# iorx71m register map
Registers from a debugger description file.
Registers are 8-bit, access not given, no defined reset value unless marked. A register's access mark holds for its fields unless they carry their own. Addresses are absolute; registers are grouped by the start of their names; lines under a group give offsets from that group; [hi:lo] are bit positions; {n}, {i} and the like mark numbered series; 'fields as' and 'values as' point back to an identical list; <NAME> marks a mode.

## SFR (part 1 of 4)
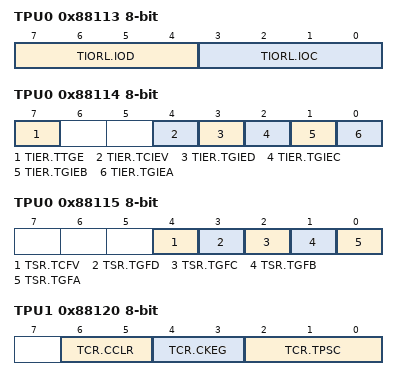
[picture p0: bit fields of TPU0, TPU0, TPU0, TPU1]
0x88113 TPU0
  [7:4] TIORL.IOD, [3:0] TIORL.IOC
0x88114 TPU0
  [7] TIER.TTGE, [4] TIER.TCIEV, [3] TIER.TGIED, [2] TIER.TGIEC, [1] TIER.TGIEB, [0] TIER.TGIEA
0x88115 TPU0
  [4] TSR.TCFV, [3] TSR.TGFD, [2] TSR.TGFC, [1] TSR.TGFB, [0] TSR.TGFA
0x88120 TPU1
  [6:5] TCR.CCLR, [4:3] TCR.CKEG, [2:0] TCR.TPSC
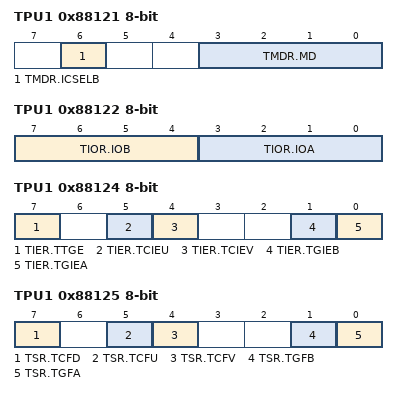
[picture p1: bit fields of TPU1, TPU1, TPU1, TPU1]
0x88121 TPU1
  [6] TMDR.ICSELB, [3:0] TMDR.MD
0x88122 TPU1
  [7:4] TIOR.IOB, [3:0] TIOR.IOA
0x88124 TPU1
  [7] TIER.TTGE, [5] TIER.TCIEU, [4] TIER.TCIEV, [1] TIER.TGIEB, [0] TIER.TGIEA
0x88125 TPU1
  [7] TSR.TCFD, [5] TSR.TCFU, [4] TSR.TCFV, [1] TSR.TGFB, [0] TSR.TGFA
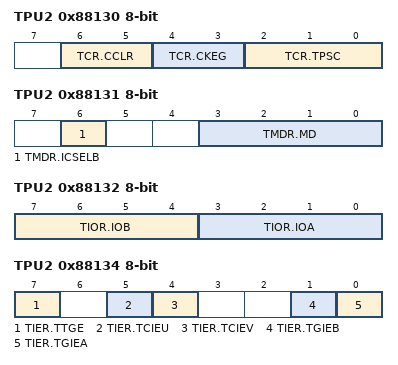
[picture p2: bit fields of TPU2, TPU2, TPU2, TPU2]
0x88130 TPU2
  [6:5] TCR.CCLR, [4:3] TCR.CKEG, [2:0] TCR.TPSC
0x88131 TPU2
  [6] TMDR.ICSELB, [3:0] TMDR.MD
0x88132 TPU2
  [7:4] TIOR.IOB, [3:0] TIOR.IOA
0x88134 TPU2
  [7] TIER.TTGE, [5] TIER.TCIEU, [4] TIER.TCIEV, [1] TIER.TGIEB, [0] TIER.TGIEA
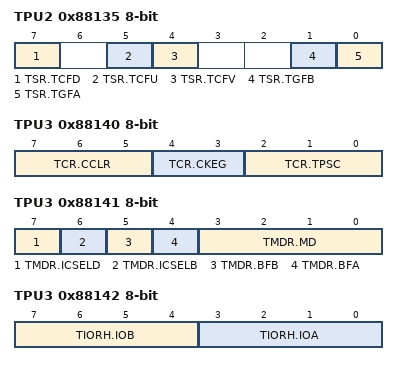
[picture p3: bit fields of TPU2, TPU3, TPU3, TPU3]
0x88135 TPU2
  [7] TSR.TCFD, [5] TSR.TCFU, [4] TSR.TCFV, [1] TSR.TGFB, [0] TSR.TGFA
0x88140 TPU3
  [7:5] TCR.CCLR, [4:3] TCR.CKEG, [2:0] TCR.TPSC
0x88141 TPU3
  [7] TMDR.ICSELD, [6] TMDR.ICSELB, [5] TMDR.BFB, [4] TMDR.BFA, [3:0] TMDR.MD
0x88142 TPU3
  [7:4] TIORH.IOB, [3:0] TIORH.IOA
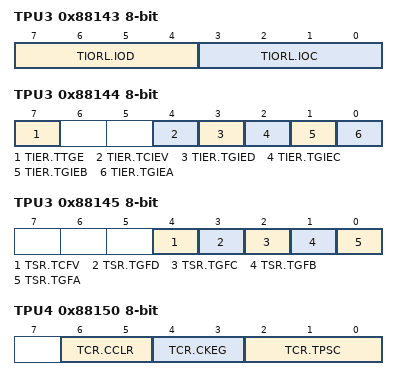
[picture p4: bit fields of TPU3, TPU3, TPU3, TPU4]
0x88143 TPU3
  [7:4] TIORL.IOD, [3:0] TIORL.IOC
0x88144 TPU3
  [7] TIER.TTGE, [4] TIER.TCIEV, [3] TIER.TGIED, [2] TIER.TGIEC, [1] TIER.TGIEB, [0] TIER.TGIEA
0x88145 TPU3
  [4] TSR.TCFV, [3] TSR.TGFD, [2] TSR.TGFC, [1] TSR.TGFB, [0] TSR.TGFA
0x88150 TPU4
  [6:5] TCR.CCLR, [4:3] TCR.CKEG, [2:0] TCR.TPSC
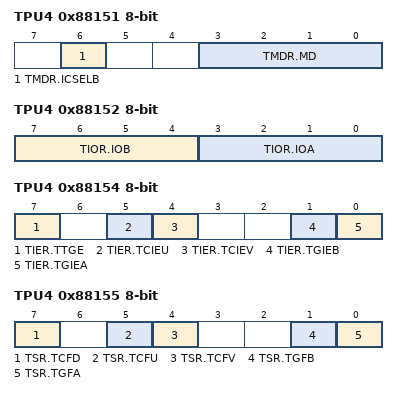
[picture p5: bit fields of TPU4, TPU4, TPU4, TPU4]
0x88151 TPU4
  [6] TMDR.ICSELB, [3:0] TMDR.MD
0x88152 TPU4
  [7:4] TIOR.IOB, [3:0] TIOR.IOA
0x88154 TPU4
  [7] TIER.TTGE, [5] TIER.TCIEU, [4] TIER.TCIEV, [1] TIER.TGIEB, [0] TIER.TGIEA
0x88155 TPU4
  [7] TSR.TCFD, [5] TSR.TCFU, [4] TSR.TCFV, [1] TSR.TGFB, [0] TSR.TGFA
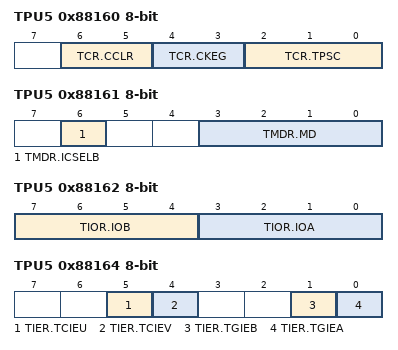
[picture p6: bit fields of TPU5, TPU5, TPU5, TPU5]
0x88160 TPU5
  [6:5] TCR.CCLR, [4:3] TCR.CKEG, [2:0] TCR.TPSC
0x88161 TPU5
  [6] TMDR.ICSELB, [3:0] TMDR.MD
0x88162 TPU5
  [7:4] TIOR.IOB, [3:0] TIOR.IOA
0x88164 TPU5
  [5] TIER.TCIEU, [4] TIER.TCIEV, [1] TIER.TGIEB, [0] TIER.TGIEA
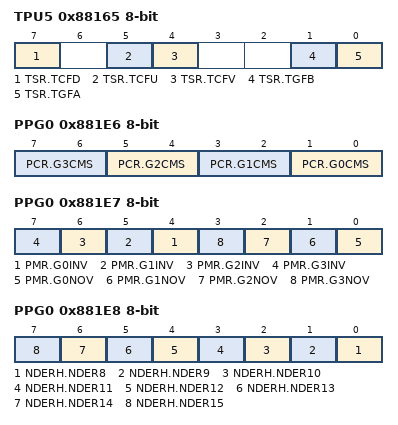
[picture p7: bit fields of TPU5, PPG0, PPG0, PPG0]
0x88165 TPU5
  [7] TSR.TCFD, [5] TSR.TCFU, [4] TSR.TCFV, [1] TSR.TGFB, [0] TSR.TGFA
0x881E6 PPG0
  [2n+1:2n] PCR.G{n}CMS (n=0..3)
0x881E7 PPG0
  [n+4] PMR.G{n}INV (n=0..3), [n] PMR.G{n}NOV (n=0..3)
0x881E8 PPG0
  [n-8] NDERH.NDER{n} (n=8..15)
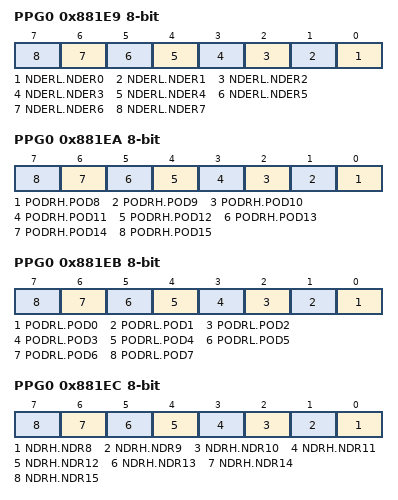
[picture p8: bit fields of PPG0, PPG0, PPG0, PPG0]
0x881E9 PPG0
  [n] NDERL.NDER{n} (n=0..7)
0x881EA PPG0
  [n-8] PODRH.POD{n} (n=8..15)
0x881EB PPG0
  [n] PODRL.POD{n} (n=0..7)
0x881EC PPG0
  [n-8] NDRH.NDR{n} (n=8..15)
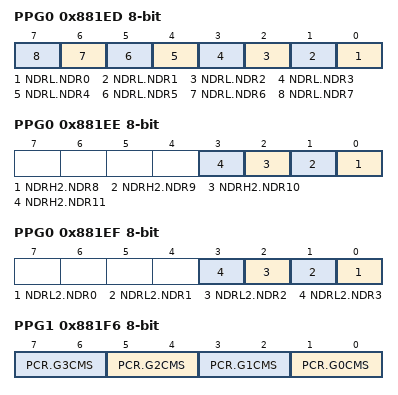
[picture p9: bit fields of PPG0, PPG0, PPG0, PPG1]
0x881ED PPG0
  [n] NDRL.NDR{n} (n=0..7)
0x881EE PPG0
  [n-8] NDRH2.NDR{n} (n=8..11)
0x881EF PPG0
  [n] NDRL2.NDR{n} (n=0..3)
0x881F0 PPG1
  [0] PTRSLR.PTRSL
0x881F6 PPG1
  [2n+1:2n] PCR.G{n}CMS (n=0..3)
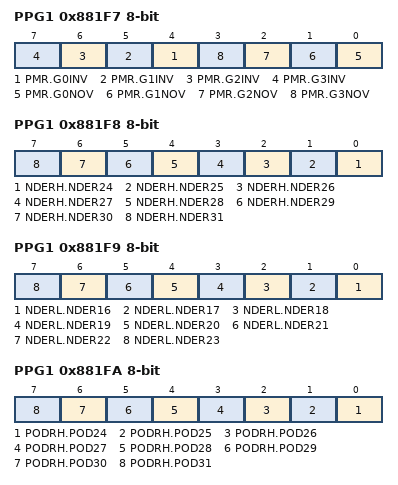
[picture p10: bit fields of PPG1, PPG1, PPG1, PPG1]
0x881F7 PPG1
  [n+4] PMR.G{n}INV (n=0..3), [n] PMR.G{n}NOV (n=0..3)
0x881F8 PPG1
  [n-24] NDERH.NDER{n} (n=24..31)
0x881F9 PPG1
  [n-16] NDERL.NDER{n} (n=16..23)
0x881FA PPG1
  [n-24] PODRH.POD{n} (n=24..31)
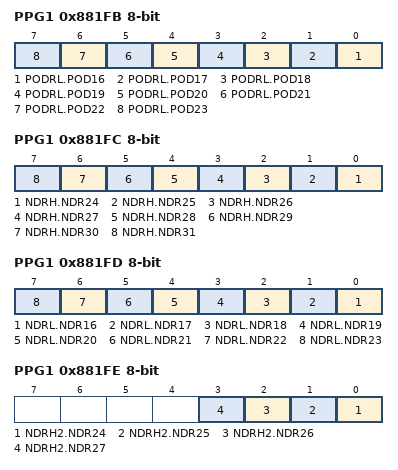
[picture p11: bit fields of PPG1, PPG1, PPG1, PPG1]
0x881FB PPG1
  [n-16] PODRL.POD{n} (n=16..23)
0x881FC PPG1
  [n-24] NDRH.NDR{n} (n=24..31)
0x881FD PPG1
  [n-16] NDRL.NDR{n} (n=16..23)
0x881FE PPG1
  [n-24] NDRH2.NDR{n} (n=24..27)
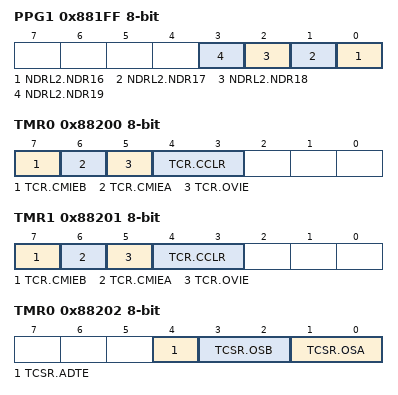
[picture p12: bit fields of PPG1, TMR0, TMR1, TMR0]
0x881FF PPG1
  [n-16] NDRL2.NDR{n} (n=16..19)
0x88200 TMR0
  [7] TCR.CMIEB, [6] TCR.CMIEA, [5] TCR.OVIE, [4:3] TCR.CCLR
0x88201 TMR1
  [7] TCR.CMIEB, [6] TCR.CMIEA, [5] TCR.OVIE, [4:3] TCR.CCLR
0x88202 TMR0
  [4] TCSR.ADTE, [3:2] TCSR.OSB, [1:0] TCSR.OSA
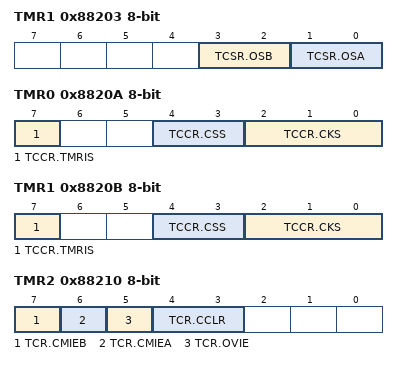
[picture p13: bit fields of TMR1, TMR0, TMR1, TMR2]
0x88203 TMR1
  [3:2] TCSR.OSB, [1:0] TCSR.OSA
0x8820A TMR0
  [7] TCCR.TMRIS, [4:3] TCCR.CSS, [2:0] TCCR.CKS
0x8820B TMR1
  [7] TCCR.TMRIS, [4:3] TCCR.CSS, [2:0] TCCR.CKS
0x8820C TMR0
  [0] TCSTR.TCS
0x8820D TMR1
  [0] TCSTR.TCS
0x88210 TMR2
  [7] TCR.CMIEB, [6] TCR.CMIEA, [5] TCR.OVIE, [4:3] TCR.CCLR
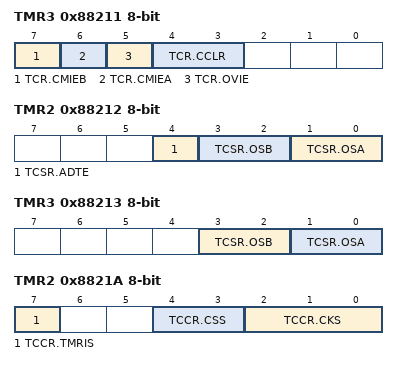
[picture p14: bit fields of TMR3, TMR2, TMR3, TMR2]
0x88211 TMR3
  [7] TCR.CMIEB, [6] TCR.CMIEA, [5] TCR.OVIE, [4:3] TCR.CCLR
0x88212 TMR2
  [4] TCSR.ADTE, [3:2] TCSR.OSB, [1:0] TCSR.OSA
0x88213 TMR3
  [3:2] TCSR.OSB, [1:0] TCSR.OSA
0x8821A TMR2
  [7] TCCR.TMRIS, [4:3] TCCR.CSS, [2:0] TCCR.CKS
0x8821B TMR3
  [7] TCCR.TMRIS, [4:3] TCCR.CSS, [2:0] TCCR.CKS
0x8821C TMR2
  [0] TCSTR.TCS
0x8821D TMR3
  [0] TCSTR.TCS
0x88280 CRC
  [7] CRCCR.DORCLR, [2] CRCCR.LMS, [1:0] CRCCR.GPS
0x88300 RIIC0
  [7] ICCR1.ICE, [6] ICCR1.IICRST, [5] ICCR1.CLO, [4] ICCR1.SOWP, [3] ICCR1.SCLO, [2] ICCR1.SDAO, [1] ICCR1.SCLI, [0] ICCR1.SDAI
0x88301 RIIC0
  [7] ICCR2.BBSY, [6] ICCR2.MST, [5] ICCR2.TRS, [3] ICCR2.SP, [2] ICCR2.RS, [1] ICCR2.ST
0x88302 RIIC0
  [7] ICMR1.MTWP, [6:4] ICMR1.CKS, [3] ICMR1.BCWP, [2:0] ICMR1.BC
0x88303 RIIC0
  [7] ICMR2.DLCS, [6:4] ICMR2.SDDL, [2] ICMR2.TMOH, [1] ICMR2.TMOL, [0] ICMR2.TMOS
0x88304 RIIC0
  [7] ICMR3.SMBS, [6] ICMR3.WAIT, [5] ICMR3.RDRFS, [4] ICMR3.ACKWP, [3] ICMR3.ACKBT, [2] ICMR3.ACKBR, [1:0] ICMR3.NF
0x88305 RIIC0
  [7] ICFER.FMPE, [6] ICFER.SCLE, [5] ICFER.NFE, [4] ICFER.NACKE, [3] ICFER.SALE, [2] ICFER.NALE, [1] ICFER.MALE, [0] ICFER.TMOE
0x88306 RIIC0
  [7] ICSER.HOAE, [5] ICSER.DIDE, [3] ICSER.GCAE, [2] ICSER.SAR2E, [1] ICSER.SAR1E, [0] ICSER.SAR0E
0x88307 RIIC0
  [7] ICIER.TIE, [6] ICIER.TEIE, [5] ICIER.RIE, [4] ICIER.NAKIE, [3] ICIER.SPIE, [2] ICIER.STIE, [1] ICIER.ALIE, [0] ICIER.TMOIE
0x88308 RIIC0
  [7] ICSR1.HOA, [5] ICSR1.DID, [3] ICSR1.GCA, [2] ICSR1.AAS2, [1] ICSR1.AAS1, [0] ICSR1.AAS0
0x88309 RIIC0
  [7] ICSR2.TDRE, [6] ICSR2.TEND, [5] ICSR2.RDRF, [4] ICSR2.NACKF, [3] ICSR2.STOP, [2] ICSR2.START, [1] ICSR2.AL, [0] ICSR2.TMOF
0x8830A RIIC0
  [7:1] SARL0.SVA, [0] SARL0.SVA0
0x8830B RIIC0
  [2:1] SARU0.SVA, [0] SARU0.FS
0x8830C RIIC0
  [7:1] SARL1.SVA, [0] SARL1.SVA0
0x8830D RIIC0
  [2:1] SARU1.SVA, [0] SARU1.FS
0x8830E RIIC0
  [7:1] SARL2.SVA, [0] SARL2.SVA0
0x8830F RIIC0
  [2:1] SARU2.SVA, [0] SARU2.FS
0x88310 RIIC0
  [4:0] ICBRL.BRL
0x88311 RIIC0
  [4:0] ICBRH.BRH
0x88340 RIIC2
  fields as RIIC0
0x88341 RIIC2
  [7] ICCR2.BBSY, [6] ICCR2.MST, [5] ICCR2.TRS, [3] ICCR2.SP, [2] ICCR2.RS, [1] ICCR2.ST
0x88342 RIIC2
  [7] ICMR1.MTWP, [6:4] ICMR1.CKS, [3] ICMR1.BCWP, [2:0] ICMR1.BC
0x88343 RIIC2
  [7] ICMR2.DLCS, [6:4] ICMR2.SDDL, [2] ICMR2.TMOH, [1] ICMR2.TMOL, [0] ICMR2.TMOS
0x88344 RIIC2
  [7] ICMR3.SMBS, [6] ICMR3.WAIT, [5] ICMR3.RDRFS, [4] ICMR3.ACKWP, [3] ICMR3.ACKBT, [2] ICMR3.ACKBR, [1:0] ICMR3.NF
0x88345 RIIC2
  [7] ICFER.FMPE, [6] ICFER.SCLE, [5] ICFER.NFE, [4] ICFER.NACKE, [3] ICFER.SALE, [2] ICFER.NALE, [1] ICFER.MALE, [0] ICFER.TMOE
0x88346 RIIC2
  [7] ICSER.HOAE, [5] ICSER.DIDE, [3] ICSER.GCAE, [2] ICSER.SAR2E, [1] ICSER.SAR1E, [0] ICSER.SAR0E
0x88347 RIIC2
  [7] ICIER.TIE, [6] ICIER.TEIE, [5] ICIER.RIE, [4] ICIER.NAKIE, [3] ICIER.SPIE, [2] ICIER.STIE, [1] ICIER.ALIE, [0] ICIER.TMOIE
0x88348 RIIC2
  [7] ICSR1.HOA, [5] ICSR1.DID, [3] ICSR1.GCA, [2] ICSR1.AAS2, [1] ICSR1.AAS1, [0] ICSR1.AAS0
0x88349 RIIC2
  [7] ICSR2.TDRE, [6] ICSR2.TEND, [5] ICSR2.RDRF, [4] ICSR2.NACKF, [3] ICSR2.STOP, [2] ICSR2.START, [1] ICSR2.AL, [0] ICSR2.TMOF
0x8834A RIIC2
  [7:1] SARL0.SVA, [0] SARL0.SVA0
0x8834B RIIC2
  [2:1] SARU0.SVA, [0] SARU0.FS
0x8834C RIIC2
  [7:1] SARL1.SVA, [0] SARL1.SVA0
0x8834D RIIC2
  [2:1] SARU1.SVA, [0] SARU1.FS
0x8834E RIIC2
  [7:1] SARL2.SVA, [0] SARL2.SVA0
0x8834F RIIC2
  [2:1] SARU2.SVA, [0] SARU2.FS
0x88350 RIIC2
  [4:0] ICBRL.BRL
0x88351 RIIC2
  [4:0] ICBRH.BRH
0x88500 MMCIF 32-bit
  [30] CECMDSET.BOOT, [29:24] CECMDSET.CMD, [23:22] CECMDSET.RTYP, [21] CECMDSET.RBSY, [19] CECMDSET.WDAT, [18] CECMDSET.DWEN, [17] CECMDSET.CMLTE, [16] CECMDSET.CMD12EN, [15:14] CECMDSET.RIDXC, [13:12] CECMDSET.RCRC7C, [10] CECMDSET.CRC16C, [9] CECMDSET.BOOTACK, [8] CECMDSET.CRCSTE, [7] CECMDSET.TBIT, [6] CECMDSET.OPDM, [3] CECMDSET.SBIT, [1:0] CECMDSET.DATW
0x88508 MMCIF 32-bit
  [31:0] CEARG.ARG
0x8850C MMCIF 32-bit
  [31:0] CEARGCMD12.C12ARG
0x88510 MMCIF 32-bit
  [0] CECMDCTRL.BREAK
0x88514 MMCIF 32-bit
  [31:16] CEBLOCKSET.BLKCNT, [15:0] CEBLOCKSET.BLKSIZ
0x88518 MMCIF 32-bit
  [31] CECLKCTRL.MMCBUSBSY, [24] CECLKCTRL.CLKEN, [19:16] CECLKCTRL.CLKDIV, [13:12] CECLKCTRL.SRSPTO, [11:8] CECLKCTRL.SRBSYTO, [7:4] CECLKCTRL.SRWDTO
0x8851C MMCIF 32-bit
  [26] CEBUFACC.DMATYP, [25] CEBUFACC.DMAWEN, [24] CEBUFACC.DMAREN, [16] CEBUFACC.ATYP
0x88530 MMCIF 32-bit
  [31:0] CERESPCMD12.RSP12
0x88534 MMCIF 32-bit
  [31:0] CEDATA.DATA
0x8853C MMCIF 32-bit
  [31:28] CEBOOT.SBTCLKDIV, [27:24] CEBOOT.SBTACKTO, [23:20] CEBOOT.SFSTBTDATTO, [19:16] CEBOOT.SBTDATTO
0x88540 MMCIF 32-bit
  [26] CEINT.CMD12DRE, [25] CEINT.CMD12RBE, [24] CEINT.CMD12CRE, [23] CEINT.DTRANE, [22] CEINT.BUFRE, [21] CEINT.BUFWEN, [20] CEINT.BUFREN, [17] CEINT.RBSYE, [16] CEINT.CRSPE, [15] CEINT.CMDVIO, [14] CEINT.BUFVIO, [11] CEINT.WDATERR, [10] CEINT.RDATERR, [9] CEINT.RIDXERR, [8] CEINT.RSPERR, [4] CEINT.CRCSTO, [3] CEINT.WDATTO, [2] CEINT.RDATTO, [1] CEINT.RBSYTO, [0] CEINT.RSPTO
0x88544 MMCIF 32-bit
  [26] CEINTEN.MCMD12DRE, [25] CEINTEN.MCMD12RBE, [24] CEINTEN.MCMD12CRE, [23] CEINTEN.MDTRANE, [22] CEINTEN.MBUFRE, [21] CEINTEN.MBUFWEN, [20] CEINTEN.MBUFREN, [17] CEINTEN.MRBSYE, [16] CEINTEN.MCRSPE, [15] CEINTEN.MCMDVIO, [14] CEINTEN.MBUFVIO, [11] CEINTEN.MWDATERR, [10] CEINTEN.MRDATERR, [9] CEINTEN.MRIDXERR, [8] CEINTEN.MRSPERR, [4] CEINTEN.MCRCSTO, [3] CEINTEN.MWDATTO, [2] CEINTEN.MRDATTO, [1] CEINTEN.MRBSYTO, [0] CEINTEN.MRSPTO
0x88548 MMCIF 32-bit
  [31] CEHOSTSTS1.CMDSEQ, [30] CEHOSTSTS1.CMDSIG, [29:24] CEHOSTSTS1.RSPIDX, [23:16] CEHOSTSTS1.DATSIG, [15:0] CEHOSTSTS1.RCVBLK
0x8854C MMCIF 32-bit
  [31] CEHOSTSTS2.CRCSTE, [30] CEHOSTSTS2.CRC16E, [29] CEHOSTSTS2.AC12CRCE, [28] CEHOSTSTS2.RSPCRC7E, [27] CEHOSTSTS2.CRCSTEBE, [26] CEHOSTSTS2.RDATEBE, [25] CEHOSTSTS2.AC12REBE, [24] CEHOSTSTS2.RSPEBE, [23] CEHOSTSTS2.AC12IDXE, [22] CEHOSTSTS2.RSPIDXE, [21] CEHOSTSTS2.BTACKPATE, [20] CEHOSTSTS2.BTACKEBE, [18:16] CEHOSTSTS2.CRCST, [14] CEHOSTSTS2.STRDATTO, [13] CEHOSTSTS2.DATBSYTO, [12] CEHOSTSTS2.CRCSTTO, [11] CEHOSTSTS2.AC12BSYTO, [10] CEHOSTSTS2.RSPBSYTO, [9] CEHOSTSTS2.AC12RSPTO, [8] CEHOSTSTS2.STRSPTO, [7] CEHOSTSTS2.BTACKTO, [6] CEHOSTSTS2.FSTBTDATTO, [5] CEHOSTSTS2.BTDATTO
0x88570 MMCIF 32-bit
  [14] CEDETECT.CDSIG, [13] CEDETECT.CDRISE, [12] CEDETECT.CDFALL, [5] CEDETECT.MCDRISE, [4] CEDETECT.MCDFALL
0x88574 MMCIF 32-bit
  [21] CEADDMODE.RESNOUT, [19] CEADDMODE.CLKMAIN
0x8857C MMCIF 32-bit
  [31] CEVERSION.SWRST, [15:0] CEVERSION.VERSION
0x89000 S12AD 16-bit
  [15] ADCSR.ADST, [14:13] ADCSR.ADCS, [12] ADCSR.ADIE, [9] ADCSR.TRGE, [8] ADCSR.EXTRG, [7] ADCSR.DBLE, [6] ADCSR.GBADIE, [4:0] ADCSR.DBLANS
0x89004 S12AD 16-bit
  [15:0] ADANSA0.ANSA0
0x89008 S12AD 16-bit
  [15:0] ADADS0.ADS0
0x8900C S12AD
  [7] ADADC.AVEE, [1:0] ADADC.ADC
0x8900E S12AD 16-bit
  [15] ADCER.ADRFMT, [11] ADCER.DIAGM, [10] ADCER.DIAGLD, [9:8] ADCER.DIAGVAL, [5] ADCER.ACE, [2:1] ADCER.ADPRC
0x89010 S12AD 16-bit
  [13:8] ADSTRGR.TRSA, [5:0] ADSTRGR.TRSB
0x89014 S12AD 16-bit
  [15:0] ADANSB0.ANSB0
0x89018 S12AD 16-bit
  [13:2] ADDBLDR.AD
0x8901E S12AD 16-bit
  [15:14] ADRD.RIGHT.DIAGST, [15:4] ADRD.LEFT.AD, [11:0] ADRD.RIGHT.AD, [1:0] ADRD.LEFT.DIAGST
0x89066 S12AD 16-bit
  [10:8] ADSHCR.SHANS, [7:0] ADSHCR.SSTSH
0x8907A S12AD
  [4:0] ADDISCR.ADNDIS
0x8907C S12AD
  [0] ADSHMSR.SHMD
0x89080 S12AD 16-bit
  [15] ADGSPCR.GBRP, [1] ADGSPCR.GBRSCN, [0] ADGSPCR.PGS
0x89090 S12AD
  [7] ADCMPCR.CMPIE, [6] ADCMPCR.WCMPE
0x89094 S12AD 16-bit
  [15:0] ADCMPANSR0.CMPS0
0x89098 S12AD 16-bit
  [15:0] ADCMPLR0.CMPL0
0x890A0 S12AD 16-bit
  [15:0] ADCMPSR0.CMPF0
0x89100 S12AD1 16-bit
  fields as S12AD
0x89104 S12AD1 16-bit
  [15:0] ADANSA0.ANSA0
0x89106 S12AD1 16-bit
  [4:0] ADANSA1.ANSA1
0x89108 S12AD1 16-bit
  [15:0] ADADS0.ADS0
0x8910A S12AD1 16-bit
  [4:0] ADADS1.ADS1
0x8910C S12AD1
  [7] ADADC.AVEE, [1:0] ADADC.ADC
0x8910E S12AD1 16-bit
  [15] ADCER.ADRFMT, [11] ADCER.DIAGM, [10] ADCER.DIAGLD, [9:8] ADCER.DIAGVAL, [5] ADCER.ACE, [2:1] ADCER.ADPRC
0x89110 S12AD1 16-bit
  [13:8] ADSTRGR.TRSA, [5:0] ADSTRGR.TRSB
0x89112 S12AD1 16-bit
  [15] ADEXICR.EXOEN, [14:13] ADEXICR.EXSEL, [11] ADEXICR.OCSB, [10] ADEXICR.TSSB, [9] ADEXICR.OCSA, [8] ADEXICR.TSSA, [1] ADEXICR.OCSAD, [0] ADEXICR.TSSAD
0x89114 S12AD1 16-bit
  [15:0] ADANSB0.ANSB0
0x89116 S12AD1 16-bit
  [4:0] ADANSB1.ANSB1
0x8911E S12AD1 16-bit
  [15:14] ADRD.RIGHT.DIAGST, [15:4] ADRD.LEFT.AD, [11:0] ADRD.RIGHT.AD, [1:0] ADRD.LEFT.DIAGST
0x8917A S12AD1
  [4:0] ADDISCR.ADNDIS
0x89180 S12AD1 16-bit
  [15] ADGSPCR.GBRP, [1] ADGSPCR.GBRSCN, [0] ADGSPCR.PGS
0x89190 S12AD1
  [7] ADCMPCR.CMPIE, [6] ADCMPCR.WCMPE
0x89192 S12AD1
  [1] ADCMPANSER.CMPSOC, [0] ADCMPANSER.CMPSTS
0x89193 S12AD1
  [1] ADCMPLER.CMPLOC, [0] ADCMPLER.CMPLTS
0x89194 S12AD1 16-bit
  [15:0] ADCMPANSR0.CMPS0
0x89196 S12AD1 16-bit
  [4:0] ADCMPANSR1.CMPS1
0x89198 S12AD1 16-bit
  [15:0] ADCMPLR0.CMPL0
0x8919A S12AD1 16-bit
  [4:0] ADCMPLR1.CMPL1
0x891A0 S12AD1 16-bit
  [15:0] ADCMPSR0.CMPF0
0x891A2 S12AD1 16-bit
  [4:0] ADCMPSR1.CMPF1
0x891A4 S12AD1
  [1] ADCMPSER.CMPFOC, [0] ADCMPSER.CMPFTS
0x89E00 QSPI
  [7] SPCR.SPRIE, [6] SPCR.SPE, [5] SPCR.SPTIE, [3] SPCR.MSTR, [1] SPCR.SPSSLIE
0x89E01 QSPI
  [0] SSLP.SSLP
0x89E02 QSPI
  [5] SPPCR.MOIFE, [4] SPPCR.MOIFV, [2] SPPCR.IO3FV, [1] SPPCR.IO2FV, [0] SPPCR.SPLP
0x89E03 QSPI
  [7] SPSR.SPRFF, [6] SPSR.TREND, [5] SPSR.SPTEF, [4] SPSR.SPSSLF
0x89E08 QSPI
  [1:0] SPSCR.SPSC
0x89E09 QSPI
  [1:0] SPSSR.SPSS
0x89E0A QSPI
  [n] SPBR.SPBR{n} (n=0..7)
0x89E0B QSPI
  [7] SPDCR.TXDMY
0x89E0C QSPI
  [2:0] SPCKD.SCKDL
0x89E0D QSPI
  [2:0] SSLND.SLNDL
0x89E0E QSPI
  [2:0] SPND.SPNDL
0x89E10 QSPI 16-bit
  [15] SPCMD0.SCKDEN, [14] SPCMD0.SLNDEN, [13] SPCMD0.SPNDEN, [12] SPCMD0.LSBF, [11:8] SPCMD0.SPB, [7] SPCMD0.SSLKP, [6:5] SPCMD0.SPIMOD, [4] SPCMD0.SPRW, [3:2] SPCMD0.BRDV, [1] SPCMD0.CPOL, [0] SPCMD0.CPHA
0x89E12 QSPI 16-bit
  [15] SPCMD1.SCKDEN, [14] SPCMD1.SLNDEN, [13] SPCMD1.SPNDEN, [12] SPCMD1.LSBF, [11:8] SPCMD1.SPB, [7] SPCMD1.SSLKP, [6:5] SPCMD1.SPIMOD, [4] SPCMD1.SPRW, [3:2] SPCMD1.BRDV, [1] SPCMD1.CPOL, [0] SPCMD1.CPHA
0x89E14 QSPI 16-bit
  [15] SPCMD2.SCKDEN, [14] SPCMD2.SLNDEN, [13] SPCMD2.SPNDEN, [12] SPCMD2.LSBF, [11:8] SPCMD2.SPB, [7] SPCMD2.SSLKP, [6:5] SPCMD2.SPIMOD, [4] SPCMD2.SPRW, [3:2] SPCMD2.BRDV, [1] SPCMD2.CPOL, [0] SPCMD2.CPHA
0x89E16 QSPI 16-bit
  [15] SPCMD3.SCKDEN, [14] SPCMD3.SLNDEN, [13] SPCMD3.SPNDEN, [12] SPCMD3.LSBF, [11:8] SPCMD3.SPB, [7] SPCMD3.SSLKP, [6:5] SPCMD3.SPIMOD, [4] SPCMD3.SPRW, [3:2] SPCMD3.BRDV, [1] SPCMD3.CPOL, [0] SPCMD3.CPHA
0x89E18 QSPI
  [7] SPBFCR.TXRST, [6] SPBFCR.RXRST, [5:4] SPBFCR.TXTRG, [3] SPBFCR.TXTRGEX, [2:0] SPBFCR.RXTRG
0x89E1A QSPI 16-bit
  [13:8] SPBDCR.TXBC, [5:0] SPBDCR.RXBC
{0x8A000+0x20*i} SCI{i} (i=0..7)
  [7] SMR.CM, [6] SMR.CHR, [5] SMR.PE, [4] SMR.PM, [3] SMR.STOP, [2] SMR.MP, [1:0] SMR.CKS
{0x8A000+0x20*i} SMCI{i} (i=0..7)
  [7] SMR.GM, [6] SMR.BLK, [5] SMR.PE, [4] SMR.PM, [3:2] SMR.BCP, [1:0] SMR.CKS
{0x8A002+0x20*i} SCI{i} (i=0..7)
  [7] SCR.TIE, [6] SCR.RIE, [5] SCR.TE, [4] SCR.RE, [3] SCR.MPIE, [2] SCR.TEIE, [1:0] SCR.CKE
{0x8A002+0x20*i} SMCI{i} (i=0..7)
  [7] SCR.TIE, [6] SCR.RIE, [5] SCR.TE, [4] SCR.RE, [3] SCR.MPIE, [2] SCR.TEIE, [1:0] SCR.CKE
{0x8A004+0x20*i} SCI{i} (i=0..7)
  [7] SSR.TDRE, [6] SSR.RDRF, [5] SSR.ORER, [4] SSR.FER, [3] SSR.PER, [2] SSR.TEND, [1] SSR.MPB, [0] SSR.MPBT
{0x8A004+0x20*i} SMCI{i} (i=0..7)
  [7] SSR.TDRE, [6] SSR.RDRF, [5] SSR.ORER, [4] SSR.ERS, [3] SSR.PER, [2] SSR.TEND, [1] SSR.MPB, [0] SSR.MPBT
{0x8A006+0x20*i} SCI{i} (i=0..7)
  [7] SCMR.BCP2, [4] SCMR.CHR1, [3] SCMR.SDIR, [2] SCMR.SINV, [0] SCMR.SMIF
{0x8A006+0x20*i} SMCI{i} (i=0..7)
  [7] SCMR.BCP2, [4] SCMR.CHR1, [3] SCMR.SDIR, [2] SCMR.SINV, [0] SCMR.SMIF
{0x8A007+0x20*i} SCI{i} (i=0..7)
  [7] SEMR.RXDESEL, [6] SEMR.BGDM, [5] SEMR.NFEN, [4] SEMR.ABCS, [2] SEMR.BRME, [0] SEMR.ACS0
{0x8A008+0x20*i} SCI{i} (i=0..7)
  [2:0] SNFR.NFCS
{0x8A009+0x20*i} SCI{i} (i=0..7)
  [7:3] SIMR1.IICDL, [0] SIMR1.IICM
{0x8A00A+0x20*i} SCI{i} (i=0..7)
  [5] SIMR2.IICACKT, [1] SIMR2.IICCSC, [0] SIMR2.IICINTM
{0x8A00B+0x20*i} SCI{i} (i=0..7)
  [7:6] SIMR3.IICSCLS, [5:4] SIMR3.IICSDAS, [3] SIMR3.IICSTIF, [2] SIMR3.IICSTPREQ, [1] SIMR3.IICRSTAREQ, [0] SIMR3.IICSTAREQ
{0x8A00C+0x20*i} SCI{i} (i=0..7)
  [0] SISR.IICACKR
{0x8A00D+0x20*i} SCI{i} (i=0..7)
  [7] SPMR.CKPH, [6] SPMR.CKPOL, [4] SPMR.MFF, [2] SPMR.MSS, [1] SPMR.CTSE, [0] SPMR.SSE
0x8A500 SSI0 32-bit
  [30] SSICR.CKS, [29] SSICR.TUIEN, [28] SSICR.TOIEN, [27] SSICR.RUIEN, [26] SSICR.ROIEN, [25] SSICR.IIEN, [23:22] SSICR.CHNL, [21:19] SSICR.DWL, [18:16] SSICR.SWL, [15] SSICR.SCKD, [14] SSICR.SWSD, [13] SSICR.SCKP, [12] SSICR.SWSP, [11] SSICR.SPDP, [10] SSICR.SDTA, [9] SSICR.PDTA, [8] SSICR.DEL, [7:4] SSICR.CKDV, [3] SSICR.MUEN, [1] SSICR.TEN, [0] SSICR.REN
0x8A504 SSI0 32-bit
  [29] SSISR.TUIRQ, [28] SSISR.TOIRQ, [27] SSISR.RUIRQ, [26] SSISR.ROIRQ, [25] SSISR.IIRQ, [6:5] SSISR.TCHNO, [4] SSISR.TSWNO, [3:2] SSISR.RCHNO, [1] SSISR.RSWNO, [0] SSISR.IDST
0x8A510 SSI0 32-bit
  [31] SSIFCR.AUCKE, [16] SSIFCR.SSIRST, [7:6] SSIFCR.TTRG, [5:4] SSIFCR.RTRG, [3] SSIFCR.TIE, [2] SSIFCR.RIE, [1] SSIFCR.TFRST, [0] SSIFCR.RFRST
0x8A514 SSI0 32-bit
  [27:24] SSIFSR.TDC, [16] SSIFSR.TDE, [11:8] SSIFSR.RDC, [0] SSIFSR.RDF
0x8A520 SSI0 32-bit
  [8] SSITDMR.CONT
0x8A540 SSI1 32-bit
  fields as SSI0
0x8A544 SSI1 32-bit
  [29] SSISR.TUIRQ, [28] SSISR.TOIRQ, [27] SSISR.RUIRQ, [26] SSISR.ROIRQ, [25] SSISR.IIRQ, [6:5] SSISR.TCHNO, [4] SSISR.TSWNO, [3:2] SSISR.RCHNO, [1] SSISR.RSWNO, [0] SSISR.IDST
0x8A550 SSI1 32-bit
  [31] SSIFCR.AUCKE, [16] SSIFCR.SSIRST, [7:6] SSIFCR.TTRG, [5:4] SSIFCR.RTRG, [3] SSIFCR.TIE, [2] SSIFCR.RIE, [1] SSIFCR.TFRST, [0] SSIFCR.RFRST
0x8A554 SSI1 32-bit
  [27:24] SSIFSR.TDC, [16] SSIFSR.TDE, [11:8] SSIFSR.RDC, [0] SSIFSR.RDF
0x8A560 SSI1 32-bit
  [8] SSITDMR.CONT
0x8AC00 SDHI 32-bit
  [15:14] SDCMD.CMD12AT, [13] SDCMD.TRSTP, [12] SDCMD.CMDRW, [11] SDCMD.CMDTP, [10:8] SDCMD.RSPTP, [7:6] SDCMD.ACMD, [5:0] SDCMD.CMDIDX
0x8AC10 SDHI 32-bit
  [8] SDSTOP.SDBLKCNTEN, [0] SDSTOP.STP
0x8AC38 SDHI 32-bit
  [10] SDSTS1.SDD3MON, [9] SDSTS1.SDD3IN, [8] SDSTS1.SDD3RM, [7] SDSTS1.SDWPMON, [5] SDSTS1.SDCDMON, [4] SDSTS1.SDCDIN, [3] SDSTS1.SDCDRM, [2] SDSTS1.ACEND, [0] SDSTS1.RSPEND
0x8AC3C SDHI 32-bit
  [15] SDSTS2.ILA, [14] SDSTS2.CBSY, [13] SDSTS2.SDCLKCREN, [9] SDSTS2.BWE, [8] SDSTS2.BRE, [7] SDSTS2.SDD0MON, [6] SDSTS2.RSPTO, [5] SDSTS2.ILR, [4] SDSTS2.ILW, [3] SDSTS2.DTO, [2] SDSTS2.ENDE, [1] SDSTS2.CRCE, [0] SDSTS2.CMDE
0x8AC40 SDHI 32-bit
  [9] SDIMSK1.SDD3INM, [8] SDIMSK1.SDD3RMM, [4] SDIMSK1.SDCDINM, [3] SDIMSK1.SDCDRMM, [2] SDIMSK1.ACENDM, [0] SDIMSK1.RSPENDM
0x8AC44 SDHI 32-bit
  [15] SDIMSK2.ILAM, [9] SDIMSK2.BWEM, [8] SDIMSK2.BREM, [6] SDIMSK2.RSPTOM, [5] SDIMSK2.ILRM, [4] SDIMSK2.ILWM, [3] SDIMSK2.DTTOM, [2] SDIMSK2.ENDEM, [1] SDIMSK2.CRCEM, [0] SDIMSK2.CMDEM
0x8AC48 SDHI 32-bit
  [9] SDCLKCR.CLKCTRLEN, [8] SDCLKCR.CLKEN, [7:0] SDCLKCR.CLKSEL
0x8AC4C SDHI 32-bit
  [9:0] SDSIZE.LEN
0x8AC50 SDHI 32-bit
  [15] SDOPT.WIDTH, [7:4] SDOPT.TOP, [3:0] SDOPT.CTOP
0x8AC58 SDHI 32-bit
  [14:12] SDERSTS1.CRCTK, [11] SDERSTS1.CRCTKE, [10] SDERSTS1.RDCRCE, [9] SDERSTS1.RSPCRCE1, [8] SDERSTS1.RSPCRCE0, [5] SDERSTS1.CRCLENE, [4] SDERSTS1.RDLENE, [3] SDERSTS1.RSPLENE1, [2] SDERSTS1.RSPLENE0, [1] SDERSTS1.CMDE1, [0] SDERSTS1.CMDE0
0x8AC5C SDHI 32-bit
  [6] SDERSTS2.CRCBSYTO, [5] SDERSTS2.CRCTO, [4] SDERSTS2.RDTO, [3] SDERSTS2.BSYTO1, [2] SDERSTS2.BSYTO0, [1] SDERSTS2.RSPTO1, [0] SDERSTS2.RSPTO0
0x8AC68 SDHI 32-bit
  [9] SDIOMD.C52PUB, [8] SDIOMD.IOABT, [2] SDIOMD.RWREQ, [0] SDIOMD.INTEN
0x8AC6C SDHI 32-bit
  [15] SDIOSTS.EXWT, [14] SDIOSTS.EXPUB52, [0] SDIOSTS.IOIRQ
0x8AC70 SDHI 32-bit
  [15] SDIOIMSK.EXWTM, [14] SDIOIMSK.EXPUB52M, [0] SDIOIMSK.IOIRQM
0x8ADB0 SDHI 32-bit
  [1] SDDMAEN.DMAEN
0x8ADC0 SDHI 32-bit
  [0] SDRST.SDRST
0x8ADC4 SDHI 32-bit
  [15] SDVER.CPRM, [14] SDVER.CLKRAT, [11:8] SDVER.IP2, [7:0] SDVER.IP1
0x8ADE0 SDHI 32-bit
  [7] SDSWAP.BRSWP, [6] SDSWAP.BWSWP
0x8B000 CAC
  [0] CACR0.CFME
0x8B001 CAC
  [7:6] CACR1.EDGES, [5:4] CACR1.TCSS, [3:1] CACR1.FMCS, [0] CACR1.CACREFE
0x8B002 CAC
  [7:6] CACR2.DFS, [5:4] CACR2.RCDS, [3:1] CACR2.RSCS, [0] CACR2.RPS
0x8B003 CAC
  [6] CAICR.OVFFCL, [5] CAICR.MENDFCL, [4] CAICR.FERRFCL, [2] CAICR.OVFIE, [1] CAICR.MENDIE, [0] CAICR.FERRIE
0x8B004 CAC
  [2] CASTR.OVFF, [1] CASTR.MENDF, [0] CASTR.FERRF
0x8B080 DOC
  [6] DOCR.DOPCFCL, [5] DOCR.DOPCF, [4] DOCR.DOPCIE, [2] DOCR.DCSEL, [1:0] DOCR.OMS
0x8B100 ELC
  [7] ELCR.ELCON
0x8B101 ELC
  [7:0] ELSR0.ELS
0x8B104 ELC
  [7:0] ELSR3.ELS
0x8B105 ELC
  [7:0] ELSR4.ELS
0x8B108 ELC
  [7:0] ELSR7.ELS
0x8B10B ELC
  [7:0] ELSR10.ELS
0x8B10C ELC
  [7:0] ELSR11.ELS
0x8B10D ELC
  [7:0] ELSR12.ELS
0x8B10E ELC
  [7:0] ELSR13.ELS
0x8B110 ELC
  [7:0] ELSR15.ELS
0x8B111 ELC
  [7:0] ELSR16.ELS
0x8B113 ELC
  [7:0] ELSR18.ELS
0x8B114 ELC
  [7:0] ELSR19.ELS
0x8B115 ELC
  [7:0] ELSR20.ELS
0x8B116 ELC
  [7:0] ELSR21.ELS
0x8B117 ELC
  [7:0] ELSR22.ELS
0x8B118 ELC
  [7:0] ELSR23.ELS
0x8B119 ELC
  [7:0] ELSR24.ELS
0x8B11A ELC
  [7:0] ELSR25.ELS
0x8B11B ELC
  [7:0] ELSR26.ELS
0x8B11C ELC
  [7:0] ELSR27.ELS
0x8B11D ELC
  [7:0] ELSR28.ELS
0x8B11F ELC
  [7:6] ELOPA.MTU3MD, [1:0] ELOPA.MTU0MD
0x8B120 ELC
  [1:0] ELOPB.MTU4MD
0x8B121 ELC
  [3:2] ELOPC.CMT1MD
0x8B122 ELC
  [2n+1:2n] ELOPD.TMR{n}MD (n=0..3)
0x8B123 ELC
  [n] PGR1.PGR{n} (n=0..7)
0x8B124 ELC
  [n] PGR2.PGR{n} (n=0..7)
0x8B125 ELC
  [6:4] PGC1.PGCO, [2] PGC1.PGCOVE, [1:0] PGC1.PGCI
0x8B126 ELC
  [6:4] PGC2.PGCO, [2] PGC2.PGCOVE, [1:0] PGC2.PGCI
0x8B127 ELC
  [n] PDBF1.PDBF{n} (n=0..7)
0x8B128 ELC
  [n] PDBF2.PDBF{n} (n=0..7)
0x8B129 ELC
  [6:5] PEL0.PSM, [4:3] PEL0.PSP, [2:0] PEL0.PSB
0x8B12A ELC
  [6:5] PEL1.PSM, [4:3] PEL1.PSP, [2:0] PEL1.PSB
0x8B12B ELC
  [6:5] PEL2.PSM, [4:3] PEL2.PSP, [2:0] PEL2.PSB
0x8B12C ELC
  [6:5] PEL3.PSM, [4:3] PEL3.PSP, [2:0] PEL3.PSB
0x8B12D ELC
  [7] ELSEGR.WI, [6] ELSEGR.WE, [0] ELSEGR.SEG
0x8B131 ELC
  [7:0] ELSR33.ELS
0x8B133 ELC
  [7:0] ELSR35.ELS
0x8B134 ELC
  [7:0] ELSR36.ELS
0x8B135 ELC
  [7:0] ELSR37.ELS
0x8B136 ELC
  [7:0] ELSR38.ELS
0x8B139 ELC
  [7:0] ELSR41.ELS
0x8B13A ELC
  [7:0] ELSR42.ELS
0x8B13B ELC
  [7:0] ELSR43.ELS
0x8B13C ELC
  [7:0] ELSR44.ELS
0x8B13D ELC
  [7:0] ELSR45.ELS
0x8B13F ELC
  [2n+1:2n] ELOPF.TPU{n}MD (n=0..3)
0x8B141 ELC
  [1:0] ELOPH.CMTW0MD
0x8B142 ELC
  [6:4] ELOPI.GPT1MD, [2:0] ELOPI.GPT0MD
0x8B143 ELC
  [6:4] ELOPJ.GPT3MD, [2:0] ELOPJ.GPT2MD
0x8B300 SCI12
  fields as SCI0
0x8B300 SMCI12
  fields as SMCI0
0x8B302 SCI12
  [7] SCR.TIE, [6] SCR.RIE, [5] SCR.TE, [4] SCR.RE, [3] SCR.MPIE, [2] SCR.TEIE, [1:0] SCR.CKE
0x8B302 SMCI12
  [7] SCR.TIE, [6] SCR.RIE, [5] SCR.TE, [4] SCR.RE, [3] SCR.MPIE, [2] SCR.TEIE, [1:0] SCR.CKE
0x8B304 SCI12
  [7] SSR.TDRE, [6] SSR.RDRF, [5] SSR.ORER, [4] SSR.FER, [3] SSR.PER, [2] SSR.TEND, [1] SSR.MPB, [0] SSR.MPBT
0x8B304 SMCI12
  [7] SSR.TDRE, [6] SSR.RDRF, [5] SSR.ORER, [4] SSR.ERS, [3] SSR.PER, [2] SSR.TEND, [1] SSR.MPB, [0] SSR.MPBT
0x8B306 SCI12
  [7] SCMR.BCP2, [4] SCMR.CHR1, [3] SCMR.SDIR, [2] SCMR.SINV, [0] SCMR.SMIF
0x8B306 SMCI12
  [7] SCMR.BCP2, [4] SCMR.CHR1, [3] SCMR.SDIR, [2] SCMR.SINV, [0] SCMR.SMIF
0x8B307 SCI12
  [7] SEMR.RXDESEL, [6] SEMR.BGDM, [5] SEMR.NFEN, [4] SEMR.ABCS, [2] SEMR.BRME, [0] SEMR.ACS0
0x8B308 SCI12
  [2:0] SNFR.NFCS
0x8B309 SCI12
  [7:3] SIMR1.IICDL, [0] SIMR1.IICM
0x8B30A SCI12
  [5] SIMR2.IICACKT, [1] SIMR2.IICCSC, [0] SIMR2.IICINTM
0x8B30B SCI12
  [7:6] SIMR3.IICSCLS, [5:4] SIMR3.IICSDAS, [3] SIMR3.IICSTIF, [2] SIMR3.IICSTPREQ, [1] SIMR3.IICRSTAREQ, [0] SIMR3.IICSTAREQ
0x8B30C SCI12
  [0] SISR.IICACKR
0x8B30D SCI12
  [7] SPMR.CKPH, [6] SPMR.CKPOL, [4] SPMR.MFF, [2] SPMR.MSS, [1] SPMR.CTSE, [0] SPMR.SSE
0x8B320 SCI12
  [0] ESMER.ESME
0x8B321 SCI12
  [3] CR0.BRME, [2] CR0.RXDSF, [1] CR0.SFSF
0x8B322 SCI12
  [7:5] CR1.PIBS, [4] CR1.PIBE, [3:2] CR1.CF1DS, [1] CR1.CF0RE, [0] CR1.BFE
0x8B323 SCI12
  [7:6] CR2.RTS, [5:4] CR2.BCCS, [2:0] CR2.DFCS
0x8B324 SCI12
  [0] CR3.SDST
0x8B325 SCI12
  [4] PCR.SHARPS, [1] PCR.RXDXPS, [0] PCR.TXDXPS
0x8B326 SCI12
  [5] ICR.AEDIE, [4] ICR.BCDIE, [3] ICR.PIBDIE, [2] ICR.CF1MIE, [1] ICR.CF0MIE, [0] ICR.BFDIE
0x8B327 SCI12
  [5] STR.AEDF, [4] STR.BCDF, [3] STR.PIBDF, [2] STR.CF1MF, [1] STR.CF0MF, [0] STR.BFDF
0x8B328 SCI12
  [5] STCR.AEDCL, [4] STCR.BCDCL, [3] STCR.PIBDCL, [2] STCR.CF1MCL, [1] STCR.CF0MCL, [0] STCR.BFDCL
0x8B32A SCI12
  [n] CF0CR.CF0CE{n} (n=0..7)
0x8B32E SCI12
  [n] CF1CR.CF1CE{n} (n=0..7)
0x8B330 SCI12
  [0] TCR.TCST
0x8B331 SCI12
  [6:4] TMR.TCSS, [3] TMR.TWRC, [1:0] TMR.TOMS
0x8C000 PORT0
  [7] PDR.B7, [5] PDR.B5, [n] PDR.B{n} (n=0..3)
0x8C001 PORT1
  [n] PDR.B{n} (n=0..7)
0x8C002 PORT2
  [n] PDR.B{n} (n=0..7)
0x8C003 PORT3
  [7] PDR.B7, [6] PDR.B6, [n] PDR.B{n} (n=0..4)
0x8C004 PORT4
  [n] PDR.B{n} (n=0..7)
0x8C005 PORT5
  [n] PDR.B{n} (n=0..6)
0x8C006 PORT6
  [n] PDR.B{n} (n=0..7)
0x8C007 PORT7
  [n] PDR.B{n} (n=0..7)
0x8C008 PORT8
  [7] PDR.B7, [6] PDR.B6, [n] PDR.B{n} (n=0..3)
0x8C009 PORT9
  [n] PDR.B{n} (n=0..7)
0x8C00A PORTA
  [n] PDR.B{n} (n=0..7)
0x8C00B PORTB
  [n] PDR.B{n} (n=0..7)
0x8C00C PORTC
  [n] PDR.B{n} (n=0..7)
0x8C00D PORTD
  [n] PDR.B{n} (n=0..7)
0x8C00E PORTE
  [n] PDR.B{n} (n=0..7)
0x8C00F PORTF
  [n] PDR.B{n} (n=0..5)
0x8C010 PORTG
  [n] PDR.B{n} (n=0..7)
0x8C012 PORTJ
  [5] PDR.B5, [3] PDR.B3
0x8C020 PORT0
  [7] PODR.B7, [5] PODR.B5, [n] PODR.B{n} (n=0..3)
0x8C021 PORT1
  [n] PODR.B{n} (n=0..7)
0x8C022 PORT2
  [n] PODR.B{n} (n=0..7)
0x8C023 PORT3
  [7] PODR.B7, [6] PODR.B6, [n] PODR.B{n} (n=0..4)
0x8C024 PORT4
  [n] PODR.B{n} (n=0..7)
0x8C025 PORT5
  [n] PODR.B{n} (n=0..6)
0x8C026 PORT6
  [n] PODR.B{n} (n=0..7)
0x8C027 PORT7
  [n] PODR.B{n} (n=0..7)
0x8C028 PORT8
  [7] PODR.B7, [6] PODR.B6, [n] PODR.B{n} (n=0..3)
0x8C029 PORT9
  [n] PODR.B{n} (n=0..7)
0x8C02A PORTA
  [n] PODR.B{n} (n=0..7)
0x8C02B PORTB
  [n] PODR.B{n} (n=0..7)
0x8C02C PORTC
  [n] PODR.B{n} (n=0..7)
0x8C02D PORTD
  [n] PODR.B{n} (n=0..7)
0x8C02E PORTE
  [n] PODR.B{n} (n=0..7)
0x8C02F PORTF
  [n] PODR.B{n} (n=0..5)
0x8C030 PORTG
  [n] PODR.B{n} (n=0..7)
0x8C032 PORTJ
  [5] PODR.B5, [3] PODR.B3
0x8C040 PORT0
  [7] PIDR.B7, [5] PIDR.B5, [n] PIDR.B{n} (n=0..3)
{0x8C040+i} PORT{i} (i=1..4)
  [n] PIDR.B{n} (n=0..7)
0x8C045 PORT5
  [n] PIDR.B{n} (n=0..6)
0x8C046 PORT6
  [n] PIDR.B{n} (n=0..7)
0x8C047 PORT7
  [n] PIDR.B{n} (n=0..7)
0x8C048 PORT8
  [7] PIDR.B7, [6] PIDR.B6, [n] PIDR.B{n} (n=0..3)
0x8C049 PORT9
  [n] PIDR.B{n} (n=0..7)
0x8C04A PORTA
  [n] PIDR.B{n} (n=0..7)
0x8C04B PORTB
  [n] PIDR.B{n} (n=0..7)
0x8C04C PORTC
  [n] PIDR.B{n} (n=0..7)
0x8C04D PORTD
  [n] PIDR.B{n} (n=0..7)
0x8C04E PORTE
  [n] PIDR.B{n} (n=0..7)
0x8C04F PORTF
  [n] PIDR.B{n} (n=0..5)
0x8C050 PORTG
  [n] PIDR.B{n} (n=0..7)
0x8C052 PORTJ
  [5] PIDR.B5, [3] PIDR.B3
0x8C060 PORT0
  [7] PMR.B7, [5] PMR.B5, [n] PMR.B{n} (n=0..3)
0x8C061 PORT1
  [n] PMR.B{n} (n=0..7)
0x8C062 PORT2
  [n] PMR.B{n} (n=0..7)
0x8C063 PORT3
  [7] PMR.B7, [6] PMR.B6, [n] PMR.B{n} (n=0..4)
0x8C064 PORT4
  [n] PMR.B{n} (n=0..7)
0x8C065 PORT5
  [n] PMR.B{n} (n=0..6)
0x8C066 PORT6
  [n] PMR.B{n} (n=0..7)
0x8C067 PORT7
  [n] PMR.B{n} (n=0..7)
0x8C068 PORT8
  [7] PMR.B7, [6] PMR.B6, [n] PMR.B{n} (n=0..3)
0x8C069 PORT9
  [n] PMR.B{n} (n=0..7)
0x8C06A PORTA
  [n] PMR.B{n} (n=0..7)
0x8C06B PORTB
  [n] PMR.B{n} (n=0..7)
0x8C06C PORTC
  [n] PMR.B{n} (n=0..7)
0x8C06D PORTD
  [n] PMR.B{n} (n=0..7)
0x8C06E PORTE
  [n] PMR.B{n} (n=0..7)
0x8C06F PORTF
  [n] PMR.B{n} (n=0..5)
0x8C070 PORTG
  [n] PMR.B{n} (n=0..7)
0x8C072 PORTJ
  [5] PMR.B5, [3] PMR.B3
0x8C080 PORT0
  [6] ODR0.B6, [4] ODR0.B4, [2] ODR0.B2, [0] ODR0.B0
0x8C081 PORT0
  [6] ODR1.B6, [2] ODR1.B2
0x8C082 PORT1
  [6] ODR0.B6, [4] ODR0.B4, [2] ODR0.B2, [0] ODR0.B0
0x8C083 PORT1
  [6] ODR1.B6, [4] ODR1.B4, [2] ODR1.B2, [0] ODR1.B0
0x8C084 PORT2
  [6] ODR0.B6, [4] ODR0.B4, [2] ODR0.B2, [0] ODR0.B0
0x8C085 PORT2
  [6] ODR1.B6, [4] ODR1.B4, [2] ODR1.B2, [0] ODR1.B0
0x8C086 PORT3
  [6] ODR0.B6, [4] ODR0.B4, [2] ODR0.B2, [0] ODR0.B0
0x8C087 PORT3
  [6] ODR1.B6, [4] ODR1.B4, [0] ODR1.B0
0x8C088 PORT4
  [6] ODR0.B6, [4] ODR0.B4, [2] ODR0.B2, [0] ODR0.B0
0x8C089 PORT4
  [6] ODR1.B6, [4] ODR1.B4, [2] ODR1.B2, [0] ODR1.B0
0x8C08A PORT5
  [6] ODR0.B6, [4] ODR0.B4, [2] ODR0.B2, [0] ODR0.B0
0x8C08B PORT5
  [6] ODR1.B6, [4] ODR1.B4, [2] ODR1.B2, [0] ODR1.B0
0x8C08C PORT6
  [6] ODR0.B6, [4] ODR0.B4, [2] ODR0.B2, [0] ODR0.B0
0x8C08D PORT6
  [6] ODR1.B6, [4] ODR1.B4, [2] ODR1.B2, [0] ODR1.B0
0x8C08E PORT7
  [6] ODR0.B6, [4] ODR0.B4, [2] ODR0.B2, [0] ODR0.B0
0x8C08F PORT7
  [6] ODR1.B6, [4] ODR1.B4, [2] ODR1.B2, [0] ODR1.B0
0x8C090 PORT8
  [6] ODR0.B6, [4] ODR0.B4, [2] ODR0.B2, [0] ODR0.B0
0x8C091 PORT8
  [6] ODR1.B6, [4] ODR1.B4
0x8C092 PORT9
  [6] ODR0.B6, [4] ODR0.B4, [2] ODR0.B2, [0] ODR0.B0
0x8C093 PORT9
  [6] ODR1.B6, [4] ODR1.B4, [2] ODR1.B2, [0] ODR1.B0
0x8C094 PORTA
  [6] ODR0.B6, [4] ODR0.B4, [2] ODR0.B2, [0] ODR0.B0
0x8C095 PORTA
  [6] ODR1.B6, [4] ODR1.B4, [2] ODR1.B2, [0] ODR1.B0
0x8C096 PORTB
  [6] ODR0.B6, [4] ODR0.B4, [2] ODR0.B2, [0] ODR0.B0
0x8C097 PORTB
  [6] ODR1.B6, [4] ODR1.B4, [2] ODR1.B2, [0] ODR1.B0
0x8C098 PORTC
  [6] ODR0.B6, [4] ODR0.B4, [2] ODR0.B2, [0] ODR0.B0
0x8C099 PORTC
  [6] ODR1.B6, [4] ODR1.B4, [2] ODR1.B2, [0] ODR1.B0
0x8C09A PORTD
  [6] ODR0.B6, [4] ODR0.B4, [2] ODR0.B2, [0] ODR0.B0
0x8C09B PORTD
  [6] ODR1.B6, [4] ODR1.B4, [2] ODR1.B2, [0] ODR1.B0
0x8C09C PORTE
  [6] ODR0.B6, [4] ODR0.B4, [3] ODR0.B3, [2] ODR0.B2, [0] ODR0.B0
0x8C09D PORTE
  [6] ODR1.B6, [4] ODR1.B4, [2] ODR1.B2, [0] ODR1.B0
0x8C09E PORTF
  [6] ODR0.B6, [4] ODR0.B4, [2] ODR0.B2, [0] ODR0.B0
0x8C09F PORTF
  [2] ODR1.B2, [0] ODR1.B0
0x8C0A0 PORTG
  [6] ODR0.B6, [4] ODR0.B4, [2] ODR0.B2, [0] ODR0.B0
0x8C0A1 PORTG
  [6] ODR1.B6, [4] ODR1.B4, [2] ODR1.B2, [0] ODR1.B0
0x8C0A4 PORTJ
  [6] ODR0.B6
0x8C0A5 PORTJ
  [2] ODR1.B2
0x8C0C0 PORT0
  [7] PCR.B7, [5] PCR.B5, [n] PCR.B{n} (n=0..3)
0x8C0C1 PORT1
  [n] PCR.B{n} (n=0..7)
0x8C0C2 PORT2
  [n] PCR.B{n} (n=0..7)
0x8C0C3 PORT3
  [7] PCR.B7, [6] PCR.B6, [n] PCR.B{n} (n=0..4)
0x8C0C4 PORT4
  [n] PCR.B{n} (n=0..7)
0x8C0C5 PORT5
  [n] PCR.B{n} (n=0..6)
0x8C0C6 PORT6
  [n] PCR.B{n} (n=0..7)
0x8C0C7 PORT7
  [n] PCR.B{n} (n=0..7)
0x8C0C8 PORT8
  [7] PCR.B7, [6] PCR.B6, [n] PCR.B{n} (n=0..3)
0x8C0C9 PORT9
  [n] PCR.B{n} (n=0..7)
0x8C0CA PORTA
  [n] PCR.B{n} (n=0..7)
0x8C0CB PORTB
  [n] PCR.B{n} (n=0..7)
0x8C0CC PORTC
  [n] PCR.B{n} (n=0..7)
0x8C0CD PORTD
  [n] PCR.B{n} (n=0..7)
0x8C0CE PORTE
  [n] PCR.B{n} (n=0..7)
0x8C0CF PORTF
  [n] PCR.B{n} (n=0..5)
0x8C0D0 PORTG
  [n] PCR.B{n} (n=0..7)
0x8C0D2 PORTJ
  [5] PCR.B5, [3] PCR.B3
0x8C0E0 PORT0
  [2] DSCR.B2, [1] DSCR.B1, [0] DSCR.B0
0x8C0E2 PORT2
  [7] DSCR.B7
0x8C0E5 PORT5
  [6] DSCR.B6, [2] DSCR.B2, [1] DSCR.B1, [0] DSCR.B0
0x8C0E9 PORT9
  [n] DSCR.B{n} (n=0..7)
0x8C0EA PORTA
  [n] DSCR.B{n} (n=0..7)
0x8C0EB PORTB
  [n] DSCR.B{n} (n=0..7)
0x8C0EC PORTC
  [n] DSCR.B{n} (n=0..7)
0x8C0ED PORTD
  [n] DSCR.B{n} (n=0..7)
0x8C0EE PORTE
  [n] DSCR.B{n} (n=0..7)
0x8C0F0 PORTG
  [1] DSCR.B1, [0] DSCR.B0
0x8C100 MPC
  [n] PFCSE.CS{n}E (n=0..7)
0x8C102 MPC
  [7:6] PFCSS0.CS3S, [5:4] PFCSS0.CS2S, [3:2] PFCSS0.CS1S, [0] PFCSS0.CS0S
0x8C103 MPC
  [2n-7:2n-8] PFCSS1.CS{n}S (n=4..7)
0x8C104 MPC
  [n-8] PFAOE0.A{n}E (n=8..15)
0x8C105 MPC
  [n-16] PFAOE1.A{n}E (n=16..23)
0x8C106 MPC
  [7] PFBCR0.WR32BC32E, [6] PFBCR0.WR1BC1E, [5] PFBCR0.DH32E, [4] PFBCR0.DHE, [3] PFBCR0.BCLKO, [2] PFBCR0.ADRHMS2, [1] PFBCR0.ADRHMS, [0] PFBCR0.ADRLE
0x8C107 MPC
  [7] PFBCR1.SDCLKE, [6] PFBCR1.DQM1E, [4] PFBCR1.MDSDE, [3] PFBCR1.ALES, [2] PFBCR1.ALEOE, [1:0] PFBCR1.WAITS
0x8C10E MPC
  [5] PFENET.PHYMODE1, [4] PFENET.PHYMODE0
0x8C11F MPC
  [7] PWPR.B0WI, [6] PWPR.PFSWE
0x8C140 MPC
  [7] P00PFS.ASEL, [6] P00PFS.ISEL, [5:0] P00PFS.PSEL
0x8C141 MPC
  [7] P01PFS.ASEL, [6] P01PFS.ISEL, [5:0] P01PFS.PSEL
0x8C142 MPC
  [7] P02PFS.ASEL, [6] P02PFS.ISEL, [5:0] P02PFS.PSEL
0x8C143 MPC
  [7] P03PFS.ASEL, [6] P03PFS.ISEL
0x8C145 MPC
  [7] P05PFS.ASEL, [6] P05PFS.ISEL
0x8C147 MPC
  [6] P07PFS.ISEL, [5:0] P07PFS.PSEL
0x8C148 MPC
  [6] P10PFS.ISEL, [5:0] P10PFS.PSEL
0x8C149 MPC
  [6] P11PFS.ISEL, [5:0] P11PFS.PSEL
0x8C14A MPC
  [6] P12PFS.ISEL, [5:0] P12PFS.PSEL
0x8C14B MPC
  [6] P13PFS.ISEL, [5:0] P13PFS.PSEL
0x8C14C MPC
  [6] P14PFS.ISEL, [5:0] P14PFS.PSEL
0x8C14D MPC
  [6] P15PFS.ISEL, [5:0] P15PFS.PSEL
0x8C14E MPC
  [6] P16PFS.ISEL, [5:0] P16PFS.PSEL
0x8C14F MPC
  [6] P17PFS.ISEL, [5:0] P17PFS.PSEL
0x8C150 MPC
  [6] P20PFS.ISEL, [5:0] P20PFS.PSEL
0x8C151 MPC
  [6] P21PFS.ISEL, [5:0] P21PFS.PSEL
0x8C152 MPC
  [5:0] P22PFS.PSEL
0x8C153 MPC
  [5:0] P23PFS.PSEL
0x8C154 MPC
  [5:0] P24PFS.PSEL
0x8C155 MPC
  [5:0] P25PFS.PSEL
0x8C156 MPC
  [5:0] P26PFS.PSEL
0x8C157 MPC
  [5:0] P27PFS.PSEL
0x8C158 MPC
  [6] P30PFS.ISEL, [5:0] P30PFS.PSEL
0x8C159 MPC
  [6] P31PFS.ISEL, [5:0] P31PFS.PSEL
0x8C15A MPC
  [6] P32PFS.ISEL, [5:0] P32PFS.PSEL
0x8C15B MPC
  [6] P33PFS.ISEL, [5:0] P33PFS.PSEL
0x8C15C MPC
  [6] P34PFS.ISEL, [5:0] P34PFS.PSEL
0x8C160 MPC
  [7] P40PFS.ASEL, [6] P40PFS.ISEL
0x8C161 MPC
  [7] P41PFS.ASEL, [6] P41PFS.ISEL
0x8C162 MPC
  [7] P42PFS.ASEL, [6] P42PFS.ISEL
0x8C163 MPC
  [7] P43PFS.ASEL, [6] P43PFS.ISEL
0x8C164 MPC
  [7] P44PFS.ASEL, [6] P44PFS.ISEL
0x8C165 MPC
  [7] P45PFS.ASEL, [6] P45PFS.ISEL
0x8C166 MPC
  [7] P46PFS.ASEL, [6] P46PFS.ISEL
0x8C167 MPC
  [7] P47PFS.ASEL, [6] P47PFS.ISEL
0x8C168 MPC
  [5:0] P50PFS.PSEL
0x8C169 MPC
  [5:0] P51PFS.PSEL
0x8C16A MPC
  [5:0] P52PFS.PSEL
0x8C16C MPC
  [5:0] P54PFS.PSEL
0x8C16D MPC
  [6] P55PFS.ISEL, [5:0] P55PFS.PSEL
0x8C16E MPC
  [5:0] P56PFS.PSEL
0x8C170 MPC
  [5:0] P60PFS.PSEL
0x8C176 MPC
  [5:0] P66PFS.PSEL
0x8C177 MPC
  [6] P67PFS.ISEL, [5:0] P67PFS.PSEL
0x8C179 MPC
  [5:0] P71PFS.PSEL
0x8C17A MPC
  [5:0] P72PFS.PSEL
0x8C17B MPC
  [5:0] P73PFS.PSEL
0x8C17C MPC
  [5:0] P74PFS.PSEL
0x8C17D MPC
  [5:0] P75PFS.PSEL
0x8C17E MPC
  [5:0] P76PFS.PSEL
0x8C17F MPC
  [5:0] P77PFS.PSEL
0x8C180 MPC
  [5:0] P80PFS.PSEL
0x8C181 MPC
  [5:0] P81PFS.PSEL
0x8C182 MPC
  [5:0] P82PFS.PSEL
0x8C183 MPC
  [5:0] P83PFS.PSEL
0x8C186 MPC
  [5:0] P86PFS.PSEL
0x8C187 MPC
  [5:0] P87PFS.PSEL
0x8C188 MPC
  [7] P90PFS.ASEL, [5:0] P90PFS.PSEL
0x8C189 MPC
  [7] P91PFS.ASEL, [5:0] P91PFS.PSEL
0x8C18A MPC
  [7] P92PFS.ASEL, [5:0] P92PFS.PSEL
0x8C18B MPC
  [7] P93PFS.ASEL, [5:0] P93PFS.PSEL
0x8C18C MPC
  [7] P94PFS.ASEL, [5:0] P94PFS.PSEL
0x8C18D MPC
  [7] P95PFS.ASEL, [5:0] P95PFS.PSEL
0x8C18E MPC
  [7] P96PFS.ASEL, [5:0] P96PFS.PSEL
0x8C18F MPC
  [7] P97PFS.ASEL, [5:0] P97PFS.PSEL
0x8C190 MPC
  [5:0] PA0PFS.PSEL
0x8C191 MPC
  [6] PA1PFS.ISEL, [5:0] PA1PFS.PSEL
0x8C192 MPC
  [5:0] PA2PFS.PSEL
0x8C193 MPC
  [6] PA3PFS.ISEL, [5:0] PA3PFS.PSEL
0x8C194 MPC
  [6] PA4PFS.ISEL, [5:0] PA4PFS.PSEL
0x8C195 MPC
  [5:0] PA5PFS.PSEL
0x8C196 MPC
  [5:0] PA6PFS.PSEL
0x8C197 MPC
  [5:0] PA7PFS.PSEL
0x8C198 MPC
  [6] PB0PFS.ISEL, [5:0] PB0PFS.PSEL
0x8C199 MPC
  [6] PB1PFS.ISEL, [5:0] PB1PFS.PSEL
0x8C19A MPC
  [5:0] PB2PFS.PSEL
0x8C19B MPC
  [5:0] PB3PFS.PSEL
0x8C19C MPC
  [5:0] PB4PFS.PSEL
0x8C19D MPC
  [5:0] PB5PFS.PSEL
0x8C19E MPC
  [5:0] PB6PFS.PSEL
0x8C19F MPC
  [5:0] PB7PFS.PSEL
0x8C1A0 MPC
  [6] PC0PFS.ISEL, [5:0] PC0PFS.PSEL
0x8C1A1 MPC
  [6] PC1PFS.ISEL, [5:0] PC1PFS.PSEL
0x8C1A2 MPC
  [5:0] PC2PFS.PSEL
0x8C1A3 MPC
  [5:0] PC3PFS.PSEL
0x8C1A4 MPC
  [5:0] PC4PFS.PSEL
0x8C1A5 MPC
  [5:0] PC5PFS.PSEL
0x8C1A6 MPC
  [6] PC6PFS.ISEL, [5:0] PC6PFS.PSEL
0x8C1A7 MPC
  [6] PC7PFS.ISEL, [5:0] PC7PFS.PSEL
0x8C1A8 MPC
  [7] PD0PFS.ASEL, [6] PD0PFS.ISEL, [5:0] PD0PFS.PSEL
0x8C1A9 MPC
  [7] PD1PFS.ASEL, [6] PD1PFS.ISEL, [5:0] PD1PFS.PSEL
0x8C1AA MPC
  [7] PD2PFS.ASEL, [6] PD2PFS.ISEL, [5:0] PD2PFS.PSEL
0x8C1AB MPC
  [7] PD3PFS.ASEL, [6] PD3PFS.ISEL, [5:0] PD3PFS.PSEL
0x8C1AC MPC
  [7] PD4PFS.ASEL, [6] PD4PFS.ISEL, [5:0] PD4PFS.PSEL
0x8C1AD MPC
  [7] PD5PFS.ASEL, [6] PD5PFS.ISEL, [5:0] PD5PFS.PSEL
0x8C1AE MPC
  [7] PD6PFS.ASEL, [6] PD6PFS.ISEL, [5:0] PD6PFS.PSEL
0x8C1AF MPC
  [7] PD7PFS.ASEL, [6] PD7PFS.ISEL, [5:0] PD7PFS.PSEL
0x8C1B0 MPC
  [7] PE0PFS.ASEL, [5:0] PE0PFS.PSEL
0x8C1B1 MPC
  [7] PE1PFS.ASEL, [5:0] PE1PFS.PSEL
0x8C1B2 MPC
  [7] PE2PFS.ASEL, [6] PE2PFS.ISEL, [5:0] PE2PFS.PSEL
0x8C1B3 MPC
  [7] PE3PFS.ASEL, [5:0] PE3PFS.PSEL
0x8C1B4 MPC
  [7] PE4PFS.ASEL, [5:0] PE4PFS.PSEL
0x8C1B5 MPC
  [7] PE5PFS.ASEL, [6] PE5PFS.ISEL, [5:0] PE5PFS.PSEL
0x8C1B6 MPC
  [7] PE6PFS.ASEL, [6] PE6PFS.ISEL, [5:0] PE6PFS.PSEL
0x8C1B7 MPC
  [7] PE7PFS.ASEL, [6] PE7PFS.ISEL, [5:0] PE7PFS.PSEL
0x8C1B8 MPC
  [5:0] PF0PFS.PSEL
0x8C1B9 MPC
  [5:0] PF1PFS.PSEL
0x8C1BA MPC
  [5:0] PF2PFS.PSEL
0x8C1BD MPC
  [6] PF5PFS.ISEL, [5:0] PF5PFS.PSEL
0x8C1C0 MPC
  [5:0] PG0PFS.PSEL
0x8C1C1 MPC
  [5:0] PG1PFS.PSEL
0x8C1C2 MPC
  [5:0] PG2PFS.PSEL
0x8C1C3 MPC
  [5:0] PG3PFS.PSEL
0x8C1C4 MPC
  [5:0] PG4PFS.PSEL
0x8C1C5 MPC
  [5:0] PG5PFS.PSEL
0x8C1C6 MPC
  [5:0] PG6PFS.PSEL
0x8C1C7 MPC
  [5:0] PG7PFS.PSEL
0x8C1D3 MPC
  [5:0] PJ3PFS.PSEL
0x8C1D5 MPC
  [5:0] PJ5PFS.PSEL
0x8C280 SYSTEM
  [7] DPSBYCR.DPSBY, [6] DPSBYCR.IOKEEP, [1:0] DPSBYCR.DEEPCUT
0x8C282 SYSTEM
  [n] DPSIER0.DIRQ{n}E (n=0..7)
0x8C283 SYSTEM
  [n-8] DPSIER1.DIRQ{n}E (n=8..15)
0x8C284 SYSTEM
  [7] DPSIER2.DUSBIE, [6] DPSIER2.DRIICCIE, [5] DPSIER2.DRIICDIE, [4] DPSIER2.DNMIE, [3] DPSIER2.DRTCAIE, [2] DPSIER2.DRTCIIE, [1] DPSIER2.DLVD2IE, [0] DPSIER2.DLVD1IE
0x8C285 SYSTEM
  [0] DPSIER3.DCANIE
0x8C286 SYSTEM
  [n] DPSIFR0.DIRQ{n}F (n=0..7)
0x8C287 SYSTEM
  [n-8] DPSIFR1.DIRQ{n}F (n=8..15)
0x8C288 SYSTEM
  [7] DPSIFR2.DUSBIF, [6] DPSIFR2.DRIICCIF, [5] DPSIFR2.DRIICDIF, [4] DPSIFR2.DNMIF, [3] DPSIFR2.DRTCAIF, [2] DPSIFR2.DRTCIIF, [1] DPSIFR2.DLVD2IF, [0] DPSIFR2.DLVD1IF
0x8C289 SYSTEM
  [0] DPSIFR3.DCANIF
0x8C28A SYSTEM
  [n] DPSIEGR0.DIRQ{n}EG (n=0..7)
0x8C28B SYSTEM
  [n-8] DPSIEGR1.DIRQ{n}EG (n=8..15)
0x8C28C SYSTEM
  [6] DPSIEGR2.DRIICCEG, [5] DPSIEGR2.DRIICDEG, [4] DPSIEGR2.DNMIEG, [1] DPSIEGR2.DLVD2EG, [0] DPSIEGR2.DLVD1EG
0x8C28D SYSTEM
  [0] DPSIEGR3.DCANIEG
0x8C290 SYSTEM
  [7] RSTSR0.DPSRSTF, [3] RSTSR0.LVD2RF, [2] RSTSR0.LVD1RF, [1] RSTSR0.LVD0RF, [0] RSTSR0.PORF
0x8C291 SYSTEM
  [0] RSTSR1.CWSF
0x8C293 SYSTEM
  [6] MOFCR.MOSEL, [5:4] MOFCR.MODRV2, [0] MOFCR.MOFXIN
0x8C294 SYSTEM
  [0] HOCOPCR.HOCOPCNT
0x8C296 FLASH
  [1:0] FWEPROR.FLWE
0x8C297 SYSTEM
  [6] LVCMPCR.LVD2E, [5] LVCMPCR.LVD1E
0x8C298 SYSTEM
  [7:4] LVDLVLR.LVD2LVL, [3:0] LVDLVLR.LVD1LVL
0x8C29A SYSTEM
  [7] LVD1CR0.LVD1RN, [6] LVD1CR0.LVD1RI, [5:4] LVD1CR0.LVD1FSAMP, [2] LVD1CR0.LVD1CMPE, [1] LVD1CR0.LVD1DFDIS, [0] LVD1CR0.LVD1RIE
0x8C29B SYSTEM
  [7] LVD2CR0.LVD2RN, [6] LVD2CR0.LVD2RI, [5:4] LVD2CR0.LVD2FSAMP, [2] LVD2CR0.LVD2CMPE, [1] LVD2CR0.LVD2DFDIS, [0] LVD2CR0.LVD2RIE
0x8C400 RTC
  [6] R64CNT.F1HZ, [5] R64CNT.F2HZ, [4] R64CNT.F4HZ, [3] R64CNT.F8HZ, [2] R64CNT.F16HZ, [1] R64CNT.F32HZ, [0] R64CNT.F64HZ
0x8C402 RTC
  [6:4] RSECCNT.SEC10, [3:0] RSECCNT.SEC1, [7:0] BCNT0.BCNT
0x8C404 RTC
  [6:4] RMINCNT.MIN10, [3:0] RMINCNT.MIN1, [7:0] BCNT1.BCNT
0x8C406 RTC
  [6] RHRCNT.PM, [5:4] RHRCNT.HR10, [3:0] RHRCNT.HR1, [7:0] BCNT2.BCNT
0x8C408 RTC
  [2:0] RWKCNT.DAYW, [7:0] BCNT3.BCNT
0x8C40A RTC
  [5:4] RDAYCNT.DATE10, [3:0] RDAYCNT.DATE1
0x8C40C RTC
  [4] RMONCNT.MON10, [3:0] RMONCNT.MON1
0x8C40E RTC 16-bit
  [7:4] RYRCNT.YR10, [3:0] RYRCNT.YR1
0x8C410 RTC
  [7] RSECAR.ENB, [6:4] RSECAR.SEC10, [3:0] RSECAR.SEC1, [7:0] BCNT0AR.BCNTAR
0x8C412 RTC
  [7] RMINAR.ENB, [6:4] RMINAR.MIN10, [3:0] RMINAR.MIN1, [7:0] BCNT1AR.BCNTAR
0x8C414 RTC
  [7] RHRAR.ENB, [6] RHRAR.PM, [5:4] RHRAR.HR10, [3:0] RHRAR.HR1, [7:0] BCNT2AR.BCNTAR
0x8C416 RTC
  [7] RWKAR.ENB, [2:0] RWKAR.DAYW, [7:0] BCNT3AR.BCNTAR
0x8C418 RTC
  [7] RDAYAR.ENB, [5:4] RDAYAR.DATE10, [3:0] RDAYAR.DATE1, [7:0] BCNT0AER.ENB
0x8C41A RTC
  [7] RMONAR.ENB, [4] RMONAR.MON10, [3:0] RMONAR.MON1, [7:0] BCNT1AER.ENB
0x8C41C RTC 16-bit
  [7:4] RYRAR.YR10, [3:0] RYRAR.YR1, [7:0] BCNT2AER.ENB
0x8C41E RTC
  [7] RYRAREN.ENB, [7:0] BCNT3AER.ENB
0x8C422 RTC
  [7:4] RCR1.PES, [3] RCR1.RTCOS, [2] RCR1.PIE, [1] RCR1.CIE, [0] RCR1.AIE
0x8C424 RTC
  [7] RCR2.CNTMD, [6] RCR2.HR24, [5] RCR2.AADJP, [4] RCR2.AADJE, [3] RCR2.RTCOE, [2] RCR2.ADJ30, [1] RCR2.RESET, [0] RCR2.START
0x8C426 RTC
  [3:1] RCR3.RTCDV, [0] RCR3.RTCEN
0x8C428 RTC
  [0] RCR4.RCKSEL
0x8C42A RTC 16-bit
  [0] RFRH.RFC
0x8C42C RTC 16-bit
  [15:0] RFRL.RFC
0x8C42E RTC
  [7:6] RADJ.PMADJ, [5:0] RADJ.ADJ
0x8C440 RTC
  [7] RTCCR0.TCEN, [5:4] RTCCR0.TCNF, [2] RTCCR0.TCST, [1:0] RTCCR0.TCCT
0x8C442 RTC
  [7] RTCCR1.TCEN, [5:4] RTCCR1.TCNF, [2] RTCCR1.TCST, [1:0] RTCCR1.TCCT
0x8C444 RTC
  [7] RTCCR2.TCEN, [5:4] RTCCR2.TCNF, [2] RTCCR2.TCST, [1:0] RTCCR2.TCCT
0x8C452 RTC
  [6:4] RSECCP0.SEC10, [3:0] RSECCP0.SEC1, [7:0] BCNT0CP0.BCNCP0
0x8C454 RTC
  [6:4] RMINCP0.MIN10, [3:0] RMINCP0.MIN1, [7:0] BCNT1CP0.BCNCP0
0x8C456 RTC
  [6] RHRCP0.PM, [5:4] RHRCP0.HR10, [3:0] RHRCP0.HR1, [7:0] BCNT2CP0.BCNCP0
0x8C45A RTC
  [5:4] RDAYCP0.DATE10, [3:0] RDAYCP0.DATE1, [7:0] BCNT3CP0.BCNCP0
0x8C45C RTC
  [4] RMONCP0.MON10, [3:0] RMONCP0.MON1
0x8C462 RTC
  [6:4] RSECCP1.SEC10, [3:0] RSECCP1.SEC1, [7:0] BCNT0CP1.BCNCP1
0x8C464 RTC
  [6:4] RMINCP1.MIN10, [3:0] RMINCP1.MIN1, [7:0] BCNT1CP1.BCNCP1
0x8C466 RTC
  [6] RHRCP1.PM, [5:4] RHRCP1.HR10, [3:0] RHRCP1.HR1, [7:0] BCNT2CP1.BCNCP1
0x8C46A RTC
  [5:4] RDAYCP1.DATE10, [3:0] RDAYCP1.DATE1, [7:0] BCNT3CP1.BCNCP1
0x8C46C RTC
  [4] RMONCP1.MON10, [3:0] RMONCP1.MON1
0x8C472 RTC
  [6:4] RSECCP2.SEC10, [3:0] RSECCP2.SEC1, [7:0] BCNT0CP2.BCNCP2
0x8C474 RTC
  [6:4] RMINCP2.MIN10, [3:0] RMINCP2.MIN1, [7:0] BCNT1CP2.BCNCP2
0x8C476 RTC
  [6] RHRCP2.PM, [5:4] RHRCP2.HR10, [3:0] RHRCP2.HR1, [7:0] BCNT2CP2.BCNCP2
0x8C47A RTC
  [5:4] RDAYCP2.DATE10, [3:0] RDAYCP2.DATE1, [7:0] BCNT3CP2.BCNCP2
0x8C47C RTC
  [4] RMONCP2.MON10, [3:0] RMONCP2.MON1
0x8C4C0 POE3 16-bit
  [12] ICSR1.POE0F, [8] ICSR1.PIE1, [1:0] ICSR1.POE0M
0x8C4C2 POE3 16-bit
  [15] OCSR1.OSF1, [9] OCSR1.OCE1, [8] OCSR1.OIE1
0x8C4C4 POE3 16-bit
  [12] ICSR2.POE4F, [8] ICSR2.PIE2, [1:0] ICSR2.POE4M
0x8C4C6 POE3 16-bit
  [15] OCSR2.OSF2, [9] OCSR2.OCE2, [8] OCSR2.OIE2
0x8C4C8 POE3 16-bit
  [12] ICSR3.POE8F, [9] ICSR3.POE8E, [8] ICSR3.PIE3, [1:0] ICSR3.POE8M
0x8C4CA POE3
  [4] SPOER.GPT23HIZ, [3] SPOER.GPT01HIZ, [2] SPOER.MTUCH0HIZ, [1] SPOER.MTUCH67HIZ, [0] SPOER.MTUCH34HIZ
0x8C4CB POE3
  [3] POECR1.MTU0DZE, [2] POECR1.MTU0CZE, [1] POECR1.MTU0BZE, [0] POECR1.MTU0AZE
0x8C4CC POE3 16-bit
  [10] POECR2.MTU3BDZE, [9] POECR2.MTU4ACZE, [8] POECR2.MTU4BDZE, [2] POECR2.MTU6BDZE, [1] POECR2.MTU7ACZE, [0] POECR2.MTU7BDZE
0x8C4CE POE3 16-bit
  [9] POECR3.GPT3ABZE, [8] POECR3.GPT2ABZE, [1] POECR3.GPT1ABZE, [0] POECR3.GPT0ABZE
0x8C4D0 POE3 16-bit
  [13] POECR4.IC5ADDMT67ZE, [12] POECR4.IC4ADDMT67ZE, [11] POECR4.IC3ADDMT67ZE, [9] POECR4.IC1ADDMT67ZE, [n] POECR4.IC{n}ADDMT34ZE (n=2..5)
0x8C4D2 POE3 16-bit
  [5] POECR5.IC5ADDMT0ZE, [4] POECR5.IC4ADDMT0ZE, [2] POECR5.IC2ADDMT0ZE, [1] POECR5.IC1ADDMT0ZE
0x8C4D4 POE3 16-bit
  [n+8] POECR6.IC{n}ADDGPT23ZE (n=1..4), [5] POECR6.IC5ADDGPT01ZE, [3] POECR6.IC3ADDGPT01ZE, [2] POECR6.IC2ADDGPT01ZE, [1] POECR6.IC1ADDGPT01ZE
0x8C4D6 POE3 16-bit
  [12] ICSR4.POE10F, [9] ICSR4.POE10E, [8] ICSR4.PIE4, [1:0] ICSR4.POE10M
0x8C4D8 POE3 16-bit
  [12] ICSR5.POE11F, [9] ICSR5.POE11E, [8] ICSR5.PIE5, [1:0] ICSR5.POE11M
0x8C4DA POE3 16-bit
  [7] ALR1.OLSEN, [5] ALR1.OLSG2B, [4] ALR1.OLSG2A, [3] ALR1.OLSG1B, [2] ALR1.OLSG1A, [1] ALR1.OLSG0B, [0] ALR1.OLSG0A
0x8C4DC POE3 16-bit
  [12] ICSR6.OSTSTF, [9] ICSR6.OSTSTE
0x8C4E0 POE3
  [7:4] G0SELR.G0BSEL, [3:0] G0SELR.G0ASEL
0x8C4E1 POE3
  [7:4] G1SELR.G1BSEL, [3:0] G1SELR.G1ASEL
0x8C4E2 POE3
  [7:4] G2SELR.G2BSEL, [3:0] G2SELR.G2ASEL
0x8C4E3 POE3
  [7:4] G3SELR.G3BSEL, [3:0] G3SELR.G3ASEL
0x8C4E4 POE3
  [7:4] M0SELR1.M0BSEL, [3:0] M0SELR1.M0ASEL
0x8C4E5 POE3
  [7:4] M0SELR2.M0DSEL, [3:0] M0SELR2.M0CSEL
0x8C4E6 POE3
  [7:4] M3SELR.M3DSEL, [3:0] M3SELR.M3BSEL
0x8C4E7 POE3
  [7:4] M4SELR1.M4CSEL, [3:0] M4SELR1.M4ASEL
0x8C4E8 POE3
  [7:4] M4SELR2.M4DSEL, [3:0] M4SELR2.M4BSEL
0x8C4E9 POE3
  [2] MGSELR.M4G2SEL, [1] MGSELR.M4G1SEL, [0] MGSELR.M3G0SEL
0x8C500 TEMPS
  [7] TSCR.TSEN, [4] TSCR.TSOE
0x8C5C0 DA
  [1] DAADUSR.AMADSEL1
0x90200 CAN0 32-bit
  [31] MB[0]_ID.IDE, [30] MB[0]_ID.RTR, [28:18] MB[0]_ID.SID, [17:0] MB[0]_ID.EID
0x90210 CAN0 32-bit
  [31] MB[1]_ID.IDE, [30] MB[1]_ID.RTR, [28:18] MB[1]_ID.SID, [17:0] MB[1]_ID.EID
0x90220 CAN0 32-bit
  [31] MB[2]_ID.IDE, [30] MB[2]_ID.RTR, [28:18] MB[2]_ID.SID, [17:0] MB[2]_ID.EID
0x90230 CAN0 32-bit
  [31] MB[3]_ID.IDE, [30] MB[3]_ID.RTR, [28:18] MB[3]_ID.SID, [17:0] MB[3]_ID.EID
0x90240 CAN0 32-bit
  [31] MB[4]_ID.IDE, [30] MB[4]_ID.RTR, [28:18] MB[4]_ID.SID, [17:0] MB[4]_ID.EID
0x90250 CAN0 32-bit
  [31] MB[5]_ID.IDE, [30] MB[5]_ID.RTR, [28:18] MB[5]_ID.SID, [17:0] MB[5]_ID.EID
0x90260 CAN0 32-bit
  [31] MB[6]_ID.IDE, [30] MB[6]_ID.RTR, [28:18] MB[6]_ID.SID, [17:0] MB[6]_ID.EID
0x90270 CAN0 32-bit
  [31] MB[7]_ID.IDE, [30] MB[7]_ID.RTR, [28:18] MB[7]_ID.SID, [17:0] MB[7]_ID.EID
0x90280 CAN0 32-bit
  [31] MB[8]_ID.IDE, [30] MB[8]_ID.RTR, [28:18] MB[8]_ID.SID, [17:0] MB[8]_ID.EID
0x90290 CAN0 32-bit
  [31] MB[9]_ID.IDE, [30] MB[9]_ID.RTR, [28:18] MB[9]_ID.SID, [17:0] MB[9]_ID.EID
0x902A0 CAN0 32-bit
  [31] MB[10]_ID.IDE, [30] MB[10]_ID.RTR, [28:18] MB[10]_ID.SID, [17:0] MB[10]_ID.EID
# iorx71m register map
Registers are 8-bit, access not given, no defined reset value unless marked. A register's access mark holds for its fields unless they carry their own. Addresses are absolute; registers are grouped by the start of their names; [hi:lo] are bit positions; {n}, {i} and the like mark numbered series; 'fields as' and 'values as' point back to an identical list.

## SFR (part 2 of 4)
0x80000 SYSTEM 16-bit
  [0] MDMONR.MD
0x80002 SYSTEM 16-bit
  [5] MDSR.UBTS
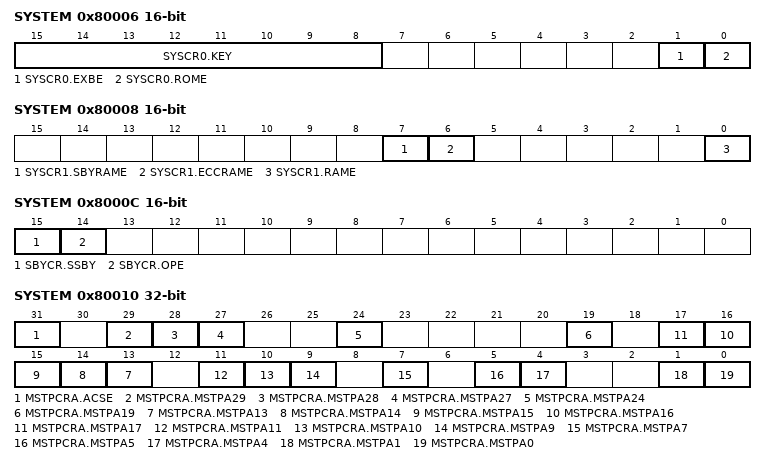
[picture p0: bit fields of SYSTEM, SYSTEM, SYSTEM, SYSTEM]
0x80006 SYSTEM 16-bit
  [15:8] SYSCR0.KEY, [1] SYSCR0.EXBE, [0] SYSCR0.ROME
0x80008 SYSTEM 16-bit
  [7] SYSCR1.SBYRAME, [6] SYSCR1.ECCRAME, [0] SYSCR1.RAME
0x8000C SYSTEM 16-bit
  [15] SBYCR.SSBY, [14] SBYCR.OPE
0x80010 SYSTEM 32-bit
  [31] MSTPCRA.ACSE, [29] MSTPCRA.MSTPA29, [28] MSTPCRA.MSTPA28, [27] MSTPCRA.MSTPA27, [24] MSTPCRA.MSTPA24, [19] MSTPCRA.MSTPA19, [n] MSTPCRA.MSTPA{n} (n=13..17), [11] MSTPCRA.MSTPA11, [10] MSTPCRA.MSTPA10, [9] MSTPCRA.MSTPA9, [7] MSTPCRA.MSTPA7, [5] MSTPCRA.MSTPA5, [4] MSTPCRA.MSTPA4, [1] MSTPCRA.MSTPA1, [0] MSTPCRA.MSTPA0
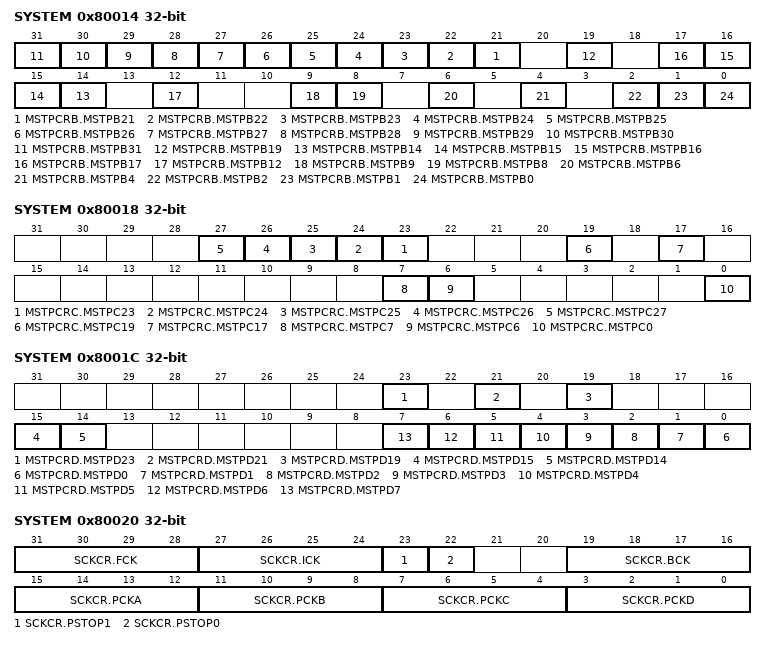
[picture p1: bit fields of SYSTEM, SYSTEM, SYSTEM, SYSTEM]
0x80014 SYSTEM 32-bit
  [n] MSTPCRB.MSTPB{n} (n=21..31), [19] MSTPCRB.MSTPB19, [n] MSTPCRB.MSTPB{n} (n=14..17), [12] MSTPCRB.MSTPB12, [9] MSTPCRB.MSTPB9, [8] MSTPCRB.MSTPB8, [6] MSTPCRB.MSTPB6, [4] MSTPCRB.MSTPB4, [2] MSTPCRB.MSTPB2, [1] MSTPCRB.MSTPB1, [0] MSTPCRB.MSTPB0
0x80018 SYSTEM 32-bit
  [n] MSTPCRC.MSTPC{n} (n=23..27), [19] MSTPCRC.MSTPC19, [17] MSTPCRC.MSTPC17, [7] MSTPCRC.MSTPC7, [6] MSTPCRC.MSTPC6, [0] MSTPCRC.MSTPC0
0x8001C SYSTEM 32-bit
  [23] MSTPCRD.MSTPD23, [21] MSTPCRD.MSTPD21, [19] MSTPCRD.MSTPD19, [15] MSTPCRD.MSTPD15, [14] MSTPCRD.MSTPD14, [n] MSTPCRD.MSTPD{n} (n=0..7)
0x80020 SYSTEM 32-bit
  [31:28] SCKCR.FCK, [27:24] SCKCR.ICK, [23] SCKCR.PSTOP1, [22] SCKCR.PSTOP0, [19:16] SCKCR.BCK, [15:12] SCKCR.PCKA, [11:8] SCKCR.PCKB, [7:4] SCKCR.PCKC, [3:0] SCKCR.PCKD
0x80024 SYSTEM 16-bit
  [7:4] SCKCR2.UCK
0x80026 SYSTEM 16-bit
  [10:8] SCKCR3.CKSEL
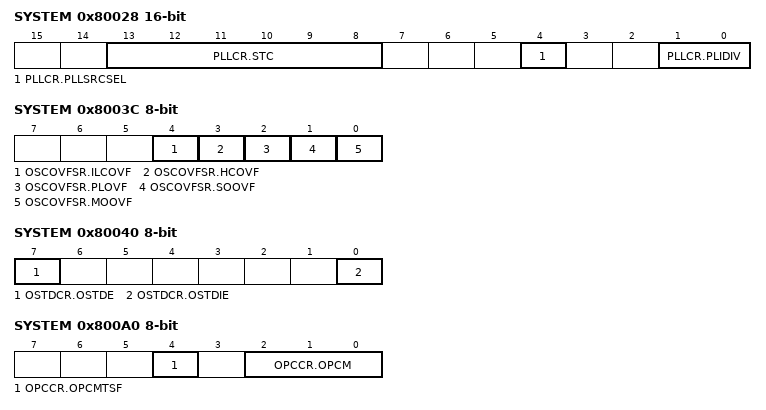
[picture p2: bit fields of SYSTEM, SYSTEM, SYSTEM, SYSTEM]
0x80028 SYSTEM 16-bit
  [13:8] PLLCR.STC, [4] PLLCR.PLLSRCSEL, [1:0] PLLCR.PLIDIV
0x8002A SYSTEM
  [0] PLLCR2.PLLEN
0x80030 SYSTEM
  [0] BCKCR.BCLKDIV
0x80032 SYSTEM
  [0] MOSCCR.MOSTP
0x80033 SYSTEM
  [0] SOSCCR.SOSTP
0x80034 SYSTEM
  [0] LOCOCR.LCSTP
0x80035 SYSTEM
  [0] ILOCOCR.ILCSTP
0x80036 SYSTEM
  [0] HOCOCR.HCSTP
0x80037 SYSTEM
  [1:0] HOCOCR2.HCFRQ
0x8003C SYSTEM
  [4] OSCOVFSR.ILCOVF, [3] OSCOVFSR.HCOVF, [2] OSCOVFSR.PLOVF, [1] OSCOVFSR.SOOVF, [0] OSCOVFSR.MOOVF
0x80040 SYSTEM
  [7] OSTDCR.OSTDE, [0] OSTDCR.OSTDIE
0x80041 SYSTEM
  [0] OSTDSR.OSTDF
0x800A0 SYSTEM
  [4] OPCCR.OPCMTSF, [2:0] OPCCR.OPCM
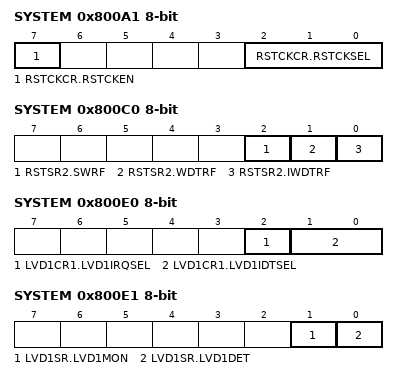
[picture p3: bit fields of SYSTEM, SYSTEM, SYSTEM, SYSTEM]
0x800A1 SYSTEM
  [7] RSTCKCR.RSTCKEN, [2:0] RSTCKCR.RSTCKSEL
0x800A2 SYSTEM
  [7:0] MOSCWTCR.MSTS
0x800A3 SYSTEM
  [7:0] SOSCWTCR.SSTS
0x800C0 SYSTEM
  [2] RSTSR2.SWRF, [1] RSTSR2.WDTRF, [0] RSTSR2.IWDTRF
0x800E0 SYSTEM
  [2] LVD1CR1.LVD1IRQSEL, [1:0] LVD1CR1.LVD1IDTSEL
0x800E1 SYSTEM
  [1] LVD1SR.LVD1MON, [0] LVD1SR.LVD1DET
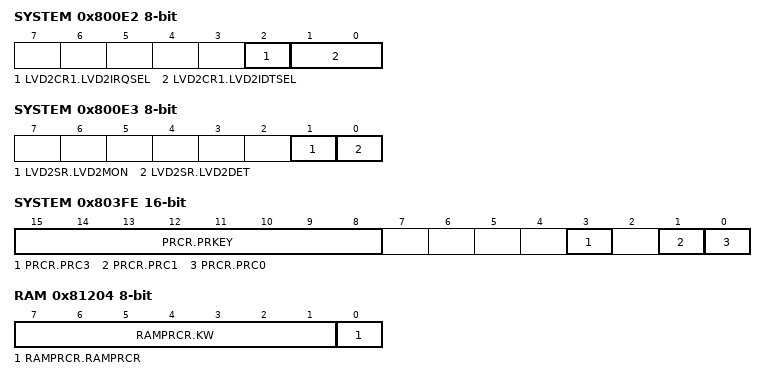
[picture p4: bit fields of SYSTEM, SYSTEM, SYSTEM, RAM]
0x800E2 SYSTEM
  [2] LVD2CR1.LVD2IRQSEL, [1:0] LVD2CR1.LVD2IDTSEL
0x800E3 SYSTEM
  [1] LVD2SR.LVD2MON, [0] LVD2SR.LVD2DET
0x803FE SYSTEM 16-bit
  [15:8] PRCR.PRKEY, [3] PRCR.PRC3, [1] PRCR.PRC1, [0] PRCR.PRC0
0x81200 RAM
  [1:0] RAMMODE.RAMMODE
0x81201 RAM
  [0] RAMSTS.RAMERR
0x81204 RAM
  [7:1] RAMPRCR.KW, [0] RAMPRCR.RAMPRCR
0x81208 RAM 32-bit
  [18:3] RAMECAD.READ
0x812C0 ECCRAM
  [1:0] ECCRAMMODE.RAMMOD
0x812C1 ECCRAM
  [0] ECCRAM2STS.ECC2ERR
0x812C2 ECCRAM
  [0] ECCRAM1STSEN.ECC1STSEN
0x812C3 ECCRAM
  [0] ECCRAM1STS.ECC1ERR
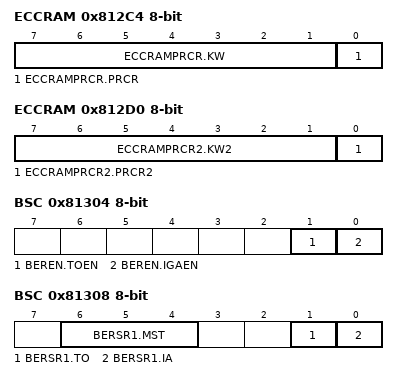
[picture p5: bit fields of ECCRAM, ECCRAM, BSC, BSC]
0x812C4 ECCRAM
  [7:1] ECCRAMPRCR.KW, [0] ECCRAMPRCR.PRCR
0x812C8 ECCRAM 32-bit
  [14:3] ECCRAM2ECAD.ECC2EAD
0x812CC ECCRAM 32-bit
  [14:3] ECCRAM1ECAD.ECC1EAD
0x812D0 ECCRAM
  [7:1] ECCRAMPRCR2.KW2, [0] ECCRAMPRCR2.PRCR2
0x812D4 ECCRAM
  [0] ECCRAMETST.TSTBYP
0x81300 BSC
  [0] BERCLR.STSCLR
0x81304 BSC
  [1] BEREN.TOEN, [0] BEREN.IGAEN
0x81308 BSC
  [6:4] BERSR1.MST, [1] BERSR1.TO, [0] BERSR1.IA
0x8130A BSC 16-bit
  [15:3] BERSR2.ADDR
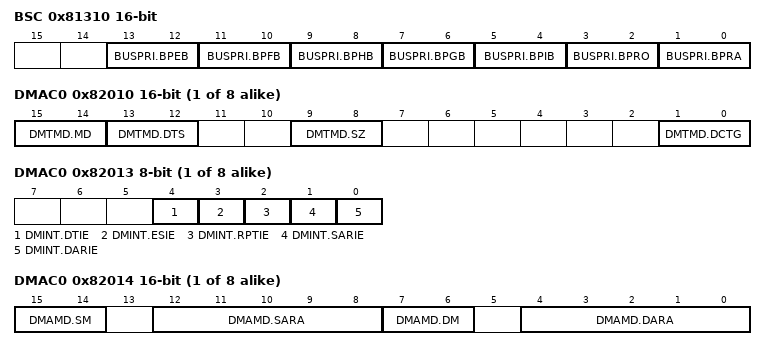
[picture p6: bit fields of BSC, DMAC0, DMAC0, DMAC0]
0x81310 BSC 16-bit
  [13:12] BUSPRI.BPEB, [11:10] BUSPRI.BPFB, [9:8] BUSPRI.BPHB, [7:6] BUSPRI.BPGB, [5:4] BUSPRI.BPIB, [3:2] BUSPRI.BPRO, [1:0] BUSPRI.BPRA
{0x82010+0x40*i} DMAC{i} 16-bit (i=0..7)
  [15:14] DMTMD.MD, [13:12] DMTMD.DTS, [9:8] DMTMD.SZ, [1:0] DMTMD.DCTG
{0x82013+0x40*i} DMAC{i} (i=0..7)
  [4] DMINT.DTIE, [3] DMINT.ESIE, [2] DMINT.RPTIE, [1] DMINT.SARIE, [0] DMINT.DARIE
{0x82014+0x40*i} DMAC{i} 16-bit (i=0..7)
  [15:14] DMAMD.SM, [12:8] DMAMD.SARA, [7:6] DMAMD.DM, [4:0] DMAMD.DARA
{0x8201C+0x40*i} DMAC{i} (i=0..7)
  [0] DMCNT.DTE
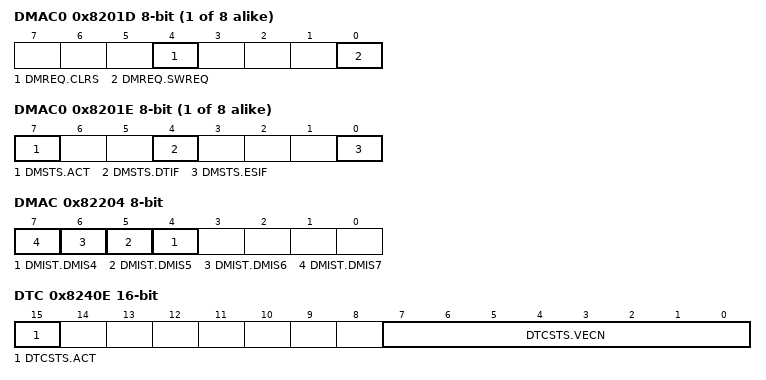
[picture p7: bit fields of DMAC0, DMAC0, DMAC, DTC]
{0x8201D+0x40*i} DMAC{i} (i=0..7)
  [4] DMREQ.CLRS, [0] DMREQ.SWREQ
{0x8201E+0x40*i} DMAC{i} (i=0..7)
  [7] DMSTS.ACT, [4] DMSTS.DTIF, [0] DMSTS.ESIF
{0x8201F+0x40*i} DMAC{i} (i=0..7)
  [0] DMCSL.DISEL
0x82200 DMAC
  [0] DMAST.DMST
0x82204 DMAC
  [n] DMIST.DMIS{n} (n=4..7)
0x82400 DTC
  [4] DTCCR.RRS
0x82408 DTC
  [0] DTCADMOD.SHORT
0x8240C DTC
  [0] DTCST.DTCST
0x8240E DTC 16-bit
  [15] DTCSTS.ACT, [7:0] DTCSTS.VECN
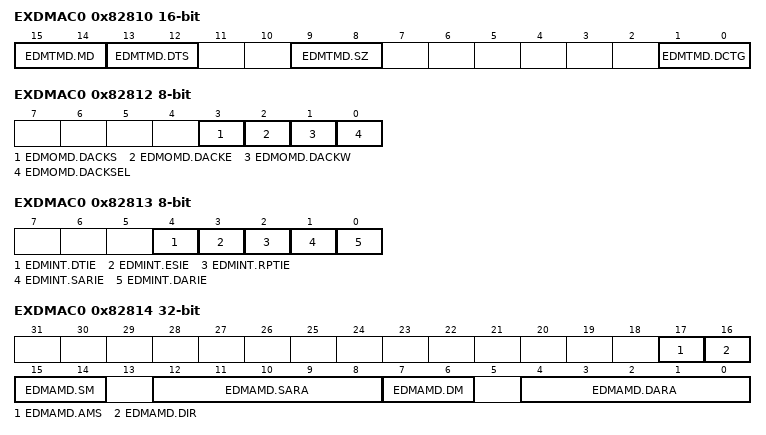
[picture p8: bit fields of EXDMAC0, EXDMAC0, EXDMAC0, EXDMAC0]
0x82810 EXDMAC0 16-bit
  [15:14] EDMTMD.MD, [13:12] EDMTMD.DTS, [9:8] EDMTMD.SZ, [1:0] EDMTMD.DCTG
0x82812 EXDMAC0
  [3] EDMOMD.DACKS, [2] EDMOMD.DACKE, [1] EDMOMD.DACKW, [0] EDMOMD.DACKSEL
0x82813 EXDMAC0
  [4] EDMINT.DTIE, [3] EDMINT.ESIE, [2] EDMINT.RPTIE, [1] EDMINT.SARIE, [0] EDMINT.DARIE
0x82814 EXDMAC0 32-bit
  [17] EDMAMD.AMS, [16] EDMAMD.DIR, [15:14] EDMAMD.SM, [12:8] EDMAMD.SARA, [7:6] EDMAMD.DM, [4:0] EDMAMD.DARA
0x8281C EXDMAC0
  [0] EDMCNT.DTE
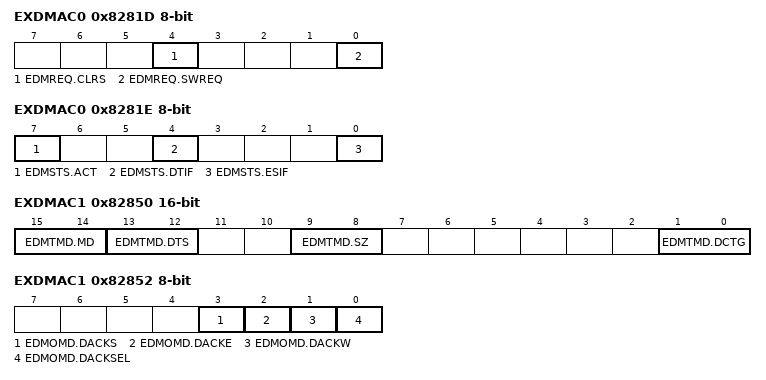
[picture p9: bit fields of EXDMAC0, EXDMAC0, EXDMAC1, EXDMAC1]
0x8281D EXDMAC0
  [4] EDMREQ.CLRS, [0] EDMREQ.SWREQ
0x8281E EXDMAC0
  [7] EDMSTS.ACT, [4] EDMSTS.DTIF, [0] EDMSTS.ESIF
0x82820 EXDMAC0
  [1:0] EDMRMD.DREQS
0x82821 EXDMAC0
  [0] EDMERF.EREQ
0x82822 EXDMAC0
  [0] EDMPRF.PREQ
0x82850 EXDMAC1 16-bit
  fields as EXDMAC0
0x82852 EXDMAC1
  [3] EDMOMD.DACKS, [2] EDMOMD.DACKE, [1] EDMOMD.DACKW, [0] EDMOMD.DACKSEL
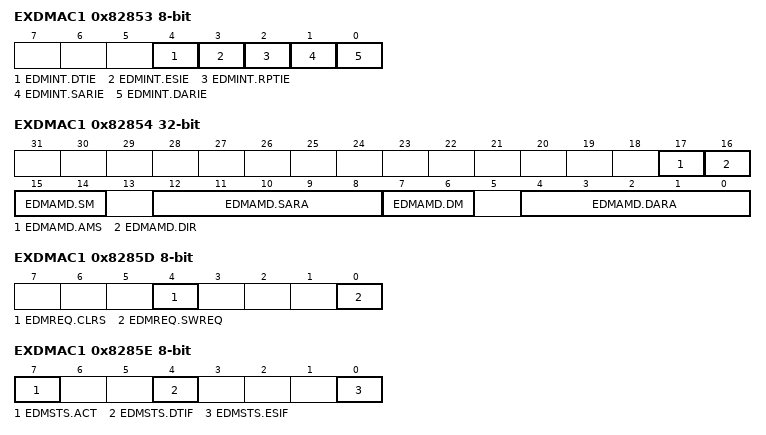
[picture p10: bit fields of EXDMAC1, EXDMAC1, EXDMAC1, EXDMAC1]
0x82853 EXDMAC1
  [4] EDMINT.DTIE, [3] EDMINT.ESIE, [2] EDMINT.RPTIE, [1] EDMINT.SARIE, [0] EDMINT.DARIE
0x82854 EXDMAC1 32-bit
  [17] EDMAMD.AMS, [16] EDMAMD.DIR, [15:14] EDMAMD.SM, [12:8] EDMAMD.SARA, [7:6] EDMAMD.DM, [4:0] EDMAMD.DARA
0x8285C EXDMAC1
  [0] EDMCNT.DTE
0x8285D EXDMAC1
  [4] EDMREQ.CLRS, [0] EDMREQ.SWREQ
0x8285E EXDMAC1
  [7] EDMSTS.ACT, [4] EDMSTS.DTIF, [0] EDMSTS.ESIF
0x82860 EXDMAC1
  [1:0] EDMRMD.DREQS
0x82861 EXDMAC1
  [0] EDMERF.EREQ
0x82862 EXDMAC1
  [0] EDMPRF.PREQ
0x82A00 EXDMAC
  [0] EDMAST.DMST
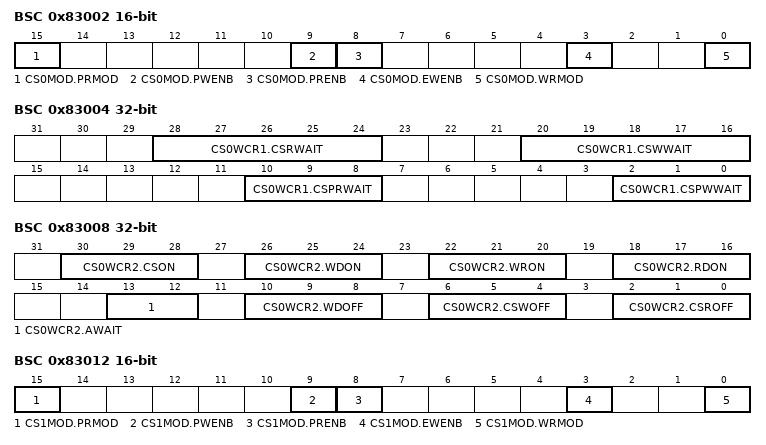
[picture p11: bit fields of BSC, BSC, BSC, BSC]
0x83002 BSC 16-bit
  [15] CS0MOD.PRMOD, [9] CS0MOD.PWENB, [8] CS0MOD.PRENB, [3] CS0MOD.EWENB, [0] CS0MOD.WRMOD
0x83004 BSC 32-bit
  [28:24] CS0WCR1.CSRWAIT, [20:16] CS0WCR1.CSWWAIT, [10:8] CS0WCR1.CSPRWAIT, [2:0] CS0WCR1.CSPWWAIT
0x83008 BSC 32-bit
  [30:28] CS0WCR2.CSON, [26:24] CS0WCR2.WDON, [22:20] CS0WCR2.WRON, [18:16] CS0WCR2.RDON, [13:12] CS0WCR2.AWAIT, [10:8] CS0WCR2.WDOFF, [6:4] CS0WCR2.CSWOFF, [2:0] CS0WCR2.CSROFF
0x83012 BSC 16-bit
  [15] CS1MOD.PRMOD, [9] CS1MOD.PWENB, [8] CS1MOD.PRENB, [3] CS1MOD.EWENB, [0] CS1MOD.WRMOD
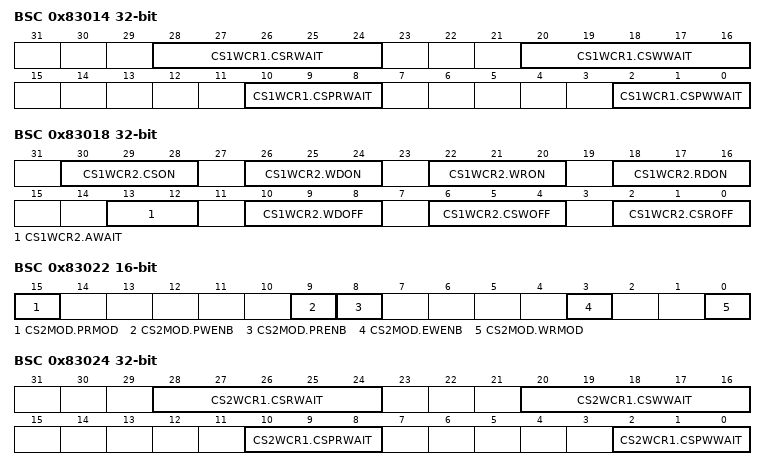
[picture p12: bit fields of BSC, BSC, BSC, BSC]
0x83014 BSC 32-bit
  [28:24] CS1WCR1.CSRWAIT, [20:16] CS1WCR1.CSWWAIT, [10:8] CS1WCR1.CSPRWAIT, [2:0] CS1WCR1.CSPWWAIT
0x83018 BSC 32-bit
  [30:28] CS1WCR2.CSON, [26:24] CS1WCR2.WDON, [22:20] CS1WCR2.WRON, [18:16] CS1WCR2.RDON, [13:12] CS1WCR2.AWAIT, [10:8] CS1WCR2.WDOFF, [6:4] CS1WCR2.CSWOFF, [2:0] CS1WCR2.CSROFF
0x83022 BSC 16-bit
  [15] CS2MOD.PRMOD, [9] CS2MOD.PWENB, [8] CS2MOD.PRENB, [3] CS2MOD.EWENB, [0] CS2MOD.WRMOD
0x83024 BSC 32-bit
  [28:24] CS2WCR1.CSRWAIT, [20:16] CS2WCR1.CSWWAIT, [10:8] CS2WCR1.CSPRWAIT, [2:0] CS2WCR1.CSPWWAIT
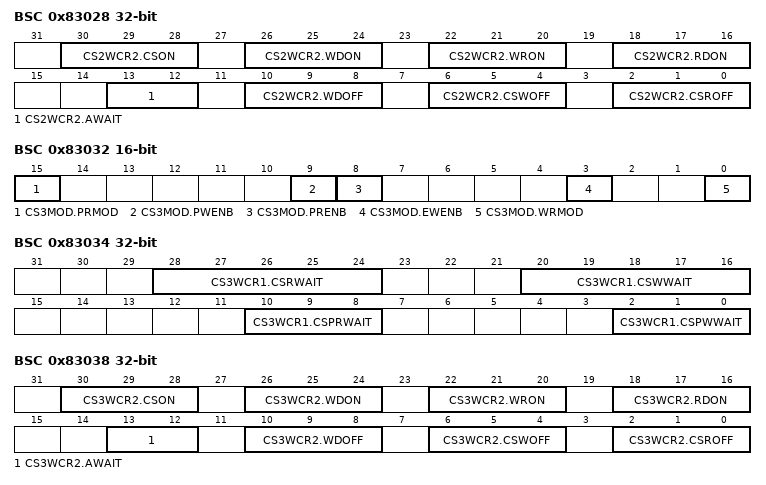
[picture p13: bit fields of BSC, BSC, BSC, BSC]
0x83028 BSC 32-bit
  [30:28] CS2WCR2.CSON, [26:24] CS2WCR2.WDON, [22:20] CS2WCR2.WRON, [18:16] CS2WCR2.RDON, [13:12] CS2WCR2.AWAIT, [10:8] CS2WCR2.WDOFF, [6:4] CS2WCR2.CSWOFF, [2:0] CS2WCR2.CSROFF
0x83032 BSC 16-bit
  [15] CS3MOD.PRMOD, [9] CS3MOD.PWENB, [8] CS3MOD.PRENB, [3] CS3MOD.EWENB, [0] CS3MOD.WRMOD
0x83034 BSC 32-bit
  [28:24] CS3WCR1.CSRWAIT, [20:16] CS3WCR1.CSWWAIT, [10:8] CS3WCR1.CSPRWAIT, [2:0] CS3WCR1.CSPWWAIT
0x83038 BSC 32-bit
  [30:28] CS3WCR2.CSON, [26:24] CS3WCR2.WDON, [22:20] CS3WCR2.WRON, [18:16] CS3WCR2.RDON, [13:12] CS3WCR2.AWAIT, [10:8] CS3WCR2.WDOFF, [6:4] CS3WCR2.CSWOFF, [2:0] CS3WCR2.CSROFF
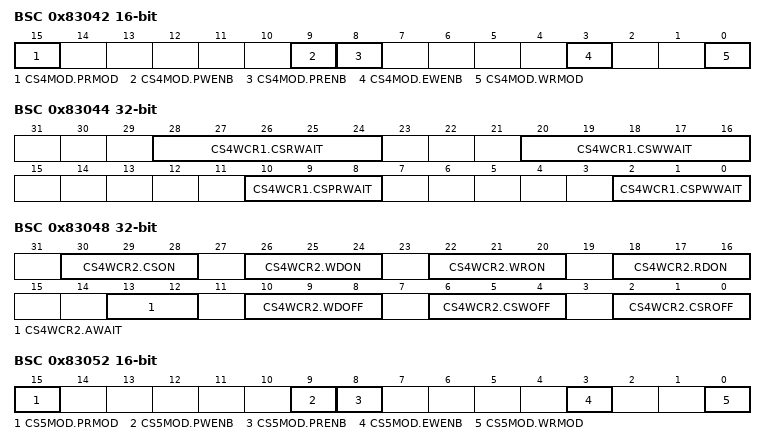
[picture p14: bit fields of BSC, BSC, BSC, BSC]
0x83042 BSC 16-bit
  [15] CS4MOD.PRMOD, [9] CS4MOD.PWENB, [8] CS4MOD.PRENB, [3] CS4MOD.EWENB, [0] CS4MOD.WRMOD
0x83044 BSC 32-bit
  [28:24] CS4WCR1.CSRWAIT, [20:16] CS4WCR1.CSWWAIT, [10:8] CS4WCR1.CSPRWAIT, [2:0] CS4WCR1.CSPWWAIT
0x83048 BSC 32-bit
  [30:28] CS4WCR2.CSON, [26:24] CS4WCR2.WDON, [22:20] CS4WCR2.WRON, [18:16] CS4WCR2.RDON, [13:12] CS4WCR2.AWAIT, [10:8] CS4WCR2.WDOFF, [6:4] CS4WCR2.CSWOFF, [2:0] CS4WCR2.CSROFF
0x83052 BSC 16-bit
  [15] CS5MOD.PRMOD, [9] CS5MOD.PWENB, [8] CS5MOD.PRENB, [3] CS5MOD.EWENB, [0] CS5MOD.WRMOD
0x83054 BSC 32-bit
  [28:24] CS5WCR1.CSRWAIT, [20:16] CS5WCR1.CSWWAIT, [10:8] CS5WCR1.CSPRWAIT, [2:0] CS5WCR1.CSPWWAIT
0x83058 BSC 32-bit
  [30:28] CS5WCR2.CSON, [26:24] CS5WCR2.WDON, [22:20] CS5WCR2.WRON, [18:16] CS5WCR2.RDON, [13:12] CS5WCR2.AWAIT, [10:8] CS5WCR2.WDOFF, [6:4] CS5WCR2.CSWOFF, [2:0] CS5WCR2.CSROFF
0x83062 BSC 16-bit
  [15] CS6MOD.PRMOD, [9] CS6MOD.PWENB, [8] CS6MOD.PRENB, [3] CS6MOD.EWENB, [0] CS6MOD.WRMOD
0x83064 BSC 32-bit
  [28:24] CS6WCR1.CSRWAIT, [20:16] CS6WCR1.CSWWAIT, [10:8] CS6WCR1.CSPRWAIT, [2:0] CS6WCR1.CSPWWAIT
0x83068 BSC 32-bit
  [30:28] CS6WCR2.CSON, [26:24] CS6WCR2.WDON, [22:20] CS6WCR2.WRON, [18:16] CS6WCR2.RDON, [13:12] CS6WCR2.AWAIT, [10:8] CS6WCR2.WDOFF, [6:4] CS6WCR2.CSWOFF, [2:0] CS6WCR2.CSROFF
0x83072 BSC 16-bit
  [15] CS7MOD.PRMOD, [9] CS7MOD.PWENB, [8] CS7MOD.PRENB, [3] CS7MOD.EWENB, [0] CS7MOD.WRMOD
0x83074 BSC 32-bit
  [28:24] CS7WCR1.CSRWAIT, [20:16] CS7WCR1.CSWWAIT, [10:8] CS7WCR1.CSPRWAIT, [2:0] CS7WCR1.CSPWWAIT
0x83078 BSC 32-bit
  [30:28] CS7WCR2.CSON, [26:24] CS7WCR2.WDON, [22:20] CS7WCR2.WRON, [18:16] CS7WCR2.RDON, [13:12] CS7WCR2.AWAIT, [10:8] CS7WCR2.WDOFF, [6:4] CS7WCR2.CSWOFF, [2:0] CS7WCR2.CSROFF
0x83802 BSC 16-bit
  [12] CS0CR.MPXEN, [8] CS0CR.EMODE, [5:4] CS0CR.BSIZE, [0] CS0CR.EXENB
0x8380A BSC 16-bit
  [11:8] CS0REC.WRCV, [3:0] CS0REC.RRCV
0x83812 BSC 16-bit
  [12] CS1CR.MPXEN, [8] CS1CR.EMODE, [5:4] CS1CR.BSIZE, [0] CS1CR.EXENB
0x8381A BSC 16-bit
  [11:8] CS1REC.WRCV, [3:0] CS1REC.RRCV
0x83822 BSC 16-bit
  [12] CS2CR.MPXEN, [8] CS2CR.EMODE, [5:4] CS2CR.BSIZE, [0] CS2CR.EXENB
0x8382A BSC 16-bit
  [11:8] CS2REC.WRCV, [3:0] CS2REC.RRCV
0x83832 BSC 16-bit
  [12] CS3CR.MPXEN, [8] CS3CR.EMODE, [5:4] CS3CR.BSIZE, [0] CS3CR.EXENB
0x8383A BSC 16-bit
  [11:8] CS3REC.WRCV, [3:0] CS3REC.RRCV
0x83842 BSC 16-bit
  [12] CS4CR.MPXEN, [8] CS4CR.EMODE, [5:4] CS4CR.BSIZE, [0] CS4CR.EXENB
0x8384A BSC 16-bit
  [11:8] CS4REC.WRCV, [3:0] CS4REC.RRCV
0x83852 BSC 16-bit
  [12] CS5CR.MPXEN, [8] CS5CR.EMODE, [5:4] CS5CR.BSIZE, [0] CS5CR.EXENB
0x8385A BSC 16-bit
  [11:8] CS5REC.WRCV, [3:0] CS5REC.RRCV
0x83862 BSC 16-bit
  [12] CS6CR.MPXEN, [8] CS6CR.EMODE, [5:4] CS6CR.BSIZE, [0] CS6CR.EXENB
0x8386A BSC 16-bit
  [11:8] CS6REC.WRCV, [3:0] CS6REC.RRCV
0x83872 BSC 16-bit
  [12] CS7CR.MPXEN, [8] CS7CR.EMODE, [5:4] CS7CR.BSIZE, [0] CS7CR.EXENB
0x8387A BSC 16-bit
  [11:8] CS7REC.WRCV, [3:0] CS7REC.RRCV
0x83880 BSC 16-bit
  [n+8] CSRECEN.RCVENM{n} (n=0..7), [n] CSRECEN.RCVEN{n} (n=0..7)
0x83C00 BSC
  [5:4] SDCCR.BSIZE, [0] SDCCR.EXENB
0x83C01 BSC
  [0] SDCMOD.EMODE
0x83C02 BSC
  [0] SDAMOD.BE
0x83C10 BSC
  [0] SDSELF.SFEN
0x83C14 BSC 16-bit
  [15:12] SDRFCR.REFW, [11:0] SDRFCR.RFC
0x83C16 BSC
  [0] SDRFEN.RFEN
0x83C20 BSC
  [0] SDICR.INIRQ
0x83C24 BSC 16-bit
  [10:8] SDIR.PRC, [7:4] SDIR.ARFC, [3:0] SDIR.ARFI
0x83C40 BSC
  [1:0] SDADR.MXC
0x83C44 BSC 32-bit
  [18:16] SDTR.RAS, [13:12] SDTR.RCD, [11:9] SDTR.RP, [8] SDTR.WR, [2:0] SDTR.CL
0x83C48 BSC 16-bit
  [14:0] SDMOD.MR
0x83C50 BSC
  [4] SDSR.SRFST, [3] SDSR.INIST, [0] SDSR.MRSST
0x86400 MPU 32-bit
  [31:4] RSPAGE0.RSPN
0x86404 MPU 32-bit
  [31:4] REPAGE0.REPN, [3:1] REPAGE0.UAC, [0] REPAGE0.V
0x86408 MPU 32-bit
  [31:4] RSPAGE1.RSPN
0x8640C MPU 32-bit
  [31:4] REPAGE1.REPN, [3:1] REPAGE1.UAC, [0] REPAGE1.V
0x86410 MPU 32-bit
  [31:4] RSPAGE2.RSPN
0x86414 MPU 32-bit
  [31:4] REPAGE2.REPN, [3:1] REPAGE2.UAC, [0] REPAGE2.V
0x86418 MPU 32-bit
  [31:4] RSPAGE3.RSPN
0x8641C MPU 32-bit
  [31:4] REPAGE3.REPN, [3:1] REPAGE3.UAC, [0] REPAGE3.V
0x86420 MPU 32-bit
  [31:4] RSPAGE4.RSPN
0x86424 MPU 32-bit
  [31:4] REPAGE4.REPN, [3:1] REPAGE4.UAC, [0] REPAGE4.V
0x86428 MPU 32-bit
  [31:4] RSPAGE5.RSPN
0x8642C MPU 32-bit
  [31:4] REPAGE5.REPN, [3:1] REPAGE5.UAC, [0] REPAGE5.V
0x86430 MPU 32-bit
  [31:4] RSPAGE6.RSPN
0x86434 MPU 32-bit
  [31:4] REPAGE6.REPN, [3:1] REPAGE6.UAC, [0] REPAGE6.V
0x86438 MPU 32-bit
  [31:4] RSPAGE7.RSPN
0x8643C MPU 32-bit
  [31:4] REPAGE7.REPN, [3:1] REPAGE7.UAC, [0] REPAGE7.V
0x86500 MPU 32-bit
  [0] MPEN.MPEN
0x86504 MPU 32-bit
  [3:1] MPBAC.UBAC
0x86508 MPU 32-bit
  [0] MPECLR.CLR
0x8650C MPU 32-bit
  [2] MPESTS.DRW, [1] MPESTS.DMPER, [0] MPESTS.IMPER
0x86514 MPU 32-bit
  [31:0] MPDEA.DEA
0x86520 MPU 32-bit
  [31:0] MPSA.SA
0x86524 MPU 16-bit
  [0] MPOPS.S
0x86526 MPU 16-bit
  [0] MPOPI.INV
0x86528 MPU 32-bit
  [23:16] MHITI.HITI, [3:1] MHITI.UHACI
0x8652C MPU 32-bit
  [23:16] MHITD.HITD, [3:1] MHITD.UHACD
0x86610 SYSTEM 32-bit
  [0] MEMWAIT.MEMWAIT
0x87010 ICU
  [0] IR016.IR
0x87011 ICU
  [0] IR017.IR
0x87012 ICU
  [0] IR018.IR
0x87013 ICU
  [0] IR019.IR
0x87014 ICU
  [0] IR020.IR
0x87015 ICU
  [0] IR021.IR
0x87016 ICU
  [0] IR022.IR
0x87017 ICU
  [0] IR023.IR
0x87018 ICU
  [0] IR024.IR
0x87019 ICU
  [0] IR025.IR
0x8701A ICU
  [0] IR026.IR
0x8701B ICU
  [0] IR027.IR
0x8701C ICU
  [0] IR028.IR
0x8701D ICU
  [0] IR029.IR
0x8701E ICU
  [0] IR030.IR
0x8701F ICU
  [0] IR031.IR
0x87020 ICU
  [0] IR032.IR
0x87021 ICU
  [0] IR033.IR
0x87022 ICU
  [0] IR034.IR
0x87023 ICU
  [0] IR035.IR
0x87024 ICU
  [0] IR036.IR
0x87025 ICU
  [0] IR037.IR
0x87026 ICU
  [0] IR038.IR
0x87027 ICU
  [0] IR039.IR
0x87028 ICU
  [0] IR040.IR
0x87029 ICU
  [0] IR041.IR
0x8702A ICU
  [0] IR042.IR
0x8702B ICU
  [0] IR043.IR
0x8702C ICU
  [0] IR044.IR
0x8702D ICU
  [0] IR045.IR
0x8702E ICU
  [0] IR046.IR
0x8702F ICU
  [0] IR047.IR
0x87030 ICU
  [0] IR048.IR
0x87031 ICU
  [0] IR049.IR
0x87032 ICU
  [0] IR050.IR
0x87033 ICU
  [0] IR051.IR
0x87034 ICU
  [0] IR052.IR
0x87035 ICU
  [0] IR053.IR
0x87036 ICU
  [0] IR054.IR
0x87037 ICU
  [0] IR055.IR
0x87038 ICU
  [0] IR056.IR
0x87039 ICU
  [0] IR057.IR
0x8703A ICU
  [0] IR058.IR
0x8703B ICU
  [0] IR059.IR
0x8703C ICU
  [0] IR060.IR
0x8703D ICU
  [0] IR061.IR
0x8703E ICU
  [0] IR062.IR
0x8703F ICU
  [0] IR063.IR
0x87040 ICU
  [0] IR064.IR
0x87041 ICU
  [0] IR065.IR
0x87042 ICU
  [0] IR066.IR
0x87043 ICU
  [0] IR067.IR
0x87044 ICU
  [0] IR068.IR
0x87045 ICU
  [0] IR069.IR
0x87046 ICU
  [0] IR070.IR
0x87047 ICU
  [0] IR071.IR
0x87048 ICU
  [0] IR072.IR
0x87049 ICU
  [0] IR073.IR
0x8704A ICU
  [0] IR074.IR
0x8704B ICU
  [0] IR075.IR
0x8704C ICU
  [0] IR076.IR
0x8704D ICU
  [0] IR077.IR
0x8704E ICU
  [0] IR078.IR
0x8704F ICU
  [0] IR079.IR
0x87050 ICU
  [0] IR080.IR
0x87051 ICU
  [0] IR081.IR
0x87052 ICU
  [0] IR082.IR
0x87053 ICU
  [0] IR083.IR
0x87054 ICU
  [0] IR084.IR
0x87055 ICU
  [0] IR085.IR
0x87056 ICU
  [0] IR086.IR
0x87057 ICU
  [0] IR087.IR
0x87058 ICU
  [0] IR088.IR
0x87059 ICU
  [0] IR089.IR
0x8705A ICU
  [0] IR090.IR
0x8705B ICU
  [0] IR091.IR
0x8705C ICU
  [0] IR092.IR
0x8705D ICU
  [0] IR093.IR
0x8705E ICU
  [0] IR094.IR
0x8705F ICU
  [0] IR095.IR
0x87060 ICU
  [0] IR096.IR
0x87061 ICU
  [0] IR097.IR
0x87062 ICU
  [0] IR098.IR
0x87063 ICU
  [0] IR099.IR
0x87064 ICU
  [0] IR100.IR
0x87065 ICU
  [0] IR101.IR
0x87066 ICU
  [0] IR102.IR
0x87067 ICU
  [0] IR103.IR
0x87068 ICU
  [0] IR104.IR
0x87069 ICU
  [0] IR105.IR
0x8706A ICU
  [0] IR106.IR
0x8706B ICU
  [0] IR107.IR
0x8706C ICU
  [0] IR108.IR
0x8706D ICU
  [0] IR109.IR
0x8706E ICU
  [0] IR110.IR
0x8706F ICU
  [0] IR111.IR
0x87070 ICU
  [0] IR112.IR
0x87071 ICU
  [0] IR113.IR
0x87072 ICU
  [0] IR114.IR
0x87073 ICU
  [0] IR115.IR
0x87074 ICU
  [0] IR116.IR
0x87075 ICU
  [0] IR117.IR
0x87076 ICU
  [0] IR118.IR
0x87077 ICU
  [0] IR119.IR
0x87078 ICU
  [0] IR120.IR
0x87079 ICU
  [0] IR121.IR
0x8707A ICU
  [0] IR122.IR
0x8707B ICU
  [0] IR123.IR
0x8707C ICU
  [0] IR124.IR
0x8707D ICU
  [0] IR125.IR
0x8707E ICU
  [0] IR126.IR
0x8707F ICU
  [0] IR127.IR
0x87080 ICU
  [0] IR128.IR
0x87081 ICU
  [0] IR129.IR
0x87082 ICU
  [0] IR130.IR
0x87083 ICU
  [0] IR131.IR
0x87084 ICU
  [0] IR132.IR
0x87085 ICU
  [0] IR133.IR
0x87086 ICU
  [0] IR134.IR
0x87087 ICU
  [0] IR135.IR
0x87088 ICU
  [0] IR136.IR
0x87089 ICU
  [0] IR137.IR
0x8708A ICU
  [0] IR138.IR
0x8708B ICU
  [0] IR139.IR
0x8708C ICU
  [0] IR140.IR
0x8708D ICU
  [0] IR141.IR
0x8708E ICU
  [0] IR142.IR
0x8708F ICU
  [0] IR143.IR
0x87090 ICU
  [0] IR144.IR
0x87091 ICU
  [0] IR145.IR
0x87092 ICU
  [0] IR146.IR
0x87093 ICU
  [0] IR147.IR
0x87094 ICU
  [0] IR148.IR
0x87095 ICU
  [0] IR149.IR
0x87096 ICU
  [0] IR150.IR
0x87097 ICU
  [0] IR151.IR
0x87098 ICU
  [0] IR152.IR
0x87099 ICU
  [0] IR153.IR
0x8709A ICU
  [0] IR154.IR
0x8709B ICU
  [0] IR155.IR
0x8709C ICU
  [0] IR156.IR
0x8709D ICU
  [0] IR157.IR
0x8709E ICU
  [0] IR158.IR
0x8709F ICU
  [0] IR159.IR
0x870A0 ICU
  [0] IR160.IR
0x870A1 ICU
  [0] IR161.IR
0x870A2 ICU
  [0] IR162.IR
0x870A3 ICU
  [0] IR163.IR
0x870A4 ICU
  [0] IR164.IR
0x870A5 ICU
  [0] IR165.IR
0x870A6 ICU
  [0] IR166.IR
0x870A7 ICU
  [0] IR167.IR
0x870A8 ICU
  [0] IR168.IR
0x870A9 ICU
  [0] IR169.IR
0x870AA ICU
  [0] IR170.IR
0x870AB ICU
  [0] IR171.IR
0x870AC ICU
  [0] IR172.IR
0x870AD ICU
  [0] IR173.IR
0x870AE ICU
  [0] IR174.IR
0x870AF ICU
  [0] IR175.IR
0x870B0 ICU
  [0] IR176.IR
0x870B1 ICU
  [0] IR177.IR
0x870B2 ICU
  [0] IR178.IR
0x870B3 ICU
  [0] IR179.IR
0x870B4 ICU
  [0] IR180.IR
0x870B5 ICU
  [0] IR181.IR
0x870B6 ICU
  [0] IR182.IR
0x870B7 ICU
  [0] IR183.IR
0x870B8 ICU
  [0] IR184.IR
0x870B9 ICU
  [0] IR185.IR
0x870BA ICU
  [0] IR186.IR
0x870BB ICU
  [0] IR187.IR
0x870BC ICU
  [0] IR188.IR
0x870BD ICU
  [0] IR189.IR
0x870BE ICU
  [0] IR190.IR
0x870BF ICU
  [0] IR191.IR
0x870C0 ICU
  [0] IR192.IR
0x870C1 ICU
  [0] IR193.IR
0x870C2 ICU
  [0] IR194.IR
0x870C3 ICU
  [0] IR195.IR
0x870C4 ICU
  [0] IR196.IR
0x870C5 ICU
  [0] IR197.IR
0x870C6 ICU
  [0] IR198.IR
0x870C7 ICU
  [0] IR199.IR
0x870C8 ICU
  [0] IR200.IR
0x870C9 ICU
  [0] IR201.IR
0x870CA ICU
  [0] IR202.IR
0x870CB ICU
  [0] IR203.IR
0x870CC ICU
  [0] IR204.IR
0x870CD ICU
  [0] IR205.IR
0x870CE ICU
  [0] IR206.IR
0x870CF ICU
  [0] IR207.IR
0x870D0 ICU
  [0] IR208.IR
0x870D1 ICU
  [0] IR209.IR
0x870D2 ICU
  [0] IR210.IR
0x870D3 ICU
  [0] IR211.IR
0x870D4 ICU
  [0] IR212.IR
0x870D5 ICU
  [0] IR213.IR
0x870D6 ICU
  [0] IR214.IR
0x870D7 ICU
  [0] IR215.IR
0x870D8 ICU
  [0] IR216.IR
0x870D9 ICU
  [0] IR217.IR
0x870DA ICU
  [0] IR218.IR
0x870DB ICU
  [0] IR219.IR
0x870DC ICU
  [0] IR220.IR
0x870DD ICU
  [0] IR221.IR
0x870DE ICU
  [0] IR222.IR
0x870DF ICU
  [0] IR223.IR
0x870E0 ICU
  [0] IR224.IR
0x870E1 ICU
  [0] IR225.IR
0x870E2 ICU
  [0] IR226.IR
0x870E3 ICU
  [0] IR227.IR
0x870E4 ICU
  [0] IR228.IR
0x870E5 ICU
  [0] IR229.IR
0x870E6 ICU
  [0] IR230.IR
0x870E7 ICU
  [0] IR231.IR
0x870E8 ICU
  [0] IR232.IR
0x870E9 ICU
  [0] IR233.IR
0x870EA ICU
  [0] IR234.IR
0x870EB ICU
  [0] IR235.IR
0x870EC ICU
  [0] IR236.IR
0x870ED ICU
  [0] IR237.IR
0x870EE ICU
  [0] IR238.IR
0x870EF ICU
  [0] IR239.IR
0x870F0 ICU
  [0] IR240.IR
0x870F1 ICU
  [0] IR241.IR
0x870F2 ICU
  [0] IR242.IR
0x870F3 ICU
  [0] IR243.IR
0x870F4 ICU
  [0] IR244.IR
0x870F5 ICU
  [0] IR245.IR
0x870F6 ICU
  [0] IR246.IR
0x870F7 ICU
  [0] IR247.IR
0x870F8 ICU
  [0] IR248.IR
0x870F9 ICU
  [0] IR249.IR
0x870FA ICU
  [0] IR250.IR
0x870FB ICU
  [0] IR251.IR
0x870FC ICU
  [0] IR252.IR
0x870FD ICU
  [0] IR253.IR
0x870FE ICU
  [0] IR254.IR
0x870FF ICU
  [0] IR255.IR
0x8711A ICU
  [0] DTCER026.DTCE
0x8711B ICU
  [0] DTCER027.DTCE
0x8711C ICU
  [0] DTCER028.DTCE
0x8711D ICU
  [0] DTCER029.DTCE
0x8711E ICU
  [0] DTCER030.DTCE
0x8711F ICU
  [0] DTCER031.DTCE
0x87120 ICU
  [0] DTCER032.DTCE
0x87121 ICU
  [0] DTCER033.DTCE
0x87122 ICU
  [0] DTCER034.DTCE
0x87123 ICU
  [0] DTCER035.DTCE
0x87124 ICU
  [0] DTCER036.DTCE
0x87125 ICU
  [0] DTCER037.DTCE
0x87126 ICU
  [0] DTCER038.DTCE
0x87127 ICU
  [0] DTCER039.DTCE
0x87128 ICU
  [0] DTCER040.DTCE
0x87129 ICU
  [0] DTCER041.DTCE
0x8712A ICU
  [0] DTCER042.DTCE
0x8712B ICU
  [0] DTCER043.DTCE
0x8712C ICU
  [0] DTCER044.DTCE
0x8712D ICU
  [0] DTCER045.DTCE
0x8712E ICU
  [0] DTCER046.DTCE
0x8712F ICU
  [0] DTCER047.DTCE
0x87130 ICU
  [0] DTCER048.DTCE
0x87131 ICU
  [0] DTCER049.DTCE
0x87132 ICU
  [0] DTCER050.DTCE
0x87133 ICU
  [0] DTCER051.DTCE
0x87134 ICU
  [0] DTCER052.DTCE
0x87135 ICU
  [0] DTCER053.DTCE
0x87136 ICU
  [0] DTCER054.DTCE
0x87137 ICU
  [0] DTCER055.DTCE
0x87138 ICU
  [0] DTCER056.DTCE
0x87139 ICU
  [0] DTCER057.DTCE
0x8713A ICU
  [0] DTCER058.DTCE
0x8713B ICU
  [0] DTCER059.DTCE
0x8713C ICU
  [0] DTCER060.DTCE
0x8713D ICU
  [0] DTCER061.DTCE
0x8713E ICU
  [0] DTCER062.DTCE
0x8713F ICU
  [0] DTCER063.DTCE
0x87140 ICU
  [0] DTCER064.DTCE
0x87141 ICU
  [0] DTCER065.DTCE
0x87142 ICU
  [0] DTCER066.DTCE
0x87143 ICU
  [0] DTCER067.DTCE
0x87144 ICU
  [0] DTCER068.DTCE
0x87145 ICU
  [0] DTCER069.DTCE
0x87146 ICU
  [0] DTCER070.DTCE
0x87147 ICU
  [0] DTCER071.DTCE
0x87148 ICU
  [0] DTCER072.DTCE
0x87149 ICU
  [0] DTCER073.DTCE
0x8714A ICU
  [0] DTCER074.DTCE
0x8714B ICU
  [0] DTCER075.DTCE
0x8714C ICU
  [0] DTCER076.DTCE
0x8714D ICU
  [0] DTCER077.DTCE
0x8714E ICU
  [0] DTCER078.DTCE
0x8714F ICU
  [0] DTCER079.DTCE
0x87150 ICU
  [0] DTCER080.DTCE
0x87151 ICU
  [0] DTCER081.DTCE
0x87152 ICU
  [0] DTCER082.DTCE
0x87153 ICU
  [0] DTCER083.DTCE
0x87154 ICU
  [0] DTCER084.DTCE
0x87155 ICU
  [0] DTCER085.DTCE
0x87156 ICU
  [0] DTCER086.DTCE
0x87157 ICU
  [0] DTCER087.DTCE
0x87158 ICU
  [0] DTCER088.DTCE
0x87159 ICU
  [0] DTCER089.DTCE
0x8715A ICU
  [0] DTCER090.DTCE
0x8715B ICU
  [0] DTCER091.DTCE
0x8715C ICU
  [0] DTCER092.DTCE
0x8715D ICU
  [0] DTCER093.DTCE
0x8715E ICU
  [0] DTCER094.DTCE
0x8715F ICU
  [0] DTCER095.DTCE
0x87160 ICU
  [0] DTCER096.DTCE
0x87161 ICU
  [0] DTCER097.DTCE
0x87162 ICU
  [0] DTCER098.DTCE
0x87163 ICU
  [0] DTCER099.DTCE
0x87164 ICU
  [0] DTCER100.DTCE
0x87165 ICU
  [0] DTCER101.DTCE
0x87166 ICU
  [0] DTCER102.DTCE
0x87167 ICU
  [0] DTCER103.DTCE
0x87168 ICU
  [0] DTCER104.DTCE
0x87169 ICU
  [0] DTCER105.DTCE
0x8716A ICU
  [0] DTCER106.DTCE
0x8716B ICU
  [0] DTCER107.DTCE
0x8716C ICU
  [0] DTCER108.DTCE
0x8716D ICU
  [0] DTCER109.DTCE
0x8716E ICU
  [0] DTCER110.DTCE
0x8716F ICU
  [0] DTCER111.DTCE
0x87170 ICU
  [0] DTCER112.DTCE
0x87171 ICU
  [0] DTCER113.DTCE
0x87172 ICU
  [0] DTCER114.DTCE
0x87173 ICU
  [0] DTCER115.DTCE
0x87174 ICU
  [0] DTCER116.DTCE
0x87175 ICU
  [0] DTCER117.DTCE
0x87176 ICU
  [0] DTCER118.DTCE
0x87177 ICU
  [0] DTCER119.DTCE
0x87178 ICU
  [0] DTCER120.DTCE
0x87179 ICU
  [0] DTCER121.DTCE
0x8717A ICU
  [0] DTCER122.DTCE
0x8717B ICU
  [0] DTCER123.DTCE
0x8717C ICU
  [0] DTCER124.DTCE
0x8717D ICU
  [0] DTCER125.DTCE
0x8717E ICU
  [0] DTCER126.DTCE
0x8717F ICU
  [0] DTCER127.DTCE
0x87180 ICU
  [0] DTCER128.DTCE
0x87181 ICU
  [0] DTCER129.DTCE
0x87182 ICU
  [0] DTCER130.DTCE
0x87183 ICU
  [0] DTCER131.DTCE
0x87184 ICU
  [0] DTCER132.DTCE
0x87185 ICU
  [0] DTCER133.DTCE
0x87186 ICU
  [0] DTCER134.DTCE
0x87187 ICU
  [0] DTCER135.DTCE
0x87188 ICU
  [0] DTCER136.DTCE
0x87189 ICU
  [0] DTCER137.DTCE
0x8718A ICU
  [0] DTCER138.DTCE
0x8718B ICU
  [0] DTCER139.DTCE
0x8718C ICU
  [0] DTCER140.DTCE
0x8718D ICU
  [0] DTCER141.DTCE
0x8718E ICU
  [0] DTCER142.DTCE
0x8718F ICU
  [0] DTCER143.DTCE
0x87190 ICU
  [0] DTCER144.DTCE
0x87191 ICU
  [0] DTCER145.DTCE
0x87192 ICU
  [0] DTCER146.DTCE
0x87193 ICU
  [0] DTCER147.DTCE
0x87194 ICU
  [0] DTCER148.DTCE
0x87195 ICU
  [0] DTCER149.DTCE
0x87196 ICU
  [0] DTCER150.DTCE
0x87197 ICU
  [0] DTCER151.DTCE
0x87198 ICU
  [0] DTCER152.DTCE
0x87199 ICU
  [0] DTCER153.DTCE
0x8719A ICU
  [0] DTCER154.DTCE
0x8719B ICU
  [0] DTCER155.DTCE
0x8719C ICU
  [0] DTCER156.DTCE
0x8719D ICU
  [0] DTCER157.DTCE
0x8719E ICU
  [0] DTCER158.DTCE
0x8719F ICU
  [0] DTCER159.DTCE
0x871A0 ICU
  [0] DTCER160.DTCE
0x871A1 ICU
  [0] DTCER161.DTCE
0x871A2 ICU
  [0] DTCER162.DTCE
0x871A3 ICU
  [0] DTCER163.DTCE
0x871A4 ICU
  [0] DTCER164.DTCE
0x871A5 ICU
  [0] DTCER165.DTCE
0x871A6 ICU
  [0] DTCER166.DTCE
0x871A7 ICU
  [0] DTCER167.DTCE
0x871A8 ICU
  [0] DTCER168.DTCE
0x871A9 ICU
  [0] DTCER169.DTCE
0x871AA ICU
  [0] DTCER170.DTCE
0x871AB ICU
  [0] DTCER171.DTCE
0x871AC ICU
  [0] DTCER172.DTCE
0x871AD ICU
  [0] DTCER173.DTCE
0x871AE ICU
  [0] DTCER174.DTCE
0x871AF ICU
  [0] DTCER175.DTCE
0x871B0 ICU
  [0] DTCER176.DTCE
0x871B1 ICU
  [0] DTCER177.DTCE
0x871B2 ICU
  [0] DTCER178.DTCE
0x871B3 ICU
  [0] DTCER179.DTCE
0x871B4 ICU
  [0] DTCER180.DTCE
0x871B5 ICU
  [0] DTCER181.DTCE
0x871B6 ICU
  [0] DTCER182.DTCE
0x871B7 ICU
  [0] DTCER183.DTCE
0x871B8 ICU
  [0] DTCER184.DTCE
0x871B9 ICU
  [0] DTCER185.DTCE
0x871BA ICU
  [0] DTCER186.DTCE
0x871BB ICU
  [0] DTCER187.DTCE
0x871BC ICU
  [0] DTCER188.DTCE
0x871BD ICU
  [0] DTCER189.DTCE
0x871BE ICU
  [0] DTCER190.DTCE
0x871BF ICU
  [0] DTCER191.DTCE
0x871C0 ICU
  [0] DTCER192.DTCE
0x871C1 ICU
  [0] DTCER193.DTCE
0x871C2 ICU
  [0] DTCER194.DTCE
0x871C3 ICU
  [0] DTCER195.DTCE
0x871C4 ICU
  [0] DTCER196.DTCE
0x871C5 ICU
  [0] DTCER197.DTCE
0x871C6 ICU
  [0] DTCER198.DTCE
0x871C7 ICU
  [0] DTCER199.DTCE
0x871C8 ICU
  [0] DTCER200.DTCE
0x871C9 ICU
  [0] DTCER201.DTCE
0x871CA ICU
  [0] DTCER202.DTCE
0x871CB ICU
  [0] DTCER203.DTCE
0x871CC ICU
  [0] DTCER204.DTCE
0x871CD ICU
  [0] DTCER205.DTCE
0x871CE ICU
  [0] DTCER206.DTCE
0x871CF ICU
  [0] DTCER207.DTCE
0x871D0 ICU
  [0] DTCER208.DTCE
0x871D1 ICU
  [0] DTCER209.DTCE
0x871D2 ICU
  [0] DTCER210.DTCE
0x871D3 ICU
  [0] DTCER211.DTCE
0x871D4 ICU
  [0] DTCER212.DTCE
0x871D5 ICU
  [0] DTCER213.DTCE
0x871D6 ICU
  [0] DTCER214.DTCE
0x871D7 ICU
  [0] DTCER215.DTCE
0x871D8 ICU
  [0] DTCER216.DTCE
0x871D9 ICU
  [0] DTCER217.DTCE
0x871DA ICU
  [0] DTCER218.DTCE
0x871DB ICU
  [0] DTCER219.DTCE
0x871DC ICU
  [0] DTCER220.DTCE
0x871DD ICU
  [0] DTCER221.DTCE
0x871DE ICU
  [0] DTCER222.DTCE
0x871DF ICU
  [0] DTCER223.DTCE
0x871E0 ICU
  [0] DTCER224.DTCE
0x871E1 ICU
  [0] DTCER225.DTCE
0x871E2 ICU
  [0] DTCER226.DTCE
0x871E3 ICU
  [0] DTCER227.DTCE
0x871E4 ICU
  [0] DTCER228.DTCE
0x871E5 ICU
  [0] DTCER229.DTCE
0x871E6 ICU
  [0] DTCER230.DTCE
0x871E7 ICU
  [0] DTCER231.DTCE
0x871E8 ICU
  [0] DTCER232.DTCE
0x871E9 ICU
  [0] DTCER233.DTCE
0x871EA ICU
  [0] DTCER234.DTCE
0x871EB ICU
  [0] DTCER235.DTCE
0x871EC ICU
  [0] DTCER236.DTCE
0x871ED ICU
  [0] DTCER237.DTCE
0x871EE ICU
  [0] DTCER238.DTCE
0x871EF ICU
  [0] DTCER239.DTCE
0x871F0 ICU
  [0] DTCER240.DTCE
0x871F1 ICU
  [0] DTCER241.DTCE
0x871F2 ICU
  [0] DTCER242.DTCE
0x871F3 ICU
  [0] DTCER243.DTCE
0x871F4 ICU
  [0] DTCER244.DTCE
0x871F5 ICU
  [0] DTCER245.DTCE
0x871F6 ICU
  [0] DTCER246.DTCE
0x871F7 ICU
  [0] DTCER247.DTCE
0x871F8 ICU
  [0] DTCER248.DTCE
0x871F9 ICU
  [0] DTCER249.DTCE
0x871FA ICU
  [0] DTCER250.DTCE
0x871FB ICU
  [0] DTCER251.DTCE
0x871FC ICU
  [0] DTCER252.DTCE
0x871FD ICU
  [0] DTCER253.DTCE
0x871FE ICU
  [0] DTCER254.DTCE
0x871FF ICU
  [0] DTCER255.DTCE
0x87202 ICU
  [n] IER02.IEN{n} (n=0..7)
0x87203 ICU
  [n] IER03.IEN{n} (n=0..7)
0x87204 ICU
  [n] IER04.IEN{n} (n=0..7)
0x87205 ICU
  [n] IER05.IEN{n} (n=0..7)
0x87206 ICU
  [n] IER06.IEN{n} (n=0..7)
0x87207 ICU
  [n] IER07.IEN{n} (n=0..7)
0x87208 ICU
  [n] IER08.IEN{n} (n=0..7)
0x87209 ICU
  [n] IER09.IEN{n} (n=0..7)
0x8720A ICU
  [n] IER0A.IEN{n} (n=0..7)
0x8720B ICU
  [n] IER0B.IEN{n} (n=0..7)
0x8720C ICU
  [n] IER0C.IEN{n} (n=0..7)
0x8720D ICU
  [n] IER0D.IEN{n} (n=0..7)
0x8720E ICU
  [n] IER0E.IEN{n} (n=0..7)
0x8720F ICU
  [n] IER0F.IEN{n} (n=0..7)
0x87210 ICU
  [n] IER10.IEN{n} (n=0..7)
0x87211 ICU
  [n] IER11.IEN{n} (n=0..7)
0x87212 ICU
  [n] IER12.IEN{n} (n=0..7)
0x87213 ICU
  [n] IER13.IEN{n} (n=0..7)
0x87214 ICU
  [n] IER14.IEN{n} (n=0..7)
0x87215 ICU
  [n] IER15.IEN{n} (n=0..7)
0x87216 ICU
  [n] IER16.IEN{n} (n=0..7)
0x87217 ICU
  [n] IER17.IEN{n} (n=0..7)
0x87218 ICU
  [n] IER18.IEN{n} (n=0..7)
0x87219 ICU
  [n] IER19.IEN{n} (n=0..7)
0x8721A ICU
  [n] IER1A.IEN{n} (n=0..7)
0x8721B ICU
  [n] IER1B.IEN{n} (n=0..7)
0x8721C ICU
  [n] IER1C.IEN{n} (n=0..7)
0x8721D ICU
  [n] IER1D.IEN{n} (n=0..7)
0x8721E ICU
  [n] IER1E.IEN{n} (n=0..7)
0x8721F ICU
  [n] IER1F.IEN{n} (n=0..7)
0x872E0 ICU
  [0] SWINTR.SWINT
0x872E1 ICU
  [0] SWINT2R.SWINT2
0x872F0 ICU 16-bit
  [15] FIR.FIEN, [7:0] FIR.FVCT
0x87300 ICU
  [3:0] IPR000.IPR
0x87301 ICU
  [3:0] IPR001.IPR
0x87302 ICU
  [3:0] IPR002.IPR
0x87303 ICU
  [3:0] IPR003.IPR
0x87304 ICU
  [3:0] IPR004.IPR
0x87305 ICU
  [3:0] IPR005.IPR
0x87306 ICU
  [3:0] IPR006.IPR
0x87307 ICU
  [3:0] IPR007.IPR
0x87308 ICU
  [3:0] IPR008.IPR
0x87309 ICU
  [3:0] IPR009.IPR
0x8730A ICU
  [3:0] IPR010.IPR
0x8730B ICU
  [3:0] IPR011.IPR
0x8730C ICU
  [3:0] IPR012.IPR
0x8730D ICU
  [3:0] IPR013.IPR
0x8730E ICU
  [3:0] IPR014.IPR
0x8730F ICU
  [3:0] IPR015.IPR
0x87310 ICU
  [3:0] IPR016.IPR
0x87311 ICU
  [3:0] IPR017.IPR
0x87312 ICU
  [3:0] IPR018.IPR
0x87313 ICU
  [3:0] IPR019.IPR
0x87314 ICU
  [3:0] IPR020.IPR
0x87315 ICU
  [3:0] IPR021.IPR
0x87316 ICU
  [3:0] IPR022.IPR
0x87317 ICU
  [3:0] IPR023.IPR
0x87318 ICU
  [3:0] IPR024.IPR
0x87319 ICU
  [3:0] IPR025.IPR
0x8731A ICU
  [3:0] IPR026.IPR
0x8731B ICU
  [3:0] IPR027.IPR
0x8731C ICU
  [3:0] IPR028.IPR
0x8731D ICU
  [3:0] IPR029.IPR
0x8731E ICU
  [3:0] IPR030.IPR
0x8731F ICU
  [3:0] IPR031.IPR
0x87320 ICU
  [3:0] IPR032.IPR
0x87321 ICU
  [3:0] IPR033.IPR
0x87322 ICU
  [3:0] IPR034.IPR
0x87323 ICU
  [3:0] IPR035.IPR
0x87324 ICU
  [3:0] IPR036.IPR
0x87325 ICU
  [3:0] IPR037.IPR
0x87326 ICU
  [3:0] IPR038.IPR
0x87327 ICU
  [3:0] IPR039.IPR
0x87328 ICU
  [3:0] IPR040.IPR
0x87329 ICU
  [3:0] IPR041.IPR
0x8732A ICU
  [3:0] IPR042.IPR
0x8732B ICU
  [3:0] IPR043.IPR
0x8732C ICU
  [3:0] IPR044.IPR
0x8732D ICU
  [3:0] IPR045.IPR
0x8732E ICU
  [3:0] IPR046.IPR
0x8732F ICU
  [3:0] IPR047.IPR
0x87330 ICU
  [3:0] IPR048.IPR
0x87331 ICU
  [3:0] IPR049.IPR
0x87332 ICU
  [3:0] IPR050.IPR
0x87333 ICU
  [3:0] IPR051.IPR
0x87334 ICU
  [3:0] IPR052.IPR
0x87335 ICU
  [3:0] IPR053.IPR
0x87336 ICU
  [3:0] IPR054.IPR
0x87337 ICU
  [3:0] IPR055.IPR
0x87338 ICU
  [3:0] IPR056.IPR
0x87339 ICU
  [3:0] IPR057.IPR
0x8733A ICU
  [3:0] IPR058.IPR
0x8733B ICU
  [3:0] IPR059.IPR
0x8733C ICU
  [3:0] IPR060.IPR
0x8733D ICU
  [3:0] IPR061.IPR
0x8733E ICU
  [3:0] IPR062.IPR
0x8733F ICU
  [3:0] IPR063.IPR
0x87340 ICU
  [3:0] IPR064.IPR
0x87341 ICU
  [3:0] IPR065.IPR
0x87342 ICU
  [3:0] IPR066.IPR
0x87343 ICU
  [3:0] IPR067.IPR
0x87344 ICU
  [3:0] IPR068.IPR
0x87345 ICU
  [3:0] IPR069.IPR
0x87346 ICU
  [3:0] IPR070.IPR
0x87347 ICU
  [3:0] IPR071.IPR
0x87348 ICU
  [3:0] IPR072.IPR
0x87349 ICU
  [3:0] IPR073.IPR
0x8734A ICU
  [3:0] IPR074.IPR
0x8734B ICU
  [3:0] IPR075.IPR
0x8734C ICU
  [3:0] IPR076.IPR
0x8734D ICU
  [3:0] IPR077.IPR
0x8734E ICU
  [3:0] IPR078.IPR
0x8734F ICU
  [3:0] IPR079.IPR
0x87350 ICU
  [3:0] IPR080.IPR
0x87351 ICU
  [3:0] IPR081.IPR
0x87352 ICU
  [3:0] IPR082.IPR
0x87353 ICU
  [3:0] IPR083.IPR
0x87354 ICU
  [3:0] IPR084.IPR
0x87355 ICU
  [3:0] IPR085.IPR
0x87356 ICU
  [3:0] IPR086.IPR
0x87357 ICU
  [3:0] IPR087.IPR
0x87358 ICU
  [3:0] IPR088.IPR
0x87359 ICU
  [3:0] IPR089.IPR
0x8735A ICU
  [3:0] IPR090.IPR
0x8735B ICU
  [3:0] IPR091.IPR
0x8735C ICU
  [3:0] IPR092.IPR
0x8735D ICU
  [3:0] IPR093.IPR
0x8735E ICU
  [3:0] IPR094.IPR
0x8735F ICU
  [3:0] IPR095.IPR
0x87360 ICU
  [3:0] IPR096.IPR
0x87361 ICU
  [3:0] IPR097.IPR
0x87362 ICU
  [3:0] IPR098.IPR
0x87363 ICU
  [3:0] IPR099.IPR
0x87364 ICU
  [3:0] IPR100.IPR
0x87365 ICU
  [3:0] IPR101.IPR
0x87366 ICU
  [3:0] IPR102.IPR
0x87367 ICU
  [3:0] IPR103.IPR
0x87368 ICU
  [3:0] IPR104.IPR
0x87369 ICU
  [3:0] IPR105.IPR
0x8736A ICU
  [3:0] IPR106.IPR
0x8736B ICU
  [3:0] IPR107.IPR
0x8736C ICU
  [3:0] IPR108.IPR
0x8736D ICU
  [3:0] IPR109.IPR
0x8736E ICU
  [3:0] IPR110.IPR
0x8736F ICU
  [3:0] IPR111.IPR
0x87370 ICU
  [3:0] IPR112.IPR
0x87371 ICU
  [3:0] IPR113.IPR
0x87372 ICU
  [3:0] IPR114.IPR
0x87373 ICU
  [3:0] IPR115.IPR
0x87374 ICU
  [3:0] IPR116.IPR
0x87375 ICU
  [3:0] IPR117.IPR
0x87376 ICU
  [3:0] IPR118.IPR
0x87377 ICU
  [3:0] IPR119.IPR
0x87378 ICU
  [3:0] IPR120.IPR
0x87379 ICU
  [3:0] IPR121.IPR
0x8737A ICU
  [3:0] IPR122.IPR
0x8737B ICU
  [3:0] IPR123.IPR
0x8737C ICU
  [3:0] IPR124.IPR
0x8737D ICU
  [3:0] IPR125.IPR
0x8737E ICU
  [3:0] IPR126.IPR
0x8737F ICU
  [3:0] IPR127.IPR
0x87380 ICU
  [3:0] IPR128.IPR
0x87381 ICU
  [3:0] IPR129.IPR
0x87382 ICU
  [3:0] IPR130.IPR
0x87383 ICU
  [3:0] IPR131.IPR
0x87384 ICU
  [3:0] IPR132.IPR
0x87385 ICU
  [3:0] IPR133.IPR
0x87386 ICU
  [3:0] IPR134.IPR
0x87387 ICU
  [3:0] IPR135.IPR
0x87388 ICU
  [3:0] IPR136.IPR
0x87389 ICU
  [3:0] IPR137.IPR
0x8738A ICU
  [3:0] IPR138.IPR
0x8738B ICU
  [3:0] IPR139.IPR
0x8738C ICU
  [3:0] IPR140.IPR
0x8738D ICU
  [3:0] IPR141.IPR
0x8738E ICU
  [3:0] IPR142.IPR
0x8738F ICU
  [3:0] IPR143.IPR
0x87390 ICU
  [3:0] IPR144.IPR
0x87391 ICU
  [3:0] IPR145.IPR
0x87392 ICU
  [3:0] IPR146.IPR
0x87393 ICU
  [3:0] IPR147.IPR
0x87394 ICU
  [3:0] IPR148.IPR
0x87395 ICU
  [3:0] IPR149.IPR
0x87396 ICU
  [3:0] IPR150.IPR
0x87397 ICU
  [3:0] IPR151.IPR
0x87398 ICU
  [3:0] IPR152.IPR
0x87399 ICU
  [3:0] IPR153.IPR
0x8739A ICU
  [3:0] IPR154.IPR
0x8739B ICU
  [3:0] IPR155.IPR
0x8739C ICU
  [3:0] IPR156.IPR
0x8739D ICU
  [3:0] IPR157.IPR
0x8739E ICU
  [3:0] IPR158.IPR
0x8739F ICU
  [3:0] IPR159.IPR
0x873A0 ICU
  [3:0] IPR160.IPR
0x873A1 ICU
  [3:0] IPR161.IPR
0x873A2 ICU
  [3:0] IPR162.IPR
0x873A3 ICU
  [3:0] IPR163.IPR
0x873A4 ICU
  [3:0] IPR164.IPR
0x873A5 ICU
  [3:0] IPR165.IPR
0x873A6 ICU
  [3:0] IPR166.IPR
0x873A7 ICU
  [3:0] IPR167.IPR
0x873A8 ICU
  [3:0] IPR168.IPR
0x873A9 ICU
  [3:0] IPR169.IPR
0x873AA ICU
  [3:0] IPR170.IPR
0x873AB ICU
  [3:0] IPR171.IPR
0x873AC ICU
  [3:0] IPR172.IPR
0x873AD ICU
  [3:0] IPR173.IPR
0x873AE ICU
  [3:0] IPR174.IPR
0x873AF ICU
  [3:0] IPR175.IPR
0x873B0 ICU
  [3:0] IPR176.IPR
0x873B1 ICU
  [3:0] IPR177.IPR
0x873B2 ICU
  [3:0] IPR178.IPR
0x873B3 ICU
  [3:0] IPR179.IPR
0x873B4 ICU
  [3:0] IPR180.IPR
0x873B5 ICU
  [3:0] IPR181.IPR
0x873B6 ICU
  [3:0] IPR182.IPR
0x873B7 ICU
  [3:0] IPR183.IPR
0x873B8 ICU
  [3:0] IPR184.IPR
0x873B9 ICU
  [3:0] IPR185.IPR
0x873BA ICU
  [3:0] IPR186.IPR
0x873BB ICU
  [3:0] IPR187.IPR
0x873BC ICU
  [3:0] IPR188.IPR
0x873BD ICU
  [3:0] IPR189.IPR
0x873BE ICU
  [3:0] IPR190.IPR
0x873BF ICU
  [3:0] IPR191.IPR
0x873C0 ICU
  [3:0] IPR192.IPR
0x873C1 ICU
  [3:0] IPR193.IPR
0x873C2 ICU
  [3:0] IPR194.IPR
0x873C3 ICU
  [3:0] IPR195.IPR
0x873C4 ICU
  [3:0] IPR196.IPR
0x873C5 ICU
  [3:0] IPR197.IPR
0x873C6 ICU
  [3:0] IPR198.IPR
0x873C7 ICU
  [3:0] IPR199.IPR
0x873C8 ICU
  [3:0] IPR200.IPR
0x873C9 ICU
  [3:0] IPR201.IPR
0x873CA ICU
  [3:0] IPR202.IPR
0x873CB ICU
  [3:0] IPR203.IPR
0x873CC ICU
  [3:0] IPR204.IPR
0x873CD ICU
  [3:0] IPR205.IPR
0x873CE ICU
  [3:0] IPR206.IPR
0x873CF ICU
  [3:0] IPR207.IPR
0x873D0 ICU
  [3:0] IPR208.IPR
0x873D1 ICU
  [3:0] IPR209.IPR
0x873D2 ICU
  [3:0] IPR210.IPR
0x873D3 ICU
  [3:0] IPR211.IPR
0x873D4 ICU
  [3:0] IPR212.IPR
0x873D5 ICU
  [3:0] IPR213.IPR
0x873D6 ICU
  [3:0] IPR214.IPR
0x873D7 ICU
  [3:0] IPR215.IPR
0x873D8 ICU
  [3:0] IPR216.IPR
0x873D9 ICU
  [3:0] IPR217.IPR
0x873DA ICU
  [3:0] IPR218.IPR
0x873DB ICU
  [3:0] IPR219.IPR
0x873DC ICU
  [3:0] IPR220.IPR
0x873DD ICU
  [3:0] IPR221.IPR
0x873DE ICU
  [3:0] IPR222.IPR
0x873DF ICU
  [3:0] IPR223.IPR
0x873E0 ICU
  [3:0] IPR224.IPR
0x873E1 ICU
  [3:0] IPR225.IPR
0x873E2 ICU
  [3:0] IPR226.IPR
0x873E3 ICU
  [3:0] IPR227.IPR
0x873E4 ICU
  [3:0] IPR228.IPR
0x873E5 ICU
  [3:0] IPR229.IPR
0x873E6 ICU
  [3:0] IPR230.IPR
0x873E7 ICU
  [3:0] IPR231.IPR
0x873E8 ICU
  [3:0] IPR232.IPR
0x873E9 ICU
  [3:0] IPR233.IPR
0x873EA ICU
  [3:0] IPR234.IPR
0x873EB ICU
  [3:0] IPR235.IPR
0x873EC ICU
  [3:0] IPR236.IPR
0x873ED ICU
  [3:0] IPR237.IPR
0x873EE ICU
  [3:0] IPR238.IPR
0x873EF ICU
  [3:0] IPR239.IPR
0x873F0 ICU
  [3:0] IPR240.IPR
0x873F1 ICU
  [3:0] IPR241.IPR
0x873F2 ICU
  [3:0] IPR242.IPR
0x873F3 ICU
  [3:0] IPR243.IPR
0x873F4 ICU
  [3:0] IPR244.IPR
0x873F5 ICU
  [3:0] IPR245.IPR
0x873F6 ICU
  [3:0] IPR246.IPR
0x873F7 ICU
  [3:0] IPR247.IPR
0x873F8 ICU
  [3:0] IPR248.IPR
0x873F9 ICU
  [3:0] IPR249.IPR
0x873FA ICU
  [3:0] IPR250.IPR
0x873FB ICU
  [3:0] IPR251.IPR
0x873FC ICU
  [3:0] IPR252.IPR
0x873FD ICU
  [3:0] IPR253.IPR
0x873FE ICU
  [3:0] IPR254.IPR
0x873FF ICU
  [3:0] IPR255.IPR
0x87500 ICU
  [3:2] IRQCR0.IRQMD
0x87501 ICU
  [3:2] IRQCR1.IRQMD
0x87502 ICU
  [3:2] IRQCR2.IRQMD
0x87503 ICU
  [3:2] IRQCR3.IRQMD
0x87504 ICU
  [3:2] IRQCR4.IRQMD
0x87505 ICU
  [3:2] IRQCR5.IRQMD
0x87506 ICU
  [3:2] IRQCR6.IRQMD
0x87507 ICU
  [3:2] IRQCR7.IRQMD
0x87508 ICU
  [3:2] IRQCR8.IRQMD
0x87509 ICU
  [3:2] IRQCR9.IRQMD
0x8750A ICU
  [3:2] IRQCR10.IRQMD
0x8750B ICU
  [3:2] IRQCR11.IRQMD
0x8750C ICU
  [3:2] IRQCR12.IRQMD
0x8750D ICU
  [3:2] IRQCR13.IRQMD
0x8750E ICU
  [3:2] IRQCR14.IRQMD
0x8750F ICU
  [3:2] IRQCR15.IRQMD
0x87520 ICU
  [n] IRQFLTE0.FLTEN{n} (n=0..7)
0x87521 ICU
  [n-8] IRQFLTE1.FLTEN{n} (n=8..15)
0x87528 ICU 16-bit
  [2n+1:2n] IRQFLTC0.FCLKSEL{n} (n=0..7)
0x8752A ICU 16-bit
  [2n-15:2n-16] IRQFLTC1.FCLKSEL{n} (n=8..15)
0x87580 ICU
  [6] NMISR.ECCRAMST, [5] NMISR.LVD2ST, [4] NMISR.LVD1ST, [3] NMISR.IWDTST, [2] NMISR.WDTST, [1] NMISR.OSTST, [0] NMISR.NMIST
0x87581 ICU
  [6] NMIER.ECCRAMEN, [5] NMIER.LVD2EN, [4] NMIER.LVD1EN, [3] NMIER.IWDTEN, [2] NMIER.WDTEN, [1] NMIER.OSTEN, [0] NMIER.NMIEN
0x87582 ICU
  [5] NMICLR.LVD2CLR, [4] NMICLR.LVD1CLR, [3] NMICLR.IWDTCLR, [2] NMICLR.WDTCLR, [1] NMICLR.OSTCLR, [0] NMICLR.NMICLR
0x87583 ICU
  [3] NMICR.NMIMD
0x87590 ICU
  [0] NMIFLTE.NFLTEN
0x87594 ICU
  [1:0] NMIFLTC.NFCLKSEL
0x87600 ICU 32-bit
  [n] GRPBE0.IS{n} (n=0..31)
0x87630 ICU 32-bit
  [n] GRPBL0.IS{n} (n=0..31)
0x87634 ICU 32-bit
  [n] GRPBL1.IS{n} (n=0..31)
0x87640 ICU 32-bit
  [n] GENBE0.EN{n} (n=0..31)
0x87670 ICU 32-bit
  [n] GENBL0.EN{n} (n=0..31)
0x87674 ICU 32-bit
  [n] GENBL1.EN{n} (n=0..31)
0x87680 ICU 32-bit
  [n] GCRBE0.CLR{n} (n=0..31)
0x87700 ICU
  [n] PIBR0.PIR{n} (n=0..7)
0x87701 ICU
  [n] PIBR1.PIR{n} (n=0..7)
0x87702 ICU
  [n] PIBR2.PIR{n} (n=0..7)
0x87703 ICU
  [n] PIBR3.PIR{n} (n=0..7)
0x87704 ICU
  [n] PIBR4.PIR{n} (n=0..7)
0x87705 ICU
  [n] PIBR5.PIR{n} (n=0..7)
0x87706 ICU
  [n] PIBR6.PIR{n} (n=0..7)
0x87707 ICU
  [n] PIBR7.PIR{n} (n=0..7)
0x87708 ICU
  [n] PIBR8.PIR{n} (n=0..7)
0x87709 ICU
  [n] PIBR9.PIR{n} (n=0..7)
0x8770A ICU
  [n] PIBRA.PIR{n} (n=0..7)
0x87780 ICU
  [7:0] SLIBXR128.SLI
0x87781 ICU
  [7:0] SLIBXR129.SLI
0x87782 ICU
  [7:0] SLIBXR130.SLI
0x87783 ICU
  [7:0] SLIBXR131.SLI
0x87784 ICU
  [7:0] SLIBXR132.SLI
0x87785 ICU
  [7:0] SLIBXR133.SLI
0x87786 ICU
  [7:0] SLIBXR134.SLI
0x87787 ICU
  [7:0] SLIBXR135.SLI
0x87788 ICU
  [7:0] SLIBXR136.SLI
0x87789 ICU
  [7:0] SLIBXR137.SLI
0x8778A ICU
  [7:0] SLIBXR138.SLI
0x8778B ICU
  [7:0] SLIBXR139.SLI
0x8778C ICU
  [7:0] SLIBXR140.SLI
0x8778D ICU
  [7:0] SLIBXR141.SLI
0x8778E ICU
  [7:0] SLIBXR142.SLI
0x8778F ICU
  [7:0] SLIBXR143.SLI
0x87790 ICU
  [7:0] SLIBR144.SLI
0x87791 ICU
  [7:0] SLIBR145.SLI
0x87792 ICU
  [7:0] SLIBR146.SLI
0x87793 ICU
  [7:0] SLIBR147.SLI
0x87794 ICU
  [7:0] SLIBR148.SLI
0x87795 ICU
  [7:0] SLIBR149.SLI
0x87796 ICU
  [7:0] SLIBR150.SLI
0x87797 ICU
  [7:0] SLIBR151.SLI
0x87798 ICU
  [7:0] SLIBR152.SLI
0x87799 ICU
  [7:0] SLIBR153.SLI
0x8779A ICU
  [7:0] SLIBR154.SLI
0x8779B ICU
  [7:0] SLIBR155.SLI
0x8779C ICU
  [7:0] SLIBR156.SLI
0x8779D ICU
  [7:0] SLIBR157.SLI
0x8779E ICU
  [7:0] SLIBR158.SLI
0x8779F ICU
  [7:0] SLIBR159.SLI
0x877A0 ICU
  [7:0] SLIBR160.SLI
0x877A1 ICU
  [7:0] SLIBR161.SLI
0x877A2 ICU
  [7:0] SLIBR162.SLI
0x877A3 ICU
  [7:0] SLIBR163.SLI
0x877A4 ICU
  [7:0] SLIBR164.SLI
0x877A5 ICU
  [7:0] SLIBR165.SLI
0x877A6 ICU
  [7:0] SLIBR166.SLI
0x877A7 ICU
  [7:0] SLIBR167.SLI
0x877A8 ICU
  [7:0] SLIBR168.SLI
0x877A9 ICU
  [7:0] SLIBR169.SLI
0x877AA ICU
  [7:0] SLIBR170.SLI
0x877AB ICU
  [7:0] SLIBR171.SLI
0x877AC ICU
  [7:0] SLIBR172.SLI
0x877AD ICU
  [7:0] SLIBR173.SLI
0x877AE ICU
  [7:0] SLIBR174.SLI
0x877AF ICU
  [7:0] SLIBR175.SLI
0x877B0 ICU
  [7:0] SLIBR176.SLI
0x877B1 ICU
  [7:0] SLIBR177.SLI
0x877B2 ICU
  [7:0] SLIBR178.SLI
0x877B3 ICU
  [7:0] SLIBR179.SLI
0x877B4 ICU
  [7:0] SLIBR180.SLI
0x877B5 ICU
  [7:0] SLIBR181.SLI
0x877B6 ICU
  [7:0] SLIBR182.SLI
0x877B7 ICU
  [7:0] SLIBR183.SLI
0x877B8 ICU
  [7:0] SLIBR184.SLI
0x877B9 ICU
  [7:0] SLIBR185.SLI
0x877BA ICU
  [7:0] SLIBR186.SLI
0x877BB ICU
  [7:0] SLIBR187.SLI
0x877BC ICU
  [7:0] SLIBR188.SLI
0x877BD ICU
  [7:0] SLIBR189.SLI
0x877BE ICU
  [7:0] SLIBR190.SLI
0x877BF ICU
  [7:0] SLIBR191.SLI
0x877C0 ICU
  [7:0] SLIBR192.SLI
0x877C1 ICU
  [7:0] SLIBR193.SLI
0x877C2 ICU
  [7:0] SLIBR194.SLI
0x877C3 ICU
  [7:0] SLIBR195.SLI
0x877C4 ICU
  [7:0] SLIBR196.SLI
0x877C5 ICU
  [7:0] SLIBR197.SLI
0x877C6 ICU
  [7:0] SLIBR198.SLI
0x877C7 ICU
  [7:0] SLIBR199.SLI
0x877C8 ICU
  [7:0] SLIBR200.SLI
0x877C9 ICU
  [7:0] SLIBR201.SLI
0x877CA ICU
  [7:0] SLIBR202.SLI
0x877CB ICU
  [7:0] SLIBR203.SLI
0x877CC ICU
  [7:0] SLIBR204.SLI
0x877CD ICU
  [7:0] SLIBR205.SLI
0x877CE ICU
  [7:0] SLIBR206.SLI
0x877CF ICU
  [7:0] SLIBR207.SLI
0x87830 ICU 32-bit
  [n] GRPAL0.IS{n} (n=0..31)
0x87834 ICU 32-bit
  [n] GRPAL1.IS{n} (n=0..31)
0x87870 ICU 32-bit
  [n] GENAL0.EN{n} (n=0..31)
0x87874 ICU 32-bit
  [n] GENAL1.EN{n} (n=0..31)
0x87900 ICU
  [n] PIAR0.PIR{n} (n=0..7)
0x87901 ICU
  [n] PIAR1.PIR{n} (n=0..7)
0x87902 ICU
  [n] PIAR2.PIR{n} (n=0..7)
0x87903 ICU
  [n] PIAR3.PIR{n} (n=0..7)
0x87904 ICU
  [n] PIAR4.PIR{n} (n=0..7)
0x87905 ICU
  [n] PIAR5.PIR{n} (n=0..7)
0x87906 ICU
  [n] PIAR6.PIR{n} (n=0..7)
0x87907 ICU
  [n] PIAR7.PIR{n} (n=0..7)
0x87908 ICU
  [n] PIAR8.PIR{n} (n=0..7)
0x87909 ICU
  [n] PIAR9.PIR{n} (n=0..7)
0x8790A ICU
  [n] PIARA.PIR{n} (n=0..7)
0x8790B ICU
  [n] PIARB.PIR{n} (n=0..7)
0x879D0 ICU
  [7:0] SLIAR208.SLI
0x879D1 ICU
  [7:0] SLIAR209.SLI
0x879D2 ICU
  [7:0] SLIAR210.SLI
0x879D3 ICU
  [7:0] SLIAR211.SLI
0x879D4 ICU
  [7:0] SLIAR212.SLI
0x879D5 ICU
  [7:0] SLIAR213.SLI
0x879D6 ICU
  [7:0] SLIAR214.SLI
0x879D7 ICU
  [7:0] SLIAR215.SLI
0x879D8 ICU
  [7:0] SLIAR216.SLI
0x879D9 ICU
  [7:0] SLIAR217.SLI
0x879DA ICU
  [7:0] SLIAR218.SLI
0x879DB ICU
  [7:0] SLIAR219.SLI
0x879DC ICU
  [7:0] SLIAR220.SLI
0x879DD ICU
  [7:0] SLIAR221.SLI
0x879DE ICU
  [7:0] SLIAR222.SLI
0x879DF ICU
  [7:0] SLIAR223.SLI
0x879E0 ICU
  [7:0] SLIAR224.SLI
0x879E1 ICU
  [7:0] SLIAR225.SLI
0x879E2 ICU
  [7:0] SLIAR226.SLI
0x879E3 ICU
  [7:0] SLIAR227.SLI
0x879E4 ICU
  [7:0] SLIAR228.SLI
0x879E5 ICU
  [7:0] SLIAR229.SLI
0x879E6 ICU
  [7:0] SLIAR230.SLI
0x879E7 ICU
  [7:0] SLIAR231.SLI
0x879E8 ICU
  [7:0] SLIAR232.SLI
0x879E9 ICU
  [7:0] SLIAR233.SLI
0x879EA ICU
  [7:0] SLIAR234.SLI
0x879EB ICU
  [7:0] SLIAR235.SLI
0x879EC ICU
  [7:0] SLIAR236.SLI
0x879ED ICU
  [7:0] SLIAR237.SLI
0x879EE ICU
  [7:0] SLIAR238.SLI
0x879EF ICU
  [7:0] SLIAR239.SLI
0x879F0 ICU
  [7:0] SLIAR240.SLI
0x879F1 ICU
  [7:0] SLIAR241.SLI
0x879F2 ICU
  [7:0] SLIAR242.SLI
0x879F3 ICU
  [7:0] SLIAR243.SLI
0x879F4 ICU
  [7:0] SLIAR244.SLI
0x879F5 ICU
  [7:0] SLIAR245.SLI
0x879F6 ICU
  [7:0] SLIAR246.SLI
0x879F7 ICU
  [7:0] SLIAR247.SLI
0x879F8 ICU
  [7:0] SLIAR248.SLI
0x879F9 ICU
  [7:0] SLIAR249.SLI
0x879FA ICU
  [7:0] SLIAR250.SLI
0x879FB ICU
  [7:0] SLIAR251.SLI
0x879FC ICU
  [7:0] SLIAR252.SLI
0x879FD ICU
  [7:0] SLIAR253.SLI
0x879FE ICU
  [7:0] SLIAR254.SLI
0x879FF ICU
  [7:0] SLIAR255.SLI
0x87A00 ICU
  [0] SLIPRCR.WPRC
0x87A01 ICU
  [1] SELEXDR.SELEXD1, [0] SELEXDR.SELEXD0
0x88000 CMT 16-bit
  [1] CMSTR0.STR1, [0] CMSTR0.STR0
0x88002 CMT0 16-bit
  [6] CMCR.CMIE, [1:0] CMCR.CKS
0x88008 CMT1 16-bit
  [6] CMCR.CMIE, [1:0] CMCR.CKS
0x88010 CMT 16-bit
  [1] CMSTR1.STR3, [0] CMSTR1.STR2
0x88012 CMT2 16-bit
  [6] CMCR.CMIE, [1:0] CMCR.CKS
0x88018 CMT3 16-bit
  [6] CMCR.CMIE, [1:0] CMCR.CKS
0x88022 WDT 16-bit
  [13:12] WDTCR.RPSS, [9:8] WDTCR.RPES, [7:4] WDTCR.CKS, [1:0] WDTCR.TOPS
0x88024 WDT 16-bit
  [15] WDTSR.REFEF, [14] WDTSR.UNDFF, [13:0] WDTSR.CNTVAL
0x88026 WDT
  [7] WDTRCR.RSTIRQS
0x88032 IWDT 16-bit
  [13:12] IWDTCR.RPSS, [9:8] IWDTCR.RPES, [7:4] IWDTCR.CKS, [1:0] IWDTCR.TOPS
0x88034 IWDT 16-bit
  [15] IWDTSR.REFEF, [14] IWDTSR.UNDFF, [13:0] IWDTSR.CNTVAL
0x88036 IWDT
  [7] IWDTRCR.RSTIRQS
0x88038 IWDT
  [7] IWDTCSTPR.SLCSTP
0x88044 DA
  [7] DACR.DAOE1, [6] DACR.DAOE0, [5] DACR.DAE
0x88045 DA
  [7] DADPR.DPSEL
0x88046 DA
  [7] DAADSCR.DAADST
0x88048 DA
  [7] DAAMPCR.DAAMP1, [6] DAAMPCR.DAAMP0
0x88100 TPUA
  [n] TSTR.CST{n} (n=0..5)
0x88101 TPUA
  [n] TSYR.SYNC{n} (n=0..5)
0x88108 TPU0
  [5:4] NFCR.NFCS, [3] NFCR.NFDEN, [2] NFCR.NFCEN, [1] NFCR.NFBEN, [0] NFCR.NFAEN
0x88109 TPU1
  [5:4] NFCR.NFCS, [1] NFCR.NFBEN, [0] NFCR.NFAEN
0x8810A TPU2
  [5:4] NFCR.NFCS, [1] NFCR.NFBEN, [0] NFCR.NFAEN
0x8810B TPU3
  fields as TPU0
0x8810C TPU4
  [5:4] NFCR.NFCS, [1] NFCR.NFBEN, [0] NFCR.NFAEN
0x8810D TPU5
  [5:4] NFCR.NFCS, [1] NFCR.NFBEN, [0] NFCR.NFAEN
0x88110 TPU0
  [7:5] TCR.CCLR, [4:3] TCR.CKEG, [2:0] TCR.TPSC
0x88111 TPU0
  [7] TMDR.ICSELD, [6] TMDR.ICSELB, [5] TMDR.BFB, [4] TMDR.BFA, [3:0] TMDR.MD
0x88112 TPU0
  [7:4] TIORH.IOB, [3:0] TIORH.IOA
# iorx71m register map
Registers are 8-bit, access not given, no defined reset value unless marked. A register's access mark holds for its fields unless they carry their own. Addresses are absolute; registers are grouped by the start of their names; [hi:lo] are bit positions; {n}, {i} and the like mark numbered series; 'fields as' and 'values as' point back to an identical list.

## SFR (part 3 of 4)
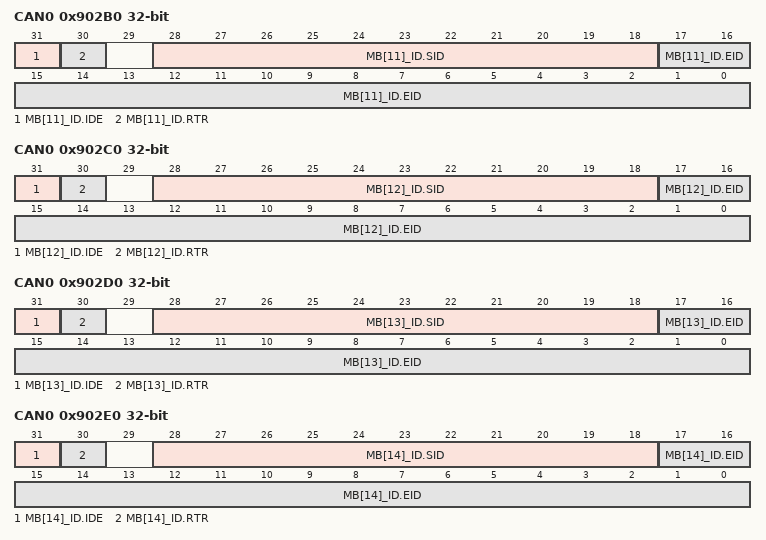
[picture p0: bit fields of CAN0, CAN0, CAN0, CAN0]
0x902B0 CAN0 32-bit
  [31] MB[11]_ID.IDE, [30] MB[11]_ID.RTR, [28:18] MB[11]_ID.SID, [17:0] MB[11]_ID.EID
0x902C0 CAN0 32-bit
  [31] MB[12]_ID.IDE, [30] MB[12]_ID.RTR, [28:18] MB[12]_ID.SID, [17:0] MB[12]_ID.EID
0x902D0 CAN0 32-bit
  [31] MB[13]_ID.IDE, [30] MB[13]_ID.RTR, [28:18] MB[13]_ID.SID, [17:0] MB[13]_ID.EID
0x902E0 CAN0 32-bit
  [31] MB[14]_ID.IDE, [30] MB[14]_ID.RTR, [28:18] MB[14]_ID.SID, [17:0] MB[14]_ID.EID
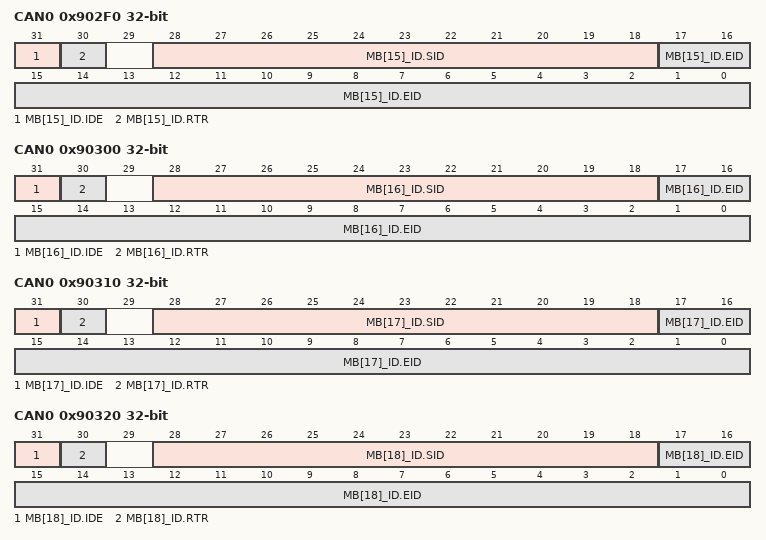
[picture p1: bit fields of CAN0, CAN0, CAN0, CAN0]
0x902F0 CAN0 32-bit
  [31] MB[15]_ID.IDE, [30] MB[15]_ID.RTR, [28:18] MB[15]_ID.SID, [17:0] MB[15]_ID.EID
0x90300 CAN0 32-bit
  [31] MB[16]_ID.IDE, [30] MB[16]_ID.RTR, [28:18] MB[16]_ID.SID, [17:0] MB[16]_ID.EID
0x90310 CAN0 32-bit
  [31] MB[17]_ID.IDE, [30] MB[17]_ID.RTR, [28:18] MB[17]_ID.SID, [17:0] MB[17]_ID.EID
0x90320 CAN0 32-bit
  [31] MB[18]_ID.IDE, [30] MB[18]_ID.RTR, [28:18] MB[18]_ID.SID, [17:0] MB[18]_ID.EID
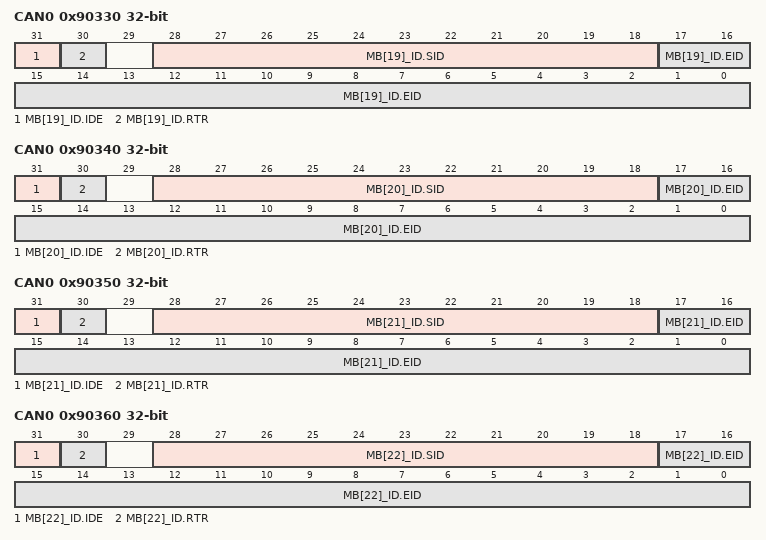
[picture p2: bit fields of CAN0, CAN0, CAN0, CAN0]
0x90330 CAN0 32-bit
  [31] MB[19]_ID.IDE, [30] MB[19]_ID.RTR, [28:18] MB[19]_ID.SID, [17:0] MB[19]_ID.EID
0x90340 CAN0 32-bit
  [31] MB[20]_ID.IDE, [30] MB[20]_ID.RTR, [28:18] MB[20]_ID.SID, [17:0] MB[20]_ID.EID
0x90350 CAN0 32-bit
  [31] MB[21]_ID.IDE, [30] MB[21]_ID.RTR, [28:18] MB[21]_ID.SID, [17:0] MB[21]_ID.EID
0x90360 CAN0 32-bit
  [31] MB[22]_ID.IDE, [30] MB[22]_ID.RTR, [28:18] MB[22]_ID.SID, [17:0] MB[22]_ID.EID
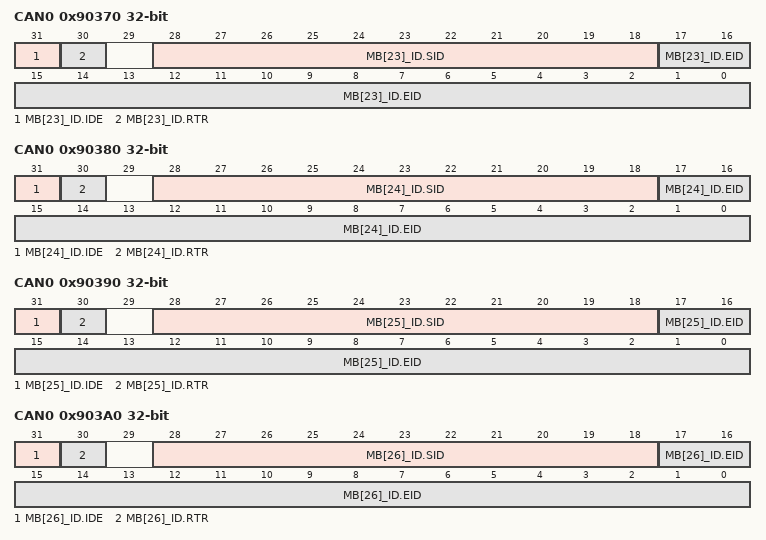
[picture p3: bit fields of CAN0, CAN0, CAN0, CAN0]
0x90370 CAN0 32-bit
  [31] MB[23]_ID.IDE, [30] MB[23]_ID.RTR, [28:18] MB[23]_ID.SID, [17:0] MB[23]_ID.EID
0x90380 CAN0 32-bit
  [31] MB[24]_ID.IDE, [30] MB[24]_ID.RTR, [28:18] MB[24]_ID.SID, [17:0] MB[24]_ID.EID
0x90390 CAN0 32-bit
  [31] MB[25]_ID.IDE, [30] MB[25]_ID.RTR, [28:18] MB[25]_ID.SID, [17:0] MB[25]_ID.EID
0x903A0 CAN0 32-bit
  [31] MB[26]_ID.IDE, [30] MB[26]_ID.RTR, [28:18] MB[26]_ID.SID, [17:0] MB[26]_ID.EID
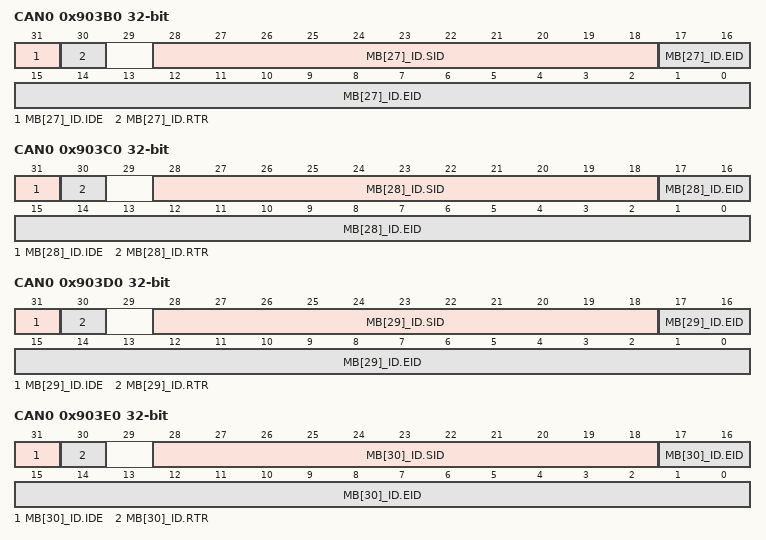
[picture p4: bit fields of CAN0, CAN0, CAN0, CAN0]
0x903B0 CAN0 32-bit
  [31] MB[27]_ID.IDE, [30] MB[27]_ID.RTR, [28:18] MB[27]_ID.SID, [17:0] MB[27]_ID.EID
0x903C0 CAN0 32-bit
  [31] MB[28]_ID.IDE, [30] MB[28]_ID.RTR, [28:18] MB[28]_ID.SID, [17:0] MB[28]_ID.EID
0x903D0 CAN0 32-bit
  [31] MB[29]_ID.IDE, [30] MB[29]_ID.RTR, [28:18] MB[29]_ID.SID, [17:0] MB[29]_ID.EID
0x903E0 CAN0 32-bit
  [31] MB[30]_ID.IDE, [30] MB[30]_ID.RTR, [28:18] MB[30]_ID.SID, [17:0] MB[30]_ID.EID
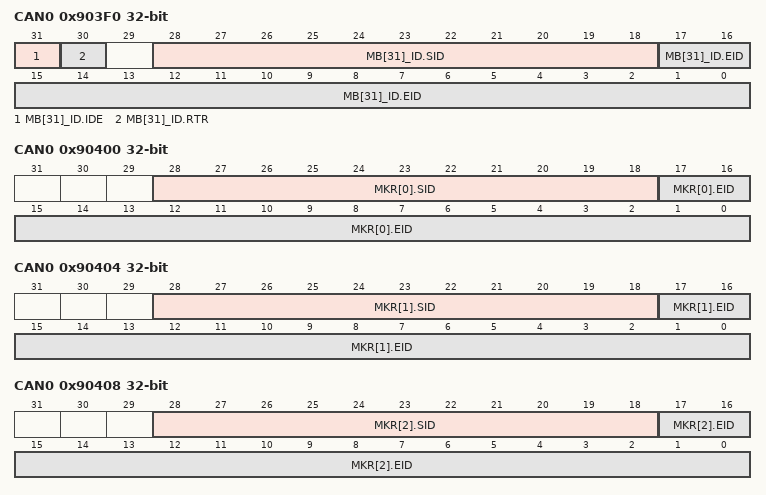
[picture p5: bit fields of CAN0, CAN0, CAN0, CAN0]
0x903F0 CAN0 32-bit
  [31] MB[31]_ID.IDE, [30] MB[31]_ID.RTR, [28:18] MB[31]_ID.SID, [17:0] MB[31]_ID.EID
0x90400 CAN0 32-bit
  [28:18] MKR[0].SID, [17:0] MKR[0].EID
0x90404 CAN0 32-bit
  [28:18] MKR[1].SID, [17:0] MKR[1].EID
0x90408 CAN0 32-bit
  [28:18] MKR[2].SID, [17:0] MKR[2].EID
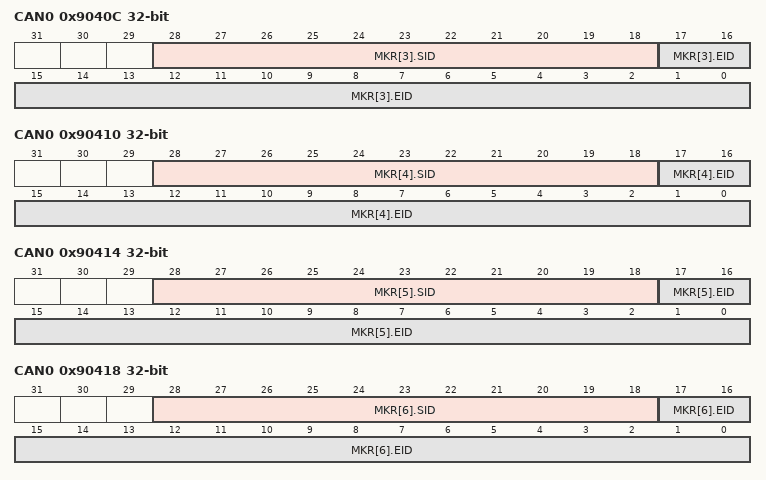
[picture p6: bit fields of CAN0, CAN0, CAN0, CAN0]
0x9040C CAN0 32-bit
  [28:18] MKR[3].SID, [17:0] MKR[3].EID
0x90410 CAN0 32-bit
  [28:18] MKR[4].SID, [17:0] MKR[4].EID
0x90414 CAN0 32-bit
  [28:18] MKR[5].SID, [17:0] MKR[5].EID
0x90418 CAN0 32-bit
  [28:18] MKR[6].SID, [17:0] MKR[6].EID
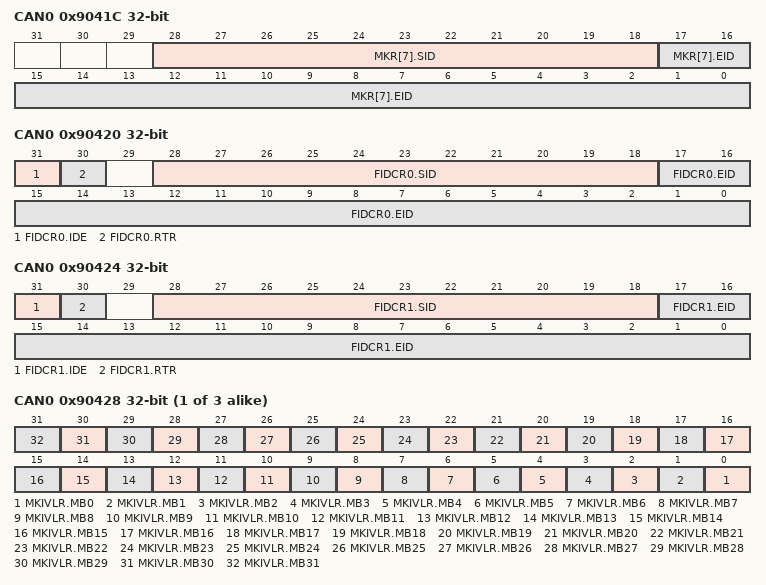
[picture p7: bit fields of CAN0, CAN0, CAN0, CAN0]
0x9041C CAN0 32-bit
  [28:18] MKR[7].SID, [17:0] MKR[7].EID
0x90420 CAN0 32-bit
  [31] FIDCR0.IDE, [30] FIDCR0.RTR, [28:18] FIDCR0.SID, [17:0] FIDCR0.EID
0x90424 CAN0 32-bit
  [31] FIDCR1.IDE, [30] FIDCR1.RTR, [28:18] FIDCR1.SID, [17:0] FIDCR1.EID
{0x90428+0x1000*i} CAN{i} 32-bit (i=0..2)
  [n] MKIVLR.MB{n} (n=0..31)
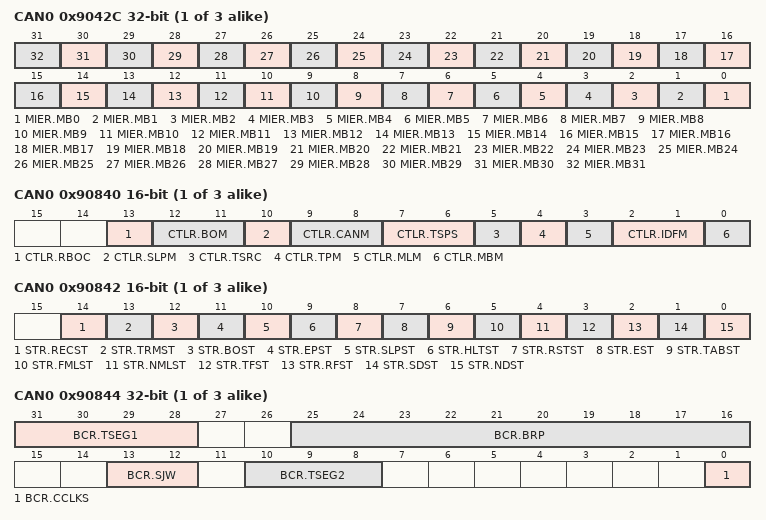
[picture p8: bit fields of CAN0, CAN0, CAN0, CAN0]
{0x9042C+0x1000*i} CAN{i} 32-bit (i=0..2)
  [n] MIER.MB{n} (n=0..31)
0x90820 CAN0
  [7] MCTL[0]_TX.TRMREQ, [7] MCTL[0]_RX.TRMREQ, [6] MCTL[0]_TX.RECREQ, [6] MCTL[0]_RX.RECREQ, [4] MCTL[0]_TX.ONESHOT, [4] MCTL[0]_RX.ONESHOT, [2] MCTL[0]_TX.TRMABT, [2] MCTL[0]_RX.MSGLOST, [1] MCTL[0]_TX.TRMACTIVE, [1] MCTL[0]_RX.INVALDATA, [0] MCTL[0]_TX.SENTDATA, [0] MCTL[0]_RX.NEWDATA
0x90821 CAN0
  [7] MCTL[1]_TX.TRMREQ, [7] MCTL[1]_RX.TRMREQ, [6] MCTL[1]_TX.RECREQ, [6] MCTL[1]_RX.RECREQ, [4] MCTL[1]_TX.ONESHOT, [4] MCTL[1]_RX.ONESHOT, [2] MCTL[1]_TX.TRMABT, [2] MCTL[1]_RX.MSGLOST, [1] MCTL[1]_TX.TRMACTIVE, [1] MCTL[1]_RX.INVALDATA, [0] MCTL[1]_TX.SENTDATA, [0] MCTL[1]_RX.NEWDATA
0x90822 CAN0
  [7] MCTL[2]_TX.TRMREQ, [7] MCTL[2]_RX.TRMREQ, [6] MCTL[2]_TX.RECREQ, [6] MCTL[2]_RX.RECREQ, [4] MCTL[2]_TX.ONESHOT, [4] MCTL[2]_RX.ONESHOT, [2] MCTL[2]_TX.TRMABT, [2] MCTL[2]_RX.MSGLOST, [1] MCTL[2]_TX.TRMACTIVE, [1] MCTL[2]_RX.INVALDATA, [0] MCTL[2]_TX.SENTDATA, [0] MCTL[2]_RX.NEWDATA
0x90823 CAN0
  [7] MCTL[3]_TX.TRMREQ, [7] MCTL[3]_RX.TRMREQ, [6] MCTL[3]_TX.RECREQ, [6] MCTL[3]_RX.RECREQ, [4] MCTL[3]_TX.ONESHOT, [4] MCTL[3]_RX.ONESHOT, [2] MCTL[3]_TX.TRMABT, [2] MCTL[3]_RX.MSGLOST, [1] MCTL[3]_TX.TRMACTIVE, [1] MCTL[3]_RX.INVALDATA, [0] MCTL[3]_TX.SENTDATA, [0] MCTL[3]_RX.NEWDATA
0x90824 CAN0
  [7] MCTL[4]_TX.TRMREQ, [7] MCTL[4]_RX.TRMREQ, [6] MCTL[4]_TX.RECREQ, [6] MCTL[4]_RX.RECREQ, [4] MCTL[4]_TX.ONESHOT, [4] MCTL[4]_RX.ONESHOT, [2] MCTL[4]_TX.TRMABT, [2] MCTL[4]_RX.MSGLOST, [1] MCTL[4]_TX.TRMACTIVE, [1] MCTL[4]_RX.INVALDATA, [0] MCTL[4]_TX.SENTDATA, [0] MCTL[4]_RX.NEWDATA
0x90825 CAN0
  [7] MCTL[5]_TX.TRMREQ, [7] MCTL[5]_RX.TRMREQ, [6] MCTL[5]_TX.RECREQ, [6] MCTL[5]_RX.RECREQ, [4] MCTL[5]_TX.ONESHOT, [4] MCTL[5]_RX.ONESHOT, [2] MCTL[5]_TX.TRMABT, [2] MCTL[5]_RX.MSGLOST, [1] MCTL[5]_TX.TRMACTIVE, [1] MCTL[5]_RX.INVALDATA, [0] MCTL[5]_TX.SENTDATA, [0] MCTL[5]_RX.NEWDATA
0x90826 CAN0
  [7] MCTL[6]_TX.TRMREQ, [7] MCTL[6]_RX.TRMREQ, [6] MCTL[6]_TX.RECREQ, [6] MCTL[6]_RX.RECREQ, [4] MCTL[6]_TX.ONESHOT, [4] MCTL[6]_RX.ONESHOT, [2] MCTL[6]_TX.TRMABT, [2] MCTL[6]_RX.MSGLOST, [1] MCTL[6]_TX.TRMACTIVE, [1] MCTL[6]_RX.INVALDATA, [0] MCTL[6]_TX.SENTDATA, [0] MCTL[6]_RX.NEWDATA
0x90827 CAN0
  [7] MCTL[7]_TX.TRMREQ, [7] MCTL[7]_RX.TRMREQ, [6] MCTL[7]_TX.RECREQ, [6] MCTL[7]_RX.RECREQ, [4] MCTL[7]_TX.ONESHOT, [4] MCTL[7]_RX.ONESHOT, [2] MCTL[7]_TX.TRMABT, [2] MCTL[7]_RX.MSGLOST, [1] MCTL[7]_TX.TRMACTIVE, [1] MCTL[7]_RX.INVALDATA, [0] MCTL[7]_TX.SENTDATA, [0] MCTL[7]_RX.NEWDATA
0x90828 CAN0
  [7] MCTL[8]_TX.TRMREQ, [7] MCTL[8]_RX.TRMREQ, [6] MCTL[8]_TX.RECREQ, [6] MCTL[8]_RX.RECREQ, [4] MCTL[8]_TX.ONESHOT, [4] MCTL[8]_RX.ONESHOT, [2] MCTL[8]_TX.TRMABT, [2] MCTL[8]_RX.MSGLOST, [1] MCTL[8]_TX.TRMACTIVE, [1] MCTL[8]_RX.INVALDATA, [0] MCTL[8]_TX.SENTDATA, [0] MCTL[8]_RX.NEWDATA
0x90829 CAN0
  [7] MCTL[9]_TX.TRMREQ, [7] MCTL[9]_RX.TRMREQ, [6] MCTL[9]_TX.RECREQ, [6] MCTL[9]_RX.RECREQ, [4] MCTL[9]_TX.ONESHOT, [4] MCTL[9]_RX.ONESHOT, [2] MCTL[9]_TX.TRMABT, [2] MCTL[9]_RX.MSGLOST, [1] MCTL[9]_TX.TRMACTIVE, [1] MCTL[9]_RX.INVALDATA, [0] MCTL[9]_TX.SENTDATA, [0] MCTL[9]_RX.NEWDATA
0x9082A CAN0
  [7] MCTL[10]_TX.TRMREQ, [7] MCTL[10]_RX.TRMREQ, [6] MCTL[10]_TX.RECREQ, [6] MCTL[10]_RX.RECREQ, [4] MCTL[10]_TX.ONESHOT, [4] MCTL[10]_RX.ONESHOT, [2] MCTL[10]_TX.TRMABT, [2] MCTL[10]_RX.MSGLOST, [1] MCTL[10]_TX.TRMACTIVE, [1] MCTL[10]_RX.INVALDATA, [0] MCTL[10]_TX.SENTDATA, [0] MCTL[10]_RX.NEWDATA
0x9082B CAN0
  [7] MCTL[11]_TX.TRMREQ, [7] MCTL[11]_RX.TRMREQ, [6] MCTL[11]_TX.RECREQ, [6] MCTL[11]_RX.RECREQ, [4] MCTL[11]_TX.ONESHOT, [4] MCTL[11]_RX.ONESHOT, [2] MCTL[11]_TX.TRMABT, [2] MCTL[11]_RX.MSGLOST, [1] MCTL[11]_TX.TRMACTIVE, [1] MCTL[11]_RX.INVALDATA, [0] MCTL[11]_TX.SENTDATA, [0] MCTL[11]_RX.NEWDATA
0x9082C CAN0
  [7] MCTL[12]_TX.TRMREQ, [7] MCTL[12]_RX.TRMREQ, [6] MCTL[12]_TX.RECREQ, [6] MCTL[12]_RX.RECREQ, [4] MCTL[12]_TX.ONESHOT, [4] MCTL[12]_RX.ONESHOT, [2] MCTL[12]_TX.TRMABT, [2] MCTL[12]_RX.MSGLOST, [1] MCTL[12]_TX.TRMACTIVE, [1] MCTL[12]_RX.INVALDATA, [0] MCTL[12]_TX.SENTDATA, [0] MCTL[12]_RX.NEWDATA
0x9082D CAN0
  [7] MCTL[13]_TX.TRMREQ, [7] MCTL[13]_RX.TRMREQ, [6] MCTL[13]_TX.RECREQ, [6] MCTL[13]_RX.RECREQ, [4] MCTL[13]_TX.ONESHOT, [4] MCTL[13]_RX.ONESHOT, [2] MCTL[13]_TX.TRMABT, [2] MCTL[13]_RX.MSGLOST, [1] MCTL[13]_TX.TRMACTIVE, [1] MCTL[13]_RX.INVALDATA, [0] MCTL[13]_TX.SENTDATA, [0] MCTL[13]_RX.NEWDATA
0x9082E CAN0
  [7] MCTL[14]_TX.TRMREQ, [7] MCTL[14]_RX.TRMREQ, [6] MCTL[14]_TX.RECREQ, [6] MCTL[14]_RX.RECREQ, [4] MCTL[14]_TX.ONESHOT, [4] MCTL[14]_RX.ONESHOT, [2] MCTL[14]_TX.TRMABT, [2] MCTL[14]_RX.MSGLOST, [1] MCTL[14]_TX.TRMACTIVE, [1] MCTL[14]_RX.INVALDATA, [0] MCTL[14]_TX.SENTDATA, [0] MCTL[14]_RX.NEWDATA
0x9082F CAN0
  [7] MCTL[15]_TX.TRMREQ, [7] MCTL[15]_RX.TRMREQ, [6] MCTL[15]_TX.RECREQ, [6] MCTL[15]_RX.RECREQ, [4] MCTL[15]_TX.ONESHOT, [4] MCTL[15]_RX.ONESHOT, [2] MCTL[15]_TX.TRMABT, [2] MCTL[15]_RX.MSGLOST, [1] MCTL[15]_TX.TRMACTIVE, [1] MCTL[15]_RX.INVALDATA, [0] MCTL[15]_TX.SENTDATA, [0] MCTL[15]_RX.NEWDATA
0x90830 CAN0
  [7] MCTL[16]_TX.TRMREQ, [7] MCTL[16]_RX.TRMREQ, [6] MCTL[16]_TX.RECREQ, [6] MCTL[16]_RX.RECREQ, [4] MCTL[16]_TX.ONESHOT, [4] MCTL[16]_RX.ONESHOT, [2] MCTL[16]_TX.TRMABT, [2] MCTL[16]_RX.MSGLOST, [1] MCTL[16]_TX.TRMACTIVE, [1] MCTL[16]_RX.INVALDATA, [0] MCTL[16]_TX.SENTDATA, [0] MCTL[16]_RX.NEWDATA
0x90831 CAN0
  [7] MCTL[17]_TX.TRMREQ, [7] MCTL[17]_RX.TRMREQ, [6] MCTL[17]_TX.RECREQ, [6] MCTL[17]_RX.RECREQ, [4] MCTL[17]_TX.ONESHOT, [4] MCTL[17]_RX.ONESHOT, [2] MCTL[17]_TX.TRMABT, [2] MCTL[17]_RX.MSGLOST, [1] MCTL[17]_TX.TRMACTIVE, [1] MCTL[17]_RX.INVALDATA, [0] MCTL[17]_TX.SENTDATA, [0] MCTL[17]_RX.NEWDATA
0x90832 CAN0
  [7] MCTL[18]_TX.TRMREQ, [7] MCTL[18]_RX.TRMREQ, [6] MCTL[18]_TX.RECREQ, [6] MCTL[18]_RX.RECREQ, [4] MCTL[18]_TX.ONESHOT, [4] MCTL[18]_RX.ONESHOT, [2] MCTL[18]_TX.TRMABT, [2] MCTL[18]_RX.MSGLOST, [1] MCTL[18]_TX.TRMACTIVE, [1] MCTL[18]_RX.INVALDATA, [0] MCTL[18]_TX.SENTDATA, [0] MCTL[18]_RX.NEWDATA
0x90833 CAN0
  [7] MCTL[19]_TX.TRMREQ, [7] MCTL[19]_RX.TRMREQ, [6] MCTL[19]_TX.RECREQ, [6] MCTL[19]_RX.RECREQ, [4] MCTL[19]_TX.ONESHOT, [4] MCTL[19]_RX.ONESHOT, [2] MCTL[19]_TX.TRMABT, [2] MCTL[19]_RX.MSGLOST, [1] MCTL[19]_TX.TRMACTIVE, [1] MCTL[19]_RX.INVALDATA, [0] MCTL[19]_TX.SENTDATA, [0] MCTL[19]_RX.NEWDATA
0x90834 CAN0
  [7] MCTL[20]_TX.TRMREQ, [7] MCTL[20]_RX.TRMREQ, [6] MCTL[20]_TX.RECREQ, [6] MCTL[20]_RX.RECREQ, [4] MCTL[20]_TX.ONESHOT, [4] MCTL[20]_RX.ONESHOT, [2] MCTL[20]_TX.TRMABT, [2] MCTL[20]_RX.MSGLOST, [1] MCTL[20]_TX.TRMACTIVE, [1] MCTL[20]_RX.INVALDATA, [0] MCTL[20]_TX.SENTDATA, [0] MCTL[20]_RX.NEWDATA
0x90835 CAN0
  [7] MCTL[21]_TX.TRMREQ, [7] MCTL[21]_RX.TRMREQ, [6] MCTL[21]_TX.RECREQ, [6] MCTL[21]_RX.RECREQ, [4] MCTL[21]_TX.ONESHOT, [4] MCTL[21]_RX.ONESHOT, [2] MCTL[21]_TX.TRMABT, [2] MCTL[21]_RX.MSGLOST, [1] MCTL[21]_TX.TRMACTIVE, [1] MCTL[21]_RX.INVALDATA, [0] MCTL[21]_TX.SENTDATA, [0] MCTL[21]_RX.NEWDATA
0x90836 CAN0
  [7] MCTL[22]_TX.TRMREQ, [7] MCTL[22]_RX.TRMREQ, [6] MCTL[22]_TX.RECREQ, [6] MCTL[22]_RX.RECREQ, [4] MCTL[22]_TX.ONESHOT, [4] MCTL[22]_RX.ONESHOT, [2] MCTL[22]_TX.TRMABT, [2] MCTL[22]_RX.MSGLOST, [1] MCTL[22]_TX.TRMACTIVE, [1] MCTL[22]_RX.INVALDATA, [0] MCTL[22]_TX.SENTDATA, [0] MCTL[22]_RX.NEWDATA
0x90837 CAN0
  [7] MCTL[23]_TX.TRMREQ, [7] MCTL[23]_RX.TRMREQ, [6] MCTL[23]_TX.RECREQ, [6] MCTL[23]_RX.RECREQ, [4] MCTL[23]_TX.ONESHOT, [4] MCTL[23]_RX.ONESHOT, [2] MCTL[23]_TX.TRMABT, [2] MCTL[23]_RX.MSGLOST, [1] MCTL[23]_TX.TRMACTIVE, [1] MCTL[23]_RX.INVALDATA, [0] MCTL[23]_TX.SENTDATA, [0] MCTL[23]_RX.NEWDATA
0x90838 CAN0
  [7] MCTL[24]_TX.TRMREQ, [7] MCTL[24]_RX.TRMREQ, [6] MCTL[24]_TX.RECREQ, [6] MCTL[24]_RX.RECREQ, [4] MCTL[24]_TX.ONESHOT, [4] MCTL[24]_RX.ONESHOT, [2] MCTL[24]_TX.TRMABT, [2] MCTL[24]_RX.MSGLOST, [1] MCTL[24]_TX.TRMACTIVE, [1] MCTL[24]_RX.INVALDATA, [0] MCTL[24]_TX.SENTDATA, [0] MCTL[24]_RX.NEWDATA
0x90839 CAN0
  [7] MCTL[25]_TX.TRMREQ, [7] MCTL[25]_RX.TRMREQ, [6] MCTL[25]_TX.RECREQ, [6] MCTL[25]_RX.RECREQ, [4] MCTL[25]_TX.ONESHOT, [4] MCTL[25]_RX.ONESHOT, [2] MCTL[25]_TX.TRMABT, [2] MCTL[25]_RX.MSGLOST, [1] MCTL[25]_TX.TRMACTIVE, [1] MCTL[25]_RX.INVALDATA, [0] MCTL[25]_TX.SENTDATA, [0] MCTL[25]_RX.NEWDATA
0x9083A CAN0
  [7] MCTL[26]_TX.TRMREQ, [7] MCTL[26]_RX.TRMREQ, [6] MCTL[26]_TX.RECREQ, [6] MCTL[26]_RX.RECREQ, [4] MCTL[26]_TX.ONESHOT, [4] MCTL[26]_RX.ONESHOT, [2] MCTL[26]_TX.TRMABT, [2] MCTL[26]_RX.MSGLOST, [1] MCTL[26]_TX.TRMACTIVE, [1] MCTL[26]_RX.INVALDATA, [0] MCTL[26]_TX.SENTDATA, [0] MCTL[26]_RX.NEWDATA
0x9083B CAN0
  [7] MCTL[27]_TX.TRMREQ, [7] MCTL[27]_RX.TRMREQ, [6] MCTL[27]_TX.RECREQ, [6] MCTL[27]_RX.RECREQ, [4] MCTL[27]_TX.ONESHOT, [4] MCTL[27]_RX.ONESHOT, [2] MCTL[27]_TX.TRMABT, [2] MCTL[27]_RX.MSGLOST, [1] MCTL[27]_TX.TRMACTIVE, [1] MCTL[27]_RX.INVALDATA, [0] MCTL[27]_TX.SENTDATA, [0] MCTL[27]_RX.NEWDATA
0x9083C CAN0
  [7] MCTL[28]_TX.TRMREQ, [7] MCTL[28]_RX.TRMREQ, [6] MCTL[28]_TX.RECREQ, [6] MCTL[28]_RX.RECREQ, [4] MCTL[28]_TX.ONESHOT, [4] MCTL[28]_RX.ONESHOT, [2] MCTL[28]_TX.TRMABT, [2] MCTL[28]_RX.MSGLOST, [1] MCTL[28]_TX.TRMACTIVE, [1] MCTL[28]_RX.INVALDATA, [0] MCTL[28]_TX.SENTDATA, [0] MCTL[28]_RX.NEWDATA
0x9083D CAN0
  [7] MCTL[29]_TX.TRMREQ, [7] MCTL[29]_RX.TRMREQ, [6] MCTL[29]_TX.RECREQ, [6] MCTL[29]_RX.RECREQ, [4] MCTL[29]_TX.ONESHOT, [4] MCTL[29]_RX.ONESHOT, [2] MCTL[29]_TX.TRMABT, [2] MCTL[29]_RX.MSGLOST, [1] MCTL[29]_TX.TRMACTIVE, [1] MCTL[29]_RX.INVALDATA, [0] MCTL[29]_TX.SENTDATA, [0] MCTL[29]_RX.NEWDATA
0x9083E CAN0
  [7] MCTL[30]_TX.TRMREQ, [7] MCTL[30]_RX.TRMREQ, [6] MCTL[30]_TX.RECREQ, [6] MCTL[30]_RX.RECREQ, [4] MCTL[30]_TX.ONESHOT, [4] MCTL[30]_RX.ONESHOT, [2] MCTL[30]_TX.TRMABT, [2] MCTL[30]_RX.MSGLOST, [1] MCTL[30]_TX.TRMACTIVE, [1] MCTL[30]_RX.INVALDATA, [0] MCTL[30]_TX.SENTDATA, [0] MCTL[30]_RX.NEWDATA
0x9083F CAN0
  [7] MCTL[31]_TX.TRMREQ, [7] MCTL[31]_RX.TRMREQ, [6] MCTL[31]_TX.RECREQ, [6] MCTL[31]_RX.RECREQ, [4] MCTL[31]_TX.ONESHOT, [4] MCTL[31]_RX.ONESHOT, [2] MCTL[31]_TX.TRMABT, [2] MCTL[31]_RX.MSGLOST, [1] MCTL[31]_TX.TRMACTIVE, [1] MCTL[31]_RX.INVALDATA, [0] MCTL[31]_TX.SENTDATA, [0] MCTL[31]_RX.NEWDATA
{0x90840+0x1000*i} CAN{i} 16-bit (i=0..2)
  [13] CTLR.RBOC, [12:11] CTLR.BOM, [10] CTLR.SLPM, [9:8] CTLR.CANM, [7:6] CTLR.TSPS, [5] CTLR.TSRC, [4] CTLR.TPM, [3] CTLR.MLM, [2:1] CTLR.IDFM, [0] CTLR.MBM
{0x90842+0x1000*i} CAN{i} 16-bit (i=0..2)
  [14] STR.RECST, [13] STR.TRMST, [12] STR.BOST, [11] STR.EPST, [10] STR.SLPST, [9] STR.HLTST, [8] STR.RSTST, [7] STR.EST, [6] STR.TABST, [5] STR.FMLST, [4] STR.NMLST, [3] STR.TFST, [2] STR.RFST, [1] STR.SDST, [0] STR.NDST
{0x90844+0x1000*i} CAN{i} 32-bit (i=0..2)
  [31:28] BCR.TSEG1, [25:16] BCR.BRP, [13:12] BCR.SJW, [10:8] BCR.TSEG2, [0] BCR.CCLKS
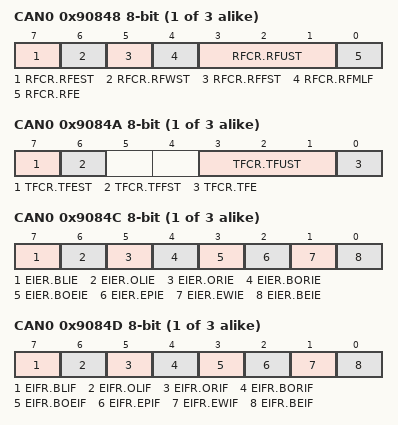
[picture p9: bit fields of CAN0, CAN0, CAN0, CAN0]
{0x90848+0x1000*i} CAN{i} (i=0..2)
  [7] RFCR.RFEST, [6] RFCR.RFWST, [5] RFCR.RFFST, [4] RFCR.RFMLF, [3:1] RFCR.RFUST, [0] RFCR.RFE
{0x9084A+0x1000*i} CAN{i} (i=0..2)
  [7] TFCR.TFEST, [6] TFCR.TFFST, [3:1] TFCR.TFUST, [0] TFCR.TFE
{0x9084C+0x1000*i} CAN{i} (i=0..2)
  [7] EIER.BLIE, [6] EIER.OLIE, [5] EIER.ORIE, [4] EIER.BORIE, [3] EIER.BOEIE, [2] EIER.EPIE, [1] EIER.EWIE, [0] EIER.BEIE
{0x9084D+0x1000*i} CAN{i} (i=0..2)
  [7] EIFR.BLIF, [6] EIFR.OLIF, [5] EIFR.ORIF, [4] EIFR.BORIF, [3] EIFR.BOEIF, [2] EIFR.EPIF, [1] EIFR.EWIF, [0] EIFR.BEIF
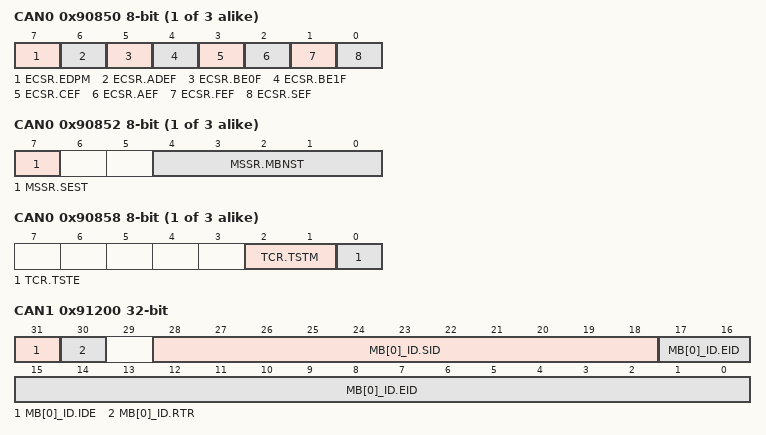
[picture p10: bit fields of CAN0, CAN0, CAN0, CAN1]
{0x90850+0x1000*i} CAN{i} (i=0..2)
  [7] ECSR.EDPM, [6] ECSR.ADEF, [5] ECSR.BE0F, [4] ECSR.BE1F, [3] ECSR.CEF, [2] ECSR.AEF, [1] ECSR.FEF, [0] ECSR.SEF
{0x90852+0x1000*i} CAN{i} (i=0..2)
  [7] MSSR.SEST, [4:0] MSSR.MBNST
{0x90853+0x1000*i} CAN{i} (i=0..2)
  [1:0] MSMR.MBSM
{0x90858+0x1000*i} CAN{i} (i=0..2)
  [2:1] TCR.TSTM, [0] TCR.TSTE
0x91200 CAN1 32-bit
  [31] MB[0]_ID.IDE, [30] MB[0]_ID.RTR, [28:18] MB[0]_ID.SID, [17:0] MB[0]_ID.EID
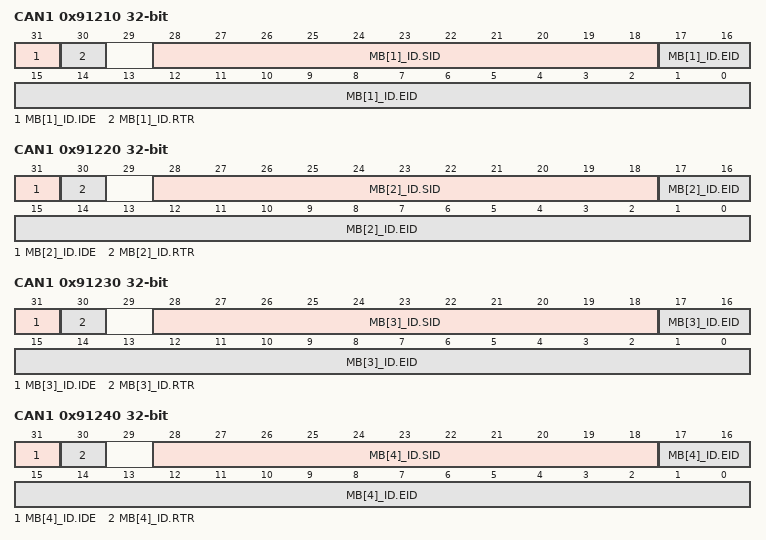
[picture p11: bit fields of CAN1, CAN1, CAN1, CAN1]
0x91210 CAN1 32-bit
  [31] MB[1]_ID.IDE, [30] MB[1]_ID.RTR, [28:18] MB[1]_ID.SID, [17:0] MB[1]_ID.EID
0x91220 CAN1 32-bit
  [31] MB[2]_ID.IDE, [30] MB[2]_ID.RTR, [28:18] MB[2]_ID.SID, [17:0] MB[2]_ID.EID
0x91230 CAN1 32-bit
  [31] MB[3]_ID.IDE, [30] MB[3]_ID.RTR, [28:18] MB[3]_ID.SID, [17:0] MB[3]_ID.EID
0x91240 CAN1 32-bit
  [31] MB[4]_ID.IDE, [30] MB[4]_ID.RTR, [28:18] MB[4]_ID.SID, [17:0] MB[4]_ID.EID
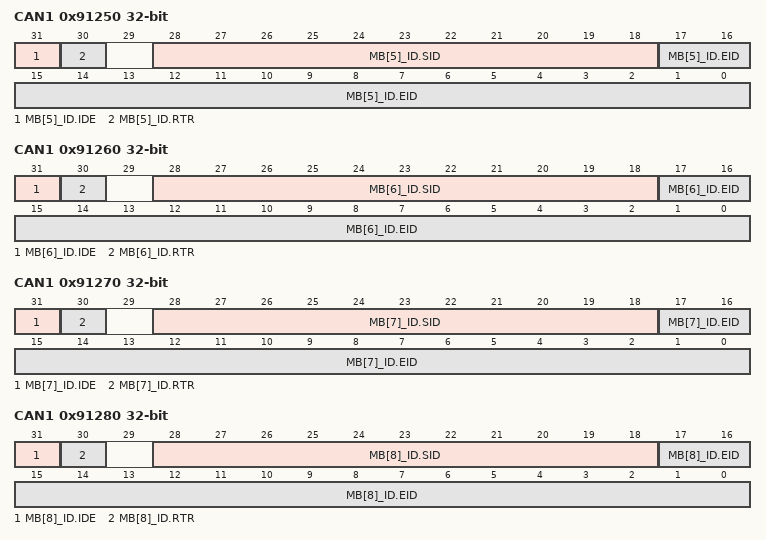
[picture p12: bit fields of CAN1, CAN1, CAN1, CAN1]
0x91250 CAN1 32-bit
  [31] MB[5]_ID.IDE, [30] MB[5]_ID.RTR, [28:18] MB[5]_ID.SID, [17:0] MB[5]_ID.EID
0x91260 CAN1 32-bit
  [31] MB[6]_ID.IDE, [30] MB[6]_ID.RTR, [28:18] MB[6]_ID.SID, [17:0] MB[6]_ID.EID
0x91270 CAN1 32-bit
  [31] MB[7]_ID.IDE, [30] MB[7]_ID.RTR, [28:18] MB[7]_ID.SID, [17:0] MB[7]_ID.EID
0x91280 CAN1 32-bit
  [31] MB[8]_ID.IDE, [30] MB[8]_ID.RTR, [28:18] MB[8]_ID.SID, [17:0] MB[8]_ID.EID
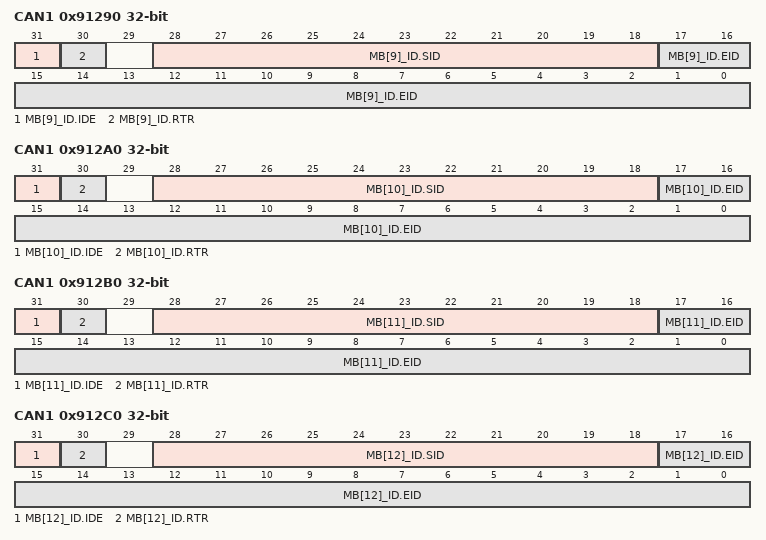
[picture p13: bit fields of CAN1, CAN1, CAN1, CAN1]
0x91290 CAN1 32-bit
  [31] MB[9]_ID.IDE, [30] MB[9]_ID.RTR, [28:18] MB[9]_ID.SID, [17:0] MB[9]_ID.EID
0x912A0 CAN1 32-bit
  [31] MB[10]_ID.IDE, [30] MB[10]_ID.RTR, [28:18] MB[10]_ID.SID, [17:0] MB[10]_ID.EID
0x912B0 CAN1 32-bit
  fields as CAN0
0x912C0 CAN1 32-bit
  [31] MB[12]_ID.IDE, [30] MB[12]_ID.RTR, [28:18] MB[12]_ID.SID, [17:0] MB[12]_ID.EID
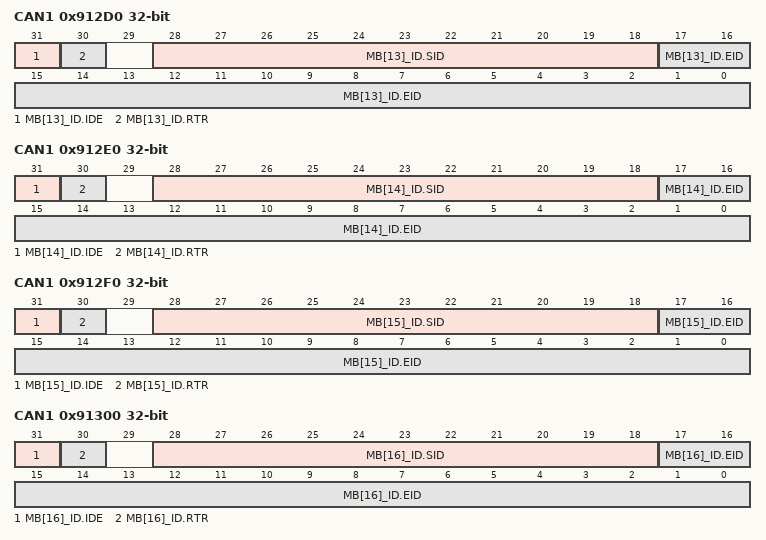
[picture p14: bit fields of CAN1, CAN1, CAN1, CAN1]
0x912D0 CAN1 32-bit
  [31] MB[13]_ID.IDE, [30] MB[13]_ID.RTR, [28:18] MB[13]_ID.SID, [17:0] MB[13]_ID.EID
0x912E0 CAN1 32-bit
  [31] MB[14]_ID.IDE, [30] MB[14]_ID.RTR, [28:18] MB[14]_ID.SID, [17:0] MB[14]_ID.EID
0x912F0 CAN1 32-bit
  [31] MB[15]_ID.IDE, [30] MB[15]_ID.RTR, [28:18] MB[15]_ID.SID, [17:0] MB[15]_ID.EID
0x91300 CAN1 32-bit
  [31] MB[16]_ID.IDE, [30] MB[16]_ID.RTR, [28:18] MB[16]_ID.SID, [17:0] MB[16]_ID.EID
0x91310 CAN1 32-bit
  [31] MB[17]_ID.IDE, [30] MB[17]_ID.RTR, [28:18] MB[17]_ID.SID, [17:0] MB[17]_ID.EID
0x91320 CAN1 32-bit
  [31] MB[18]_ID.IDE, [30] MB[18]_ID.RTR, [28:18] MB[18]_ID.SID, [17:0] MB[18]_ID.EID
0x91330 CAN1 32-bit
  [31] MB[19]_ID.IDE, [30] MB[19]_ID.RTR, [28:18] MB[19]_ID.SID, [17:0] MB[19]_ID.EID
0x91340 CAN1 32-bit
  [31] MB[20]_ID.IDE, [30] MB[20]_ID.RTR, [28:18] MB[20]_ID.SID, [17:0] MB[20]_ID.EID
0x91350 CAN1 32-bit
  [31] MB[21]_ID.IDE, [30] MB[21]_ID.RTR, [28:18] MB[21]_ID.SID, [17:0] MB[21]_ID.EID
0x91360 CAN1 32-bit
  [31] MB[22]_ID.IDE, [30] MB[22]_ID.RTR, [28:18] MB[22]_ID.SID, [17:0] MB[22]_ID.EID
0x91370 CAN1 32-bit
  [31] MB[23]_ID.IDE, [30] MB[23]_ID.RTR, [28:18] MB[23]_ID.SID, [17:0] MB[23]_ID.EID
0x91380 CAN1 32-bit
  [31] MB[24]_ID.IDE, [30] MB[24]_ID.RTR, [28:18] MB[24]_ID.SID, [17:0] MB[24]_ID.EID
0x91390 CAN1 32-bit
  [31] MB[25]_ID.IDE, [30] MB[25]_ID.RTR, [28:18] MB[25]_ID.SID, [17:0] MB[25]_ID.EID
0x913A0 CAN1 32-bit
  [31] MB[26]_ID.IDE, [30] MB[26]_ID.RTR, [28:18] MB[26]_ID.SID, [17:0] MB[26]_ID.EID
0x913B0 CAN1 32-bit
  [31] MB[27]_ID.IDE, [30] MB[27]_ID.RTR, [28:18] MB[27]_ID.SID, [17:0] MB[27]_ID.EID
0x913C0 CAN1 32-bit
  [31] MB[28]_ID.IDE, [30] MB[28]_ID.RTR, [28:18] MB[28]_ID.SID, [17:0] MB[28]_ID.EID
0x913D0 CAN1 32-bit
  [31] MB[29]_ID.IDE, [30] MB[29]_ID.RTR, [28:18] MB[29]_ID.SID, [17:0] MB[29]_ID.EID
0x913E0 CAN1 32-bit
  [31] MB[30]_ID.IDE, [30] MB[30]_ID.RTR, [28:18] MB[30]_ID.SID, [17:0] MB[30]_ID.EID
0x913F0 CAN1 32-bit
  [31] MB[31]_ID.IDE, [30] MB[31]_ID.RTR, [28:18] MB[31]_ID.SID, [17:0] MB[31]_ID.EID
0x91400 CAN1 32-bit
  [28:18] MKR[0].SID, [17:0] MKR[0].EID
0x91404 CAN1 32-bit
  [28:18] MKR[1].SID, [17:0] MKR[1].EID
0x91408 CAN1 32-bit
  [28:18] MKR[2].SID, [17:0] MKR[2].EID
0x9140C CAN1 32-bit
  [28:18] MKR[3].SID, [17:0] MKR[3].EID
0x91410 CAN1 32-bit
  [28:18] MKR[4].SID, [17:0] MKR[4].EID
0x91414 CAN1 32-bit
  [28:18] MKR[5].SID, [17:0] MKR[5].EID
0x91418 CAN1 32-bit
  [28:18] MKR[6].SID, [17:0] MKR[6].EID
0x9141C CAN1 32-bit
  [28:18] MKR[7].SID, [17:0] MKR[7].EID
0x91420 CAN1 32-bit
  [31] FIDCR0.IDE, [30] FIDCR0.RTR, [28:18] FIDCR0.SID, [17:0] FIDCR0.EID
0x91424 CAN1 32-bit
  [31] FIDCR1.IDE, [30] FIDCR1.RTR, [28:18] FIDCR1.SID, [17:0] FIDCR1.EID
0x91820 CAN1
  [7] MCTL[0]_TX.TRMREQ, [7] MCTL[0]_RX.TRMREQ, [6] MCTL[0]_TX.RECREQ, [6] MCTL[0]_RX.RECREQ, [4] MCTL[0]_TX.ONESHOT, [4] MCTL[0]_RX.ONESHOT, [2] MCTL[0]_TX.TRMABT, [2] MCTL[0]_RX.MSGLOST, [1] MCTL[0]_TX.TRMACTIVE, [1] MCTL[0]_RX.INVALDATA, [0] MCTL[0]_TX.SENTDATA, [0] MCTL[0]_RX.NEWDATA
0x91821 CAN1
  [7] MCTL[1]_TX.TRMREQ, [7] MCTL[1]_RX.TRMREQ, [6] MCTL[1]_TX.RECREQ, [6] MCTL[1]_RX.RECREQ, [4] MCTL[1]_TX.ONESHOT, [4] MCTL[1]_RX.ONESHOT, [2] MCTL[1]_TX.TRMABT, [2] MCTL[1]_RX.MSGLOST, [1] MCTL[1]_TX.TRMACTIVE, [1] MCTL[1]_RX.INVALDATA, [0] MCTL[1]_TX.SENTDATA, [0] MCTL[1]_RX.NEWDATA
0x91822 CAN1
  [7] MCTL[2]_TX.TRMREQ, [7] MCTL[2]_RX.TRMREQ, [6] MCTL[2]_TX.RECREQ, [6] MCTL[2]_RX.RECREQ, [4] MCTL[2]_TX.ONESHOT, [4] MCTL[2]_RX.ONESHOT, [2] MCTL[2]_TX.TRMABT, [2] MCTL[2]_RX.MSGLOST, [1] MCTL[2]_TX.TRMACTIVE, [1] MCTL[2]_RX.INVALDATA, [0] MCTL[2]_TX.SENTDATA, [0] MCTL[2]_RX.NEWDATA
0x91823 CAN1
  [7] MCTL[3]_TX.TRMREQ, [7] MCTL[3]_RX.TRMREQ, [6] MCTL[3]_TX.RECREQ, [6] MCTL[3]_RX.RECREQ, [4] MCTL[3]_TX.ONESHOT, [4] MCTL[3]_RX.ONESHOT, [2] MCTL[3]_TX.TRMABT, [2] MCTL[3]_RX.MSGLOST, [1] MCTL[3]_TX.TRMACTIVE, [1] MCTL[3]_RX.INVALDATA, [0] MCTL[3]_TX.SENTDATA, [0] MCTL[3]_RX.NEWDATA
0x91824 CAN1
  [7] MCTL[4]_TX.TRMREQ, [7] MCTL[4]_RX.TRMREQ, [6] MCTL[4]_TX.RECREQ, [6] MCTL[4]_RX.RECREQ, [4] MCTL[4]_TX.ONESHOT, [4] MCTL[4]_RX.ONESHOT, [2] MCTL[4]_TX.TRMABT, [2] MCTL[4]_RX.MSGLOST, [1] MCTL[4]_TX.TRMACTIVE, [1] MCTL[4]_RX.INVALDATA, [0] MCTL[4]_TX.SENTDATA, [0] MCTL[4]_RX.NEWDATA
0x91825 CAN1
  [7] MCTL[5]_TX.TRMREQ, [7] MCTL[5]_RX.TRMREQ, [6] MCTL[5]_TX.RECREQ, [6] MCTL[5]_RX.RECREQ, [4] MCTL[5]_TX.ONESHOT, [4] MCTL[5]_RX.ONESHOT, [2] MCTL[5]_TX.TRMABT, [2] MCTL[5]_RX.MSGLOST, [1] MCTL[5]_TX.TRMACTIVE, [1] MCTL[5]_RX.INVALDATA, [0] MCTL[5]_TX.SENTDATA, [0] MCTL[5]_RX.NEWDATA
0x91826 CAN1
  [7] MCTL[6]_TX.TRMREQ, [7] MCTL[6]_RX.TRMREQ, [6] MCTL[6]_TX.RECREQ, [6] MCTL[6]_RX.RECREQ, [4] MCTL[6]_TX.ONESHOT, [4] MCTL[6]_RX.ONESHOT, [2] MCTL[6]_TX.TRMABT, [2] MCTL[6]_RX.MSGLOST, [1] MCTL[6]_TX.TRMACTIVE, [1] MCTL[6]_RX.INVALDATA, [0] MCTL[6]_TX.SENTDATA, [0] MCTL[6]_RX.NEWDATA
0x91827 CAN1
  [7] MCTL[7]_TX.TRMREQ, [7] MCTL[7]_RX.TRMREQ, [6] MCTL[7]_TX.RECREQ, [6] MCTL[7]_RX.RECREQ, [4] MCTL[7]_TX.ONESHOT, [4] MCTL[7]_RX.ONESHOT, [2] MCTL[7]_TX.TRMABT, [2] MCTL[7]_RX.MSGLOST, [1] MCTL[7]_TX.TRMACTIVE, [1] MCTL[7]_RX.INVALDATA, [0] MCTL[7]_TX.SENTDATA, [0] MCTL[7]_RX.NEWDATA
0x91828 CAN1
  [7] MCTL[8]_TX.TRMREQ, [7] MCTL[8]_RX.TRMREQ, [6] MCTL[8]_TX.RECREQ, [6] MCTL[8]_RX.RECREQ, [4] MCTL[8]_TX.ONESHOT, [4] MCTL[8]_RX.ONESHOT, [2] MCTL[8]_TX.TRMABT, [2] MCTL[8]_RX.MSGLOST, [1] MCTL[8]_TX.TRMACTIVE, [1] MCTL[8]_RX.INVALDATA, [0] MCTL[8]_TX.SENTDATA, [0] MCTL[8]_RX.NEWDATA
0x91829 CAN1
  [7] MCTL[9]_TX.TRMREQ, [7] MCTL[9]_RX.TRMREQ, [6] MCTL[9]_TX.RECREQ, [6] MCTL[9]_RX.RECREQ, [4] MCTL[9]_TX.ONESHOT, [4] MCTL[9]_RX.ONESHOT, [2] MCTL[9]_TX.TRMABT, [2] MCTL[9]_RX.MSGLOST, [1] MCTL[9]_TX.TRMACTIVE, [1] MCTL[9]_RX.INVALDATA, [0] MCTL[9]_TX.SENTDATA, [0] MCTL[9]_RX.NEWDATA
0x9182A CAN1
  [7] MCTL[10]_TX.TRMREQ, [7] MCTL[10]_RX.TRMREQ, [6] MCTL[10]_TX.RECREQ, [6] MCTL[10]_RX.RECREQ, [4] MCTL[10]_TX.ONESHOT, [4] MCTL[10]_RX.ONESHOT, [2] MCTL[10]_TX.TRMABT, [2] MCTL[10]_RX.MSGLOST, [1] MCTL[10]_TX.TRMACTIVE, [1] MCTL[10]_RX.INVALDATA, [0] MCTL[10]_TX.SENTDATA, [0] MCTL[10]_RX.NEWDATA
0x9182B CAN1
  [7] MCTL[11]_TX.TRMREQ, [7] MCTL[11]_RX.TRMREQ, [6] MCTL[11]_TX.RECREQ, [6] MCTL[11]_RX.RECREQ, [4] MCTL[11]_TX.ONESHOT, [4] MCTL[11]_RX.ONESHOT, [2] MCTL[11]_TX.TRMABT, [2] MCTL[11]_RX.MSGLOST, [1] MCTL[11]_TX.TRMACTIVE, [1] MCTL[11]_RX.INVALDATA, [0] MCTL[11]_TX.SENTDATA, [0] MCTL[11]_RX.NEWDATA
0x9182C CAN1
  [7] MCTL[12]_TX.TRMREQ, [7] MCTL[12]_RX.TRMREQ, [6] MCTL[12]_TX.RECREQ, [6] MCTL[12]_RX.RECREQ, [4] MCTL[12]_TX.ONESHOT, [4] MCTL[12]_RX.ONESHOT, [2] MCTL[12]_TX.TRMABT, [2] MCTL[12]_RX.MSGLOST, [1] MCTL[12]_TX.TRMACTIVE, [1] MCTL[12]_RX.INVALDATA, [0] MCTL[12]_TX.SENTDATA, [0] MCTL[12]_RX.NEWDATA
0x9182D CAN1
  [7] MCTL[13]_TX.TRMREQ, [7] MCTL[13]_RX.TRMREQ, [6] MCTL[13]_TX.RECREQ, [6] MCTL[13]_RX.RECREQ, [4] MCTL[13]_TX.ONESHOT, [4] MCTL[13]_RX.ONESHOT, [2] MCTL[13]_TX.TRMABT, [2] MCTL[13]_RX.MSGLOST, [1] MCTL[13]_TX.TRMACTIVE, [1] MCTL[13]_RX.INVALDATA, [0] MCTL[13]_TX.SENTDATA, [0] MCTL[13]_RX.NEWDATA
0x9182E CAN1
  [7] MCTL[14]_TX.TRMREQ, [7] MCTL[14]_RX.TRMREQ, [6] MCTL[14]_TX.RECREQ, [6] MCTL[14]_RX.RECREQ, [4] MCTL[14]_TX.ONESHOT, [4] MCTL[14]_RX.ONESHOT, [2] MCTL[14]_TX.TRMABT, [2] MCTL[14]_RX.MSGLOST, [1] MCTL[14]_TX.TRMACTIVE, [1] MCTL[14]_RX.INVALDATA, [0] MCTL[14]_TX.SENTDATA, [0] MCTL[14]_RX.NEWDATA
0x9182F CAN1
  [7] MCTL[15]_TX.TRMREQ, [7] MCTL[15]_RX.TRMREQ, [6] MCTL[15]_TX.RECREQ, [6] MCTL[15]_RX.RECREQ, [4] MCTL[15]_TX.ONESHOT, [4] MCTL[15]_RX.ONESHOT, [2] MCTL[15]_TX.TRMABT, [2] MCTL[15]_RX.MSGLOST, [1] MCTL[15]_TX.TRMACTIVE, [1] MCTL[15]_RX.INVALDATA, [0] MCTL[15]_TX.SENTDATA, [0] MCTL[15]_RX.NEWDATA
0x91830 CAN1
  [7] MCTL[16]_TX.TRMREQ, [7] MCTL[16]_RX.TRMREQ, [6] MCTL[16]_TX.RECREQ, [6] MCTL[16]_RX.RECREQ, [4] MCTL[16]_TX.ONESHOT, [4] MCTL[16]_RX.ONESHOT, [2] MCTL[16]_TX.TRMABT, [2] MCTL[16]_RX.MSGLOST, [1] MCTL[16]_TX.TRMACTIVE, [1] MCTL[16]_RX.INVALDATA, [0] MCTL[16]_TX.SENTDATA, [0] MCTL[16]_RX.NEWDATA
0x91831 CAN1
  [7] MCTL[17]_TX.TRMREQ, [7] MCTL[17]_RX.TRMREQ, [6] MCTL[17]_TX.RECREQ, [6] MCTL[17]_RX.RECREQ, [4] MCTL[17]_TX.ONESHOT, [4] MCTL[17]_RX.ONESHOT, [2] MCTL[17]_TX.TRMABT, [2] MCTL[17]_RX.MSGLOST, [1] MCTL[17]_TX.TRMACTIVE, [1] MCTL[17]_RX.INVALDATA, [0] MCTL[17]_TX.SENTDATA, [0] MCTL[17]_RX.NEWDATA
0x91832 CAN1
  [7] MCTL[18]_TX.TRMREQ, [7] MCTL[18]_RX.TRMREQ, [6] MCTL[18]_TX.RECREQ, [6] MCTL[18]_RX.RECREQ, [4] MCTL[18]_TX.ONESHOT, [4] MCTL[18]_RX.ONESHOT, [2] MCTL[18]_TX.TRMABT, [2] MCTL[18]_RX.MSGLOST, [1] MCTL[18]_TX.TRMACTIVE, [1] MCTL[18]_RX.INVALDATA, [0] MCTL[18]_TX.SENTDATA, [0] MCTL[18]_RX.NEWDATA
0x91833 CAN1
  [7] MCTL[19]_TX.TRMREQ, [7] MCTL[19]_RX.TRMREQ, [6] MCTL[19]_TX.RECREQ, [6] MCTL[19]_RX.RECREQ, [4] MCTL[19]_TX.ONESHOT, [4] MCTL[19]_RX.ONESHOT, [2] MCTL[19]_TX.TRMABT, [2] MCTL[19]_RX.MSGLOST, [1] MCTL[19]_TX.TRMACTIVE, [1] MCTL[19]_RX.INVALDATA, [0] MCTL[19]_TX.SENTDATA, [0] MCTL[19]_RX.NEWDATA
0x91834 CAN1
  [7] MCTL[20]_TX.TRMREQ, [7] MCTL[20]_RX.TRMREQ, [6] MCTL[20]_TX.RECREQ, [6] MCTL[20]_RX.RECREQ, [4] MCTL[20]_TX.ONESHOT, [4] MCTL[20]_RX.ONESHOT, [2] MCTL[20]_TX.TRMABT, [2] MCTL[20]_RX.MSGLOST, [1] MCTL[20]_TX.TRMACTIVE, [1] MCTL[20]_RX.INVALDATA, [0] MCTL[20]_TX.SENTDATA, [0] MCTL[20]_RX.NEWDATA
0x91835 CAN1
  [7] MCTL[21]_TX.TRMREQ, [7] MCTL[21]_RX.TRMREQ, [6] MCTL[21]_TX.RECREQ, [6] MCTL[21]_RX.RECREQ, [4] MCTL[21]_TX.ONESHOT, [4] MCTL[21]_RX.ONESHOT, [2] MCTL[21]_TX.TRMABT, [2] MCTL[21]_RX.MSGLOST, [1] MCTL[21]_TX.TRMACTIVE, [1] MCTL[21]_RX.INVALDATA, [0] MCTL[21]_TX.SENTDATA, [0] MCTL[21]_RX.NEWDATA
0x91836 CAN1
  [7] MCTL[22]_TX.TRMREQ, [7] MCTL[22]_RX.TRMREQ, [6] MCTL[22]_TX.RECREQ, [6] MCTL[22]_RX.RECREQ, [4] MCTL[22]_TX.ONESHOT, [4] MCTL[22]_RX.ONESHOT, [2] MCTL[22]_TX.TRMABT, [2] MCTL[22]_RX.MSGLOST, [1] MCTL[22]_TX.TRMACTIVE, [1] MCTL[22]_RX.INVALDATA, [0] MCTL[22]_TX.SENTDATA, [0] MCTL[22]_RX.NEWDATA
0x91837 CAN1
  [7] MCTL[23]_TX.TRMREQ, [7] MCTL[23]_RX.TRMREQ, [6] MCTL[23]_TX.RECREQ, [6] MCTL[23]_RX.RECREQ, [4] MCTL[23]_TX.ONESHOT, [4] MCTL[23]_RX.ONESHOT, [2] MCTL[23]_TX.TRMABT, [2] MCTL[23]_RX.MSGLOST, [1] MCTL[23]_TX.TRMACTIVE, [1] MCTL[23]_RX.INVALDATA, [0] MCTL[23]_TX.SENTDATA, [0] MCTL[23]_RX.NEWDATA
0x91838 CAN1
  [7] MCTL[24]_TX.TRMREQ, [7] MCTL[24]_RX.TRMREQ, [6] MCTL[24]_TX.RECREQ, [6] MCTL[24]_RX.RECREQ, [4] MCTL[24]_TX.ONESHOT, [4] MCTL[24]_RX.ONESHOT, [2] MCTL[24]_TX.TRMABT, [2] MCTL[24]_RX.MSGLOST, [1] MCTL[24]_TX.TRMACTIVE, [1] MCTL[24]_RX.INVALDATA, [0] MCTL[24]_TX.SENTDATA, [0] MCTL[24]_RX.NEWDATA
0x91839 CAN1
  [7] MCTL[25]_TX.TRMREQ, [7] MCTL[25]_RX.TRMREQ, [6] MCTL[25]_TX.RECREQ, [6] MCTL[25]_RX.RECREQ, [4] MCTL[25]_TX.ONESHOT, [4] MCTL[25]_RX.ONESHOT, [2] MCTL[25]_TX.TRMABT, [2] MCTL[25]_RX.MSGLOST, [1] MCTL[25]_TX.TRMACTIVE, [1] MCTL[25]_RX.INVALDATA, [0] MCTL[25]_TX.SENTDATA, [0] MCTL[25]_RX.NEWDATA
0x9183A CAN1
  [7] MCTL[26]_TX.TRMREQ, [7] MCTL[26]_RX.TRMREQ, [6] MCTL[26]_TX.RECREQ, [6] MCTL[26]_RX.RECREQ, [4] MCTL[26]_TX.ONESHOT, [4] MCTL[26]_RX.ONESHOT, [2] MCTL[26]_TX.TRMABT, [2] MCTL[26]_RX.MSGLOST, [1] MCTL[26]_TX.TRMACTIVE, [1] MCTL[26]_RX.INVALDATA, [0] MCTL[26]_TX.SENTDATA, [0] MCTL[26]_RX.NEWDATA
0x9183B CAN1
  [7] MCTL[27]_TX.TRMREQ, [7] MCTL[27]_RX.TRMREQ, [6] MCTL[27]_TX.RECREQ, [6] MCTL[27]_RX.RECREQ, [4] MCTL[27]_TX.ONESHOT, [4] MCTL[27]_RX.ONESHOT, [2] MCTL[27]_TX.TRMABT, [2] MCTL[27]_RX.MSGLOST, [1] MCTL[27]_TX.TRMACTIVE, [1] MCTL[27]_RX.INVALDATA, [0] MCTL[27]_TX.SENTDATA, [0] MCTL[27]_RX.NEWDATA
0x9183C CAN1
  [7] MCTL[28]_TX.TRMREQ, [7] MCTL[28]_RX.TRMREQ, [6] MCTL[28]_TX.RECREQ, [6] MCTL[28]_RX.RECREQ, [4] MCTL[28]_TX.ONESHOT, [4] MCTL[28]_RX.ONESHOT, [2] MCTL[28]_TX.TRMABT, [2] MCTL[28]_RX.MSGLOST, [1] MCTL[28]_TX.TRMACTIVE, [1] MCTL[28]_RX.INVALDATA, [0] MCTL[28]_TX.SENTDATA, [0] MCTL[28]_RX.NEWDATA
0x9183D CAN1
  [7] MCTL[29]_TX.TRMREQ, [7] MCTL[29]_RX.TRMREQ, [6] MCTL[29]_TX.RECREQ, [6] MCTL[29]_RX.RECREQ, [4] MCTL[29]_TX.ONESHOT, [4] MCTL[29]_RX.ONESHOT, [2] MCTL[29]_TX.TRMABT, [2] MCTL[29]_RX.MSGLOST, [1] MCTL[29]_TX.TRMACTIVE, [1] MCTL[29]_RX.INVALDATA, [0] MCTL[29]_TX.SENTDATA, [0] MCTL[29]_RX.NEWDATA
0x9183E CAN1
  [7] MCTL[30]_TX.TRMREQ, [7] MCTL[30]_RX.TRMREQ, [6] MCTL[30]_TX.RECREQ, [6] MCTL[30]_RX.RECREQ, [4] MCTL[30]_TX.ONESHOT, [4] MCTL[30]_RX.ONESHOT, [2] MCTL[30]_TX.TRMABT, [2] MCTL[30]_RX.MSGLOST, [1] MCTL[30]_TX.TRMACTIVE, [1] MCTL[30]_RX.INVALDATA, [0] MCTL[30]_TX.SENTDATA, [0] MCTL[30]_RX.NEWDATA
0x9183F CAN1
  [7] MCTL[31]_TX.TRMREQ, [7] MCTL[31]_RX.TRMREQ, [6] MCTL[31]_TX.RECREQ, [6] MCTL[31]_RX.RECREQ, [4] MCTL[31]_TX.ONESHOT, [4] MCTL[31]_RX.ONESHOT, [2] MCTL[31]_TX.TRMABT, [2] MCTL[31]_RX.MSGLOST, [1] MCTL[31]_TX.TRMACTIVE, [1] MCTL[31]_RX.INVALDATA, [0] MCTL[31]_TX.SENTDATA, [0] MCTL[31]_RX.NEWDATA
0x92200 CAN2 32-bit
  fields as CAN1
0x92210 CAN2 32-bit
  [31] MB[1]_ID.IDE, [30] MB[1]_ID.RTR, [28:18] MB[1]_ID.SID, [17:0] MB[1]_ID.EID
0x92220 CAN2 32-bit
  [31] MB[2]_ID.IDE, [30] MB[2]_ID.RTR, [28:18] MB[2]_ID.SID, [17:0] MB[2]_ID.EID
0x92230 CAN2 32-bit
  [31] MB[3]_ID.IDE, [30] MB[3]_ID.RTR, [28:18] MB[3]_ID.SID, [17:0] MB[3]_ID.EID
0x92240 CAN2 32-bit
  [31] MB[4]_ID.IDE, [30] MB[4]_ID.RTR, [28:18] MB[4]_ID.SID, [17:0] MB[4]_ID.EID
0x92250 CAN2 32-bit
  [31] MB[5]_ID.IDE, [30] MB[5]_ID.RTR, [28:18] MB[5]_ID.SID, [17:0] MB[5]_ID.EID
0x92260 CAN2 32-bit
  [31] MB[6]_ID.IDE, [30] MB[6]_ID.RTR, [28:18] MB[6]_ID.SID, [17:0] MB[6]_ID.EID
0x92270 CAN2 32-bit
  [31] MB[7]_ID.IDE, [30] MB[7]_ID.RTR, [28:18] MB[7]_ID.SID, [17:0] MB[7]_ID.EID
0x92280 CAN2 32-bit
  [31] MB[8]_ID.IDE, [30] MB[8]_ID.RTR, [28:18] MB[8]_ID.SID, [17:0] MB[8]_ID.EID
0x92290 CAN2 32-bit
  [31] MB[9]_ID.IDE, [30] MB[9]_ID.RTR, [28:18] MB[9]_ID.SID, [17:0] MB[9]_ID.EID
0x922A0 CAN2 32-bit
  [31] MB[10]_ID.IDE, [30] MB[10]_ID.RTR, [28:18] MB[10]_ID.SID, [17:0] MB[10]_ID.EID
0x922B0 CAN2 32-bit
  fields as CAN0
0x922C0 CAN2 32-bit
  [31] MB[12]_ID.IDE, [30] MB[12]_ID.RTR, [28:18] MB[12]_ID.SID, [17:0] MB[12]_ID.EID
0x922D0 CAN2 32-bit
  [31] MB[13]_ID.IDE, [30] MB[13]_ID.RTR, [28:18] MB[13]_ID.SID, [17:0] MB[13]_ID.EID
0x922E0 CAN2 32-bit
  [31] MB[14]_ID.IDE, [30] MB[14]_ID.RTR, [28:18] MB[14]_ID.SID, [17:0] MB[14]_ID.EID
0x922F0 CAN2 32-bit
  [31] MB[15]_ID.IDE, [30] MB[15]_ID.RTR, [28:18] MB[15]_ID.SID, [17:0] MB[15]_ID.EID
0x92300 CAN2 32-bit
  [31] MB[16]_ID.IDE, [30] MB[16]_ID.RTR, [28:18] MB[16]_ID.SID, [17:0] MB[16]_ID.EID
0x92310 CAN2 32-bit
  [31] MB[17]_ID.IDE, [30] MB[17]_ID.RTR, [28:18] MB[17]_ID.SID, [17:0] MB[17]_ID.EID
0x92320 CAN2 32-bit
  [31] MB[18]_ID.IDE, [30] MB[18]_ID.RTR, [28:18] MB[18]_ID.SID, [17:0] MB[18]_ID.EID
0x92330 CAN2 32-bit
  [31] MB[19]_ID.IDE, [30] MB[19]_ID.RTR, [28:18] MB[19]_ID.SID, [17:0] MB[19]_ID.EID
0x92340 CAN2 32-bit
  [31] MB[20]_ID.IDE, [30] MB[20]_ID.RTR, [28:18] MB[20]_ID.SID, [17:0] MB[20]_ID.EID
0x92350 CAN2 32-bit
  [31] MB[21]_ID.IDE, [30] MB[21]_ID.RTR, [28:18] MB[21]_ID.SID, [17:0] MB[21]_ID.EID
0x92360 CAN2 32-bit
  [31] MB[22]_ID.IDE, [30] MB[22]_ID.RTR, [28:18] MB[22]_ID.SID, [17:0] MB[22]_ID.EID
0x92370 CAN2 32-bit
  [31] MB[23]_ID.IDE, [30] MB[23]_ID.RTR, [28:18] MB[23]_ID.SID, [17:0] MB[23]_ID.EID
0x92380 CAN2 32-bit
  [31] MB[24]_ID.IDE, [30] MB[24]_ID.RTR, [28:18] MB[24]_ID.SID, [17:0] MB[24]_ID.EID
0x92390 CAN2 32-bit
  [31] MB[25]_ID.IDE, [30] MB[25]_ID.RTR, [28:18] MB[25]_ID.SID, [17:0] MB[25]_ID.EID
0x923A0 CAN2 32-bit
  [31] MB[26]_ID.IDE, [30] MB[26]_ID.RTR, [28:18] MB[26]_ID.SID, [17:0] MB[26]_ID.EID
0x923B0 CAN2 32-bit
  [31] MB[27]_ID.IDE, [30] MB[27]_ID.RTR, [28:18] MB[27]_ID.SID, [17:0] MB[27]_ID.EID
0x923C0 CAN2 32-bit
  [31] MB[28]_ID.IDE, [30] MB[28]_ID.RTR, [28:18] MB[28]_ID.SID, [17:0] MB[28]_ID.EID
0x923D0 CAN2 32-bit
  [31] MB[29]_ID.IDE, [30] MB[29]_ID.RTR, [28:18] MB[29]_ID.SID, [17:0] MB[29]_ID.EID
0x923E0 CAN2 32-bit
  [31] MB[30]_ID.IDE, [30] MB[30]_ID.RTR, [28:18] MB[30]_ID.SID, [17:0] MB[30]_ID.EID
0x923F0 CAN2 32-bit
  [31] MB[31]_ID.IDE, [30] MB[31]_ID.RTR, [28:18] MB[31]_ID.SID, [17:0] MB[31]_ID.EID
0x92400 CAN2 32-bit
  [28:18] MKR[0].SID, [17:0] MKR[0].EID
0x92404 CAN2 32-bit
  [28:18] MKR[1].SID, [17:0] MKR[1].EID
0x92408 CAN2 32-bit
  [28:18] MKR[2].SID, [17:0] MKR[2].EID
0x9240C CAN2 32-bit
  [28:18] MKR[3].SID, [17:0] MKR[3].EID
0x92410 CAN2 32-bit
  [28:18] MKR[4].SID, [17:0] MKR[4].EID
0x92414 CAN2 32-bit
  [28:18] MKR[5].SID, [17:0] MKR[5].EID
0x92418 CAN2 32-bit
  [28:18] MKR[6].SID, [17:0] MKR[6].EID
0x9241C CAN2 32-bit
  [28:18] MKR[7].SID, [17:0] MKR[7].EID
0x92420 CAN2 32-bit
  [31] FIDCR0.IDE, [30] FIDCR0.RTR, [28:18] FIDCR0.SID, [17:0] FIDCR0.EID
0x92424 CAN2 32-bit
  [31] FIDCR1.IDE, [30] FIDCR1.RTR, [28:18] FIDCR1.SID, [17:0] FIDCR1.EID
0x92820 CAN2
  [7] MCTL[0]_TX.TRMREQ, [7] MCTL[0]_RX.TRMREQ, [6] MCTL[0]_TX.RECREQ, [6] MCTL[0]_RX.RECREQ, [4] MCTL[0]_TX.ONESHOT, [4] MCTL[0]_RX.ONESHOT, [2] MCTL[0]_TX.TRMABT, [2] MCTL[0]_RX.MSGLOST, [1] MCTL[0]_TX.TRMACTIVE, [1] MCTL[0]_RX.INVALDATA, [0] MCTL[0]_TX.SENTDATA, [0] MCTL[0]_RX.NEWDATA
0x92821 CAN2
  [7] MCTL[1]_TX.TRMREQ, [7] MCTL[1]_RX.TRMREQ, [6] MCTL[1]_TX.RECREQ, [6] MCTL[1]_RX.RECREQ, [4] MCTL[1]_TX.ONESHOT, [4] MCTL[1]_RX.ONESHOT, [2] MCTL[1]_TX.TRMABT, [2] MCTL[1]_RX.MSGLOST, [1] MCTL[1]_TX.TRMACTIVE, [1] MCTL[1]_RX.INVALDATA, [0] MCTL[1]_TX.SENTDATA, [0] MCTL[1]_RX.NEWDATA
0x92822 CAN2
  [7] MCTL[2]_TX.TRMREQ, [7] MCTL[2]_RX.TRMREQ, [6] MCTL[2]_TX.RECREQ, [6] MCTL[2]_RX.RECREQ, [4] MCTL[2]_TX.ONESHOT, [4] MCTL[2]_RX.ONESHOT, [2] MCTL[2]_TX.TRMABT, [2] MCTL[2]_RX.MSGLOST, [1] MCTL[2]_TX.TRMACTIVE, [1] MCTL[2]_RX.INVALDATA, [0] MCTL[2]_TX.SENTDATA, [0] MCTL[2]_RX.NEWDATA
0x92823 CAN2
  [7] MCTL[3]_TX.TRMREQ, [7] MCTL[3]_RX.TRMREQ, [6] MCTL[3]_TX.RECREQ, [6] MCTL[3]_RX.RECREQ, [4] MCTL[3]_TX.ONESHOT, [4] MCTL[3]_RX.ONESHOT, [2] MCTL[3]_TX.TRMABT, [2] MCTL[3]_RX.MSGLOST, [1] MCTL[3]_TX.TRMACTIVE, [1] MCTL[3]_RX.INVALDATA, [0] MCTL[3]_TX.SENTDATA, [0] MCTL[3]_RX.NEWDATA
0x92824 CAN2
  [7] MCTL[4]_TX.TRMREQ, [7] MCTL[4]_RX.TRMREQ, [6] MCTL[4]_TX.RECREQ, [6] MCTL[4]_RX.RECREQ, [4] MCTL[4]_TX.ONESHOT, [4] MCTL[4]_RX.ONESHOT, [2] MCTL[4]_TX.TRMABT, [2] MCTL[4]_RX.MSGLOST, [1] MCTL[4]_TX.TRMACTIVE, [1] MCTL[4]_RX.INVALDATA, [0] MCTL[4]_TX.SENTDATA, [0] MCTL[4]_RX.NEWDATA
0x92825 CAN2
  [7] MCTL[5]_TX.TRMREQ, [7] MCTL[5]_RX.TRMREQ, [6] MCTL[5]_TX.RECREQ, [6] MCTL[5]_RX.RECREQ, [4] MCTL[5]_TX.ONESHOT, [4] MCTL[5]_RX.ONESHOT, [2] MCTL[5]_TX.TRMABT, [2] MCTL[5]_RX.MSGLOST, [1] MCTL[5]_TX.TRMACTIVE, [1] MCTL[5]_RX.INVALDATA, [0] MCTL[5]_TX.SENTDATA, [0] MCTL[5]_RX.NEWDATA
0x92826 CAN2
  [7] MCTL[6]_TX.TRMREQ, [7] MCTL[6]_RX.TRMREQ, [6] MCTL[6]_TX.RECREQ, [6] MCTL[6]_RX.RECREQ, [4] MCTL[6]_TX.ONESHOT, [4] MCTL[6]_RX.ONESHOT, [2] MCTL[6]_TX.TRMABT, [2] MCTL[6]_RX.MSGLOST, [1] MCTL[6]_TX.TRMACTIVE, [1] MCTL[6]_RX.INVALDATA, [0] MCTL[6]_TX.SENTDATA, [0] MCTL[6]_RX.NEWDATA
0x92827 CAN2
  [7] MCTL[7]_TX.TRMREQ, [7] MCTL[7]_RX.TRMREQ, [6] MCTL[7]_TX.RECREQ, [6] MCTL[7]_RX.RECREQ, [4] MCTL[7]_TX.ONESHOT, [4] MCTL[7]_RX.ONESHOT, [2] MCTL[7]_TX.TRMABT, [2] MCTL[7]_RX.MSGLOST, [1] MCTL[7]_TX.TRMACTIVE, [1] MCTL[7]_RX.INVALDATA, [0] MCTL[7]_TX.SENTDATA, [0] MCTL[7]_RX.NEWDATA
0x92828 CAN2
  [7] MCTL[8]_TX.TRMREQ, [7] MCTL[8]_RX.TRMREQ, [6] MCTL[8]_TX.RECREQ, [6] MCTL[8]_RX.RECREQ, [4] MCTL[8]_TX.ONESHOT, [4] MCTL[8]_RX.ONESHOT, [2] MCTL[8]_TX.TRMABT, [2] MCTL[8]_RX.MSGLOST, [1] MCTL[8]_TX.TRMACTIVE, [1] MCTL[8]_RX.INVALDATA, [0] MCTL[8]_TX.SENTDATA, [0] MCTL[8]_RX.NEWDATA
0x92829 CAN2
  [7] MCTL[9]_TX.TRMREQ, [7] MCTL[9]_RX.TRMREQ, [6] MCTL[9]_TX.RECREQ, [6] MCTL[9]_RX.RECREQ, [4] MCTL[9]_TX.ONESHOT, [4] MCTL[9]_RX.ONESHOT, [2] MCTL[9]_TX.TRMABT, [2] MCTL[9]_RX.MSGLOST, [1] MCTL[9]_TX.TRMACTIVE, [1] MCTL[9]_RX.INVALDATA, [0] MCTL[9]_TX.SENTDATA, [0] MCTL[9]_RX.NEWDATA
0x9282A CAN2
  [7] MCTL[10]_TX.TRMREQ, [7] MCTL[10]_RX.TRMREQ, [6] MCTL[10]_TX.RECREQ, [6] MCTL[10]_RX.RECREQ, [4] MCTL[10]_TX.ONESHOT, [4] MCTL[10]_RX.ONESHOT, [2] MCTL[10]_TX.TRMABT, [2] MCTL[10]_RX.MSGLOST, [1] MCTL[10]_TX.TRMACTIVE, [1] MCTL[10]_RX.INVALDATA, [0] MCTL[10]_TX.SENTDATA, [0] MCTL[10]_RX.NEWDATA
0x9282B CAN2
  [7] MCTL[11]_TX.TRMREQ, [7] MCTL[11]_RX.TRMREQ, [6] MCTL[11]_TX.RECREQ, [6] MCTL[11]_RX.RECREQ, [4] MCTL[11]_TX.ONESHOT, [4] MCTL[11]_RX.ONESHOT, [2] MCTL[11]_TX.TRMABT, [2] MCTL[11]_RX.MSGLOST, [1] MCTL[11]_TX.TRMACTIVE, [1] MCTL[11]_RX.INVALDATA, [0] MCTL[11]_TX.SENTDATA, [0] MCTL[11]_RX.NEWDATA
0x9282C CAN2
  [7] MCTL[12]_TX.TRMREQ, [7] MCTL[12]_RX.TRMREQ, [6] MCTL[12]_TX.RECREQ, [6] MCTL[12]_RX.RECREQ, [4] MCTL[12]_TX.ONESHOT, [4] MCTL[12]_RX.ONESHOT, [2] MCTL[12]_TX.TRMABT, [2] MCTL[12]_RX.MSGLOST, [1] MCTL[12]_TX.TRMACTIVE, [1] MCTL[12]_RX.INVALDATA, [0] MCTL[12]_TX.SENTDATA, [0] MCTL[12]_RX.NEWDATA
0x9282D CAN2
  [7] MCTL[13]_TX.TRMREQ, [7] MCTL[13]_RX.TRMREQ, [6] MCTL[13]_TX.RECREQ, [6] MCTL[13]_RX.RECREQ, [4] MCTL[13]_TX.ONESHOT, [4] MCTL[13]_RX.ONESHOT, [2] MCTL[13]_TX.TRMABT, [2] MCTL[13]_RX.MSGLOST, [1] MCTL[13]_TX.TRMACTIVE, [1] MCTL[13]_RX.INVALDATA, [0] MCTL[13]_TX.SENTDATA, [0] MCTL[13]_RX.NEWDATA
0x9282E CAN2
  [7] MCTL[14]_TX.TRMREQ, [7] MCTL[14]_RX.TRMREQ, [6] MCTL[14]_TX.RECREQ, [6] MCTL[14]_RX.RECREQ, [4] MCTL[14]_TX.ONESHOT, [4] MCTL[14]_RX.ONESHOT, [2] MCTL[14]_TX.TRMABT, [2] MCTL[14]_RX.MSGLOST, [1] MCTL[14]_TX.TRMACTIVE, [1] MCTL[14]_RX.INVALDATA, [0] MCTL[14]_TX.SENTDATA, [0] MCTL[14]_RX.NEWDATA
0x9282F CAN2
  [7] MCTL[15]_TX.TRMREQ, [7] MCTL[15]_RX.TRMREQ, [6] MCTL[15]_TX.RECREQ, [6] MCTL[15]_RX.RECREQ, [4] MCTL[15]_TX.ONESHOT, [4] MCTL[15]_RX.ONESHOT, [2] MCTL[15]_TX.TRMABT, [2] MCTL[15]_RX.MSGLOST, [1] MCTL[15]_TX.TRMACTIVE, [1] MCTL[15]_RX.INVALDATA, [0] MCTL[15]_TX.SENTDATA, [0] MCTL[15]_RX.NEWDATA
0x92830 CAN2
  [7] MCTL[16]_TX.TRMREQ, [7] MCTL[16]_RX.TRMREQ, [6] MCTL[16]_TX.RECREQ, [6] MCTL[16]_RX.RECREQ, [4] MCTL[16]_TX.ONESHOT, [4] MCTL[16]_RX.ONESHOT, [2] MCTL[16]_TX.TRMABT, [2] MCTL[16]_RX.MSGLOST, [1] MCTL[16]_TX.TRMACTIVE, [1] MCTL[16]_RX.INVALDATA, [0] MCTL[16]_TX.SENTDATA, [0] MCTL[16]_RX.NEWDATA
0x92831 CAN2
  [7] MCTL[17]_TX.TRMREQ, [7] MCTL[17]_RX.TRMREQ, [6] MCTL[17]_TX.RECREQ, [6] MCTL[17]_RX.RECREQ, [4] MCTL[17]_TX.ONESHOT, [4] MCTL[17]_RX.ONESHOT, [2] MCTL[17]_TX.TRMABT, [2] MCTL[17]_RX.MSGLOST, [1] MCTL[17]_TX.TRMACTIVE, [1] MCTL[17]_RX.INVALDATA, [0] MCTL[17]_TX.SENTDATA, [0] MCTL[17]_RX.NEWDATA
0x92832 CAN2
  [7] MCTL[18]_TX.TRMREQ, [7] MCTL[18]_RX.TRMREQ, [6] MCTL[18]_TX.RECREQ, [6] MCTL[18]_RX.RECREQ, [4] MCTL[18]_TX.ONESHOT, [4] MCTL[18]_RX.ONESHOT, [2] MCTL[18]_TX.TRMABT, [2] MCTL[18]_RX.MSGLOST, [1] MCTL[18]_TX.TRMACTIVE, [1] MCTL[18]_RX.INVALDATA, [0] MCTL[18]_TX.SENTDATA, [0] MCTL[18]_RX.NEWDATA
0x92833 CAN2
  [7] MCTL[19]_TX.TRMREQ, [7] MCTL[19]_RX.TRMREQ, [6] MCTL[19]_TX.RECREQ, [6] MCTL[19]_RX.RECREQ, [4] MCTL[19]_TX.ONESHOT, [4] MCTL[19]_RX.ONESHOT, [2] MCTL[19]_TX.TRMABT, [2] MCTL[19]_RX.MSGLOST, [1] MCTL[19]_TX.TRMACTIVE, [1] MCTL[19]_RX.INVALDATA, [0] MCTL[19]_TX.SENTDATA, [0] MCTL[19]_RX.NEWDATA
0x92834 CAN2
  [7] MCTL[20]_TX.TRMREQ, [7] MCTL[20]_RX.TRMREQ, [6] MCTL[20]_TX.RECREQ, [6] MCTL[20]_RX.RECREQ, [4] MCTL[20]_TX.ONESHOT, [4] MCTL[20]_RX.ONESHOT, [2] MCTL[20]_TX.TRMABT, [2] MCTL[20]_RX.MSGLOST, [1] MCTL[20]_TX.TRMACTIVE, [1] MCTL[20]_RX.INVALDATA, [0] MCTL[20]_TX.SENTDATA, [0] MCTL[20]_RX.NEWDATA
0x92835 CAN2
  [7] MCTL[21]_TX.TRMREQ, [7] MCTL[21]_RX.TRMREQ, [6] MCTL[21]_TX.RECREQ, [6] MCTL[21]_RX.RECREQ, [4] MCTL[21]_TX.ONESHOT, [4] MCTL[21]_RX.ONESHOT, [2] MCTL[21]_TX.TRMABT, [2] MCTL[21]_RX.MSGLOST, [1] MCTL[21]_TX.TRMACTIVE, [1] MCTL[21]_RX.INVALDATA, [0] MCTL[21]_TX.SENTDATA, [0] MCTL[21]_RX.NEWDATA
0x92836 CAN2
  [7] MCTL[22]_TX.TRMREQ, [7] MCTL[22]_RX.TRMREQ, [6] MCTL[22]_TX.RECREQ, [6] MCTL[22]_RX.RECREQ, [4] MCTL[22]_TX.ONESHOT, [4] MCTL[22]_RX.ONESHOT, [2] MCTL[22]_TX.TRMABT, [2] MCTL[22]_RX.MSGLOST, [1] MCTL[22]_TX.TRMACTIVE, [1] MCTL[22]_RX.INVALDATA, [0] MCTL[22]_TX.SENTDATA, [0] MCTL[22]_RX.NEWDATA
0x92837 CAN2
  [7] MCTL[23]_TX.TRMREQ, [7] MCTL[23]_RX.TRMREQ, [6] MCTL[23]_TX.RECREQ, [6] MCTL[23]_RX.RECREQ, [4] MCTL[23]_TX.ONESHOT, [4] MCTL[23]_RX.ONESHOT, [2] MCTL[23]_TX.TRMABT, [2] MCTL[23]_RX.MSGLOST, [1] MCTL[23]_TX.TRMACTIVE, [1] MCTL[23]_RX.INVALDATA, [0] MCTL[23]_TX.SENTDATA, [0] MCTL[23]_RX.NEWDATA
0x92838 CAN2
  [7] MCTL[24]_TX.TRMREQ, [7] MCTL[24]_RX.TRMREQ, [6] MCTL[24]_TX.RECREQ, [6] MCTL[24]_RX.RECREQ, [4] MCTL[24]_TX.ONESHOT, [4] MCTL[24]_RX.ONESHOT, [2] MCTL[24]_TX.TRMABT, [2] MCTL[24]_RX.MSGLOST, [1] MCTL[24]_TX.TRMACTIVE, [1] MCTL[24]_RX.INVALDATA, [0] MCTL[24]_TX.SENTDATA, [0] MCTL[24]_RX.NEWDATA
0x92839 CAN2
  [7] MCTL[25]_TX.TRMREQ, [7] MCTL[25]_RX.TRMREQ, [6] MCTL[25]_TX.RECREQ, [6] MCTL[25]_RX.RECREQ, [4] MCTL[25]_TX.ONESHOT, [4] MCTL[25]_RX.ONESHOT, [2] MCTL[25]_TX.TRMABT, [2] MCTL[25]_RX.MSGLOST, [1] MCTL[25]_TX.TRMACTIVE, [1] MCTL[25]_RX.INVALDATA, [0] MCTL[25]_TX.SENTDATA, [0] MCTL[25]_RX.NEWDATA
0x9283A CAN2
  [7] MCTL[26]_TX.TRMREQ, [7] MCTL[26]_RX.TRMREQ, [6] MCTL[26]_TX.RECREQ, [6] MCTL[26]_RX.RECREQ, [4] MCTL[26]_TX.ONESHOT, [4] MCTL[26]_RX.ONESHOT, [2] MCTL[26]_TX.TRMABT, [2] MCTL[26]_RX.MSGLOST, [1] MCTL[26]_TX.TRMACTIVE, [1] MCTL[26]_RX.INVALDATA, [0] MCTL[26]_TX.SENTDATA, [0] MCTL[26]_RX.NEWDATA
0x9283B CAN2
  [7] MCTL[27]_TX.TRMREQ, [7] MCTL[27]_RX.TRMREQ, [6] MCTL[27]_TX.RECREQ, [6] MCTL[27]_RX.RECREQ, [4] MCTL[27]_TX.ONESHOT, [4] MCTL[27]_RX.ONESHOT, [2] MCTL[27]_TX.TRMABT, [2] MCTL[27]_RX.MSGLOST, [1] MCTL[27]_TX.TRMACTIVE, [1] MCTL[27]_RX.INVALDATA, [0] MCTL[27]_TX.SENTDATA, [0] MCTL[27]_RX.NEWDATA
0x9283C CAN2
  [7] MCTL[28]_TX.TRMREQ, [7] MCTL[28]_RX.TRMREQ, [6] MCTL[28]_TX.RECREQ, [6] MCTL[28]_RX.RECREQ, [4] MCTL[28]_TX.ONESHOT, [4] MCTL[28]_RX.ONESHOT, [2] MCTL[28]_TX.TRMABT, [2] MCTL[28]_RX.MSGLOST, [1] MCTL[28]_TX.TRMACTIVE, [1] MCTL[28]_RX.INVALDATA, [0] MCTL[28]_TX.SENTDATA, [0] MCTL[28]_RX.NEWDATA
0x9283D CAN2
  [7] MCTL[29]_TX.TRMREQ, [7] MCTL[29]_RX.TRMREQ, [6] MCTL[29]_TX.RECREQ, [6] MCTL[29]_RX.RECREQ, [4] MCTL[29]_TX.ONESHOT, [4] MCTL[29]_RX.ONESHOT, [2] MCTL[29]_TX.TRMABT, [2] MCTL[29]_RX.MSGLOST, [1] MCTL[29]_TX.TRMACTIVE, [1] MCTL[29]_RX.INVALDATA, [0] MCTL[29]_TX.SENTDATA, [0] MCTL[29]_RX.NEWDATA
0x9283E CAN2
  [7] MCTL[30]_TX.TRMREQ, [7] MCTL[30]_RX.TRMREQ, [6] MCTL[30]_TX.RECREQ, [6] MCTL[30]_RX.RECREQ, [4] MCTL[30]_TX.ONESHOT, [4] MCTL[30]_RX.ONESHOT, [2] MCTL[30]_TX.TRMABT, [2] MCTL[30]_RX.MSGLOST, [1] MCTL[30]_TX.TRMACTIVE, [1] MCTL[30]_RX.INVALDATA, [0] MCTL[30]_TX.SENTDATA, [0] MCTL[30]_RX.NEWDATA
0x9283F CAN2
  [7] MCTL[31]_TX.TRMREQ, [7] MCTL[31]_RX.TRMREQ, [6] MCTL[31]_TX.RECREQ, [6] MCTL[31]_RX.RECREQ, [4] MCTL[31]_TX.ONESHOT, [4] MCTL[31]_RX.ONESHOT, [2] MCTL[31]_TX.TRMABT, [2] MCTL[31]_RX.MSGLOST, [1] MCTL[31]_TX.TRMACTIVE, [1] MCTL[31]_RX.INVALDATA, [0] MCTL[31]_TX.SENTDATA, [0] MCTL[31]_RX.NEWDATA
0x94200 CMTW0 16-bit
  [0] CMWSTR.STR
0x94204 CMTW0 16-bit
  [15:13] CMWCR.CCLR, [9] CMWCR.CMS, [7] CMWCR.OC1IE, [6] CMWCR.OC0IE, [5] CMWCR.IC1IE, [4] CMWCR.IC0IE, [3] CMWCR.CMWIE, [1:0] CMWCR.CKS
0x94208 CMTW0 16-bit
  [15] CMWIOR.CMWE, [13] CMWIOR.OC1E, [12] CMWIOR.OC0E, [11:10] CMWIOR.OC1, [9:8] CMWIOR.OC0, [5] CMWIOR.IC1E, [4] CMWIOR.IC0E, [3:2] CMWIOR.IC1, [1:0] CMWIOR.IC0
0x94280 CMTW1 16-bit
  [0] CMWSTR.STR
0x94284 CMTW1 16-bit
  [15:13] CMWCR.CCLR, [9] CMWCR.CMS, [7] CMWCR.OC1IE, [6] CMWCR.OC0IE, [5] CMWCR.IC1IE, [4] CMWCR.IC0IE, [3] CMWCR.CMWIE, [1:0] CMWCR.CKS
0x94288 CMTW1 16-bit
  [15] CMWIOR.CMWE, [13] CMWIOR.OC1E, [12] CMWIOR.OC0E, [11:10] CMWIOR.OC1, [9:8] CMWIOR.OC0, [5] CMWIOR.IC1E, [4] CMWIOR.IC0E, [3:2] CMWIOR.IC1, [1:0] CMWIOR.IC0
0x9DFF8 SRC 16-bit
  [9] SRCIDCTRL.IED, [8] SRCIDCTRL.IEN, [1:0] SRCIDCTRL.IFTRG
0x9DFFA SRC 16-bit
  [10] SRCODCTRL.OCH, [9] SRCODCTRL.OED, [8] SRCODCTRL.OEN, [1:0] SRCODCTRL.OFTRG
0x9DFFC SRC 16-bit
  [15] SRCCTRL.FICRAE, [13] SRCCTRL.CEEN, [12] SRCCTRL.SRCEN, [11] SRCCTRL.UDEN, [10] SRCCTRL.OVEN, [9] SRCCTRL.FL, [8] SRCCTRL.CL, [7:4] SRCCTRL.IFS, [2:0] SRCCTRL.OFS
0x9DFFE SRC 16-bit
  [15:11] SRCSTAT.OFDN, [10:7] SRCSTAT.IFDN, [5] SRCSTAT.CEF, [4] SRCSTAT.FLF, [3] SRCSTAT.UDF, [2] SRCSTAT.OVF, [1] SRCSTAT.IINT, [0] SRCSTAT.OINT
0xA0000 USB0 16-bit
  [10] SYSCFG.SCKE, [6] SYSCFG.DCFM, [5] SYSCFG.DRPD, [4] SYSCFG.DPRPU, [0] SYSCFG.USBE
0xA0004 USB0 16-bit
  [15:14] SYSSTS0.OVCMON, [6] SYSSTS0.HTACT, [5] SYSSTS0.SOFEA, [2] SYSSTS0.IDMON, [1:0] SYSSTS0.LNST
0xA0008 USB0 16-bit
  [11] DVSTCTR0.HNPBTOA, [10] DVSTCTR0.EXICEN, [9] DVSTCTR0.VBUSEN, [8] DVSTCTR0.WKUP, [7] DVSTCTR0.RWUPE, [6] DVSTCTR0.USBRST, [5] DVSTCTR0.RESUME, [4] DVSTCTR0.UACT, [2:0] DVSTCTR0.RHST
0xA0020 USB0 16-bit
  [15] CFIFOSEL.RCNT, [14] CFIFOSEL.REW, [10] CFIFOSEL.MBW, [8] CFIFOSEL.BIGEND, [5] CFIFOSEL.ISEL, [3:0] CFIFOSEL.CURPIPE
0xA0022 USB0 16-bit
  [15] CFIFOCTR.BVAL, [14] CFIFOCTR.BCLR, [13] CFIFOCTR.FRDY, [8:0] CFIFOCTR.DTLN
# iorx71m register map
Registers are 8-bit, access not given, no defined reset value unless marked. A register's access mark holds for its fields unless they carry their own. Addresses are absolute; registers are grouped by the start of their names; [hi:lo] are bit positions; {n}, {i} and the like mark numbered series; 'fields as' and 'values as' point back to an identical list.

## SFR (part 4 of 4)
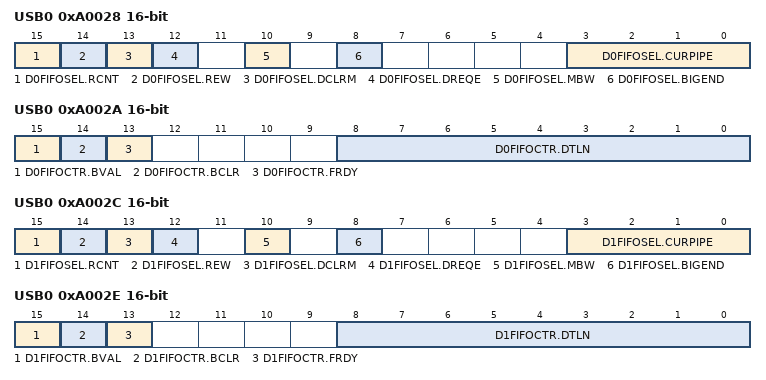
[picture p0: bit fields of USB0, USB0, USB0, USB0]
0xA0028 USB0 16-bit
  [15] D0FIFOSEL.RCNT, [14] D0FIFOSEL.REW, [13] D0FIFOSEL.DCLRM, [12] D0FIFOSEL.DREQE, [10] D0FIFOSEL.MBW, [8] D0FIFOSEL.BIGEND, [3:0] D0FIFOSEL.CURPIPE
0xA002A USB0 16-bit
  [15] D0FIFOCTR.BVAL, [14] D0FIFOCTR.BCLR, [13] D0FIFOCTR.FRDY, [8:0] D0FIFOCTR.DTLN
0xA002C USB0 16-bit
  [15] D1FIFOSEL.RCNT, [14] D1FIFOSEL.REW, [13] D1FIFOSEL.DCLRM, [12] D1FIFOSEL.DREQE, [10] D1FIFOSEL.MBW, [8] D1FIFOSEL.BIGEND, [3:0] D1FIFOSEL.CURPIPE
0xA002E USB0 16-bit
  [15] D1FIFOCTR.BVAL, [14] D1FIFOCTR.BCLR, [13] D1FIFOCTR.FRDY, [8:0] D1FIFOCTR.DTLN
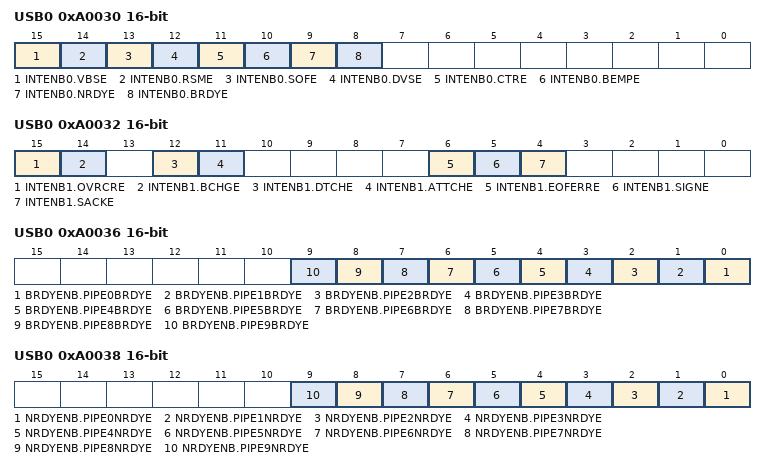
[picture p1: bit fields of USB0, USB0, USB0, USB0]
0xA0030 USB0 16-bit
  [15] INTENB0.VBSE, [14] INTENB0.RSME, [13] INTENB0.SOFE, [12] INTENB0.DVSE, [11] INTENB0.CTRE, [10] INTENB0.BEMPE, [9] INTENB0.NRDYE, [8] INTENB0.BRDYE
0xA0032 USB0 16-bit
  [15] INTENB1.OVRCRE, [14] INTENB1.BCHGE, [12] INTENB1.DTCHE, [11] INTENB1.ATTCHE, [6] INTENB1.EOFERRE, [5] INTENB1.SIGNE, [4] INTENB1.SACKE
0xA0036 USB0 16-bit
  [n] BRDYENB.PIPE{n}BRDYE (n=0..9)
0xA0038 USB0 16-bit
  [n] NRDYENB.PIPE{n}NRDYE (n=0..9)
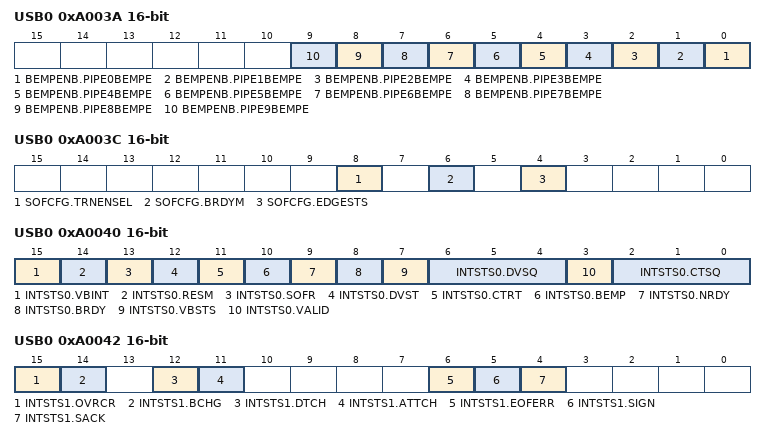
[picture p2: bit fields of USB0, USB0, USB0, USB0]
0xA003A USB0 16-bit
  [n] BEMPENB.PIPE{n}BEMPE (n=0..9)
0xA003C USB0 16-bit
  [8] SOFCFG.TRNENSEL, [6] SOFCFG.BRDYM, [4] SOFCFG.EDGESTS
0xA0040 USB0 16-bit
  [15] INTSTS0.VBINT, [14] INTSTS0.RESM, [13] INTSTS0.SOFR, [12] INTSTS0.DVST, [11] INTSTS0.CTRT, [10] INTSTS0.BEMP, [9] INTSTS0.NRDY, [8] INTSTS0.BRDY, [7] INTSTS0.VBSTS, [6:4] INTSTS0.DVSQ, [3] INTSTS0.VALID, [2:0] INTSTS0.CTSQ
0xA0042 USB0 16-bit
  [15] INTSTS1.OVRCR, [14] INTSTS1.BCHG, [12] INTSTS1.DTCH, [11] INTSTS1.ATTCH, [6] INTSTS1.EOFERR, [5] INTSTS1.SIGN, [4] INTSTS1.SACK
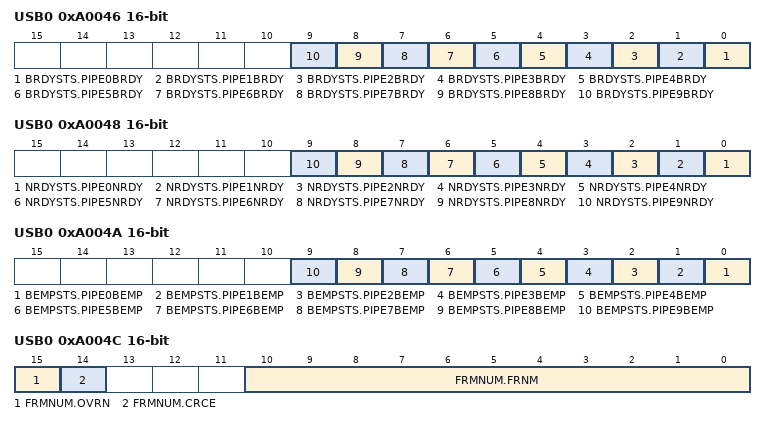
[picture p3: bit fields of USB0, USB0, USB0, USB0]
0xA0046 USB0 16-bit
  [n] BRDYSTS.PIPE{n}BRDY (n=0..9)
0xA0048 USB0 16-bit
  [n] NRDYSTS.PIPE{n}NRDY (n=0..9)
0xA004A USB0 16-bit
  [n] BEMPSTS.PIPE{n}BEMP (n=0..9)
0xA004C USB0 16-bit
  [15] FRMNUM.OVRN, [14] FRMNUM.CRCE, [10:0] FRMNUM.FRNM
0xA004E USB0 16-bit
  [15] DVCHGR.DVCHG
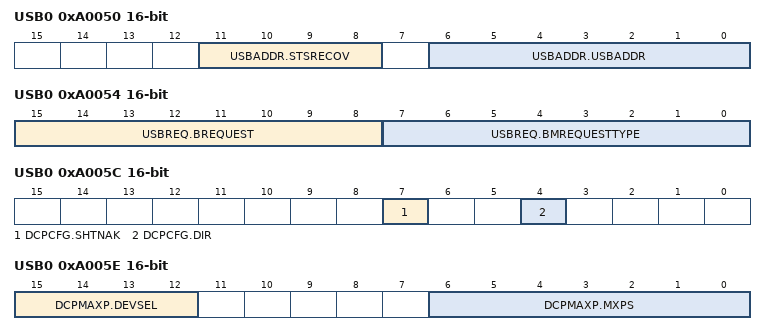
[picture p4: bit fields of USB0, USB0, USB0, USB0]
0xA0050 USB0 16-bit
  [11:8] USBADDR.STSRECOV, [6:0] USBADDR.USBADDR
0xA0054 USB0 16-bit
  [15:8] USBREQ.BREQUEST, [7:0] USBREQ.BMREQUESTTYPE
0xA005C USB0 16-bit
  [7] DCPCFG.SHTNAK, [4] DCPCFG.DIR
0xA005E USB0 16-bit
  [15:12] DCPMAXP.DEVSEL, [6:0] DCPMAXP.MXPS
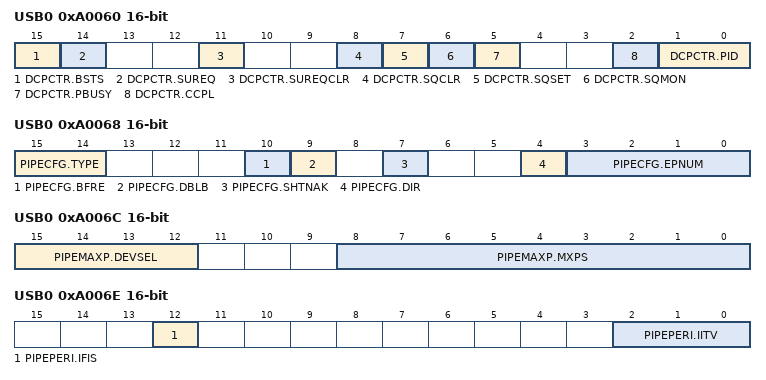
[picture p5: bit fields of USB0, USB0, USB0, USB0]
0xA0060 USB0 16-bit
  [15] DCPCTR.BSTS, [14] DCPCTR.SUREQ, [11] DCPCTR.SUREQCLR, [8] DCPCTR.SQCLR, [7] DCPCTR.SQSET, [6] DCPCTR.SQMON, [5] DCPCTR.PBUSY, [2] DCPCTR.CCPL, [1:0] DCPCTR.PID
0xA0064 USB0 16-bit
  [3:0] PIPESEL.PIPESEL
0xA0068 USB0 16-bit
  [15:14] PIPECFG.TYPE, [10] PIPECFG.BFRE, [9] PIPECFG.DBLB, [7] PIPECFG.SHTNAK, [4] PIPECFG.DIR, [3:0] PIPECFG.EPNUM
0xA006C USB0 16-bit
  [15:12] PIPEMAXP.DEVSEL, [8:0] PIPEMAXP.MXPS
0xA006E USB0 16-bit
  [12] PIPEPERI.IFIS, [2:0] PIPEPERI.IITV
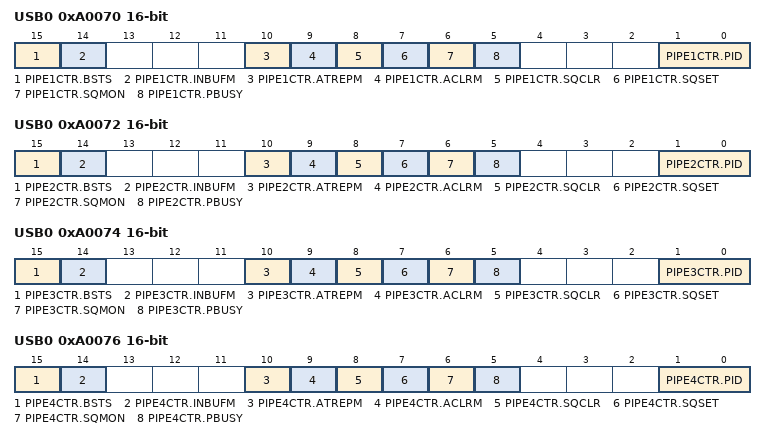
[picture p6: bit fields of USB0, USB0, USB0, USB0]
0xA0070 USB0 16-bit
  [15] PIPE1CTR.BSTS, [14] PIPE1CTR.INBUFM, [10] PIPE1CTR.ATREPM, [9] PIPE1CTR.ACLRM, [8] PIPE1CTR.SQCLR, [7] PIPE1CTR.SQSET, [6] PIPE1CTR.SQMON, [5] PIPE1CTR.PBUSY, [1:0] PIPE1CTR.PID
0xA0072 USB0 16-bit
  [15] PIPE2CTR.BSTS, [14] PIPE2CTR.INBUFM, [10] PIPE2CTR.ATREPM, [9] PIPE2CTR.ACLRM, [8] PIPE2CTR.SQCLR, [7] PIPE2CTR.SQSET, [6] PIPE2CTR.SQMON, [5] PIPE2CTR.PBUSY, [1:0] PIPE2CTR.PID
0xA0074 USB0 16-bit
  [15] PIPE3CTR.BSTS, [14] PIPE3CTR.INBUFM, [10] PIPE3CTR.ATREPM, [9] PIPE3CTR.ACLRM, [8] PIPE3CTR.SQCLR, [7] PIPE3CTR.SQSET, [6] PIPE3CTR.SQMON, [5] PIPE3CTR.PBUSY, [1:0] PIPE3CTR.PID
0xA0076 USB0 16-bit
  [15] PIPE4CTR.BSTS, [14] PIPE4CTR.INBUFM, [10] PIPE4CTR.ATREPM, [9] PIPE4CTR.ACLRM, [8] PIPE4CTR.SQCLR, [7] PIPE4CTR.SQSET, [6] PIPE4CTR.SQMON, [5] PIPE4CTR.PBUSY, [1:0] PIPE4CTR.PID
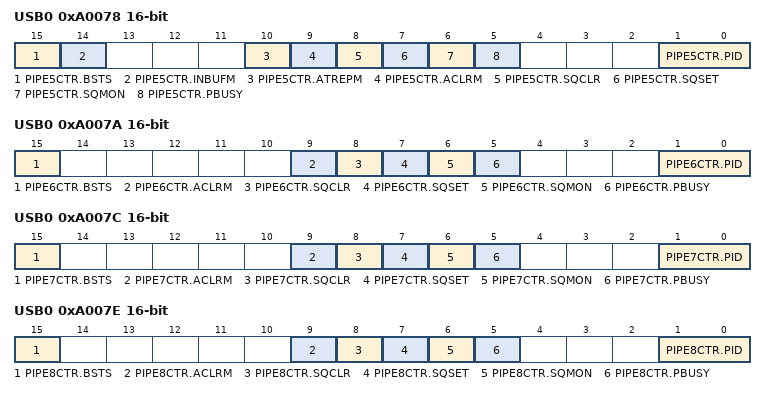
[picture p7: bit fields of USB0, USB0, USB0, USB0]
0xA0078 USB0 16-bit
  [15] PIPE5CTR.BSTS, [14] PIPE5CTR.INBUFM, [10] PIPE5CTR.ATREPM, [9] PIPE5CTR.ACLRM, [8] PIPE5CTR.SQCLR, [7] PIPE5CTR.SQSET, [6] PIPE5CTR.SQMON, [5] PIPE5CTR.PBUSY, [1:0] PIPE5CTR.PID
0xA007A USB0 16-bit
  [15] PIPE6CTR.BSTS, [9] PIPE6CTR.ACLRM, [8] PIPE6CTR.SQCLR, [7] PIPE6CTR.SQSET, [6] PIPE6CTR.SQMON, [5] PIPE6CTR.PBUSY, [1:0] PIPE6CTR.PID
0xA007C USB0 16-bit
  [15] PIPE7CTR.BSTS, [9] PIPE7CTR.ACLRM, [8] PIPE7CTR.SQCLR, [7] PIPE7CTR.SQSET, [6] PIPE7CTR.SQMON, [5] PIPE7CTR.PBUSY, [1:0] PIPE7CTR.PID
0xA007E USB0 16-bit
  [15] PIPE8CTR.BSTS, [9] PIPE8CTR.ACLRM, [8] PIPE8CTR.SQCLR, [7] PIPE8CTR.SQSET, [6] PIPE8CTR.SQMON, [5] PIPE8CTR.PBUSY, [1:0] PIPE8CTR.PID
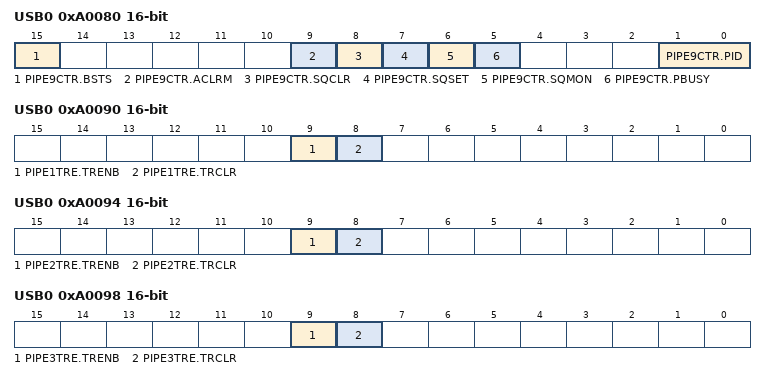
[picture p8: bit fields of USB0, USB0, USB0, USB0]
0xA0080 USB0 16-bit
  [15] PIPE9CTR.BSTS, [9] PIPE9CTR.ACLRM, [8] PIPE9CTR.SQCLR, [7] PIPE9CTR.SQSET, [6] PIPE9CTR.SQMON, [5] PIPE9CTR.PBUSY, [1:0] PIPE9CTR.PID
0xA0090 USB0 16-bit
  [9] PIPE1TRE.TRENB, [8] PIPE1TRE.TRCLR
0xA0094 USB0 16-bit
  [9] PIPE2TRE.TRENB, [8] PIPE2TRE.TRCLR
0xA0098 USB0 16-bit
  [9] PIPE3TRE.TRENB, [8] PIPE3TRE.TRCLR
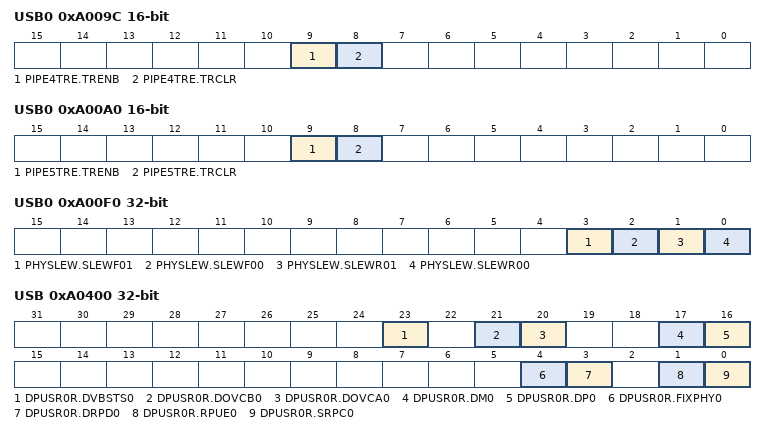
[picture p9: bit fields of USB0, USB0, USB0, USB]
0xA009C USB0 16-bit
  [9] PIPE4TRE.TRENB, [8] PIPE4TRE.TRCLR
0xA00A0 USB0 16-bit
  [9] PIPE5TRE.TRENB, [8] PIPE5TRE.TRCLR
0xA00D0 USB0 16-bit
  [7:6] DEVADD0.USBSPD
0xA00D2 USB0 16-bit
  [7:6] DEVADD1.USBSPD
0xA00D4 USB0 16-bit
  [7:6] DEVADD2.USBSPD
0xA00D6 USB0 16-bit
  [7:6] DEVADD3.USBSPD
0xA00D8 USB0 16-bit
  [7:6] DEVADD4.USBSPD
0xA00DA USB0 16-bit
  [7:6] DEVADD5.USBSPD
0xA00F0 USB0 32-bit
  [3] PHYSLEW.SLEWF01, [2] PHYSLEW.SLEWF00, [1] PHYSLEW.SLEWR01, [0] PHYSLEW.SLEWR00
0xA0400 USB 32-bit
  [23] DPUSR0R.DVBSTS0, [21] DPUSR0R.DOVCB0, [20] DPUSR0R.DOVCA0, [17] DPUSR0R.DM0, [16] DPUSR0R.DP0, [4] DPUSR0R.FIXPHY0, [3] DPUSR0R.DRPD0, [1] DPUSR0R.RPUE0, [0] DPUSR0R.SRPC0
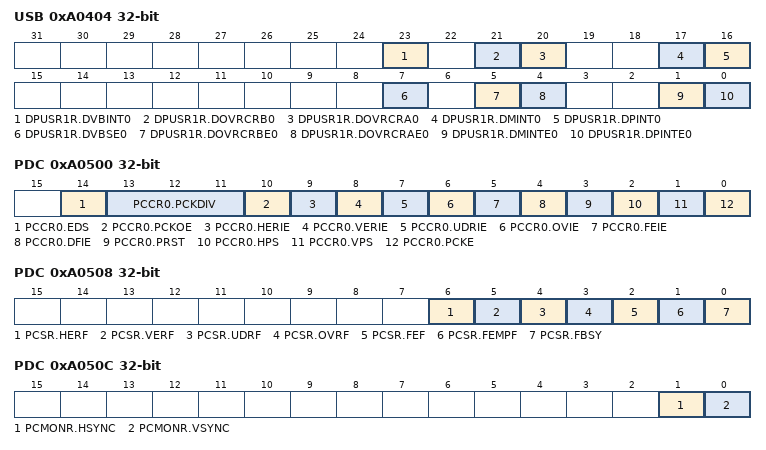
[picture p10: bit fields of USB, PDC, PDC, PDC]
0xA0404 USB 32-bit
  [23] DPUSR1R.DVBINT0, [21] DPUSR1R.DOVRCRB0, [20] DPUSR1R.DOVRCRA0, [17] DPUSR1R.DMINT0, [16] DPUSR1R.DPINT0, [7] DPUSR1R.DVBSE0, [5] DPUSR1R.DOVRCRBE0, [4] DPUSR1R.DOVRCRAE0, [1] DPUSR1R.DMINTE0, [0] DPUSR1R.DPINTE0
0xA0500 PDC 32-bit
  [14] PCCR0.EDS, [13:11] PCCR0.PCKDIV, [10] PCCR0.PCKOE, [9] PCCR0.HERIE, [8] PCCR0.VERIE, [7] PCCR0.UDRIE, [6] PCCR0.OVIE, [5] PCCR0.FEIE, [4] PCCR0.DFIE, [3] PCCR0.PRST, [2] PCCR0.HPS, [1] PCCR0.VPS, [0] PCCR0.PCKE
0xA0504 PDC 32-bit
  [0] PCCR1.PCE
0xA0508 PDC 32-bit
  [6] PCSR.HERF, [5] PCSR.VERF, [4] PCSR.UDRF, [3] PCSR.OVRF, [2] PCSR.FEF, [1] PCSR.FEMPF, [0] PCSR.FBSY
0xA050C PDC 32-bit
  [1] PCMONR.HSYNC, [0] PCMONR.VSYNC
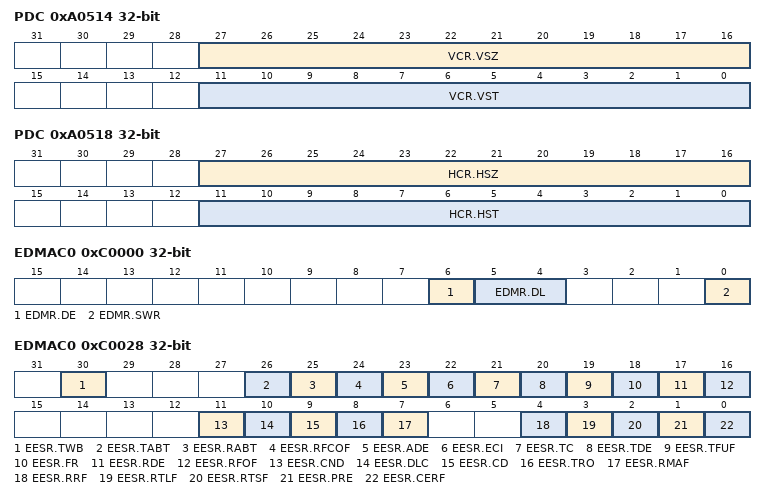
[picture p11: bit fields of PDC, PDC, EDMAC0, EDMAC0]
0xA0514 PDC 32-bit
  [27:16] VCR.VSZ, [11:0] VCR.VST
0xA0518 PDC 32-bit
  [27:16] HCR.HSZ, [11:0] HCR.HST
0xC0000 EDMAC0 32-bit
  [6] EDMR.DE, [5:4] EDMR.DL, [0] EDMR.SWR
0xC0008 EDMAC0 32-bit
  [0] EDTRR.TR
0xC0010 EDMAC0 32-bit
  [0] EDRRR.RR
0xC0028 EDMAC0 32-bit
  [30] EESR.TWB, [26] EESR.TABT, [25] EESR.RABT, [24] EESR.RFCOF, [23] EESR.ADE, [22] EESR.ECI, [21] EESR.TC, [20] EESR.TDE, [19] EESR.TFUF, [18] EESR.FR, [17] EESR.RDE, [16] EESR.RFOF, [11] EESR.CND, [10] EESR.DLC, [9] EESR.CD, [8] EESR.TRO, [7] EESR.RMAF, [4] EESR.RRF, [3] EESR.RTLF, [2] EESR.RTSF, [1] EESR.PRE, [0] EESR.CERF
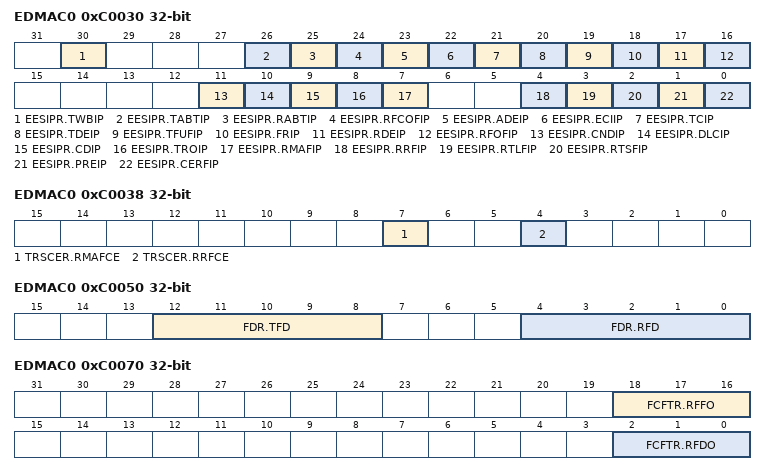
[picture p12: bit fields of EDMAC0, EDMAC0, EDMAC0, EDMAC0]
0xC0030 EDMAC0 32-bit
  [30] EESIPR.TWBIP, [26] EESIPR.TABTIP, [25] EESIPR.RABTIP, [24] EESIPR.RFCOFIP, [23] EESIPR.ADEIP, [22] EESIPR.ECIIP, [21] EESIPR.TCIP, [20] EESIPR.TDEIP, [19] EESIPR.TFUFIP, [18] EESIPR.FRIP, [17] EESIPR.RDEIP, [16] EESIPR.RFOFIP, [11] EESIPR.CNDIP, [10] EESIPR.DLCIP, [9] EESIPR.CDIP, [8] EESIPR.TROIP, [7] EESIPR.RMAFIP, [4] EESIPR.RRFIP, [3] EESIPR.RTLFIP, [2] EESIPR.RTSFIP, [1] EESIPR.PREIP, [0] EESIPR.CERFIP
0xC0038 EDMAC0 32-bit
  [7] TRSCER.RMAFCE, [4] TRSCER.RRFCE
0xC0040 EDMAC0 32-bit
  [15:0] RMFCR.MFC
0xC0048 EDMAC0 32-bit
  [10:0] TFTR.TFT
0xC0050 EDMAC0 32-bit
  [12:8] FDR.TFD, [4:0] FDR.RFD
0xC0058 EDMAC0 32-bit
  [0] RMCR.RNR
0xC0064 EDMAC0 32-bit
  [15:0] TFUCR.UNDER
0xC0068 EDMAC0 32-bit
  [15:0] RFOCR.OVER
0xC006C EDMAC0 32-bit
  [0] IOSR.ELB
0xC0070 EDMAC0 32-bit
  [18:16] FCFTR.RFFO, [2:0] FCFTR.RFDO
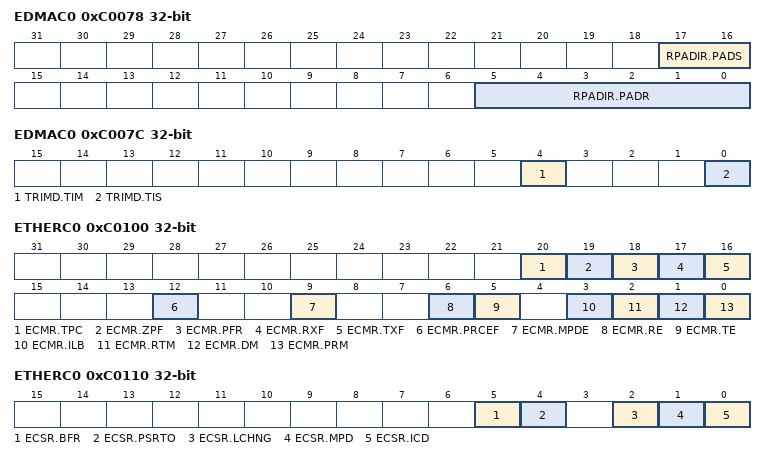
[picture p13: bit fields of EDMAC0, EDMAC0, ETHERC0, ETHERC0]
0xC0078 EDMAC0 32-bit
  [17:16] RPADIR.PADS, [5:0] RPADIR.PADR
0xC007C EDMAC0 32-bit
  [4] TRIMD.TIM, [0] TRIMD.TIS
0xC0100 ETHERC0 32-bit
  [20] ECMR.TPC, [19] ECMR.ZPF, [18] ECMR.PFR, [17] ECMR.RXF, [16] ECMR.TXF, [12] ECMR.PRCEF, [9] ECMR.MPDE, [6] ECMR.RE, [5] ECMR.TE, [3] ECMR.ILB, [2] ECMR.RTM, [1] ECMR.DM, [0] ECMR.PRM
0xC0108 ETHERC0 32-bit
  [11:0] RFLR.RFL
0xC0110 ETHERC0 32-bit
  [5] ECSR.BFR, [4] ECSR.PSRTO, [2] ECSR.LCHNG, [1] ECSR.MPD, [0] ECSR.ICD
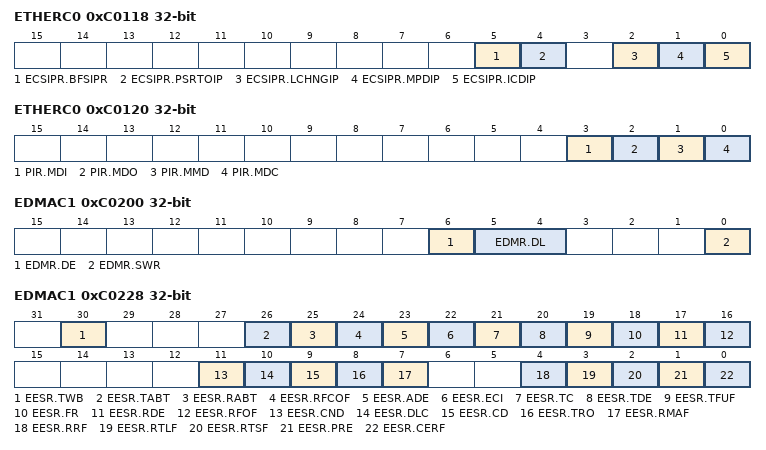
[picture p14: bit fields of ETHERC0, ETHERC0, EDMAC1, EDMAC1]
0xC0118 ETHERC0 32-bit
  [5] ECSIPR.BFSIPR, [4] ECSIPR.PSRTOIP, [2] ECSIPR.LCHNGIP, [1] ECSIPR.MPDIP, [0] ECSIPR.ICDIP
0xC0120 ETHERC0 32-bit
  [3] PIR.MDI, [2] PIR.MDO, [1] PIR.MMD, [0] PIR.MDC
0xC0128 ETHERC0 32-bit
  [0] PSR.LMON
0xC0140 ETHERC0 32-bit
  [19:0] RDMLR.RMD
0xC0150 ETHERC0 32-bit
  [4:0] IPGR.IPG
0xC0160 ETHERC0 32-bit
  [7:0] RFCF.RPAUSE
0xC0164 ETHERC0 32-bit
  [15:0] TPAUSER.TPAUSE
0xC0168 ETHERC0 32-bit
  [7:0] TPAUSECR.TXP
0xC016C ETHERC0 32-bit
  [15:0] BCFRR.BCF
0xC01C8 ETHERC0 32-bit
  [15:0] MALR.MA
0xC0200 EDMAC1 32-bit
  [6] EDMR.DE, [5:4] EDMR.DL, [0] EDMR.SWR
0xC0208 EDMAC1 32-bit
  [0] EDTRR.TR
0xC0210 EDMAC1 32-bit
  [0] EDRRR.RR
0xC0228 EDMAC1 32-bit
  [30] EESR.TWB, [26] EESR.TABT, [25] EESR.RABT, [24] EESR.RFCOF, [23] EESR.ADE, [22] EESR.ECI, [21] EESR.TC, [20] EESR.TDE, [19] EESR.TFUF, [18] EESR.FR, [17] EESR.RDE, [16] EESR.RFOF, [11] EESR.CND, [10] EESR.DLC, [9] EESR.CD, [8] EESR.TRO, [7] EESR.RMAF, [4] EESR.RRF, [3] EESR.RTLF, [2] EESR.RTSF, [1] EESR.PRE, [0] EESR.CERF
0xC0230 EDMAC1 32-bit
  [30] EESIPR.TWBIP, [26] EESIPR.TABTIP, [25] EESIPR.RABTIP, [24] EESIPR.RFCOFIP, [23] EESIPR.ADEIP, [22] EESIPR.ECIIP, [21] EESIPR.TCIP, [20] EESIPR.TDEIP, [19] EESIPR.TFUFIP, [18] EESIPR.FRIP, [17] EESIPR.RDEIP, [16] EESIPR.RFOFIP, [11] EESIPR.CNDIP, [10] EESIPR.DLCIP, [9] EESIPR.CDIP, [8] EESIPR.TROIP, [7] EESIPR.RMAFIP, [4] EESIPR.RRFIP, [3] EESIPR.RTLFIP, [2] EESIPR.RTSFIP, [1] EESIPR.PREIP, [0] EESIPR.CERFIP
0xC0238 EDMAC1 32-bit
  [7] TRSCER.RMAFCE, [4] TRSCER.RRFCE
0xC0240 EDMAC1 32-bit
  [15:0] RMFCR.MFC
0xC0248 EDMAC1 32-bit
  [10:0] TFTR.TFT
0xC0250 EDMAC1 32-bit
  [12:8] FDR.TFD, [4:0] FDR.RFD
0xC0258 EDMAC1 32-bit
  [0] RMCR.RNR
0xC0264 EDMAC1 32-bit
  [15:0] TFUCR.UNDER
0xC0268 EDMAC1 32-bit
  [15:0] RFOCR.OVER
0xC026C EDMAC1 32-bit
  [0] IOSR.ELB
0xC0270 EDMAC1 32-bit
  [18:16] FCFTR.RFFO, [2:0] FCFTR.RFDO
0xC0278 EDMAC1 32-bit
  [17:16] RPADIR.PADS, [5:0] RPADIR.PADR
0xC027C EDMAC1 32-bit
  [4] TRIMD.TIM, [0] TRIMD.TIS
0xC0300 ETHERC1 32-bit
  fields as ETHERC0
0xC0308 ETHERC1 32-bit
  [11:0] RFLR.RFL
0xC0310 ETHERC1 32-bit
  [5] ECSR.BFR, [4] ECSR.PSRTO, [2] ECSR.LCHNG, [1] ECSR.MPD, [0] ECSR.ICD
0xC0318 ETHERC1 32-bit
  [5] ECSIPR.BFSIPR, [4] ECSIPR.PSRTOIP, [2] ECSIPR.LCHNGIP, [1] ECSIPR.MPDIP, [0] ECSIPR.ICDIP
0xC0320 ETHERC1 32-bit
  [3] PIR.MDI, [2] PIR.MDO, [1] PIR.MMD, [0] PIR.MDC
0xC0328 ETHERC1 32-bit
  [0] PSR.LMON
0xC0340 ETHERC1 32-bit
  [19:0] RDMLR.RMD
0xC0350 ETHERC1 32-bit
  [4:0] IPGR.IPG
0xC0360 ETHERC1 32-bit
  [7:0] RFCF.RPAUSE
0xC0364 ETHERC1 32-bit
  [15:0] TPAUSER.TPAUSE
0xC0368 ETHERC1 32-bit
  [7:0] TPAUSECR.TXP
0xC036C ETHERC1 32-bit
  [15:0] BCFRR.BCF
0xC03C8 ETHERC1 32-bit
  [15:0] MALR.MA
0xC0400 PTPEDMAC 32-bit
  [6] EDMR.DE, [5:4] EDMR.DL, [0] EDMR.SWR
0xC0408 PTPEDMAC 32-bit
  [0] EDTRR.TR
0xC0410 PTPEDMAC 32-bit
  [0] EDRRR.RR
0xC0428 PTPEDMAC 32-bit
  [30] EESR.TWB, [26] EESR.TABT, [24] EESR.RFCOF, [23] EESR.ADE, [21] EESR.TC, [20] EESR.TDE, [19] EESR.TFUF, [18] EESR.FR, [17] EESR.RDE, [16] EESR.RFOF, [8] EESR.MACE, [7] EESR.RPORT, [4] EESR.PVER, [3:0] EESR.TYPE
0xC0430 PTPEDMAC 32-bit
  [30] EESIPR.TWBIP, [26] EESIPR.TABTIP, [24] EESIPR.RFCOFIP, [23] EESIPR.ADEIP, [21] EESIPR.TCIP, [20] EESIPR.TDEIP, [19] EESIPR.TFUFIP, [18] EESIPR.FRIP, [17] EESIPR.RDEIP, [16] EESIPR.RFOFIP, [8] EESIPR.MACEIP, [7] EESIPR.RPORTIP, [4] EESIPR.PVERIP
0xC0438 PTPEDMAC 32-bit
  [7] TRSCER.RPORTCE, [4] TRSCER.PVERCE, [3:0] TRSCER.TYPECE
0xC0440 PTPEDMAC 32-bit
  [15:0] RMFCR.MFC
0xC0448 PTPEDMAC 32-bit
  [10:0] TFTR.TFT
0xC0450 PTPEDMAC 32-bit
  [12:8] FDR.TFD, [4:0] FDR.RFD
0xC0458 PTPEDMAC 32-bit
  [0] RMCR.RNR
0xC0464 PTPEDMAC 32-bit
  [15:0] TFUCR.UNDER
0xC0468 PTPEDMAC 32-bit
  [15:0] RFOCR.OVER
0xC046C PTPEDMAC 32-bit
  [0] IOSR.ELB
0xC0470 PTPEDMAC 32-bit
  [18:16] FCFTR.RFFO, [2:0] FCFTR.RFDO
0xC0478 PTPEDMAC 32-bit
  [17:16] RPADIR.PADS, [5:0] RPADIR.PADR
0xC047C PTPEDMAC 32-bit
  [4] TRIMD.TIM, [0] TRIMD.TIS
0xC0500 EPTPC 32-bit
  [0] PTRSTR.RESET
0xC0504 EPTPC 32-bit
  [10:8] STCSELR.SCLKSEL, [2:0] STCSELR.SCLKDIV
0xC1200 MTU3
  [7:5] TCR.CCLR, [4:3] TCR.CKEG, [2:0] TCR.TPSC
0xC1201 MTU4
  [7:5] TCR.CCLR, [4:3] TCR.CKEG, [2:0] TCR.TPSC
0xC1202 MTU3
  [5] TMDR1.BFB, [4] TMDR1.BFA, [3:0] TMDR1.MD
0xC1203 MTU4
  [5] TMDR1.BFB, [4] TMDR1.BFA, [3:0] TMDR1.MD
0xC1204 MTU3
  [7:4] TIORH.IOB, [3:0] TIORH.IOA
0xC1205 MTU3
  [7:4] TIORL.IOD, [3:0] TIORL.IOC
0xC1206 MTU4
  [7:4] TIORH.IOB, [3:0] TIORH.IOA
0xC1207 MTU4
  [7:4] TIORL.IOD, [3:0] TIORL.IOC
0xC1208 MTU3
  [7] TIER.TTGE, [4] TIER.TCIEV, [3] TIER.TGIED, [2] TIER.TGIEC, [1] TIER.TGIEB, [0] TIER.TGIEA
0xC1209 MTU4
  [7] TIER.TTGE, [6] TIER.TTGE2, [4] TIER.TCIEV, [3] TIER.TGIED, [2] TIER.TGIEC, [1] TIER.TGIEB, [0] TIER.TGIEA
0xC120A MTU
  [5] TOERA.OE4D, [4] TOERA.OE4C, [3] TOERA.OE3D, [2] TOERA.OE4B, [1] TOERA.OE4A, [0] TOERA.OE3B
0xC120D MTU
  [6] TGCRA.BDC, [5] TGCRA.N, [4] TGCRA.P, [3] TGCRA.FB, [2] TGCRA.WF, [1] TGCRA.VF, [0] TGCRA.UF
0xC120E MTU
  [6] TOCR1A.PSYE, [3] TOCR1A.TOCL, [2] TOCR1A.TOCS, [1] TOCR1A.OLSN, [0] TOCR1A.OLSP
0xC120F MTU
  [7:6] TOCR2A.BF, [5] TOCR2A.OLS3N, [4] TOCR2A.OLS3P, [3] TOCR2A.OLS2N, [2] TOCR2A.OLS2P, [1] TOCR2A.OLS1N, [0] TOCR2A.OLS1P
0xC122C MTU3
  [7] TSR.TCFD
0xC122D MTU4
  [7] TSR.TCFD
0xC1230 MTU
  [7] TITCR1A.T3AEN, [6:4] TITCR1A.T3ACOR, [3] TITCR1A.T4VEN, [2:0] TITCR1A.T4VCOR
0xC1231 MTU
  [6:4] TITCNT1A.T3ACNT, [2:0] TITCNT1A.T4VCNT
0xC1232 MTU
  [1:0] TBTERA.BTE
0xC1234 MTU
  [0] TDERA.TDER
0xC1236 MTU
  [5] TOLBRA.OLS3N, [4] TOLBRA.OLS3P, [3] TOLBRA.OLS2N, [2] TOLBRA.OLS2P, [1] TOLBRA.OLS1N, [0] TOLBRA.OLS1P
0xC1238 MTU3
  [1] TBTM.TTSB, [0] TBTM.TTSA
0xC1239 MTU4
  [1] TBTM.TTSB, [0] TBTM.TTSA
0xC123A MTU
  [0] TITMRA.TITM
0xC123B MTU
  [2:0] TITCR2A.TRG4COR
0xC123C MTU
  [2:0] TITCNT2A.TRG4CNT
0xC1240 MTU4 16-bit
  [15:14] TADCR.BF, [7] TADCR.UT4AE, [6] TADCR.DT4AE, [5] TADCR.UT4BE, [4] TADCR.DT4BE, [3] TADCR.ITA3AE, [2] TADCR.ITA4VE, [1] TADCR.ITB3AE, [0] TADCR.ITB4VE
0xC124C MTU3
  [2:0] TCR2.TPSC2
0xC124D MTU4
  [2:0] TCR2.TPSC2
0xC1260 MTU
  [7] TWCRA.CCE, [1] TWCRA.SCC, [0] TWCRA.WRE
0xC1270 MTU
  [0] TMDR2A.DRS
0xC1280 MTU
  [7] TSTRA.CST4, [6] TSTRA.CST3, [3] TSTRA.CST8, [2] TSTRA.CST2, [1] TSTRA.CST1, [0] TSTRA.CST0
0xC1281 MTU
  [7] TSYRA.SYNC4, [6] TSYRA.SYNC3, [2] TSYRA.SYNC2, [1] TSYRA.SYNC1, [0] TSYRA.SYNC0
0xC1282 MTU
  [7-n] TCSYSTR.SCH{n} (n=0..4), [1] TCSYSTR.SCH6, [0] TCSYSTR.SCH7
0xC1284 MTU
  [0] TRWERA.RWE
{0xC1290+i} MTU{i} (i=0..4)
  [5:4] NFCR{i}.NFCS, [3] NFCR{i}.NFDEN, [2] NFCR{i}.NFCEN, [1] NFCR{i}.NFBEN, [0] NFCR{i}.NFAEN
0xC1298 MTU8
  [5:4] NFCR8.NFCS, [3] NFCR8.NFDEN, [2] NFCR8.NFCEN, [1] NFCR8.NFBEN, [0] NFCR8.NFAEN
0xC1299 MTU0
  [5:4] NFCRC.NFCS, [3] NFCRC.NFDEN, [2] NFCRC.NFCEN, [1] NFCRC.NFBEN, [0] NFCRC.NFAEN
0xC1300 MTU0
  [7:5] TCR.CCLR, [4:3] TCR.CKEG, [2:0] TCR.TPSC
0xC1301 MTU0
  [6] TMDR1.BFE, [5] TMDR1.BFB, [4] TMDR1.BFA, [3:0] TMDR1.MD
0xC1302 MTU0
  [7:4] TIORH.IOB, [3:0] TIORH.IOA
0xC1303 MTU0
  [7:4] TIORL.IOD, [3:0] TIORL.IOC
0xC1304 MTU0
  [7] TIER.TTGE, [4] TIER.TCIEV, [3] TIER.TGIED, [2] TIER.TGIEC, [1] TIER.TGIEB, [0] TIER.TGIEA
0xC1324 MTU0
  [7] TIER2.TTGE2, [1] TIER2.TGIEF, [0] TIER2.TGIEE
0xC1326 MTU0
  [2] TBTM.TTSE, [1] TBTM.TTSB, [0] TBTM.TTSA
0xC1328 MTU0
  [2:0] TCR2.TPSC2
0xC1380 MTU1
  [6:5] TCR.CCLR, [4:3] TCR.CKEG, [2:0] TCR.TPSC
0xC1381 MTU1
  [3:0] TMDR1.MD
0xC1382 MTU1
  [7:4] TIOR.IOB, [3:0] TIOR.IOA
0xC1384 MTU1
  [7] TIER.TTGE, [5] TIER.TCIEU, [4] TIER.TCIEV, [1] TIER.TGIEB, [0] TIER.TGIEA
0xC1385 MTU1
  [7] TSR.TCFD
0xC1390 MTU1
  [3] TICCR.I2BE, [2] TICCR.I2AE, [1] TICCR.I1BE, [0] TICCR.I1AE
0xC1391 MTU1
  [1] TMDR3.PHCKSEL, [0] TMDR3.LWA
0xC1394 MTU1
  [4:3] TCR2.PCB, [2:0] TCR2.TPSC2
0xC1400 MTU2
  [6:5] TCR.CCLR, [4:3] TCR.CKEG, [2:0] TCR.TPSC
0xC1401 MTU2
  [3:0] TMDR1.MD
0xC1402 MTU2
  [7:4] TIOR.IOB, [3:0] TIOR.IOA
0xC1404 MTU2
  [7] TIER.TTGE, [5] TIER.TCIEU, [4] TIER.TCIEV, [1] TIER.TGIEB, [0] TIER.TGIEA
0xC1405 MTU2
  [7] TSR.TCFD
0xC140C MTU2
  [4:3] TCR2.PCB, [2:0] TCR2.TPSC2
0xC1600 MTU8
  [7:5] TCR.CCLR, [4:3] TCR.CKEG, [2:0] TCR.TPSC
0xC1601 MTU8
  [5] TMDR1.BFB, [4] TMDR1.BFA, [3:0] TMDR1.MD
0xC1602 MTU8
  [7:4] TIORH.IOB, [3:0] TIORH.IOA
0xC1603 MTU8
  [7:4] TIORL.IOD, [3:0] TIORL.IOC
0xC1604 MTU8
  [4] TIER.TCIEV, [3] TIER.TGIED, [2] TIER.TGIEC, [1] TIER.TGIEB, [0] TIER.TGIEA
0xC1606 MTU8
  [2:0] TCR2.TPSC2
0xC1A00 MTU6
  [7:5] TCR.CCLR, [4:3] TCR.CKEG, [2:0] TCR.TPSC
0xC1A01 MTU7
  [7:5] TCR.CCLR, [4:3] TCR.CKEG, [2:0] TCR.TPSC
0xC1A02 MTU6
  [5] TMDR1.BFB, [4] TMDR1.BFA, [3:0] TMDR1.MD
0xC1A03 MTU7
  [5] TMDR1.BFB, [4] TMDR1.BFA, [3:0] TMDR1.MD
0xC1A04 MTU6
  [7:4] TIORH.IOB, [3:0] TIORH.IOA
0xC1A05 MTU6
  [7:4] TIORL.IOD, [3:0] TIORL.IOC
0xC1A06 MTU7
  [7:4] TIORH.IOB, [3:0] TIORH.IOA
0xC1A07 MTU7
  [7:4] TIORL.IOD, [3:0] TIORL.IOC
0xC1A08 MTU6
  [7] TIER.TTGE, [4] TIER.TCIEV, [3] TIER.TGIED, [2] TIER.TGIEC, [1] TIER.TGIEB, [0] TIER.TGIEA
0xC1A09 MTU7
  [7] TIER.TTGE, [6] TIER.TTGE2, [4] TIER.TCIEV, [3] TIER.TGIED, [2] TIER.TGIEC, [1] TIER.TGIEB, [0] TIER.TGIEA
0xC1A0A MTU
  [5] TOERB.OE7D, [4] TOERB.OE7C, [3] TOERB.OE6D, [2] TOERB.OE7B, [1] TOERB.OE7A, [0] TOERB.OE6B
0xC1A0E MTU
  [6] TOCR1B.PSYE, [3] TOCR1B.TOCL, [2] TOCR1B.TOCS, [1] TOCR1B.OLSN, [0] TOCR1B.OLSP
0xC1A0F MTU
  [7:6] TOCR2B.BF, [5] TOCR2B.OLS3N, [4] TOCR2B.OLS3P, [3] TOCR2B.OLS2N, [2] TOCR2B.OLS2P, [1] TOCR2B.OLS1N, [0] TOCR2B.OLS1P
0xC1A2C MTU6
  [7] TSR.TCFD
0xC1A2D MTU7
  [7] TSR.TCFD
0xC1A30 MTU
  [7] TITCR1B.T6AEN, [6:4] TITCR1B.T6ACOR, [3] TITCR1B.T7VEN, [2:0] TITCR1B.T7VCOR
0xC1A31 MTU
  [6:4] TITCNT1B.T6ACNT, [2:0] TITCNT1B.T7VCNT
0xC1A32 MTU
  [1:0] TBTERB.BTE
0xC1A34 MTU
  [0] TDERB.TDER
0xC1A36 MTU
  [5] TOLBRB.OLS3N, [4] TOLBRB.OLS3P, [3] TOLBRB.OLS2N, [2] TOLBRB.OLS2P, [1] TOLBRB.OLS1N, [0] TOLBRB.OLS1P
0xC1A38 MTU6
  [1] TBTM.TTSB, [0] TBTM.TTSA
0xC1A39 MTU7
  [1] TBTM.TTSB, [0] TBTM.TTSA
0xC1A3A MTU
  [0] TITMRB.TITM
0xC1A3B MTU
  [2:0] TITCR2B.TRG7COR
0xC1A3C MTU
  [2:0] TITCNT2B.TRG7CNT
0xC1A40 MTU7 16-bit
  [15:14] TADCR.BF, [7] TADCR.UT7AE, [6] TADCR.DT7AE, [5] TADCR.UT7BE, [4] TADCR.DT7BE, [3] TADCR.ITA6AE, [2] TADCR.ITA7VE, [1] TADCR.ITB6AE, [0] TADCR.ITB7VE
0xC1A4C MTU6
  [2:0] TCR2.TPSC2
0xC1A4D MTU7
  [2:0] TCR2.TPSC2
0xC1A50 MTU6
  [7] TSYCR.CE0A, [6] TSYCR.CE0B, [5] TSYCR.CE0C, [4] TSYCR.CE0D, [3] TSYCR.CE1A, [2] TSYCR.CE1B, [1] TSYCR.CE2A, [0] TSYCR.CE2B
0xC1A60 MTU
  [7] TWCRB.CCE, [1] TWCRB.SCC, [0] TWCRB.WRE
0xC1A70 MTU
  [0] TMDR2B.DRS
0xC1A80 MTU
  [7] TSTRB.CST7, [6] TSTRB.CST6
0xC1A81 MTU
  [7] TSYRB.SYNC7, [6] TSYRB.SYNC6
0xC1A84 MTU
  [0] TRWERB.RWE
0xC1A93 MTU6
  [5:4] NFCR6.NFCS, [3] NFCR6.NFDEN, [2] NFCR6.NFCEN, [1] NFCR6.NFBEN, [0] NFCR6.NFAEN
0xC1A94 MTU7
  [5:4] NFCR7.NFCS, [3] NFCR7.NFDEN, [2] NFCR7.NFCEN, [1] NFCR7.NFBEN, [0] NFCR7.NFAEN
0xC1A95 MTU5
  [5:4] NFCR5.NFCS, [2] NFCR5.NFWEN, [1] NFCR5.NFVEN, [0] NFCR5.NFUEN
0xC1C84 MTU5
  [1:0] TCRU.TPSC
0xC1C85 MTU5
  [4:3] TCR2U.CKEG, [2:0] TCR2U.TPSC2
0xC1C86 MTU5
  [4:0] TIORU.IOC
0xC1C94 MTU5
  [1:0] TCRV.TPSC
0xC1C95 MTU5
  [4:3] TCR2V.CKEG, [2:0] TCR2V.TPSC2
0xC1C96 MTU5
  [4:0] TIORV.IOC
0xC1CA4 MTU5
  [1:0] TCRW.TPSC
0xC1CA5 MTU5
  [4:3] TCR2W.CKEG, [2:0] TCR2W.TPSC2
0xC1CA6 MTU5
  [4:0] TIORW.IOC
0xC1CB2 MTU5
  [2] TIER.TGIE5U, [1] TIER.TGIE5V, [0] TIER.TGIE5W
0xC1CB4 MTU5
  [2] TSTR.CSTU5, [1] TSTR.CSTV5, [0] TSTR.CSTW5
0xC1CB6 MTU5
  [2] TCNTCMPCLR.CMPCLR5U, [1] TCNTCMPCLR.CMPCLR5V, [0] TCNTCMPCLR.CMPCLR5W
0xC2000 GPT 16-bit
  [n] GTSTR.CST{n} (n=0..3)
0xC2002 GPT 16-bit
  [2n+9:2n+8] NFCR.NFCS{n} (n=0..3), [2n+1] NFCR.NFB{n}EN (n=0..3), [2n] NFCR.NFA{n}EN (n=0..3)
0xC2004 GPT 16-bit
  [2n+9:2n+8] GTHSCR.CPHW{n} (n=0..3), [2n+1:2n] GTHSCR.CSHW{n} (n=0..3)
0xC2006 GPT 16-bit
  [n+8] GTHCCR.CCSW{n} (n=0..3), [2n+1:2n] GTHCCR.CCHW{n} (n=0..3)
0xC2008 GPT 16-bit
  [4n+3:4n] GTHSSR.CSHSL{n} (n=0..3)
0xC200A GPT 16-bit
  [4n+3:4n] GTHPSR.CSHPL{n} (n=0..3)
0xC200C GPT 16-bit
  [n] GTWP.WP{n} (n=0..3)
0xC200E GPT 16-bit
  [4n+1:4n] GTSYNC.SYNC{n} (n=0..3)
0xC2010 GPT 16-bit
  [15] GTETINT.GTETRGEN, [14:13] GTETINT.GTENFCS, [1] GTETINT.ETINEN, [0] GTETINT.ETIPEN
0xC2014 GPT 16-bit
  [n-18] GTBDR.BD{n} (n=30..33), [n-12] GTBDR.BD{n} (n=20..23), [n-6] GTBDR.BD{n} (n=10..13), [n] GTBDR.BD{n:02} (n=0..3)
0xC2018 GPT 16-bit
  [n] GTSWP.SWP{n} (n=0..3)
{0xC2100+0x80*i} GPT{i} 16-bit (i=0..3)
  [15] GTIOR.OBHLD, [14] GTIOR.OBDFLT, [13:8] GTIOR.GTIOB, [7] GTIOR.OAHLD, [6] GTIOR.OADFLT, [5:0] GTIOR.GTIOA
{0xC2102+0x80*i} GPT{i} 16-bit (i=0..3)
  [15] GTINTAD.ADTRBDEN, [14] GTINTAD.ADTRBUEN, [13] GTINTAD.ADTRADEN, [12] GTINTAD.ADTRAUEN, [11] GTINTAD.EINT, [7:6] GTINTAD.GTINTPR, [5] GTINTAD.GTINTF, [4] GTINTAD.GTINTE, [3] GTINTAD.GTINTD, [2] GTINTAD.GTINTC, [1] GTINTAD.GTINTB, [0] GTINTAD.GTINTA
{0xC2104+0x80*i} GPT{i} 16-bit (i=0..3)
  [13:12] GTCR.CCLR, [9:8] GTCR.TPCS, [2:0] GTCR.MD
{0xC2106+0x80*i} GPT{i} 16-bit (i=0..3)
  [14] GTBER.ADTDB, [13:12] GTBER.ADTTB, [10] GTBER.ADTDA, [9:8] GTBER.ADTTA, [6] GTBER.CCRSWT, [5:4] GTBER.PR, [3:2] GTBER.CCRB, [1:0] GTBER.CCRA
{0xC2108+0x80*i} GPT{i} 16-bit (i=0..3)
  [1] GTUDC.UDF, [0] GTUDC.UD
{0xC210A+0x80*i} GPT{i} 16-bit (i=0..3)
  [14] GTITC.ADTBL, [12] GTITC.ADTAL, [10:8] GTITC.IVTT, [7:6] GTITC.IVTC, [5] GTITC.ITLF, [4] GTITC.ITLE, [3] GTITC.ITLD, [2] GTITC.ITLC, [1] GTITC.ITLB, [0] GTITC.ITLA
{0xC210C+0x80*i} GPT{i} 16-bit (i=0..3)
  [15] GTST.TUCF, [11] GTST.DTEF, [10:8] GTST.ITCNT
{0xC2134+0x80*i} GPT{i} 16-bit (i=0..3)
  [15] GTONCR.OBE, [14] GTONCR.OAE, [12] GTONCR.SWN, [8] GTONCR.NFV, [7:4] GTONCR.NFS, [3] GTONCR.NVB, [2] GTONCR.NVA, [1] GTONCR.NEB, [0] GTONCR.NEA
{0xC2136+0x80*i} GPT{i} 16-bit (i=0..3)
  [8] GTDTCR.TDFER, [5] GTDTCR.TDBDE, [4] GTDTCR.TDBUE, [0] GTDTCR.TDE
{0xC2140+0x80*i} GPT{i} 16-bit (i=0..3)
  [1:0] GTSOS.SOS
{0xC2142+0x80*i} GPT{i} 16-bit (i=0..3)
  [0] GTSOTR.SOTR
0xC4000 EPTPC 32-bit
  [n+16] MIESR.CYC{n} (n=0..5), [3] MIESR.PRC, [2] MIESR.SY1, [1] MIESR.SY0, [0] MIESR.ST
0xC4004 EPTPC 32-bit
  [n+16] MIEIPR.CYC{n} (n=0..5), [3] MIEIPR.PR, [2] MIEIPR.SY1, [1] MIEIPR.SY0, [0] MIEIPR.ST
0xC4010 EPTPC 32-bit
  [24] ELIPPR.PLSN, [16] ELIPPR.PLSP, [n+8] ELIPPR.CYCN{n} (n=0..5), [n] ELIPPR.CYCP{n} (n=0..5)
0xC4014 EPTPC 32-bit
  [24] ELIPACR.PLSN, [16] ELIPACR.PLSP, [n+8] ELIPACR.CYCN{n} (n=0..5), [n] ELIPACR.CYCP{n} (n=0..5)
0xC4040 EPTPC 32-bit
  [4] STSR.W10D, [3] STSR.SYNTOUT, [1] STSR.SYNCOUT, [0] STSR.SYNC
0xC4044 EPTPC 32-bit
  [4] STIPR.W10D, [3] STIPR.SYNTOUT, [1] STIPR.SYNCOUT, [0] STIPR.SYNC
0xC4050 EPTPC 32-bit
  [1:0] STCFR.STCF
0xC4054 EPTPC 32-bit
  [29] STMR.ALEN1, [28] STMR.ALEN0, [23:20] STMR.DVTH, [19:16] STMR.SYTH, [15] STMR.W10S, [13] STMR.CMOD, [7:0] STMR.WINT
0xC4060 EPTPC 32-bit
  [n] IPTSELR.IPTSEL{n} (n=0..5)
0xC4064 EPTPC 32-bit
  [n] MITSELR.MINTEN{n} (n=0..5)
0xC4068 EPTPC 32-bit
  [n] ELTSELR.ELTDIS{n} (n=0..5)
0xC406C EPTPC 32-bit
  [0] STCHSELR.SYSEL
0xC4080 EPTPC 32-bit
  [0] SYNSTARTR.STR
0xC4084 EPTPC 32-bit
  [0] LCIVLDR.LOAD
0xC40B0 EPTPC 32-bit
  [15:0] LCIVRU.VALU
0xC4124 EPTPC 32-bit
  [0] GETW10R.GW10
0xC4128 EPTPC 32-bit
  [30:0] PLIMITRU.LMTU
0xC4134 EPTPC 32-bit
  [30:0] MLIMITRU.LMTU
0xC4140 EPTPC 32-bit
  [0] GETINFOR.INFO
0xC4170 EPTPC 32-bit
  [15:0] LCCVRU.CNTU
0xC4308 EPTPC 32-bit
  [29:0] TMCYCR0.CYC
0xC430C EPTPC 32-bit
  [28:0] TMPLSR0.WTH
0xC4318 EPTPC 32-bit
  [29:0] TMCYCR1.CYC
0xC431C EPTPC 32-bit
  [28:0] TMPLSR1.WTH
0xC4328 EPTPC 32-bit
  [29:0] TMCYCR2.CYC
0xC432C EPTPC 32-bit
  [28:0] TMPLSR2.WTH
0xC4338 EPTPC 32-bit
  [29:0] TMCYCR3.CYC
0xC433C EPTPC 32-bit
  [28:0] TMPLSR3.WTH
0xC4348 EPTPC 32-bit
  [29:0] TMCYCR4.CYC
0xC434C EPTPC 32-bit
  [28:0] TMPLSR4.WTH
0xC4358 EPTPC 32-bit
  [29:0] TMCYCR5.CYC
0xC435C EPTPC 32-bit
  [28:0] TMPLSR5.WTH
0xC437C EPTPC 32-bit
  [n] TMSTARTR.EN{n} (n=0..5)
0xC4400 EPTPC 32-bit
  [29] PRSR.URE1, [28] PRSR.URE0, [8] PRSR.MACE, [n] PRSR.OVRE{n} (n=0..3)
0xC4404 EPTPC 32-bit
  [29] PRIPR.URE1, [28] PRIPR.URE0, [8] PRIPR.MACE, [n] PRIPR.OVRE{n} (n=0..3)
0xC4410 EPTPC 32-bit
  [23:0] PRMACRU0.MACU
0xC4414 EPTPC 32-bit
  [23:0] PRMACRL0.MACL
0xC4418 EPTPC 32-bit
  [23:0] PRMACRU1.MACU
0xC441C EPTPC 32-bit
  [23:0] PRMACRL1.MACL
0xC4420 EPTPC 32-bit
  [1:0] TRNDISR.TDIS
0xC4430 EPTPC 32-bit
  [9] TRNMR.FWD1, [8] TRNMR.FWD0, [0] TRNMR.MOD
0xC4434 EPTPC 32-bit
  [10:0] TRNCTTDR.THVAL
0xC4800 EPTPC0 32-bit
  [17] SYSR.GENDN, [16] SYSR.RESDN, [14] SYSR.INFABT, [12] SYSR.RECLP, [6] SYSR.DRQOVR, [5] SYSR.INTDEV, [4] SYSR.DRPTO, [2] SYSR.MPDUD, [1] SYSR.INTCHG, [0] SYSR.OFMUD
0xC4804 EPTPC0 32-bit
  [17] SYIPR.GENDN, [16] SYIPR.RESDN, [14] SYIPR.INFABT, [12] SYIPR.RECLP, [6] SYIPR.DRQOVR, [5] SYIPR.INTDEV, [4] SYIPR.DRPTO, [2] SYIPR.MPDUD, [1] SYIPR.INTCHG, [0] SYIPR.OFMUD
0xC4810 EPTPC0 32-bit
  [23:0] SYMACRU.MACU
0xC4814 EPTPC0 32-bit
  [23:0] SYMACRL.MACL
0xC4840 EPTPC0 32-bit
  [7:4] SYSPVRR.TRSP, [3:0] SYSPVRR.VER
0xC4844 EPTPC0 32-bit
  [7:0] SYDOMR.DNUM
0xC4850 EPTPC0 32-bit
  [n] ANFR.FLAG{n} (n=0..15)
0xC4854 EPTPC0 32-bit
  [n] SYNFR.FLAG{n} (n=0..15)
0xC4858 EPTPC0 32-bit
  [n] DYRQFR.FLAG{n} (n=0..15)
0xC485C EPTPC0 32-bit
  [n] DYRPFR.FLAG{n} (n=0..15)
0xC4868 EPTPC0 32-bit
  [15:0] SYPNUMR.PNUM
0xC4880 EPTPC0 32-bit
  [2] SYRVLDR.ANUP, [1] SYRVLDR.STUP, [0] SYRVLDR.BMUP
0xC4890 EPTPC0 32-bit
  [30:28] SYRFL1R.PDFUP, [26:24] SYRFL1R.PDRP, [22:20] SYRFL1R.PDRQ, [18:16] SYRFL1R.DRP, [14:12] SYRFL1R.DRQ, [10:8] SYRFL1R.FUP, [6:4] SYRFL1R.SYNC, [1:0] SYRFL1R.ANCE
0xC4894 EPTPC0 32-bit
  [29:28] SYRFL2R.ILL, [5:4] SYRFL2R.SIG, [1:0] SYRFL2R.MAN
0xC4898 EPTPC0 32-bit
  [12] SYTRENR.PDRQ, [8] SYTRENR.DRQ, [4] SYTRENR.SYNC, [0] SYTRENR.ANCE
0xC48A8 EPTPC0 32-bit
  [15:0] MTPID.PNUM
0xC48C0 EPTPC0 32-bit
  [23:16] SYTLIR.DREQ, [15:8] SYTLIR.SYNC, [7:0] SYTLIR.ANCE
0xC48C4 EPTPC0 32-bit
  [23:16] SYRLIR.DRESP, [15:8] SYRLIR.SYNC, [7:0] SYRLIR.ANCE
0xC48E0 EPTPC0 32-bit
  [23:16] GMPR.GMPR1, [7:0] GMPR.GMPR2
0xC48F0 EPTPC0 32-bit
  [31:16] CUOTSR.CUTO, [7:0] CUOTSR.TSRC
0xC48F4 EPTPC0 32-bit
  [15:0] SRR.SRMV
0xC4900 EPTPC0 32-bit
  [23:0] PPMACRU.MACU
0xC4904 EPTPC0 32-bit
  [23:0] PPMACRL.MACL
0xC4908 EPTPC0 32-bit
  [23:0] PDMACRU.MACU
0xC490C EPTPC0 32-bit
  [23:0] PDMACRL.MACL
0xC4910 EPTPC0 32-bit
  [15:0] PETYPER.TYPE
0xC4928 EPTPC0 32-bit
  [7:0] PETOSR.EVTO
0xC492C EPTPC0 32-bit
  [7:0] PGTOSR.GETO
0xC4930 EPTPC0 32-bit
  [7:0] PPTTLR.PRTL
0xC4934 EPTPC0 32-bit
  [7:0] PDTTLR.PDTL
0xC4938 EPTPC0 32-bit
  [15:0] PEUDPR.EVUPT
0xC493C EPTPC0 32-bit
  [15:0] PGUDPR.GEUPT
0xC4940 EPTPC0 32-bit
  [16] FFLTR.EXTPRM, [2] FFLTR.ENB, [1] FFLTR.PRT, [0] FFLTR.SEL
0xC4960 EPTPC0 32-bit
  [23:0] FMAC0RU.MACU
0xC4964 EPTPC0 32-bit
  [23:0] FMAC0RL.MACL
0xC4968 EPTPC0 32-bit
  [23:0] FMAC1RU.MACU
0xC496C EPTPC0 32-bit
  [23:0] FMAC1RL.MACL
0xC49C0 EPTPC0 32-bit
  [15:0] DASYMRU.ASYMU
0xC49C8 EPTPC0 32-bit
  [31:16] TSLATR.INGP, [15:0] TSLATR.EGP
0xC49CC EPTPC0 32-bit
  [20] SYCONFR.TCMOD, [16] SYCONFR.FILDIS, [12] SYCONFR.SBDIS, [7:0] SYCONFR.TCYC
0xC49D0 EPTPC0 32-bit
  [1] SYFORMR.FORM1, [0] SYFORMR.FORM0
0xC4C00 EPTPC1 32-bit
  fields as EPTPC0
0xC4C04 EPTPC1 32-bit
  [17] SYIPR.GENDN, [16] SYIPR.RESDN, [14] SYIPR.INFABT, [12] SYIPR.RECLP, [6] SYIPR.DRQOVR, [5] SYIPR.INTDEV, [4] SYIPR.DRPTO, [2] SYIPR.MPDUD, [1] SYIPR.INTCHG, [0] SYIPR.OFMUD
0xC4C10 EPTPC1 32-bit
  [23:0] SYMACRU.MACU
0xC4C14 EPTPC1 32-bit
  [23:0] SYMACRL.MACL
0xC4C40 EPTPC1 32-bit
  [7:4] SYSPVRR.TRSP, [3:0] SYSPVRR.VER
0xC4C44 EPTPC1 32-bit
  [7:0] SYDOMR.DNUM
0xC4C50 EPTPC1 32-bit
  [n] ANFR.FLAG{n} (n=0..15)
0xC4C54 EPTPC1 32-bit
  [n] SYNFR.FLAG{n} (n=0..15)
0xC4C58 EPTPC1 32-bit
  [n] DYRQFR.FLAG{n} (n=0..15)
0xC4C5C EPTPC1 32-bit
  [n] DYRPFR.FLAG{n} (n=0..15)
0xC4C68 EPTPC1 32-bit
  [15:0] SYPNUMR.PNUM
0xC4C80 EPTPC1 32-bit
  [2] SYRVLDR.ANUP, [1] SYRVLDR.STUP, [0] SYRVLDR.BMUP
0xC4C90 EPTPC1 32-bit
  [30:28] SYRFL1R.PDFUP, [26:24] SYRFL1R.PDRP, [22:20] SYRFL1R.PDRQ, [18:16] SYRFL1R.DRP, [14:12] SYRFL1R.DRQ, [10:8] SYRFL1R.FUP, [6:4] SYRFL1R.SYNC, [1:0] SYRFL1R.ANCE
0xC4C94 EPTPC1 32-bit
  [29:28] SYRFL2R.ILL, [5:4] SYRFL2R.SIG, [1:0] SYRFL2R.MAN
0xC4C98 EPTPC1 32-bit
  [12] SYTRENR.PDRQ, [8] SYTRENR.DRQ, [4] SYTRENR.SYNC, [0] SYTRENR.ANCE
0xC4CA8 EPTPC1 32-bit
  [15:0] MTPID.PNUM
0xC4CC0 EPTPC1 32-bit
  [23:16] SYTLIR.DREQ, [15:8] SYTLIR.SYNC, [7:0] SYTLIR.ANCE
0xC4CC4 EPTPC1 32-bit
  [23:16] SYRLIR.DRESP, [15:8] SYRLIR.SYNC, [7:0] SYRLIR.ANCE
0xC4CE0 EPTPC1 32-bit
  [23:16] GMPR.GMPR1, [7:0] GMPR.GMPR2
0xC4CF0 EPTPC1 32-bit
  [31:16] CUOTSR.CUTO, [7:0] CUOTSR.TSRC
0xC4CF4 EPTPC1 32-bit
  [15:0] SRR.SRMV
0xC4D00 EPTPC1 32-bit
  [23:0] PPMACRU.MACU
0xC4D04 EPTPC1 32-bit
  [23:0] PPMACRL.MACL
0xC4D08 EPTPC1 32-bit
  [23:0] PDMACRU.MACU
0xC4D0C EPTPC1 32-bit
  [23:0] PDMACRL.MACL
0xC4D10 EPTPC1 32-bit
  [15:0] PETYPER.TYPE
0xC4D28 EPTPC1 32-bit
  [7:0] PETOSR.EVTO
0xC4D2C EPTPC1 32-bit
  [7:0] PGTOSR.GETO
0xC4D30 EPTPC1 32-bit
  [7:0] PPTTLR.PRTL
0xC4D34 EPTPC1 32-bit
  [7:0] PDTTLR.PDTL
0xC4D38 EPTPC1 32-bit
  [15:0] PEUDPR.EVUPT
0xC4D3C EPTPC1 32-bit
  [15:0] PGUDPR.GEUPT
0xC4D40 EPTPC1 32-bit
  [16] FFLTR.EXTPRM, [2] FFLTR.ENB, [1] FFLTR.PRT, [0] FFLTR.SEL
0xC4D60 EPTPC1 32-bit
  [23:0] FMAC0RU.MACU
0xC4D64 EPTPC1 32-bit
  [23:0] FMAC0RL.MACL
0xC4D68 EPTPC1 32-bit
  [23:0] FMAC1RU.MACU
0xC4D6C EPTPC1 32-bit
  [23:0] FMAC1RL.MACL
0xC4DC0 EPTPC1 32-bit
  [15:0] DASYMRU.ASYMU
0xC4DC8 EPTPC1 32-bit
  [31:16] TSLATR.INGP, [15:0] TSLATR.EGP
0xC4DCC EPTPC1 32-bit
  [20] SYCONFR.TCMOD, [16] SYCONFR.FILDIS, [12] SYCONFR.SBDIS, [7:0] SYCONFR.TCYC
0xC4DD0 EPTPC1 32-bit
  [1] SYFORMR.FORM1, [0] SYFORMR.FORM0
{0xCFF00+0x20*i} SCIFA{i} 16-bit (i=8..11)
  [7] SMR.CM, [6] SMR.CHR, [5] SMR.PE, [4] SMR.PM, [3] SMR.STOP, [1:0] SMR.CKS
{0xCFF04+0x20*i} SCIFA{i} 16-bit (i=8..11)
  [7] SCR.TIE, [6] SCR.RIE, [5] SCR.TE, [4] SCR.RE, [3] SCR.REIE, [2] SCR.TEIE, [1:0] SCR.CKE
{0xCFF08+0x20*i} SCIFA{i} 16-bit (i=8..11)
  [7] FSR.ER, [6] FSR.TEND, [5] FSR.TDFE, [4] FSR.BRK, [3] FSR.FER, [2] FSR.PER, [1] FSR.RDF, [0] FSR.DR
{0xCFF0C+0x20*i} SCIFA{i} 16-bit (i=8..11)
  [10:8] FCR.RSTRG, [7:6] FCR.RTRG, [5:4] FCR.TTRG, [3] FCR.MCE, [2] FCR.TFRST, [1] FCR.RFRST, [0] FCR.LOOP
{0xCFF0E+0x20*i} SCIFA{i} 16-bit (i=8..11)
  [12:8] FDR.T, [4:0] FDR.R
{0xCFF10+0x20*i} SCIFA{i} 16-bit (i=8..11)
  [7] SPTR.RTS2IO, [6] SPTR.RTS2DT, [5] SPTR.CTS2IO, [4] SPTR.CTS2DT, [3] SPTR.SCKIO, [2] SPTR.SCKDT, [1] SPTR.SPB2IO, [0] SPTR.SPB2DT
{0xCFF12+0x20*i} SCIFA{i} 16-bit (i=8..11)
  [11:8] LSR.PER, [5:2] LSR.FER, [0] LSR.ORER
{0xCFF14+0x20*i} SCIFA{i} (i=8..11)
  [7] SEMR.BGDM, [5] SEMR.BRME, [4] SEMR.MDDRS, [3] SEMR.DIR, [2] SEMR.NFEN, [0] SEMR.ABCS0
{0xCFF16+0x20*i} SCIFA{i} 16-bit (i=8..11)
  [15] FTCR.RTRGS, [12:8] FTCR.RFTC, [7] FTCR.TTRGS, [4:0] FTCR.TFTC
0xD0100 RSPI0
  [7] SPCR.SPRIE, [6] SPCR.SPE, [5] SPCR.SPTIE, [4] SPCR.SPEIE, [3] SPCR.MSTR, [2] SPCR.MODFEN, [1] SPCR.TXMD, [0] SPCR.SPMS
0xD0101 RSPI0
  [n] SSLP.SSL{n}P (n=0..3)
0xD0102 RSPI0
  [5] SPPCR.MOIFE, [4] SPPCR.MOIFV, [1] SPPCR.SPLP2, [0] SPPCR.SPLP
0xD0103 RSPI0
  [7] SPSR.SPRF, [5] SPSR.SPTEF, [3] SPSR.PERF, [2] SPSR.MODF, [1] SPSR.IDLNF, [0] SPSR.OVRF
0xD0108 RSPI0
  [2:0] SPSCR.SPSLN
0xD0109 RSPI0
  [6:4] SPSSR.SPECM, [2:0] SPSSR.SPCP
0xD010B RSPI0
  [5] SPDCR.SPLW, [4] SPDCR.SPRDTD, [1:0] SPDCR.SPFC
0xD010C RSPI0
  [2:0] SPCKD.SCKDL
0xD010D RSPI0
  [2:0] SSLND.SLNDL
0xD010E RSPI0
  [2:0] SPND.SPNDL
0xD010F RSPI0
  [4] SPCR2.SCKASE, [3] SPCR2.PTE, [2] SPCR2.SPIIE, [1] SPCR2.SPOE, [0] SPCR2.SPPE
0xD0110 RSPI0 16-bit
  [15] SPCMD0.SCKDEN, [14] SPCMD0.SLNDEN, [13] SPCMD0.SPNDEN, [12] SPCMD0.LSBF, [11:8] SPCMD0.SPB, [7] SPCMD0.SSLKP, [6:4] SPCMD0.SSLA, [3:2] SPCMD0.BRDV, [1] SPCMD0.CPOL, [0] SPCMD0.CPHA
0xD0112 RSPI0 16-bit
  [15] SPCMD1.SCKDEN, [14] SPCMD1.SLNDEN, [13] SPCMD1.SPNDEN, [12] SPCMD1.LSBF, [11:8] SPCMD1.SPB, [7] SPCMD1.SSLKP, [6:4] SPCMD1.SSLA, [3:2] SPCMD1.BRDV, [1] SPCMD1.CPOL, [0] SPCMD1.CPHA
0xD0114 RSPI0 16-bit
  [15] SPCMD2.SCKDEN, [14] SPCMD2.SLNDEN, [13] SPCMD2.SPNDEN, [12] SPCMD2.LSBF, [11:8] SPCMD2.SPB, [7] SPCMD2.SSLKP, [6:4] SPCMD2.SSLA, [3:2] SPCMD2.BRDV, [1] SPCMD2.CPOL, [0] SPCMD2.CPHA
0xD0116 RSPI0 16-bit
  [15] SPCMD3.SCKDEN, [14] SPCMD3.SLNDEN, [13] SPCMD3.SPNDEN, [12] SPCMD3.LSBF, [11:8] SPCMD3.SPB, [7] SPCMD3.SSLKP, [6:4] SPCMD3.SSLA, [3:2] SPCMD3.BRDV, [1] SPCMD3.CPOL, [0] SPCMD3.CPHA
0xD0118 RSPI0 16-bit
  [15] SPCMD4.SCKDEN, [14] SPCMD4.SLNDEN, [13] SPCMD4.SPNDEN, [12] SPCMD4.LSBF, [11:8] SPCMD4.SPB, [7] SPCMD4.SSLKP, [6:4] SPCMD4.SSLA, [3:2] SPCMD4.BRDV, [1] SPCMD4.CPOL, [0] SPCMD4.CPHA
0xD011A RSPI0 16-bit
  [15] SPCMD5.SCKDEN, [14] SPCMD5.SLNDEN, [13] SPCMD5.SPNDEN, [12] SPCMD5.LSBF, [11:8] SPCMD5.SPB, [7] SPCMD5.SSLKP, [6:4] SPCMD5.SSLA, [3:2] SPCMD5.BRDV, [1] SPCMD5.CPOL, [0] SPCMD5.CPHA
0xD011C RSPI0 16-bit
  [15] SPCMD6.SCKDEN, [14] SPCMD6.SLNDEN, [13] SPCMD6.SPNDEN, [12] SPCMD6.LSBF, [11:8] SPCMD6.SPB, [7] SPCMD6.SSLKP, [6:4] SPCMD6.SSLA, [3:2] SPCMD6.BRDV, [1] SPCMD6.CPOL, [0] SPCMD6.CPHA
0xD011E RSPI0 16-bit
  [15] SPCMD7.SCKDEN, [14] SPCMD7.SLNDEN, [13] SPCMD7.SPNDEN, [12] SPCMD7.LSBF, [11:8] SPCMD7.SPB, [7] SPCMD7.SSLKP, [6:4] SPCMD7.SSLA, [3:2] SPCMD7.BRDV, [1] SPCMD7.CPOL, [0] SPCMD7.CPHA
0xD0120 RSPI1
  fields as RSPI0
0xD0121 RSPI1
  [n] SSLP.SSL{n}P (n=0..3)
0xD0122 RSPI1
  [5] SPPCR.MOIFE, [4] SPPCR.MOIFV, [1] SPPCR.SPLP2, [0] SPPCR.SPLP
0xD0123 RSPI1
  [7] SPSR.SPRF, [5] SPSR.SPTEF, [3] SPSR.PERF, [2] SPSR.MODF, [1] SPSR.IDLNF, [0] SPSR.OVRF
0xD0128 RSPI1
  [2:0] SPSCR.SPSLN
0xD0129 RSPI1
  [6:4] SPSSR.SPECM, [2:0] SPSSR.SPCP
0xD012B RSPI1
  [5] SPDCR.SPLW, [4] SPDCR.SPRDTD, [1:0] SPDCR.SPFC
0xD012C RSPI1
  [2:0] SPCKD.SCKDL
0xD012D RSPI1
  [2:0] SSLND.SLNDL
0xD012E RSPI1
  [2:0] SPND.SPNDL
0xD012F RSPI1
  [4] SPCR2.SCKASE, [3] SPCR2.PTE, [2] SPCR2.SPIIE, [1] SPCR2.SPOE, [0] SPCR2.SPPE
0xD0130 RSPI1 16-bit
  [15] SPCMD0.SCKDEN, [14] SPCMD0.SLNDEN, [13] SPCMD0.SPNDEN, [12] SPCMD0.LSBF, [11:8] SPCMD0.SPB, [7] SPCMD0.SSLKP, [6:4] SPCMD0.SSLA, [3:2] SPCMD0.BRDV, [1] SPCMD0.CPOL, [0] SPCMD0.CPHA
0xD0132 RSPI1 16-bit
  [15] SPCMD1.SCKDEN, [14] SPCMD1.SLNDEN, [13] SPCMD1.SPNDEN, [12] SPCMD1.LSBF, [11:8] SPCMD1.SPB, [7] SPCMD1.SSLKP, [6:4] SPCMD1.SSLA, [3:2] SPCMD1.BRDV, [1] SPCMD1.CPOL, [0] SPCMD1.CPHA
0xD0134 RSPI1 16-bit
  [15] SPCMD2.SCKDEN, [14] SPCMD2.SLNDEN, [13] SPCMD2.SPNDEN, [12] SPCMD2.LSBF, [11:8] SPCMD2.SPB, [7] SPCMD2.SSLKP, [6:4] SPCMD2.SSLA, [3:2] SPCMD2.BRDV, [1] SPCMD2.CPOL, [0] SPCMD2.CPHA
0xD0136 RSPI1 16-bit
  [15] SPCMD3.SCKDEN, [14] SPCMD3.SLNDEN, [13] SPCMD3.SPNDEN, [12] SPCMD3.LSBF, [11:8] SPCMD3.SPB, [7] SPCMD3.SSLKP, [6:4] SPCMD3.SSLA, [3:2] SPCMD3.BRDV, [1] SPCMD3.CPOL, [0] SPCMD3.CPHA
0xD0138 RSPI1 16-bit
  [15] SPCMD4.SCKDEN, [14] SPCMD4.SLNDEN, [13] SPCMD4.SPNDEN, [12] SPCMD4.LSBF, [11:8] SPCMD4.SPB, [7] SPCMD4.SSLKP, [6:4] SPCMD4.SSLA, [3:2] SPCMD4.BRDV, [1] SPCMD4.CPOL, [0] SPCMD4.CPHA
0xD013A RSPI1 16-bit
  [15] SPCMD5.SCKDEN, [14] SPCMD5.SLNDEN, [13] SPCMD5.SPNDEN, [12] SPCMD5.LSBF, [11:8] SPCMD5.SPB, [7] SPCMD5.SSLKP, [6:4] SPCMD5.SSLA, [3:2] SPCMD5.BRDV, [1] SPCMD5.CPOL, [0] SPCMD5.CPHA
0xD013C RSPI1 16-bit
  [15] SPCMD6.SCKDEN, [14] SPCMD6.SLNDEN, [13] SPCMD6.SPNDEN, [12] SPCMD6.LSBF, [11:8] SPCMD6.SPB, [7] SPCMD6.SSLKP, [6:4] SPCMD6.SSLA, [3:2] SPCMD6.BRDV, [1] SPCMD6.CPOL, [0] SPCMD6.CPHA
0xD013E RSPI1 16-bit
  [15] SPCMD7.SCKDEN, [14] SPCMD7.SLNDEN, [13] SPCMD7.SPNDEN, [12] SPCMD7.LSBF, [11:8] SPCMD7.SPB, [7] SPCMD7.SSLKP, [6:4] SPCMD7.SSLA, [3:2] SPCMD7.BRDV, [1] SPCMD7.CPOL, [0] SPCMD7.CPHA
0xD0400 USBA 16-bit
  [8] SYSCFG.CNEN, [7] SYSCFG.HSE, [6] SYSCFG.DCFM, [5] SYSCFG.DRPD, [4] SYSCFG.DPRPU, [0] SYSCFG.USBE
0xD0402 USBA 16-bit
  [3:0] BUSWAIT.BWAIT
0xD0404 USBA 16-bit
  [15:14] SYSSTS0.OVCMON, [6] SYSSTS0.HTACT, [5] SYSSTS0.SOFEA, [2] SYSSTS0.IDMON, [1:0] SYSSTS0.LNST
0xD0406 USBA 16-bit
  [0] PLLSTA.PLLLOCK
0xD0408 USBA 16-bit
  [11] DVSTCTR0.HNPBTOA, [10] DVSTCTR0.EXICEN, [9] DVSTCTR0.VBUSEN, [8] DVSTCTR0.WKUP, [7] DVSTCTR0.RWUPE, [6] DVSTCTR0.USBRST, [5] DVSTCTR0.RESUME, [4] DVSTCTR0.UACT, [2:0] DVSTCTR0.RHST
0xD040C USBA 16-bit
  [3:0] TESTMODE.UTST
0xD0420 USBA 16-bit
  [15] CFIFOSEL.RCNT, [14] CFIFOSEL.REW, [11:10] CFIFOSEL.MBW, [8] CFIFOSEL.BIGEND, [5] CFIFOSEL.ISEL, [3:0] CFIFOSEL.CURPIPE
0xD0422 USBA 16-bit
  [15] CFIFOCTR.BVAL, [14] CFIFOCTR.BCLR, [13] CFIFOCTR.FRDY, [11:0] CFIFOCTR.DTLN
0xD0428 USBA 16-bit
  [15] D0FIFOSEL.RCNT, [14] D0FIFOSEL.REW, [13] D0FIFOSEL.DCLRM, [12] D0FIFOSEL.DREQE, [11:10] D0FIFOSEL.MBW, [8] D0FIFOSEL.BIGEND, [3:0] D0FIFOSEL.CURPIPE
0xD042A USBA 16-bit
  [15] D0FIFOCTR.BVAL, [14] D0FIFOCTR.BCLR, [13] D0FIFOCTR.FRDY, [11:0] D0FIFOCTR.DTLN
0xD042C USBA 16-bit
  [15] D1FIFOSEL.RCNT, [14] D1FIFOSEL.REW, [13] D1FIFOSEL.DCLRM, [12] D1FIFOSEL.DREQE, [11:10] D1FIFOSEL.MBW, [8] D1FIFOSEL.BIGEND, [3:0] D1FIFOSEL.CURPIPE
0xD042E USBA 16-bit
  [15] D1FIFOCTR.BVAL, [14] D1FIFOCTR.BCLR, [13] D1FIFOCTR.FRDY, [11:0] D1FIFOCTR.DTLN
0xD0430 USBA 16-bit
  [15] INTENB0.VBSE, [14] INTENB0.RSME, [13] INTENB0.SOFE, [12] INTENB0.DVSE, [11] INTENB0.CTRE, [10] INTENB0.BEMPE, [9] INTENB0.NRDYE, [8] INTENB0.BRDYE
0xD0432 USBA 16-bit
  [15] INTENB1.OVRCRE, [14] INTENB1.BCHGE, [12] INTENB1.DTCHE, [11] INTENB1.ATTCHE, [9] INTENB1.L1RSMENDE, [8] INTENB1.LPMENDE, [6] INTENB1.EOFERRE, [5] INTENB1.SIGNE, [4] INTENB1.SACKE, [0] INTENB1.PDDETINTE
0xD0436 USBA 16-bit
  [n] BRDYENB.PIPE{n}BRDYE (n=0..9)
0xD0438 USBA 16-bit
  [n] NRDYENB.PIPE{n}NRDYE (n=0..9)
0xD043A USBA 16-bit
  [n] BEMPENB.PIPE{n}BEMPE (n=0..9)
0xD043C USBA 16-bit
  [8] SOFCFG.TRNENSEL, [6] SOFCFG.BRDYM, [5] SOFCFG.INTL, [4] SOFCFG.EDGESTS
0xD043E USBA 16-bit
  [15] PHYSET.HSEB, [9:8] PHYSET.REPSEL, [5:4] PHYSET.CLKSEL, [3] PHYSET.CDPEN, [1] PHYSET.PLLRESET, [0] PHYSET.DIRPD
0xD0440 USBA 16-bit
  [15] INTSTS0.VBINT, [14] INTSTS0.RESM, [13] INTSTS0.SOFR, [12] INTSTS0.DVST, [11] INTSTS0.CTRT, [10] INTSTS0.BEMP, [9] INTSTS0.NRDY, [8] INTSTS0.BRDY, [7] INTSTS0.VBSTS, [6:4] INTSTS0.DVSQ, [3] INTSTS0.VALID, [2:0] INTSTS0.CTSQ
0xD0442 USBA 16-bit
  [15] INTSTS1.OVRCR, [14] INTSTS1.BCHG, [12] INTSTS1.DTCH, [11] INTSTS1.ATTCH, [9] INTSTS1.L1RSMEND, [8] INTSTS1.LPMEND, [6] INTSTS1.EOFERR, [5] INTSTS1.SIGN, [4] INTSTS1.SACK, [0] INTSTS1.PDDETINT
0xD0446 USBA 16-bit
  [9:0] BRDYSTS.PIPEBRDY
0xD0448 USBA 16-bit
  [9:0] NRDYSTS.PIPENRDY
0xD044A USBA 16-bit
  [9:0] BEMPSTS.PIPEBEMP
0xD044C USBA 16-bit
  [15] FRMNUM.OVRN, [14] FRMNUM.CRCE, [10:0] FRMNUM.FRNM
0xD044E USBA 16-bit
  [2:0] UFRMNUM.UFRNM
0xD0450 USBA 16-bit
  [6:0] USBADDR.USBADDR
0xD0454 USBA 16-bit
  [15:8] USBREQ.BREQUEST, [7:0] USBREQ.BMREQUESTTYPE
0xD045C USBA 16-bit
  [8] DCPCFG.CNTMD, [7] DCPCFG.SHTNAK, [4] DCPCFG.DIR
0xD045E USBA 16-bit
  [15:12] DCPMAXP.DEVSEL, [6:0] DCPMAXP.MXPS
0xD0460 USBA 16-bit
  [15] DCPCTR.BSTS, [14] DCPCTR.SUREQ, [11] DCPCTR.SUREQCLR, [8] DCPCTR.SQCLR, [7] DCPCTR.SQSET, [6] DCPCTR.SQMON, [5] DCPCTR.PBUSY, [2] DCPCTR.CCPL, [1:0] DCPCTR.PID
0xD0464 USBA 16-bit
  [3:0] PIPESEL.PIPESEL
0xD0468 USBA 16-bit
  [15:14] PIPECFG.TYPE, [10] PIPECFG.BFRE, [9] PIPECFG.DBLB, [8] PIPECFG.CNTMD, [7] PIPECFG.SHTNAK, [4] PIPECFG.DIR, [3:0] PIPECFG.EPNUM
0xD046A USBA 16-bit
  [14:10] PIPEBUF.BUFSIZE, [7:0] PIPEBUF.BUFNMB
0xD046C USBA 16-bit
  [15:12] PIPEMAXP.DEVSEL, [10:0] PIPEMAXP.MXPS
0xD046E USBA 16-bit
  [12] PIPEPERI.IFIS, [2:0] PIPEPERI.IITV
0xD0470 USBA 16-bit
  [15] PIPE1CTR.BSTS, [14] PIPE1CTR.INBUFM, [10] PIPE1CTR.ATREPM, [9] PIPE1CTR.ACLRM, [8] PIPE1CTR.SQCLR, [7] PIPE1CTR.SQSET, [6] PIPE1CTR.SQMON, [5] PIPE1CTR.PBUSY, [1:0] PIPE1CTR.PID
0xD0472 USBA 16-bit
  [15] PIPE2CTR.BSTS, [14] PIPE2CTR.INBUFM, [10] PIPE2CTR.ATREPM, [9] PIPE2CTR.ACLRM, [8] PIPE2CTR.SQCLR, [7] PIPE2CTR.SQSET, [6] PIPE2CTR.SQMON, [5] PIPE2CTR.PBUSY, [1:0] PIPE2CTR.PID
0xD0474 USBA 16-bit
  [15] PIPE3CTR.BSTS, [14] PIPE3CTR.INBUFM, [10] PIPE3CTR.ATREPM, [9] PIPE3CTR.ACLRM, [8] PIPE3CTR.SQCLR, [7] PIPE3CTR.SQSET, [6] PIPE3CTR.SQMON, [5] PIPE3CTR.PBUSY, [1:0] PIPE3CTR.PID
0xD0476 USBA 16-bit
  [15] PIPE4CTR.BSTS, [14] PIPE4CTR.INBUFM, [10] PIPE4CTR.ATREPM, [9] PIPE4CTR.ACLRM, [8] PIPE4CTR.SQCLR, [7] PIPE4CTR.SQSET, [6] PIPE4CTR.SQMON, [5] PIPE4CTR.PBUSY, [1:0] PIPE4CTR.PID
0xD0478 USBA 16-bit
  [15] PIPE5CTR.BSTS, [14] PIPE5CTR.INBUFM, [10] PIPE5CTR.ATREPM, [9] PIPE5CTR.ACLRM, [8] PIPE5CTR.SQCLR, [7] PIPE5CTR.SQSET, [6] PIPE5CTR.SQMON, [5] PIPE5CTR.PBUSY, [1:0] PIPE5CTR.PID
0xD047A USBA 16-bit
  [15] PIPE6CTR.BSTS, [14] PIPE6CTR.INBUFM, [10] PIPE6CTR.ATREPM, [9] PIPE6CTR.ACLRM, [8] PIPE6CTR.SQCLR, [7] PIPE6CTR.SQSET, [6] PIPE6CTR.SQMON, [5] PIPE6CTR.PBUSY, [1:0] PIPE6CTR.PID
0xD047C USBA 16-bit
  [15] PIPE7CTR.BSTS, [14] PIPE7CTR.INBUFM, [10] PIPE7CTR.ATREPM, [9] PIPE7CTR.ACLRM, [8] PIPE7CTR.SQCLR, [7] PIPE7CTR.SQSET, [6] PIPE7CTR.SQMON, [5] PIPE7CTR.PBUSY, [1:0] PIPE7CTR.PID
0xD047E USBA 16-bit
  [15] PIPE8CTR.BSTS, [14] PIPE8CTR.INBUFM, [10] PIPE8CTR.ATREPM, [9] PIPE8CTR.ACLRM, [8] PIPE8CTR.SQCLR, [7] PIPE8CTR.SQSET, [6] PIPE8CTR.SQMON, [5] PIPE8CTR.PBUSY, [1:0] PIPE8CTR.PID
0xD0480 USBA 16-bit
  [15] PIPE9CTR.BSTS, [14] PIPE9CTR.INBUFM, [10] PIPE9CTR.ATREPM, [9] PIPE9CTR.ACLRM, [8] PIPE9CTR.SQCLR, [7] PIPE9CTR.SQSET, [6] PIPE9CTR.SQMON, [5] PIPE9CTR.PBUSY, [1:0] PIPE9CTR.PID
0xD0490 USBA 16-bit
  [9] PIPE1TRE.TRENB, [8] PIPE1TRE.TRCLR
0xD0492 USBA 16-bit
  [15:0] PIPE1TRN.TRNCNT
0xD0494 USBA 16-bit
  [9] PIPE2TRE.TRENB, [8] PIPE2TRE.TRCLR
0xD0496 USBA 16-bit
  [15:0] PIPE2TRN.TRNCNT
0xD0498 USBA 16-bit
  [9] PIPE3TRE.TRENB, [8] PIPE3TRE.TRCLR
0xD049A USBA 16-bit
  [15:0] PIPE3TRN.TRNCNT
0xD049C USBA 16-bit
  [9] PIPE4TRE.TRENB, [8] PIPE4TRE.TRCLR
0xD049E USBA 16-bit
  [15:0] PIPE4TRN.TRNCNT
0xD04A0 USBA 16-bit
  [9] PIPE5TRE.TRENB, [8] PIPE5TRE.TRCLR
0xD04A2 USBA 16-bit
  [15:0] PIPE5TRN.TRNCNT
0xD04D0 USBA 16-bit
  [14:11] DEVADD0.UPPHUB, [10:8] DEVADD0.HUBPORT, [7:6] DEVADD0.USBSPD
0xD04D2 USBA 16-bit
  [14:11] DEVADD1.UPPHUB, [10:8] DEVADD1.HUBPORT, [7:6] DEVADD1.USBSPD
0xD04D4 USBA 16-bit
  [14:11] DEVADD2.UPPHUB, [10:8] DEVADD2.HUBPORT, [7:6] DEVADD2.USBSPD
0xD04D6 USBA 16-bit
  [14:11] DEVADD3.UPPHUB, [10:8] DEVADD3.HUBPORT, [7:6] DEVADD3.USBSPD
0xD04D8 USBA 16-bit
  [14:11] DEVADD4.UPPHUB, [10:8] DEVADD4.HUBPORT, [7:6] DEVADD4.USBSPD
0xD04DA USBA 16-bit
  [14:11] DEVADD5.UPPHUB, [10:8] DEVADD5.HUBPORT, [7:6] DEVADD5.USBSPD
0xD0500 USBA 16-bit
  [7] LPCTRL.HWUPM
0xD0502 USBA 16-bit
  [14] LPSTS.SUSPENDM
0xD0540 USBA 16-bit
  [9] BCCTRL.PDDETSTS, [8] BCCTRL.CHGDETSTS, [4] BCCTRL.VDMSRCE, [3] BCCTRL.IDPSINKE, [2] BCCTRL.VDPSRCE, [1] BCCTRL.IDMSINKE, [0] BCCTRL.IDPSRCE
0xD0544 USBA 16-bit
  [14] PL1CTRL1.L1EXTMD, [11:8] PL1CTRL1.HIRDTHR, [7:4] PL1CTRL1.DVSQ, [3] PL1CTRL1.L1NEGOMD, [2:1] PL1CTRL1.L1RESPMD, [0] PL1CTRL1.L1RESPEN
0xD0546 USBA 16-bit
  [12] PL1CTRL2.RWEMON, [11:8] PL1CTRL2.HIRDMON
0xD0548 USBA 16-bit
  [2:1] HL1CTRL1.L1STATUS, [0] HL1CTRL1.L1REQ
0xD054A USBA 16-bit
  [15] HL1CTRL2.BESL, [12] HL1CTRL2.L1RWE, [11:8] HL1CTRL2.HIRD, [3:0] HL1CTRL2.L1ADDR
0xD0560 USBA 32-bit
  [23] DPUSR0R.DVBSTSHM, [21] DPUSR0R.DOVCBHM, [20] DPUSR0R.DOVCAHM
0xD0564 USBA 32-bit
  [23] DPUSR1R.DVBSTSH, [21] DPUSR1R.DOVCBH, [20] DPUSR1R.DOVCAH, [7] DPUSR1R.DVBSTSHE, [5] DPUSR1R.DOVCBHE, [4] DPUSR1R.DOVCAHE
0x120064 SYSTEM 32-bit
  [2:0] MDE.MDE
0x120068 SYSTEM 32-bit
  [28] OFS0.WDTRSTIRQS, [27:26] OFS0.WDTRPSS, [25:24] OFS0.WDTRPES, [23:20] OFS0.WDTCKS, [19:18] OFS0.WDTTOPS, [17] OFS0.WDTSTRT, [14] OFS0.IWDTSLCSTP, [12] OFS0.IWDTRSTIRQS, [11:10] OFS0.IWDTRPSS, [9:8] OFS0.IWDTRPES, [7:4] OFS0.IWDTCKS, [3:2] OFS0.IWDTTOPS, [1] OFS0.IWDTSTRT
0x12006C SYSTEM 32-bit
  [8] OFS1.HOCOEN, [2] OFS1.LVDAS, [1:0] OFS1.VDSEL
0x7FE010 FLASH
  [7] FASTAT.CFAE, [4] FASTAT.CMDLK, [3] FASTAT.DFAE, [0] FASTAT.ECRCT
0x7FE014 FLASH
  [7] FAEINT.CFAEIE, [4] FAEINT.CMDLKIE, [3] FAEINT.DFAEIE, [0] FAEINT.ECRCTIE
0x7FE018 FLASH
  [0] FRDYIE.FRDYIE
0x7FE030 FLASH 32-bit
  [31:0] FSADDR.FSADDR
0x7FE034 FLASH 32-bit
  [31:0] FEADDR.FEADDR
0x7FE054 FLASH 16-bit
  [15:8] FCURAME.KEY, [1] FCURAME.FRAMTRAN, [0] FCURAME.FCRME
0x7FE080 FLASH 32-bit
  [15] FSTATR.FRDY, [14] FSTATR.ILGLERR, [13] FSTATR.ERSERR, [12] FSTATR.PRGERR, [11] FSTATR.SUSRDY, [10] FSTATR.DBFULL, [9] FSTATR.ERSSPD, [8] FSTATR.PRGSPD, [7] FSTATR.FCUERR, [6] FSTATR.FLWEERR, [1] FSTATR.FRDTCT, [0] FSTATR.FRCRCT
0x7FE084 FLASH 16-bit
  [15:8] FENTRYR.KEY, [7] FENTRYR.FENTRYD, [0] FENTRYR.FENTRYC
0x7FE088 FLASH 16-bit
  [15:8] FPROTR.KEY, [0] FPROTR.FPROTCN
0x7FE08C FLASH 16-bit
  [15:8] FSUINITR.KEY, [0] FSUINITR.SUINIT
0x7FE090 FLASH
  [0] FLKSTAT.FLOCKST
0x7FE0A0 FLASH 16-bit
  [15:8] FCMDR.CMDR, [7:0] FCMDR.PCMDR
0x7FE0C0 FLASH 16-bit
  [7:0] FPESTAT.PEERRST
0x7FE0D0 FLASH
  [0] FBCCNT.BCDIR
0x7FE0D4 FLASH
  [0] FBCSTAT.BCST
0x7FE0D8 FLASH 32-bit
  [18:0] FPSADDR.PSADR
0x7FE0E0 FLASH 16-bit
  [0] FCPSR.ESUSPMD
0x7FE0E4 FLASH 16-bit
  [15:8] FPCKAR.KEY, [7:0] FPCKAR.PCKA
